VERSION 5.7 ;
  NOWIREEXTENSIONATPIN ON ;
  DIVIDERCHAR "/" ;
  BUSBITCHARS "[]" ;
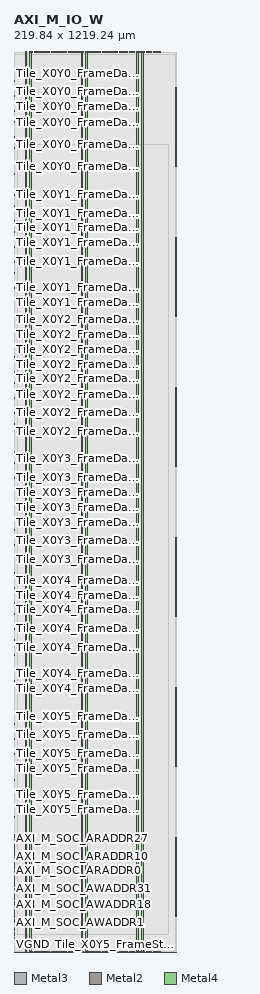
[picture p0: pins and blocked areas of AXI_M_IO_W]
MACRO AXI_M_IO_W
  CLASS BLOCK ;
  FOREIGN AXI_M_IO_W ;
  ORIGIN 0.000 0.000 ;
  SIZE 219.840 BY 1219.240 ;
  PIN AXI_M_SOC_ARADDR0
    DIRECTION OUTPUT ;
    USE SIGNAL ;
    ANTENNADIFFAREA 0.632400 ;
    PORT
      LAYER Metal3 ;
        RECT 0.000 120.340 0.400 120.740 ;
    END
  END AXI_M_SOC_ARADDR0
  PIN AXI_M_SOC_ARADDR1
    DIRECTION OUTPUT ;
    USE SIGNAL ;
    ANTENNADIFFAREA 0.632400 ;
    PORT
      LAYER Metal3 ;
        RECT 0.000 121.180 0.400 121.580 ;
    END
  END AXI_M_SOC_ARADDR1
  PIN AXI_M_SOC_ARADDR10
    DIRECTION OUTPUT ;
    USE SIGNAL ;
    ANTENNADIFFAREA 0.632400 ;
    PORT
      LAYER Metal3 ;
        RECT 0.000 128.740 0.400 129.140 ;
    END
  END AXI_M_SOC_ARADDR10
  PIN AXI_M_SOC_ARADDR11
    DIRECTION OUTPUT ;
    USE SIGNAL ;
    ANTENNADIFFAREA 0.632400 ;
    PORT
      LAYER Metal3 ;
        RECT 0.000 129.580 0.400 129.980 ;
    END
  END AXI_M_SOC_ARADDR11
  PIN AXI_M_SOC_ARADDR12
    DIRECTION OUTPUT ;
    USE SIGNAL ;
    ANTENNADIFFAREA 0.632400 ;
    PORT
      LAYER Metal3 ;
        RECT 0.000 130.420 0.400 130.820 ;
    END
  END AXI_M_SOC_ARADDR12
  PIN AXI_M_SOC_ARADDR13
    DIRECTION OUTPUT ;
    USE SIGNAL ;
    ANTENNADIFFAREA 0.632400 ;
    PORT
      LAYER Metal3 ;
        RECT 0.000 131.260 0.400 131.660 ;
    END
  END AXI_M_SOC_ARADDR13
  PIN AXI_M_SOC_ARADDR14
    DIRECTION OUTPUT ;
    USE SIGNAL ;
    ANTENNADIFFAREA 0.632400 ;
    PORT
      LAYER Metal3 ;
        RECT 0.000 132.100 0.400 132.500 ;
    END
  END AXI_M_SOC_ARADDR14
  PIN AXI_M_SOC_ARADDR15
    DIRECTION OUTPUT ;
    USE SIGNAL ;
    ANTENNADIFFAREA 0.632400 ;
    PORT
      LAYER Metal3 ;
        RECT 0.000 132.940 0.400 133.340 ;
    END
  END AXI_M_SOC_ARADDR15
  PIN AXI_M_SOC_ARADDR16
    DIRECTION OUTPUT ;
    USE SIGNAL ;
    ANTENNADIFFAREA 0.632400 ;
    PORT
      LAYER Metal3 ;
        RECT 0.000 133.780 0.400 134.180 ;
    END
  END AXI_M_SOC_ARADDR16
  PIN AXI_M_SOC_ARADDR17
    DIRECTION OUTPUT ;
    USE SIGNAL ;
    ANTENNADIFFAREA 0.632400 ;
    PORT
      LAYER Metal3 ;
        RECT 0.000 134.620 0.400 135.020 ;
    END
  END AXI_M_SOC_ARADDR17
  PIN AXI_M_SOC_ARADDR18
    DIRECTION OUTPUT ;
    USE SIGNAL ;
    ANTENNADIFFAREA 0.632400 ;
    PORT
      LAYER Metal3 ;
        RECT 0.000 135.460 0.400 135.860 ;
    END
  END AXI_M_SOC_ARADDR18
  PIN AXI_M_SOC_ARADDR19
    DIRECTION OUTPUT ;
    USE SIGNAL ;
    ANTENNADIFFAREA 0.632400 ;
    PORT
      LAYER Metal3 ;
        RECT 0.000 136.300 0.400 136.700 ;
    END
  END AXI_M_SOC_ARADDR19
  PIN AXI_M_SOC_ARADDR2
    DIRECTION OUTPUT ;
    USE SIGNAL ;
    ANTENNADIFFAREA 0.632400 ;
    PORT
      LAYER Metal3 ;
        RECT 0.000 122.020 0.400 122.420 ;
    END
  END AXI_M_SOC_ARADDR2
  PIN AXI_M_SOC_ARADDR20
    DIRECTION OUTPUT ;
    USE SIGNAL ;
    ANTENNADIFFAREA 0.632400 ;
    PORT
      LAYER Metal3 ;
        RECT 0.000 137.140 0.400 137.540 ;
    END
  END AXI_M_SOC_ARADDR20
  PIN AXI_M_SOC_ARADDR21
    DIRECTION OUTPUT ;
    USE SIGNAL ;
    ANTENNADIFFAREA 0.632400 ;
    PORT
      LAYER Metal3 ;
        RECT 0.000 137.980 0.400 138.380 ;
    END
  END AXI_M_SOC_ARADDR21
  PIN AXI_M_SOC_ARADDR22
    DIRECTION OUTPUT ;
    USE SIGNAL ;
    ANTENNADIFFAREA 0.632400 ;
    PORT
      LAYER Metal3 ;
        RECT 0.000 138.820 0.400 139.220 ;
    END
  END AXI_M_SOC_ARADDR22
  PIN AXI_M_SOC_ARADDR23
    DIRECTION OUTPUT ;
    USE SIGNAL ;
    ANTENNADIFFAREA 0.632400 ;
    PORT
      LAYER Metal3 ;
        RECT 0.000 139.660 0.400 140.060 ;
    END
  END AXI_M_SOC_ARADDR23
  PIN AXI_M_SOC_ARADDR24
    DIRECTION OUTPUT ;
    USE SIGNAL ;
    ANTENNADIFFAREA 0.632400 ;
    PORT
      LAYER Metal3 ;
        RECT 0.000 140.500 0.400 140.900 ;
    END
  END AXI_M_SOC_ARADDR24
  PIN AXI_M_SOC_ARADDR25
    DIRECTION OUTPUT ;
    USE SIGNAL ;
    ANTENNADIFFAREA 0.632400 ;
    PORT
      LAYER Metal3 ;
        RECT 0.000 141.340 0.400 141.740 ;
    END
  END AXI_M_SOC_ARADDR25
  PIN AXI_M_SOC_ARADDR26
    DIRECTION OUTPUT ;
    USE SIGNAL ;
    ANTENNADIFFAREA 0.632400 ;
    PORT
      LAYER Metal3 ;
        RECT 0.000 142.180 0.400 142.580 ;
    END
  END AXI_M_SOC_ARADDR26
  PIN AXI_M_SOC_ARADDR27
    DIRECTION OUTPUT ;
    USE SIGNAL ;
    ANTENNADIFFAREA 0.632400 ;
    PORT
      LAYER Metal3 ;
        RECT 0.000 143.020 0.400 143.420 ;
    END
  END AXI_M_SOC_ARADDR27
  PIN AXI_M_SOC_ARADDR28
    DIRECTION OUTPUT ;
    USE SIGNAL ;
    ANTENNADIFFAREA 0.632400 ;
    PORT
      LAYER Metal3 ;
        RECT 0.000 143.860 0.400 144.260 ;
    END
  END AXI_M_SOC_ARADDR28
  PIN AXI_M_SOC_ARADDR29
    DIRECTION OUTPUT ;
    USE SIGNAL ;
    ANTENNADIFFAREA 0.632400 ;
    PORT
      LAYER Metal3 ;
        RECT 0.000 144.700 0.400 145.100 ;
    END
  END AXI_M_SOC_ARADDR29
  PIN AXI_M_SOC_ARADDR3
    DIRECTION OUTPUT ;
    USE SIGNAL ;
    ANTENNADIFFAREA 0.632400 ;
    PORT
      LAYER Metal3 ;
        RECT 0.000 122.860 0.400 123.260 ;
    END
  END AXI_M_SOC_ARADDR3
  PIN AXI_M_SOC_ARADDR30
    DIRECTION OUTPUT ;
    USE SIGNAL ;
    ANTENNADIFFAREA 0.632400 ;
    PORT
      LAYER Metal3 ;
        RECT 0.000 145.540 0.400 145.940 ;
    END
  END AXI_M_SOC_ARADDR30
  PIN AXI_M_SOC_ARADDR31
    DIRECTION OUTPUT ;
    USE SIGNAL ;
    ANTENNADIFFAREA 0.632400 ;
    PORT
      LAYER Metal3 ;
        RECT 0.000 146.380 0.400 146.780 ;
    END
  END AXI_M_SOC_ARADDR31
  PIN AXI_M_SOC_ARADDR4
    DIRECTION OUTPUT ;
    USE SIGNAL ;
    ANTENNADIFFAREA 0.632400 ;
    PORT
      LAYER Metal3 ;
        RECT 0.000 123.700 0.400 124.100 ;
    END
  END AXI_M_SOC_ARADDR4
  PIN AXI_M_SOC_ARADDR5
    DIRECTION OUTPUT ;
    USE SIGNAL ;
    ANTENNADIFFAREA 0.632400 ;
    PORT
      LAYER Metal3 ;
        RECT 0.000 124.540 0.400 124.940 ;
    END
  END AXI_M_SOC_ARADDR5
  PIN AXI_M_SOC_ARADDR6
    DIRECTION OUTPUT ;
    USE SIGNAL ;
    ANTENNADIFFAREA 0.632400 ;
    PORT
      LAYER Metal3 ;
        RECT 0.000 125.380 0.400 125.780 ;
    END
  END AXI_M_SOC_ARADDR6
  PIN AXI_M_SOC_ARADDR7
    DIRECTION OUTPUT ;
    USE SIGNAL ;
    ANTENNADIFFAREA 0.632400 ;
    PORT
      LAYER Metal3 ;
        RECT 0.000 126.220 0.400 126.620 ;
    END
  END AXI_M_SOC_ARADDR7
  PIN AXI_M_SOC_ARADDR8
    DIRECTION OUTPUT ;
    USE SIGNAL ;
    ANTENNADIFFAREA 0.632400 ;
    PORT
      LAYER Metal3 ;
        RECT 0.000 127.060 0.400 127.460 ;
    END
  END AXI_M_SOC_ARADDR8
  PIN AXI_M_SOC_ARADDR9
    DIRECTION OUTPUT ;
    USE SIGNAL ;
    ANTENNADIFFAREA 0.632400 ;
    PORT
      LAYER Metal3 ;
        RECT 0.000 127.900 0.400 128.300 ;
    END
  END AXI_M_SOC_ARADDR9
  PIN AXI_M_SOC_ARBURST0
    DIRECTION OUTPUT ;
    USE SIGNAL ;
    ANTENNADIFFAREA 0.649200 ;
    PORT
      LAYER Metal3 ;
        RECT 0.000 156.460 0.400 156.860 ;
    END
  END AXI_M_SOC_ARBURST0
  PIN AXI_M_SOC_ARBURST1
    DIRECTION OUTPUT ;
    USE SIGNAL ;
    ANTENNADIFFAREA 0.662000 ;
    PORT
      LAYER Metal3 ;
        RECT 0.000 157.300 0.400 157.700 ;
    END
  END AXI_M_SOC_ARBURST1
  PIN AXI_M_SOC_ARLEN0
    DIRECTION OUTPUT ;
    USE SIGNAL ;
    ANTENNADIFFAREA 0.662000 ;
    PORT
      LAYER Metal3 ;
        RECT 0.000 147.220 0.400 147.620 ;
    END
  END AXI_M_SOC_ARLEN0
  PIN AXI_M_SOC_ARLEN1
    DIRECTION OUTPUT ;
    USE SIGNAL ;
    ANTENNADIFFAREA 1.135600 ;
    PORT
      LAYER Metal3 ;
        RECT 0.000 148.060 0.400 148.460 ;
    END
  END AXI_M_SOC_ARLEN1
  PIN AXI_M_SOC_ARLEN2
    DIRECTION OUTPUT ;
    USE SIGNAL ;
    ANTENNADIFFAREA 0.662000 ;
    PORT
      LAYER Metal3 ;
        RECT 0.000 148.900 0.400 149.300 ;
    END
  END AXI_M_SOC_ARLEN2
  PIN AXI_M_SOC_ARLEN3
    DIRECTION OUTPUT ;
    USE SIGNAL ;
    ANTENNADIFFAREA 1.135600 ;
    PORT
      LAYER Metal3 ;
        RECT 0.000 149.740 0.400 150.140 ;
    END
  END AXI_M_SOC_ARLEN3
  PIN AXI_M_SOC_ARLEN4
    DIRECTION OUTPUT ;
    USE SIGNAL ;
    ANTENNADIFFAREA 1.135600 ;
    PORT
      LAYER Metal3 ;
        RECT 0.000 150.580 0.400 150.980 ;
    END
  END AXI_M_SOC_ARLEN4
  PIN AXI_M_SOC_ARLEN5
    DIRECTION OUTPUT ;
    USE SIGNAL ;
    ANTENNADIFFAREA 1.135600 ;
    PORT
      LAYER Metal3 ;
        RECT 0.000 151.420 0.400 151.820 ;
    END
  END AXI_M_SOC_ARLEN5
  PIN AXI_M_SOC_ARLEN6
    DIRECTION OUTPUT ;
    USE SIGNAL ;
    ANTENNADIFFAREA 1.135600 ;
    PORT
      LAYER Metal3 ;
        RECT 0.000 152.260 0.400 152.660 ;
    END
  END AXI_M_SOC_ARLEN6
  PIN AXI_M_SOC_ARLEN7
    DIRECTION OUTPUT ;
    USE SIGNAL ;
    ANTENNADIFFAREA 1.135600 ;
    PORT
      LAYER Metal3 ;
        RECT 0.000 153.100 0.400 153.500 ;
    END
  END AXI_M_SOC_ARLEN7
  PIN AXI_M_SOC_ARREADY
    DIRECTION INPUT ;
    USE SIGNAL ;
    ANTENNAGATEAREA 1.279200 ;
    PORT
      LAYER Metal3 ;
        RECT 0.000 17.860 0.400 18.260 ;
    END
  END AXI_M_SOC_ARREADY
  PIN AXI_M_SOC_ARSIZE0
    DIRECTION OUTPUT ;
    USE SIGNAL ;
    ANTENNADIFFAREA 0.662000 ;
    PORT
      LAYER Metal3 ;
        RECT 0.000 153.940 0.400 154.340 ;
    END
  END AXI_M_SOC_ARSIZE0
  PIN AXI_M_SOC_ARSIZE1
    DIRECTION OUTPUT ;
    USE SIGNAL ;
    ANTENNADIFFAREA 0.649200 ;
    PORT
      LAYER Metal3 ;
        RECT 0.000 154.780 0.400 155.180 ;
    END
  END AXI_M_SOC_ARSIZE1
  PIN AXI_M_SOC_ARSIZE2
    DIRECTION OUTPUT ;
    USE SIGNAL ;
    ANTENNADIFFAREA 0.662000 ;
    PORT
      LAYER Metal3 ;
        RECT 0.000 155.620 0.400 156.020 ;
    END
  END AXI_M_SOC_ARSIZE2
  PIN AXI_M_SOC_ARVALID
    DIRECTION OUTPUT ;
    USE SIGNAL ;
    ANTENNADIFFAREA 0.632400 ;
    PORT
      LAYER Metal3 ;
        RECT 0.000 158.140 0.400 158.540 ;
    END
  END AXI_M_SOC_ARVALID
  PIN AXI_M_SOC_AWADDR0
    DIRECTION OUTPUT ;
    USE SIGNAL ;
    ANTENNADIFFAREA 0.632400 ;
    PORT
      LAYER Metal3 ;
        RECT 0.000 48.940 0.400 49.340 ;
    END
  END AXI_M_SOC_AWADDR0
  PIN AXI_M_SOC_AWADDR1
    DIRECTION OUTPUT ;
    USE SIGNAL ;
    ANTENNADIFFAREA 0.632400 ;
    PORT
      LAYER Metal3 ;
        RECT 0.000 49.780 0.400 50.180 ;
    END
  END AXI_M_SOC_AWADDR1
  PIN AXI_M_SOC_AWADDR10
    DIRECTION OUTPUT ;
    USE SIGNAL ;
    ANTENNADIFFAREA 0.632400 ;
    PORT
      LAYER Metal3 ;
        RECT 0.000 57.340 0.400 57.740 ;
    END
  END AXI_M_SOC_AWADDR10
  PIN AXI_M_SOC_AWADDR11
    DIRECTION OUTPUT ;
    USE SIGNAL ;
    ANTENNADIFFAREA 0.632400 ;
    PORT
      LAYER Metal3 ;
        RECT 0.000 58.180 0.400 58.580 ;
    END
  END AXI_M_SOC_AWADDR11
  PIN AXI_M_SOC_AWADDR12
    DIRECTION OUTPUT ;
    USE SIGNAL ;
    ANTENNADIFFAREA 0.632400 ;
    PORT
      LAYER Metal3 ;
        RECT 0.000 59.020 0.400 59.420 ;
    END
  END AXI_M_SOC_AWADDR12
  PIN AXI_M_SOC_AWADDR13
    DIRECTION OUTPUT ;
    USE SIGNAL ;
    ANTENNADIFFAREA 0.632400 ;
    PORT
      LAYER Metal3 ;
        RECT 0.000 59.860 0.400 60.260 ;
    END
  END AXI_M_SOC_AWADDR13
  PIN AXI_M_SOC_AWADDR14
    DIRECTION OUTPUT ;
    USE SIGNAL ;
    ANTENNADIFFAREA 0.632400 ;
    PORT
      LAYER Metal3 ;
        RECT 0.000 60.700 0.400 61.100 ;
    END
  END AXI_M_SOC_AWADDR14
  PIN AXI_M_SOC_AWADDR15
    DIRECTION OUTPUT ;
    USE SIGNAL ;
    ANTENNADIFFAREA 0.632400 ;
    PORT
      LAYER Metal3 ;
        RECT 0.000 61.540 0.400 61.940 ;
    END
  END AXI_M_SOC_AWADDR15
  PIN AXI_M_SOC_AWADDR16
    DIRECTION OUTPUT ;
    USE SIGNAL ;
    ANTENNADIFFAREA 0.632400 ;
    PORT
      LAYER Metal3 ;
        RECT 0.000 62.380 0.400 62.780 ;
    END
  END AXI_M_SOC_AWADDR16
  PIN AXI_M_SOC_AWADDR17
    DIRECTION OUTPUT ;
    USE SIGNAL ;
    ANTENNADIFFAREA 0.632400 ;
    PORT
      LAYER Metal3 ;
        RECT 0.000 63.220 0.400 63.620 ;
    END
  END AXI_M_SOC_AWADDR17
  PIN AXI_M_SOC_AWADDR18
    DIRECTION OUTPUT ;
    USE SIGNAL ;
    ANTENNADIFFAREA 0.632400 ;
    PORT
      LAYER Metal3 ;
        RECT 0.000 64.060 0.400 64.460 ;
    END
  END AXI_M_SOC_AWADDR18
  PIN AXI_M_SOC_AWADDR19
    DIRECTION OUTPUT ;
    USE SIGNAL ;
    ANTENNADIFFAREA 0.632400 ;
    PORT
      LAYER Metal3 ;
        RECT 0.000 64.900 0.400 65.300 ;
    END
  END AXI_M_SOC_AWADDR19
  PIN AXI_M_SOC_AWADDR2
    DIRECTION OUTPUT ;
    USE SIGNAL ;
    ANTENNADIFFAREA 0.632400 ;
    PORT
      LAYER Metal3 ;
        RECT 0.000 50.620 0.400 51.020 ;
    END
  END AXI_M_SOC_AWADDR2
  PIN AXI_M_SOC_AWADDR20
    DIRECTION OUTPUT ;
    USE SIGNAL ;
    ANTENNADIFFAREA 0.632400 ;
    PORT
      LAYER Metal3 ;
        RECT 0.000 65.740 0.400 66.140 ;
    END
  END AXI_M_SOC_AWADDR20
  PIN AXI_M_SOC_AWADDR21
    DIRECTION OUTPUT ;
    USE SIGNAL ;
    ANTENNADIFFAREA 0.632400 ;
    PORT
      LAYER Metal3 ;
        RECT 0.000 66.580 0.400 66.980 ;
    END
  END AXI_M_SOC_AWADDR21
  PIN AXI_M_SOC_AWADDR22
    DIRECTION OUTPUT ;
    USE SIGNAL ;
    ANTENNADIFFAREA 0.632400 ;
    PORT
      LAYER Metal3 ;
        RECT 0.000 67.420 0.400 67.820 ;
    END
  END AXI_M_SOC_AWADDR22
  PIN AXI_M_SOC_AWADDR23
    DIRECTION OUTPUT ;
    USE SIGNAL ;
    ANTENNADIFFAREA 0.632400 ;
    PORT
      LAYER Metal3 ;
        RECT 0.000 68.260 0.400 68.660 ;
    END
  END AXI_M_SOC_AWADDR23
  PIN AXI_M_SOC_AWADDR24
    DIRECTION OUTPUT ;
    USE SIGNAL ;
    ANTENNADIFFAREA 0.632400 ;
    PORT
      LAYER Metal3 ;
        RECT 0.000 69.100 0.400 69.500 ;
    END
  END AXI_M_SOC_AWADDR24
  PIN AXI_M_SOC_AWADDR25
    DIRECTION OUTPUT ;
    USE SIGNAL ;
    ANTENNADIFFAREA 0.632400 ;
    PORT
      LAYER Metal3 ;
        RECT 0.000 69.940 0.400 70.340 ;
    END
  END AXI_M_SOC_AWADDR25
  PIN AXI_M_SOC_AWADDR26
    DIRECTION OUTPUT ;
    USE SIGNAL ;
    ANTENNADIFFAREA 0.632400 ;
    PORT
      LAYER Metal3 ;
        RECT 0.000 70.780 0.400 71.180 ;
    END
  END AXI_M_SOC_AWADDR26
  PIN AXI_M_SOC_AWADDR27
    DIRECTION OUTPUT ;
    USE SIGNAL ;
    ANTENNADIFFAREA 0.632400 ;
    PORT
      LAYER Metal3 ;
        RECT 0.000 71.620 0.400 72.020 ;
    END
  END AXI_M_SOC_AWADDR27
  PIN AXI_M_SOC_AWADDR28
    DIRECTION OUTPUT ;
    USE SIGNAL ;
    ANTENNADIFFAREA 0.632400 ;
    PORT
      LAYER Metal3 ;
        RECT 0.000 72.460 0.400 72.860 ;
    END
  END AXI_M_SOC_AWADDR28
  PIN AXI_M_SOC_AWADDR29
    DIRECTION OUTPUT ;
    USE SIGNAL ;
    ANTENNADIFFAREA 0.632400 ;
    PORT
      LAYER Metal3 ;
        RECT 0.000 73.300 0.400 73.700 ;
    END
  END AXI_M_SOC_AWADDR29
  PIN AXI_M_SOC_AWADDR3
    DIRECTION OUTPUT ;
    USE SIGNAL ;
    ANTENNADIFFAREA 0.632400 ;
    PORT
      LAYER Metal3 ;
        RECT 0.000 51.460 0.400 51.860 ;
    END
  END AXI_M_SOC_AWADDR3
  PIN AXI_M_SOC_AWADDR30
    DIRECTION OUTPUT ;
    USE SIGNAL ;
    ANTENNADIFFAREA 0.632400 ;
    PORT
      LAYER Metal3 ;
        RECT 0.000 74.140 0.400 74.540 ;
    END
  END AXI_M_SOC_AWADDR30
  PIN AXI_M_SOC_AWADDR31
    DIRECTION OUTPUT ;
    USE SIGNAL ;
    ANTENNADIFFAREA 0.632400 ;
    PORT
      LAYER Metal3 ;
        RECT 0.000 74.980 0.400 75.380 ;
    END
  END AXI_M_SOC_AWADDR31
  PIN AXI_M_SOC_AWADDR4
    DIRECTION OUTPUT ;
    USE SIGNAL ;
    ANTENNADIFFAREA 0.632400 ;
    PORT
      LAYER Metal3 ;
        RECT 0.000 52.300 0.400 52.700 ;
    END
  END AXI_M_SOC_AWADDR4
  PIN AXI_M_SOC_AWADDR5
    DIRECTION OUTPUT ;
    USE SIGNAL ;
    ANTENNADIFFAREA 0.632400 ;
    PORT
      LAYER Metal3 ;
        RECT 0.000 53.140 0.400 53.540 ;
    END
  END AXI_M_SOC_AWADDR5
  PIN AXI_M_SOC_AWADDR6
    DIRECTION OUTPUT ;
    USE SIGNAL ;
    ANTENNADIFFAREA 0.632400 ;
    PORT
      LAYER Metal3 ;
        RECT 0.000 53.980 0.400 54.380 ;
    END
  END AXI_M_SOC_AWADDR6
  PIN AXI_M_SOC_AWADDR7
    DIRECTION OUTPUT ;
    USE SIGNAL ;
    ANTENNADIFFAREA 0.632400 ;
    PORT
      LAYER Metal3 ;
        RECT 0.000 54.820 0.400 55.220 ;
    END
  END AXI_M_SOC_AWADDR7
  PIN AXI_M_SOC_AWADDR8
    DIRECTION OUTPUT ;
    USE SIGNAL ;
    ANTENNADIFFAREA 0.632400 ;
    PORT
      LAYER Metal3 ;
        RECT 0.000 55.660 0.400 56.060 ;
    END
  END AXI_M_SOC_AWADDR8
  PIN AXI_M_SOC_AWADDR9
    DIRECTION OUTPUT ;
    USE SIGNAL ;
    ANTENNADIFFAREA 0.632400 ;
    PORT
      LAYER Metal3 ;
        RECT 0.000 56.500 0.400 56.900 ;
    END
  END AXI_M_SOC_AWADDR9
  PIN AXI_M_SOC_AWBURST0
    DIRECTION OUTPUT ;
    USE SIGNAL ;
    ANTENNADIFFAREA 0.649200 ;
    PORT
      LAYER Metal3 ;
        RECT 0.000 85.060 0.400 85.460 ;
    END
  END AXI_M_SOC_AWBURST0
  PIN AXI_M_SOC_AWBURST1
    DIRECTION OUTPUT ;
    USE SIGNAL ;
    ANTENNADIFFAREA 0.662000 ;
    PORT
      LAYER Metal3 ;
        RECT 0.000 85.900 0.400 86.300 ;
    END
  END AXI_M_SOC_AWBURST1
  PIN AXI_M_SOC_AWLEN0
    DIRECTION OUTPUT ;
    USE SIGNAL ;
    ANTENNADIFFAREA 0.662000 ;
    PORT
      LAYER Metal3 ;
        RECT 0.000 75.820 0.400 76.220 ;
    END
  END AXI_M_SOC_AWLEN0
  PIN AXI_M_SOC_AWLEN1
    DIRECTION OUTPUT ;
    USE SIGNAL ;
    ANTENNADIFFAREA 0.662000 ;
    PORT
      LAYER Metal3 ;
        RECT 0.000 76.660 0.400 77.060 ;
    END
  END AXI_M_SOC_AWLEN1
  PIN AXI_M_SOC_AWLEN2
    DIRECTION OUTPUT ;
    USE SIGNAL ;
    ANTENNADIFFAREA 0.662000 ;
    PORT
      LAYER Metal3 ;
        RECT 0.000 77.500 0.400 77.900 ;
    END
  END AXI_M_SOC_AWLEN2
  PIN AXI_M_SOC_AWLEN3
    DIRECTION OUTPUT ;
    USE SIGNAL ;
    ANTENNADIFFAREA 0.662000 ;
    PORT
      LAYER Metal3 ;
        RECT 0.000 78.340 0.400 78.740 ;
    END
  END AXI_M_SOC_AWLEN3
  PIN AXI_M_SOC_AWLEN4
    DIRECTION OUTPUT ;
    USE SIGNAL ;
    ANTENNADIFFAREA 0.662000 ;
    PORT
      LAYER Metal3 ;
        RECT 0.000 79.180 0.400 79.580 ;
    END
  END AXI_M_SOC_AWLEN4
  PIN AXI_M_SOC_AWLEN5
    DIRECTION OUTPUT ;
    USE SIGNAL ;
    ANTENNADIFFAREA 0.662000 ;
    PORT
      LAYER Metal3 ;
        RECT 0.000 80.020 0.400 80.420 ;
    END
  END AXI_M_SOC_AWLEN5
  PIN AXI_M_SOC_AWLEN6
    DIRECTION OUTPUT ;
    USE SIGNAL ;
    ANTENNADIFFAREA 0.662000 ;
    PORT
      LAYER Metal3 ;
        RECT 0.000 80.860 0.400 81.260 ;
    END
  END AXI_M_SOC_AWLEN6
  PIN AXI_M_SOC_AWLEN7
    DIRECTION OUTPUT ;
    USE SIGNAL ;
    ANTENNADIFFAREA 0.662000 ;
    PORT
      LAYER Metal3 ;
        RECT 0.000 81.700 0.400 82.100 ;
    END
  END AXI_M_SOC_AWLEN7
  PIN AXI_M_SOC_AWREADY
    DIRECTION INPUT ;
    USE SIGNAL ;
    ANTENNAGATEAREA 1.279200 ;
    PORT
      LAYER Metal3 ;
        RECT 0.000 13.660 0.400 14.060 ;
    END
  END AXI_M_SOC_AWREADY
  PIN AXI_M_SOC_AWSIZE0
    DIRECTION OUTPUT ;
    USE SIGNAL ;
    ANTENNADIFFAREA 0.662000 ;
    PORT
      LAYER Metal3 ;
        RECT 0.000 82.540 0.400 82.940 ;
    END
  END AXI_M_SOC_AWSIZE0
  PIN AXI_M_SOC_AWSIZE1
    DIRECTION OUTPUT ;
    USE SIGNAL ;
    ANTENNADIFFAREA 0.649200 ;
    PORT
      LAYER Metal3 ;
        RECT 0.000 83.380 0.400 83.780 ;
    END
  END AXI_M_SOC_AWSIZE1
  PIN AXI_M_SOC_AWSIZE2
    DIRECTION OUTPUT ;
    USE SIGNAL ;
    ANTENNADIFFAREA 0.662000 ;
    PORT
      LAYER Metal3 ;
        RECT 0.000 84.220 0.400 84.620 ;
    END
  END AXI_M_SOC_AWSIZE2
  PIN AXI_M_SOC_AWVALID
    DIRECTION OUTPUT ;
    USE SIGNAL ;
    ANTENNAGATEAREA 0.213200 ;
    ANTENNADIFFAREA 0.632400 ;
    PORT
      LAYER Metal3 ;
        RECT 0.000 86.740 0.400 87.140 ;
    END
  END AXI_M_SOC_AWVALID
  PIN AXI_M_SOC_BREADY
    DIRECTION OUTPUT ;
    USE SIGNAL ;
    ANTENNADIFFAREA 0.632400 ;
    PORT
      LAYER Metal3 ;
        RECT 0.000 119.500 0.400 119.900 ;
    END
  END AXI_M_SOC_BREADY
  PIN AXI_M_SOC_BRESP0
    DIRECTION INPUT ;
    USE SIGNAL ;
    ANTENNAGATEAREA 1.279200 ;
    ANTENNADIFFAREA 12.092400 ;
    PORT
      LAYER Metal3 ;
        RECT 0.000 15.340 0.400 15.740 ;
    END
  END AXI_M_SOC_BRESP0
  PIN AXI_M_SOC_BRESP1
    DIRECTION INPUT ;
    USE SIGNAL ;
    ANTENNAGATEAREA 1.279200 ;
    PORT
      LAYER Metal3 ;
        RECT 0.000 16.180 0.400 16.580 ;
    END
  END AXI_M_SOC_BRESP1
  PIN AXI_M_SOC_BVALID
    DIRECTION INPUT ;
    USE SIGNAL ;
    ANTENNAGATEAREA 1.279200 ;
    ANTENNADIFFAREA 36.277199 ;
    PORT
      LAYER Metal3 ;
        RECT 0.000 17.020 0.400 17.420 ;
    END
  END AXI_M_SOC_BVALID
  PIN AXI_M_SOC_RDATA0
    DIRECTION INPUT ;
    USE SIGNAL ;
    ANTENNAGATEAREA 1.279200 ;
    PORT
      LAYER Metal3 ;
        RECT 0.000 18.700 0.400 19.100 ;
    END
  END AXI_M_SOC_RDATA0
  PIN AXI_M_SOC_RDATA1
    DIRECTION INPUT ;
    USE SIGNAL ;
    ANTENNAGATEAREA 1.279200 ;
    PORT
      LAYER Metal3 ;
        RECT 0.000 19.540 0.400 19.940 ;
    END
  END AXI_M_SOC_RDATA1
  PIN AXI_M_SOC_RDATA10
    DIRECTION INPUT ;
    USE SIGNAL ;
    ANTENNAGATEAREA 1.279200 ;
    ANTENNADIFFAREA 72.554398 ;
    PORT
      LAYER Metal3 ;
        RECT 0.000 27.100 0.400 27.500 ;
    END
  END AXI_M_SOC_RDATA10
  PIN AXI_M_SOC_RDATA11
    DIRECTION INPUT ;
    USE SIGNAL ;
    ANTENNAGATEAREA 1.279200 ;
    PORT
      LAYER Metal3 ;
        RECT 0.000 27.940 0.400 28.340 ;
    END
  END AXI_M_SOC_RDATA11
  PIN AXI_M_SOC_RDATA12
    DIRECTION INPUT ;
    USE SIGNAL ;
    ANTENNAGATEAREA 1.279200 ;
    PORT
      LAYER Metal3 ;
        RECT 0.000 28.780 0.400 29.180 ;
    END
  END AXI_M_SOC_RDATA12
  PIN AXI_M_SOC_RDATA13
    DIRECTION INPUT ;
    USE SIGNAL ;
    ANTENNAGATEAREA 1.279200 ;
    ANTENNADIFFAREA 12.092400 ;
    PORT
      LAYER Metal3 ;
        RECT 0.000 29.620 0.400 30.020 ;
    END
  END AXI_M_SOC_RDATA13
  PIN AXI_M_SOC_RDATA14
    DIRECTION INPUT ;
    USE SIGNAL ;
    ANTENNAGATEAREA 1.279200 ;
    PORT
      LAYER Metal3 ;
        RECT 0.000 30.460 0.400 30.860 ;
    END
  END AXI_M_SOC_RDATA14
  PIN AXI_M_SOC_RDATA15
    DIRECTION INPUT ;
    USE SIGNAL ;
    ANTENNAGATEAREA 1.279200 ;
    ANTENNADIFFAREA 12.092400 ;
    PORT
      LAYER Metal3 ;
        RECT 0.000 31.300 0.400 31.700 ;
    END
  END AXI_M_SOC_RDATA15
  PIN AXI_M_SOC_RDATA16
    DIRECTION INPUT ;
    USE SIGNAL ;
    ANTENNAGATEAREA 1.279200 ;
    PORT
      LAYER Metal3 ;
        RECT 0.000 32.140 0.400 32.540 ;
    END
  END AXI_M_SOC_RDATA16
  PIN AXI_M_SOC_RDATA17
    DIRECTION INPUT ;
    USE SIGNAL ;
    ANTENNAGATEAREA 1.279200 ;
    PORT
      LAYER Metal3 ;
        RECT 0.000 32.980 0.400 33.380 ;
    END
  END AXI_M_SOC_RDATA17
  PIN AXI_M_SOC_RDATA18
    DIRECTION INPUT ;
    USE SIGNAL ;
    ANTENNAGATEAREA 1.279200 ;
    ANTENNADIFFAREA 12.092400 ;
    PORT
      LAYER Metal3 ;
        RECT 0.000 33.820 0.400 34.220 ;
    END
  END AXI_M_SOC_RDATA18
  PIN AXI_M_SOC_RDATA19
    DIRECTION INPUT ;
    USE SIGNAL ;
    ANTENNAGATEAREA 1.279200 ;
    PORT
      LAYER Metal3 ;
        RECT 0.000 34.660 0.400 35.060 ;
    END
  END AXI_M_SOC_RDATA19
  PIN AXI_M_SOC_RDATA2
    DIRECTION INPUT ;
    USE SIGNAL ;
    ANTENNAGATEAREA 1.279200 ;
    PORT
      LAYER Metal3 ;
        RECT 0.000 20.380 0.400 20.780 ;
    END
  END AXI_M_SOC_RDATA2
  PIN AXI_M_SOC_RDATA20
    DIRECTION INPUT ;
    USE SIGNAL ;
    ANTENNAGATEAREA 1.279200 ;
    PORT
      LAYER Metal3 ;
        RECT 0.000 35.500 0.400 35.900 ;
    END
  END AXI_M_SOC_RDATA20
  PIN AXI_M_SOC_RDATA21
    DIRECTION INPUT ;
    USE SIGNAL ;
    ANTENNAGATEAREA 1.279200 ;
    PORT
      LAYER Metal3 ;
        RECT 0.000 36.340 0.400 36.740 ;
    END
  END AXI_M_SOC_RDATA21
  PIN AXI_M_SOC_RDATA22
    DIRECTION INPUT ;
    USE SIGNAL ;
    ANTENNAGATEAREA 1.279200 ;
    ANTENNADIFFAREA 12.092400 ;
    PORT
      LAYER Metal3 ;
        RECT 0.000 37.180 0.400 37.580 ;
    END
  END AXI_M_SOC_RDATA22
  PIN AXI_M_SOC_RDATA23
    DIRECTION INPUT ;
    USE SIGNAL ;
    ANTENNAGATEAREA 1.279200 ;
    ANTENNADIFFAREA 24.184799 ;
    PORT
      LAYER Metal3 ;
        RECT 0.000 38.020 0.400 38.420 ;
    END
  END AXI_M_SOC_RDATA23
  PIN AXI_M_SOC_RDATA24
    DIRECTION INPUT ;
    USE SIGNAL ;
    ANTENNAGATEAREA 1.279200 ;
    ANTENNADIFFAREA 12.092400 ;
    PORT
      LAYER Metal3 ;
        RECT 0.000 38.860 0.400 39.260 ;
    END
  END AXI_M_SOC_RDATA24
  PIN AXI_M_SOC_RDATA25
    DIRECTION INPUT ;
    USE SIGNAL ;
    ANTENNAGATEAREA 1.279200 ;
    PORT
      LAYER Metal3 ;
        RECT 0.000 39.700 0.400 40.100 ;
    END
  END AXI_M_SOC_RDATA25
  PIN AXI_M_SOC_RDATA26
    DIRECTION INPUT ;
    USE SIGNAL ;
    ANTENNAGATEAREA 1.279200 ;
    PORT
      LAYER Metal3 ;
        RECT 0.000 40.540 0.400 40.940 ;
    END
  END AXI_M_SOC_RDATA26
  PIN AXI_M_SOC_RDATA27
    DIRECTION INPUT ;
    USE SIGNAL ;
    ANTENNAGATEAREA 1.279200 ;
    PORT
      LAYER Metal3 ;
        RECT 0.000 41.380 0.400 41.780 ;
    END
  END AXI_M_SOC_RDATA27
  PIN AXI_M_SOC_RDATA28
    DIRECTION INPUT ;
    USE SIGNAL ;
    ANTENNAGATEAREA 1.279200 ;
    PORT
      LAYER Metal3 ;
        RECT 0.000 42.220 0.400 42.620 ;
    END
  END AXI_M_SOC_RDATA28
  PIN AXI_M_SOC_RDATA29
    DIRECTION INPUT ;
    USE SIGNAL ;
    ANTENNAGATEAREA 1.279200 ;
    PORT
      LAYER Metal3 ;
        RECT 0.000 43.060 0.400 43.460 ;
    END
  END AXI_M_SOC_RDATA29
  PIN AXI_M_SOC_RDATA3
    DIRECTION INPUT ;
    USE SIGNAL ;
    ANTENNAGATEAREA 1.279200 ;
    PORT
      LAYER Metal3 ;
        RECT 0.000 21.220 0.400 21.620 ;
    END
  END AXI_M_SOC_RDATA3
  PIN AXI_M_SOC_RDATA30
    DIRECTION INPUT ;
    USE SIGNAL ;
    ANTENNAGATEAREA 1.279200 ;
    PORT
      LAYER Metal3 ;
        RECT 0.000 43.900 0.400 44.300 ;
    END
  END AXI_M_SOC_RDATA30
  PIN AXI_M_SOC_RDATA31
    DIRECTION INPUT ;
    USE SIGNAL ;
    ANTENNAGATEAREA 1.279200 ;
    PORT
      LAYER Metal3 ;
        RECT 0.000 44.740 0.400 45.140 ;
    END
  END AXI_M_SOC_RDATA31
  PIN AXI_M_SOC_RDATA4
    DIRECTION INPUT ;
    USE SIGNAL ;
    ANTENNAGATEAREA 1.279200 ;
    PORT
      LAYER Metal3 ;
        RECT 0.000 22.060 0.400 22.460 ;
    END
  END AXI_M_SOC_RDATA4
  PIN AXI_M_SOC_RDATA5
    DIRECTION INPUT ;
    USE SIGNAL ;
    ANTENNAGATEAREA 1.279200 ;
    PORT
      LAYER Metal3 ;
        RECT 0.000 22.900 0.400 23.300 ;
    END
  END AXI_M_SOC_RDATA5
  PIN AXI_M_SOC_RDATA6
    DIRECTION INPUT ;
    USE SIGNAL ;
    ANTENNAGATEAREA 1.279200 ;
    PORT
      LAYER Metal3 ;
        RECT 0.000 23.740 0.400 24.140 ;
    END
  END AXI_M_SOC_RDATA6
  PIN AXI_M_SOC_RDATA7
    DIRECTION INPUT ;
    USE SIGNAL ;
    ANTENNAGATEAREA 1.279200 ;
    PORT
      LAYER Metal3 ;
        RECT 0.000 24.580 0.400 24.980 ;
    END
  END AXI_M_SOC_RDATA7
  PIN AXI_M_SOC_RDATA8
    DIRECTION INPUT ;
    USE SIGNAL ;
    ANTENNAGATEAREA 1.279200 ;
    PORT
      LAYER Metal3 ;
        RECT 0.000 25.420 0.400 25.820 ;
    END
  END AXI_M_SOC_RDATA8
  PIN AXI_M_SOC_RDATA9
    DIRECTION INPUT ;
    USE SIGNAL ;
    ANTENNAGATEAREA 1.279200 ;
    ANTENNADIFFAREA 12.092400 ;
    PORT
      LAYER Metal3 ;
        RECT 0.000 26.260 0.400 26.660 ;
    END
  END AXI_M_SOC_RDATA9
  PIN AXI_M_SOC_RLAST
    DIRECTION INPUT ;
    USE SIGNAL ;
    ANTENNAGATEAREA 1.279200 ;
    PORT
      LAYER Metal3 ;
        RECT 0.000 47.260 0.400 47.660 ;
    END
  END AXI_M_SOC_RLAST
  PIN AXI_M_SOC_RREADY
    DIRECTION OUTPUT ;
    USE SIGNAL ;
    ANTENNADIFFAREA 0.632400 ;
    PORT
      LAYER Metal3 ;
        RECT 0.000 158.980 0.400 159.380 ;
    END
  END AXI_M_SOC_RREADY
  PIN AXI_M_SOC_RRESP0
    DIRECTION INPUT ;
    USE SIGNAL ;
    ANTENNAGATEAREA 1.279200 ;
    PORT
      LAYER Metal3 ;
        RECT 0.000 45.580 0.400 45.980 ;
    END
  END AXI_M_SOC_RRESP0
  PIN AXI_M_SOC_RRESP1
    DIRECTION INPUT ;
    USE SIGNAL ;
    ANTENNAGATEAREA 1.279200 ;
    PORT
      LAYER Metal3 ;
        RECT 0.000 46.420 0.400 46.820 ;
    END
  END AXI_M_SOC_RRESP1
  PIN AXI_M_SOC_RVALID
    DIRECTION INPUT ;
    USE SIGNAL ;
    ANTENNAGATEAREA 1.279200 ;
    PORT
      LAYER Metal3 ;
        RECT 0.000 48.100 0.400 48.500 ;
    END
  END AXI_M_SOC_RVALID
  PIN AXI_M_SOC_WDATA0
    DIRECTION OUTPUT ;
    USE SIGNAL ;
    ANTENNADIFFAREA 0.632400 ;
    PORT
      LAYER Metal3 ;
        RECT 0.000 87.580 0.400 87.980 ;
    END
  END AXI_M_SOC_WDATA0
  PIN AXI_M_SOC_WDATA1
    DIRECTION OUTPUT ;
    USE SIGNAL ;
    ANTENNADIFFAREA 0.632400 ;
    PORT
      LAYER Metal3 ;
        RECT 0.000 88.420 0.400 88.820 ;
    END
  END AXI_M_SOC_WDATA1
  PIN AXI_M_SOC_WDATA10
    DIRECTION OUTPUT ;
    USE SIGNAL ;
    ANTENNADIFFAREA 0.632400 ;
    PORT
      LAYER Metal3 ;
        RECT 0.000 95.980 0.400 96.380 ;
    END
  END AXI_M_SOC_WDATA10
  PIN AXI_M_SOC_WDATA11
    DIRECTION OUTPUT ;
    USE SIGNAL ;
    ANTENNADIFFAREA 0.632400 ;
    PORT
      LAYER Metal3 ;
        RECT 0.000 96.820 0.400 97.220 ;
    END
  END AXI_M_SOC_WDATA11
  PIN AXI_M_SOC_WDATA12
    DIRECTION OUTPUT ;
    USE SIGNAL ;
    ANTENNADIFFAREA 0.632400 ;
    PORT
      LAYER Metal3 ;
        RECT 0.000 97.660 0.400 98.060 ;
    END
  END AXI_M_SOC_WDATA12
  PIN AXI_M_SOC_WDATA13
    DIRECTION OUTPUT ;
    USE SIGNAL ;
    ANTENNADIFFAREA 0.632400 ;
    PORT
      LAYER Metal3 ;
        RECT 0.000 98.500 0.400 98.900 ;
    END
  END AXI_M_SOC_WDATA13
  PIN AXI_M_SOC_WDATA14
    DIRECTION OUTPUT ;
    USE SIGNAL ;
    ANTENNADIFFAREA 0.632400 ;
    PORT
      LAYER Metal3 ;
        RECT 0.000 99.340 0.400 99.740 ;
    END
  END AXI_M_SOC_WDATA14
  PIN AXI_M_SOC_WDATA15
    DIRECTION OUTPUT ;
    USE SIGNAL ;
    ANTENNADIFFAREA 0.632400 ;
    PORT
      LAYER Metal3 ;
        RECT 0.000 100.180 0.400 100.580 ;
    END
  END AXI_M_SOC_WDATA15
  PIN AXI_M_SOC_WDATA16
    DIRECTION OUTPUT ;
    USE SIGNAL ;
    ANTENNADIFFAREA 0.632400 ;
    PORT
      LAYER Metal3 ;
        RECT 0.000 101.020 0.400 101.420 ;
    END
  END AXI_M_SOC_WDATA16
  PIN AXI_M_SOC_WDATA17
    DIRECTION OUTPUT ;
    USE SIGNAL ;
    ANTENNADIFFAREA 0.632400 ;
    PORT
      LAYER Metal3 ;
        RECT 0.000 101.860 0.400 102.260 ;
    END
  END AXI_M_SOC_WDATA17
  PIN AXI_M_SOC_WDATA18
    DIRECTION OUTPUT ;
    USE SIGNAL ;
    ANTENNADIFFAREA 0.632400 ;
    PORT
      LAYER Metal3 ;
        RECT 0.000 102.700 0.400 103.100 ;
    END
  END AXI_M_SOC_WDATA18
  PIN AXI_M_SOC_WDATA19
    DIRECTION OUTPUT ;
    USE SIGNAL ;
    ANTENNADIFFAREA 0.632400 ;
    PORT
      LAYER Metal3 ;
        RECT 0.000 103.540 0.400 103.940 ;
    END
  END AXI_M_SOC_WDATA19
  PIN AXI_M_SOC_WDATA2
    DIRECTION OUTPUT ;
    USE SIGNAL ;
    ANTENNADIFFAREA 0.632400 ;
    PORT
      LAYER Metal3 ;
        RECT 0.000 89.260 0.400 89.660 ;
    END
  END AXI_M_SOC_WDATA2
  PIN AXI_M_SOC_WDATA20
    DIRECTION OUTPUT ;
    USE SIGNAL ;
    ANTENNADIFFAREA 0.632400 ;
    PORT
      LAYER Metal3 ;
        RECT 0.000 104.380 0.400 104.780 ;
    END
  END AXI_M_SOC_WDATA20
  PIN AXI_M_SOC_WDATA21
    DIRECTION OUTPUT ;
    USE SIGNAL ;
    ANTENNADIFFAREA 0.632400 ;
    PORT
      LAYER Metal3 ;
        RECT 0.000 105.220 0.400 105.620 ;
    END
  END AXI_M_SOC_WDATA21
  PIN AXI_M_SOC_WDATA22
    DIRECTION OUTPUT ;
    USE SIGNAL ;
    ANTENNADIFFAREA 0.632400 ;
    PORT
      LAYER Metal3 ;
        RECT 0.000 106.060 0.400 106.460 ;
    END
  END AXI_M_SOC_WDATA22
  PIN AXI_M_SOC_WDATA23
    DIRECTION OUTPUT ;
    USE SIGNAL ;
    ANTENNADIFFAREA 0.632400 ;
    PORT
      LAYER Metal3 ;
        RECT 0.000 106.900 0.400 107.300 ;
    END
  END AXI_M_SOC_WDATA23
  PIN AXI_M_SOC_WDATA24
    DIRECTION OUTPUT ;
    USE SIGNAL ;
    ANTENNADIFFAREA 0.632400 ;
    PORT
      LAYER Metal3 ;
        RECT 0.000 107.740 0.400 108.140 ;
    END
  END AXI_M_SOC_WDATA24
  PIN AXI_M_SOC_WDATA25
    DIRECTION OUTPUT ;
    USE SIGNAL ;
    ANTENNADIFFAREA 0.632400 ;
    PORT
      LAYER Metal3 ;
        RECT 0.000 108.580 0.400 108.980 ;
    END
  END AXI_M_SOC_WDATA25
  PIN AXI_M_SOC_WDATA26
    DIRECTION OUTPUT ;
    USE SIGNAL ;
    ANTENNADIFFAREA 0.632400 ;
    PORT
      LAYER Metal3 ;
        RECT 0.000 109.420 0.400 109.820 ;
    END
  END AXI_M_SOC_WDATA26
  PIN AXI_M_SOC_WDATA27
    DIRECTION OUTPUT ;
    USE SIGNAL ;
    ANTENNADIFFAREA 0.632400 ;
    PORT
      LAYER Metal3 ;
        RECT 0.000 110.260 0.400 110.660 ;
    END
  END AXI_M_SOC_WDATA27
  PIN AXI_M_SOC_WDATA28
    DIRECTION OUTPUT ;
    USE SIGNAL ;
    ANTENNADIFFAREA 0.632400 ;
    PORT
      LAYER Metal3 ;
        RECT 0.000 111.100 0.400 111.500 ;
    END
  END AXI_M_SOC_WDATA28
  PIN AXI_M_SOC_WDATA29
    DIRECTION OUTPUT ;
    USE SIGNAL ;
    ANTENNADIFFAREA 0.632400 ;
    PORT
      LAYER Metal3 ;
        RECT 0.000 111.940 0.400 112.340 ;
    END
  END AXI_M_SOC_WDATA29
  PIN AXI_M_SOC_WDATA3
    DIRECTION OUTPUT ;
    USE SIGNAL ;
    ANTENNADIFFAREA 0.632400 ;
    PORT
      LAYER Metal3 ;
        RECT 0.000 90.100 0.400 90.500 ;
    END
  END AXI_M_SOC_WDATA3
  PIN AXI_M_SOC_WDATA30
    DIRECTION OUTPUT ;
    USE SIGNAL ;
    ANTENNADIFFAREA 0.632400 ;
    PORT
      LAYER Metal3 ;
        RECT 0.000 112.780 0.400 113.180 ;
    END
  END AXI_M_SOC_WDATA30
  PIN AXI_M_SOC_WDATA31
    DIRECTION OUTPUT ;
    USE SIGNAL ;
    ANTENNADIFFAREA 0.632400 ;
    PORT
      LAYER Metal3 ;
        RECT 0.000 113.620 0.400 114.020 ;
    END
  END AXI_M_SOC_WDATA31
  PIN AXI_M_SOC_WDATA4
    DIRECTION OUTPUT ;
    USE SIGNAL ;
    ANTENNADIFFAREA 0.632400 ;
    PORT
      LAYER Metal3 ;
        RECT 0.000 90.940 0.400 91.340 ;
    END
  END AXI_M_SOC_WDATA4
  PIN AXI_M_SOC_WDATA5
    DIRECTION OUTPUT ;
    USE SIGNAL ;
    ANTENNADIFFAREA 0.632400 ;
    PORT
      LAYER Metal3 ;
        RECT 0.000 91.780 0.400 92.180 ;
    END
  END AXI_M_SOC_WDATA5
  PIN AXI_M_SOC_WDATA6
    DIRECTION OUTPUT ;
    USE SIGNAL ;
    ANTENNADIFFAREA 0.632400 ;
    PORT
      LAYER Metal3 ;
        RECT 0.000 92.620 0.400 93.020 ;
    END
  END AXI_M_SOC_WDATA6
  PIN AXI_M_SOC_WDATA7
    DIRECTION OUTPUT ;
    USE SIGNAL ;
    ANTENNADIFFAREA 0.632400 ;
    PORT
      LAYER Metal3 ;
        RECT 0.000 93.460 0.400 93.860 ;
    END
  END AXI_M_SOC_WDATA7
  PIN AXI_M_SOC_WDATA8
    DIRECTION OUTPUT ;
    USE SIGNAL ;
    ANTENNADIFFAREA 0.632400 ;
    PORT
      LAYER Metal3 ;
        RECT 0.000 94.300 0.400 94.700 ;
    END
  END AXI_M_SOC_WDATA8
  PIN AXI_M_SOC_WDATA9
    DIRECTION OUTPUT ;
    USE SIGNAL ;
    ANTENNADIFFAREA 0.632400 ;
    PORT
      LAYER Metal3 ;
        RECT 0.000 95.140 0.400 95.540 ;
    END
  END AXI_M_SOC_WDATA9
  PIN AXI_M_SOC_WLAST
    DIRECTION OUTPUT ;
    USE SIGNAL ;
    ANTENNADIFFAREA 0.649200 ;
    PORT
      LAYER Metal3 ;
        RECT 0.000 117.820 0.400 118.220 ;
    END
  END AXI_M_SOC_WLAST
  PIN AXI_M_SOC_WREADY
    DIRECTION INPUT ;
    USE SIGNAL ;
    ANTENNAGATEAREA 1.279200 ;
    PORT
      LAYER Metal3 ;
        RECT 0.000 14.500 0.400 14.900 ;
    END
  END AXI_M_SOC_WREADY
  PIN AXI_M_SOC_WSTRB0
    DIRECTION OUTPUT ;
    USE SIGNAL ;
    ANTENNADIFFAREA 0.649200 ;
    PORT
      LAYER Metal3 ;
        RECT 0.000 114.460 0.400 114.860 ;
    END
  END AXI_M_SOC_WSTRB0
  PIN AXI_M_SOC_WSTRB1
    DIRECTION OUTPUT ;
    USE SIGNAL ;
    ANTENNADIFFAREA 0.649200 ;
    PORT
      LAYER Metal3 ;
        RECT 0.000 115.300 0.400 115.700 ;
    END
  END AXI_M_SOC_WSTRB1
  PIN AXI_M_SOC_WSTRB2
    DIRECTION OUTPUT ;
    USE SIGNAL ;
    ANTENNADIFFAREA 0.649200 ;
    PORT
      LAYER Metal3 ;
        RECT 0.000 116.140 0.400 116.540 ;
    END
  END AXI_M_SOC_WSTRB2
  PIN AXI_M_SOC_WSTRB3
    DIRECTION OUTPUT ;
    USE SIGNAL ;
    ANTENNADIFFAREA 0.649200 ;
    PORT
      LAYER Metal3 ;
        RECT 0.000 116.980 0.400 117.380 ;
    END
  END AXI_M_SOC_WSTRB3
  PIN AXI_M_SOC_WVALID
    DIRECTION OUTPUT ;
    USE SIGNAL ;
    ANTENNADIFFAREA 0.632400 ;
    PORT
      LAYER Metal3 ;
        RECT 0.000 118.660 0.400 119.060 ;
    END
  END AXI_M_SOC_WVALID
  PIN Tile_X0Y0_E1BEG[0]
    DIRECTION OUTPUT ;
    USE SIGNAL ;
    ANTENNADIFFAREA 0.708600 ;
    PORT
      LAYER Metal3 ;
        RECT 219.440 1104.400 219.840 1104.800 ;
    END
  END Tile_X0Y0_E1BEG[0]
  PIN Tile_X0Y0_E1BEG[1]
    DIRECTION OUTPUT ;
    USE SIGNAL ;
    ANTENNADIFFAREA 0.708600 ;
    PORT
      LAYER Metal3 ;
        RECT 219.440 1105.240 219.840 1105.640 ;
    END
  END Tile_X0Y0_E1BEG[1]
  PIN Tile_X0Y0_E1BEG[2]
    DIRECTION OUTPUT ;
    USE SIGNAL ;
    ANTENNADIFFAREA 0.708600 ;
    PORT
      LAYER Metal3 ;
        RECT 219.440 1106.080 219.840 1106.480 ;
    END
  END Tile_X0Y0_E1BEG[2]
  PIN Tile_X0Y0_E1BEG[3]
    DIRECTION OUTPUT ;
    USE SIGNAL ;
    ANTENNADIFFAREA 0.708600 ;
    PORT
      LAYER Metal3 ;
        RECT 219.440 1106.920 219.840 1107.320 ;
    END
  END Tile_X0Y0_E1BEG[3]
  PIN Tile_X0Y0_E2BEG[0]
    DIRECTION OUTPUT ;
    USE SIGNAL ;
    ANTENNADIFFAREA 0.708600 ;
    PORT
      LAYER Metal3 ;
        RECT 219.440 1107.760 219.840 1108.160 ;
    END
  END Tile_X0Y0_E2BEG[0]
  PIN Tile_X0Y0_E2BEG[1]
    DIRECTION OUTPUT ;
    USE SIGNAL ;
    ANTENNADIFFAREA 0.708600 ;
    PORT
      LAYER Metal3 ;
        RECT 219.440 1108.600 219.840 1109.000 ;
    END
  END Tile_X0Y0_E2BEG[1]
  PIN Tile_X0Y0_E2BEG[2]
    DIRECTION OUTPUT ;
    USE SIGNAL ;
    ANTENNADIFFAREA 0.708600 ;
    PORT
      LAYER Metal3 ;
        RECT 219.440 1109.440 219.840 1109.840 ;
    END
  END Tile_X0Y0_E2BEG[2]
  PIN Tile_X0Y0_E2BEG[3]
    DIRECTION OUTPUT ;
    USE SIGNAL ;
    ANTENNADIFFAREA 0.708600 ;
    PORT
      LAYER Metal3 ;
        RECT 219.440 1110.280 219.840 1110.680 ;
    END
  END Tile_X0Y0_E2BEG[3]
  PIN Tile_X0Y0_E2BEG[4]
    DIRECTION OUTPUT ;
    USE SIGNAL ;
    ANTENNADIFFAREA 0.708600 ;
    PORT
      LAYER Metal3 ;
        RECT 219.440 1111.120 219.840 1111.520 ;
    END
  END Tile_X0Y0_E2BEG[4]
  PIN Tile_X0Y0_E2BEG[5]
    DIRECTION OUTPUT ;
    USE SIGNAL ;
    ANTENNADIFFAREA 0.708600 ;
    PORT
      LAYER Metal3 ;
        RECT 219.440 1111.960 219.840 1112.360 ;
    END
  END Tile_X0Y0_E2BEG[5]
  PIN Tile_X0Y0_E2BEG[6]
    DIRECTION OUTPUT ;
    USE SIGNAL ;
    ANTENNADIFFAREA 0.708600 ;
    PORT
      LAYER Metal3 ;
        RECT 219.440 1112.800 219.840 1113.200 ;
    END
  END Tile_X0Y0_E2BEG[6]
  PIN Tile_X0Y0_E2BEG[7]
    DIRECTION OUTPUT ;
    USE SIGNAL ;
    ANTENNADIFFAREA 0.708600 ;
    PORT
      LAYER Metal3 ;
        RECT 219.440 1113.640 219.840 1114.040 ;
    END
  END Tile_X0Y0_E2BEG[7]
  PIN Tile_X0Y0_E2BEGb[0]
    DIRECTION OUTPUT ;
    USE SIGNAL ;
    ANTENNADIFFAREA 0.708600 ;
    PORT
      LAYER Metal3 ;
        RECT 219.440 1114.480 219.840 1114.880 ;
    END
  END Tile_X0Y0_E2BEGb[0]
  PIN Tile_X0Y0_E2BEGb[1]
    DIRECTION OUTPUT ;
    USE SIGNAL ;
    ANTENNADIFFAREA 0.708600 ;
    PORT
      LAYER Metal3 ;
        RECT 219.440 1115.320 219.840 1115.720 ;
    END
  END Tile_X0Y0_E2BEGb[1]
  PIN Tile_X0Y0_E2BEGb[2]
    DIRECTION OUTPUT ;
    USE SIGNAL ;
    ANTENNADIFFAREA 0.708600 ;
    PORT
      LAYER Metal3 ;
        RECT 219.440 1116.160 219.840 1116.560 ;
    END
  END Tile_X0Y0_E2BEGb[2]
  PIN Tile_X0Y0_E2BEGb[3]
    DIRECTION OUTPUT ;
    USE SIGNAL ;
    ANTENNADIFFAREA 0.708600 ;
    PORT
      LAYER Metal3 ;
        RECT 219.440 1117.000 219.840 1117.400 ;
    END
  END Tile_X0Y0_E2BEGb[3]
  PIN Tile_X0Y0_E2BEGb[4]
    DIRECTION OUTPUT ;
    USE SIGNAL ;
    ANTENNADIFFAREA 0.708600 ;
    PORT
      LAYER Metal3 ;
        RECT 219.440 1117.840 219.840 1118.240 ;
    END
  END Tile_X0Y0_E2BEGb[4]
  PIN Tile_X0Y0_E2BEGb[5]
    DIRECTION OUTPUT ;
    USE SIGNAL ;
    ANTENNADIFFAREA 0.708600 ;
    PORT
      LAYER Metal3 ;
        RECT 219.440 1118.680 219.840 1119.080 ;
    END
  END Tile_X0Y0_E2BEGb[5]
  PIN Tile_X0Y0_E2BEGb[6]
    DIRECTION OUTPUT ;
    USE SIGNAL ;
    ANTENNADIFFAREA 0.708600 ;
    PORT
      LAYER Metal3 ;
        RECT 219.440 1119.520 219.840 1119.920 ;
    END
  END Tile_X0Y0_E2BEGb[6]
  PIN Tile_X0Y0_E2BEGb[7]
    DIRECTION OUTPUT ;
    USE SIGNAL ;
    ANTENNADIFFAREA 0.708600 ;
    PORT
      LAYER Metal3 ;
        RECT 219.440 1120.360 219.840 1120.760 ;
    END
  END Tile_X0Y0_E2BEGb[7]
  PIN Tile_X0Y0_E6BEG[0]
    DIRECTION OUTPUT ;
    USE SIGNAL ;
    ANTENNADIFFAREA 0.708600 ;
    PORT
      LAYER Metal3 ;
        RECT 219.440 1134.640 219.840 1135.040 ;
    END
  END Tile_X0Y0_E6BEG[0]
  PIN Tile_X0Y0_E6BEG[10]
    DIRECTION OUTPUT ;
    USE SIGNAL ;
    ANTENNADIFFAREA 0.708600 ;
    PORT
      LAYER Metal3 ;
        RECT 219.440 1143.040 219.840 1143.440 ;
    END
  END Tile_X0Y0_E6BEG[10]
  PIN Tile_X0Y0_E6BEG[11]
    DIRECTION OUTPUT ;
    USE SIGNAL ;
    ANTENNADIFFAREA 0.708600 ;
    PORT
      LAYER Metal3 ;
        RECT 219.440 1143.880 219.840 1144.280 ;
    END
  END Tile_X0Y0_E6BEG[11]
  PIN Tile_X0Y0_E6BEG[1]
    DIRECTION OUTPUT ;
    USE SIGNAL ;
    ANTENNADIFFAREA 0.708600 ;
    PORT
      LAYER Metal3 ;
        RECT 219.440 1135.480 219.840 1135.880 ;
    END
  END Tile_X0Y0_E6BEG[1]
  PIN Tile_X0Y0_E6BEG[2]
    DIRECTION OUTPUT ;
    USE SIGNAL ;
    ANTENNADIFFAREA 0.708600 ;
    PORT
      LAYER Metal3 ;
        RECT 219.440 1136.320 219.840 1136.720 ;
    END
  END Tile_X0Y0_E6BEG[2]
  PIN Tile_X0Y0_E6BEG[3]
    DIRECTION OUTPUT ;
    USE SIGNAL ;
    ANTENNADIFFAREA 0.708600 ;
    PORT
      LAYER Metal3 ;
        RECT 219.440 1137.160 219.840 1137.560 ;
    END
  END Tile_X0Y0_E6BEG[3]
  PIN Tile_X0Y0_E6BEG[4]
    DIRECTION OUTPUT ;
    USE SIGNAL ;
    ANTENNADIFFAREA 0.708600 ;
    PORT
      LAYER Metal3 ;
        RECT 219.440 1138.000 219.840 1138.400 ;
    END
  END Tile_X0Y0_E6BEG[4]
  PIN Tile_X0Y0_E6BEG[5]
    DIRECTION OUTPUT ;
    USE SIGNAL ;
    ANTENNADIFFAREA 0.708600 ;
    PORT
      LAYER Metal3 ;
        RECT 219.440 1138.840 219.840 1139.240 ;
    END
  END Tile_X0Y0_E6BEG[5]
  PIN Tile_X0Y0_E6BEG[6]
    DIRECTION OUTPUT ;
    USE SIGNAL ;
    ANTENNADIFFAREA 0.708600 ;
    PORT
      LAYER Metal3 ;
        RECT 219.440 1139.680 219.840 1140.080 ;
    END
  END Tile_X0Y0_E6BEG[6]
  PIN Tile_X0Y0_E6BEG[7]
    DIRECTION OUTPUT ;
    USE SIGNAL ;
    ANTENNADIFFAREA 0.708600 ;
    PORT
      LAYER Metal3 ;
        RECT 219.440 1140.520 219.840 1140.920 ;
    END
  END Tile_X0Y0_E6BEG[7]
  PIN Tile_X0Y0_E6BEG[8]
    DIRECTION OUTPUT ;
    USE SIGNAL ;
    ANTENNADIFFAREA 0.708600 ;
    PORT
      LAYER Metal3 ;
        RECT 219.440 1141.360 219.840 1141.760 ;
    END
  END Tile_X0Y0_E6BEG[8]
  PIN Tile_X0Y0_E6BEG[9]
    DIRECTION OUTPUT ;
    USE SIGNAL ;
    ANTENNADIFFAREA 0.708600 ;
    PORT
      LAYER Metal3 ;
        RECT 219.440 1142.200 219.840 1142.600 ;
    END
  END Tile_X0Y0_E6BEG[9]
  PIN Tile_X0Y0_EE4BEG[0]
    DIRECTION OUTPUT ;
    USE SIGNAL ;
    ANTENNADIFFAREA 0.708600 ;
    PORT
      LAYER Metal3 ;
        RECT 219.440 1121.200 219.840 1121.600 ;
    END
  END Tile_X0Y0_EE4BEG[0]
  PIN Tile_X0Y0_EE4BEG[10]
    DIRECTION OUTPUT ;
    USE SIGNAL ;
    ANTENNADIFFAREA 0.708600 ;
    PORT
      LAYER Metal3 ;
        RECT 219.440 1129.600 219.840 1130.000 ;
    END
  END Tile_X0Y0_EE4BEG[10]
  PIN Tile_X0Y0_EE4BEG[11]
    DIRECTION OUTPUT ;
    USE SIGNAL ;
    ANTENNADIFFAREA 0.708600 ;
    PORT
      LAYER Metal3 ;
        RECT 219.440 1130.440 219.840 1130.840 ;
    END
  END Tile_X0Y0_EE4BEG[11]
  PIN Tile_X0Y0_EE4BEG[12]
    DIRECTION OUTPUT ;
    USE SIGNAL ;
    ANTENNADIFFAREA 0.708600 ;
    PORT
      LAYER Metal3 ;
        RECT 219.440 1131.280 219.840 1131.680 ;
    END
  END Tile_X0Y0_EE4BEG[12]
  PIN Tile_X0Y0_EE4BEG[13]
    DIRECTION OUTPUT ;
    USE SIGNAL ;
    ANTENNADIFFAREA 0.708600 ;
    PORT
      LAYER Metal3 ;
        RECT 219.440 1132.120 219.840 1132.520 ;
    END
  END Tile_X0Y0_EE4BEG[13]
  PIN Tile_X0Y0_EE4BEG[14]
    DIRECTION OUTPUT ;
    USE SIGNAL ;
    ANTENNADIFFAREA 0.708600 ;
    PORT
      LAYER Metal3 ;
        RECT 219.440 1132.960 219.840 1133.360 ;
    END
  END Tile_X0Y0_EE4BEG[14]
  PIN Tile_X0Y0_EE4BEG[15]
    DIRECTION OUTPUT ;
    USE SIGNAL ;
    ANTENNADIFFAREA 0.708600 ;
    PORT
      LAYER Metal3 ;
        RECT 219.440 1133.800 219.840 1134.200 ;
    END
  END Tile_X0Y0_EE4BEG[15]
  PIN Tile_X0Y0_EE4BEG[1]
    DIRECTION OUTPUT ;
    USE SIGNAL ;
    ANTENNADIFFAREA 0.708600 ;
    PORT
      LAYER Metal3 ;
        RECT 219.440 1122.040 219.840 1122.440 ;
    END
  END Tile_X0Y0_EE4BEG[1]
  PIN Tile_X0Y0_EE4BEG[2]
    DIRECTION OUTPUT ;
    USE SIGNAL ;
    ANTENNADIFFAREA 0.708600 ;
    PORT
      LAYER Metal3 ;
        RECT 219.440 1122.880 219.840 1123.280 ;
    END
  END Tile_X0Y0_EE4BEG[2]
  PIN Tile_X0Y0_EE4BEG[3]
    DIRECTION OUTPUT ;
    USE SIGNAL ;
    ANTENNADIFFAREA 0.708600 ;
    PORT
      LAYER Metal3 ;
        RECT 219.440 1123.720 219.840 1124.120 ;
    END
  END Tile_X0Y0_EE4BEG[3]
  PIN Tile_X0Y0_EE4BEG[4]
    DIRECTION OUTPUT ;
    USE SIGNAL ;
    ANTENNADIFFAREA 0.708600 ;
    PORT
      LAYER Metal3 ;
        RECT 219.440 1124.560 219.840 1124.960 ;
    END
  END Tile_X0Y0_EE4BEG[4]
  PIN Tile_X0Y0_EE4BEG[5]
    DIRECTION OUTPUT ;
    USE SIGNAL ;
    ANTENNADIFFAREA 0.708600 ;
    PORT
      LAYER Metal3 ;
        RECT 219.440 1125.400 219.840 1125.800 ;
    END
  END Tile_X0Y0_EE4BEG[5]
  PIN Tile_X0Y0_EE4BEG[6]
    DIRECTION OUTPUT ;
    USE SIGNAL ;
    ANTENNADIFFAREA 0.708600 ;
    PORT
      LAYER Metal3 ;
        RECT 219.440 1126.240 219.840 1126.640 ;
    END
  END Tile_X0Y0_EE4BEG[6]
  PIN Tile_X0Y0_EE4BEG[7]
    DIRECTION OUTPUT ;
    USE SIGNAL ;
    ANTENNADIFFAREA 0.708600 ;
    PORT
      LAYER Metal3 ;
        RECT 219.440 1127.080 219.840 1127.480 ;
    END
  END Tile_X0Y0_EE4BEG[7]
  PIN Tile_X0Y0_EE4BEG[8]
    DIRECTION OUTPUT ;
    USE SIGNAL ;
    ANTENNADIFFAREA 0.708600 ;
    PORT
      LAYER Metal3 ;
        RECT 219.440 1127.920 219.840 1128.320 ;
    END
  END Tile_X0Y0_EE4BEG[8]
  PIN Tile_X0Y0_EE4BEG[9]
    DIRECTION OUTPUT ;
    USE SIGNAL ;
    ANTENNADIFFAREA 0.708600 ;
    PORT
      LAYER Metal3 ;
        RECT 219.440 1128.760 219.840 1129.160 ;
    END
  END Tile_X0Y0_EE4BEG[9]
  PIN Tile_X0Y0_FrameData[0]
    DIRECTION INPUT ;
    USE SIGNAL ;
    ANTENNAGATEAREA 1.626300 ;
    PORT
      LAYER Metal3 ;
        RECT 0.000 1053.580 0.400 1053.980 ;
    END
  END Tile_X0Y0_FrameData[0]
  PIN Tile_X0Y0_FrameData[10]
    DIRECTION INPUT ;
    USE SIGNAL ;
    ANTENNAGATEAREA 1.626300 ;
    PORT
      LAYER Metal3 ;
        RECT 0.000 1103.980 0.400 1104.380 ;
    END
  END Tile_X0Y0_FrameData[10]
  PIN Tile_X0Y0_FrameData[11]
    DIRECTION INPUT ;
    USE SIGNAL ;
    ANTENNAGATEAREA 1.626300 ;
    PORT
      LAYER Metal3 ;
        RECT 0.000 1109.020 0.400 1109.420 ;
    END
  END Tile_X0Y0_FrameData[11]
  PIN Tile_X0Y0_FrameData[12]
    DIRECTION INPUT ;
    USE SIGNAL ;
    ANTENNAGATEAREA 1.626300 ;
    PORT
      LAYER Metal3 ;
        RECT 0.000 1114.060 0.400 1114.460 ;
    END
  END Tile_X0Y0_FrameData[12]
  PIN Tile_X0Y0_FrameData[13]
    DIRECTION INPUT ;
    USE SIGNAL ;
    ANTENNAGATEAREA 1.626300 ;
    PORT
      LAYER Metal3 ;
        RECT 0.000 1119.100 0.400 1119.500 ;
    END
  END Tile_X0Y0_FrameData[13]
  PIN Tile_X0Y0_FrameData[14]
    DIRECTION INPUT ;
    USE SIGNAL ;
    ANTENNAGATEAREA 1.626300 ;
    PORT
      LAYER Metal3 ;
        RECT 0.000 1124.140 0.400 1124.540 ;
    END
  END Tile_X0Y0_FrameData[14]
  PIN Tile_X0Y0_FrameData[15]
    DIRECTION INPUT ;
    USE SIGNAL ;
    ANTENNAGATEAREA 1.626300 ;
    PORT
      LAYER Metal3 ;
        RECT 0.000 1129.180 0.400 1129.580 ;
    END
  END Tile_X0Y0_FrameData[15]
  PIN Tile_X0Y0_FrameData[16]
    DIRECTION INPUT ;
    USE SIGNAL ;
    ANTENNAGATEAREA 1.807000 ;
    PORT
      LAYER Metal3 ;
        RECT 0.000 1134.220 0.400 1134.620 ;
    END
  END Tile_X0Y0_FrameData[16]
  PIN Tile_X0Y0_FrameData[17]
    DIRECTION INPUT ;
    USE SIGNAL ;
    ANTENNAGATEAREA 1.807000 ;
    PORT
      LAYER Metal3 ;
        RECT 0.000 1139.260 0.400 1139.660 ;
    END
  END Tile_X0Y0_FrameData[17]
  PIN Tile_X0Y0_FrameData[18]
    DIRECTION INPUT ;
    USE SIGNAL ;
    ANTENNAGATEAREA 1.807000 ;
    PORT
      LAYER Metal3 ;
        RECT 0.000 1144.300 0.400 1144.700 ;
    END
  END Tile_X0Y0_FrameData[18]
  PIN Tile_X0Y0_FrameData[19]
    DIRECTION INPUT ;
    USE SIGNAL ;
    ANTENNAGATEAREA 1.807000 ;
    PORT
      LAYER Metal3 ;
        RECT 0.000 1149.340 0.400 1149.740 ;
    END
  END Tile_X0Y0_FrameData[19]
  PIN Tile_X0Y0_FrameData[1]
    DIRECTION INPUT ;
    USE SIGNAL ;
    ANTENNAGATEAREA 1.626300 ;
    PORT
      LAYER Metal3 ;
        RECT 0.000 1058.620 0.400 1059.020 ;
    END
  END Tile_X0Y0_FrameData[1]
  PIN Tile_X0Y0_FrameData[20]
    DIRECTION INPUT ;
    USE SIGNAL ;
    ANTENNAGATEAREA 1.807000 ;
    PORT
      LAYER Metal3 ;
        RECT 0.000 1154.380 0.400 1154.780 ;
    END
  END Tile_X0Y0_FrameData[20]
  PIN Tile_X0Y0_FrameData[21]
    DIRECTION INPUT ;
    USE SIGNAL ;
    ANTENNAGATEAREA 1.807000 ;
    PORT
      LAYER Metal3 ;
        RECT 0.000 1159.420 0.400 1159.820 ;
    END
  END Tile_X0Y0_FrameData[21]
  PIN Tile_X0Y0_FrameData[22]
    DIRECTION INPUT ;
    USE SIGNAL ;
    ANTENNAGATEAREA 1.807000 ;
    PORT
      LAYER Metal3 ;
        RECT 0.000 1164.460 0.400 1164.860 ;
    END
  END Tile_X0Y0_FrameData[22]
  PIN Tile_X0Y0_FrameData[23]
    DIRECTION INPUT ;
    USE SIGNAL ;
    ANTENNAGATEAREA 1.807000 ;
    PORT
      LAYER Metal3 ;
        RECT 0.000 1169.500 0.400 1169.900 ;
    END
  END Tile_X0Y0_FrameData[23]
  PIN Tile_X0Y0_FrameData[24]
    DIRECTION INPUT ;
    USE SIGNAL ;
    ANTENNAGATEAREA 1.807000 ;
    PORT
      LAYER Metal3 ;
        RECT 0.000 1174.540 0.400 1174.940 ;
    END
  END Tile_X0Y0_FrameData[24]
  PIN Tile_X0Y0_FrameData[25]
    DIRECTION INPUT ;
    USE SIGNAL ;
    ANTENNAGATEAREA 1.807000 ;
    PORT
      LAYER Metal3 ;
        RECT 0.000 1179.580 0.400 1179.980 ;
    END
  END Tile_X0Y0_FrameData[25]
  PIN Tile_X0Y0_FrameData[26]
    DIRECTION INPUT ;
    USE SIGNAL ;
    ANTENNAGATEAREA 1.807000 ;
    PORT
      LAYER Metal3 ;
        RECT 0.000 1184.620 0.400 1185.020 ;
    END
  END Tile_X0Y0_FrameData[26]
  PIN Tile_X0Y0_FrameData[27]
    DIRECTION INPUT ;
    USE SIGNAL ;
    ANTENNAGATEAREA 1.807000 ;
    PORT
      LAYER Metal3 ;
        RECT 0.000 1189.660 0.400 1190.060 ;
    END
  END Tile_X0Y0_FrameData[27]
  PIN Tile_X0Y0_FrameData[28]
    DIRECTION INPUT ;
    USE SIGNAL ;
    ANTENNAGATEAREA 1.807000 ;
    PORT
      LAYER Metal3 ;
        RECT 0.000 1194.700 0.400 1195.100 ;
    END
  END Tile_X0Y0_FrameData[28]
  PIN Tile_X0Y0_FrameData[29]
    DIRECTION INPUT ;
    USE SIGNAL ;
    ANTENNAGATEAREA 1.807000 ;
    PORT
      LAYER Metal3 ;
        RECT 0.000 1199.740 0.400 1200.140 ;
    END
  END Tile_X0Y0_FrameData[29]
  PIN Tile_X0Y0_FrameData[2]
    DIRECTION INPUT ;
    USE SIGNAL ;
    ANTENNAGATEAREA 1.626300 ;
    PORT
      LAYER Metal3 ;
        RECT 0.000 1063.660 0.400 1064.060 ;
    END
  END Tile_X0Y0_FrameData[2]
  PIN Tile_X0Y0_FrameData[30]
    DIRECTION INPUT ;
    USE SIGNAL ;
    ANTENNAGATEAREA 1.807000 ;
    PORT
      LAYER Metal3 ;
        RECT 0.000 1204.780 0.400 1205.180 ;
    END
  END Tile_X0Y0_FrameData[30]
  PIN Tile_X0Y0_FrameData[31]
    DIRECTION INPUT ;
    USE SIGNAL ;
    ANTENNAGATEAREA 1.807000 ;
    PORT
      LAYER Metal3 ;
        RECT 0.000 1209.820 0.400 1210.220 ;
    END
  END Tile_X0Y0_FrameData[31]
  PIN Tile_X0Y0_FrameData[3]
    DIRECTION INPUT ;
    USE SIGNAL ;
    ANTENNAGATEAREA 1.626300 ;
    PORT
      LAYER Metal3 ;
        RECT 0.000 1068.700 0.400 1069.100 ;
    END
  END Tile_X0Y0_FrameData[3]
  PIN Tile_X0Y0_FrameData[4]
    DIRECTION INPUT ;
    USE SIGNAL ;
    ANTENNAGATEAREA 1.626300 ;
    PORT
      LAYER Metal3 ;
        RECT 0.000 1073.740 0.400 1074.140 ;
    END
  END Tile_X0Y0_FrameData[4]
  PIN Tile_X0Y0_FrameData[5]
    DIRECTION INPUT ;
    USE SIGNAL ;
    ANTENNAGATEAREA 1.626300 ;
    PORT
      LAYER Metal3 ;
        RECT 0.000 1078.780 0.400 1079.180 ;
    END
  END Tile_X0Y0_FrameData[5]
  PIN Tile_X0Y0_FrameData[6]
    DIRECTION INPUT ;
    USE SIGNAL ;
    ANTENNAGATEAREA 1.626300 ;
    PORT
      LAYER Metal3 ;
        RECT 0.000 1083.820 0.400 1084.220 ;
    END
  END Tile_X0Y0_FrameData[6]
  PIN Tile_X0Y0_FrameData[7]
    DIRECTION INPUT ;
    USE SIGNAL ;
    ANTENNAGATEAREA 1.626300 ;
    ANTENNADIFFAREA 20.153999 ;
    PORT
      LAYER Metal3 ;
        RECT 0.000 1088.860 0.400 1089.260 ;
    END
  END Tile_X0Y0_FrameData[7]
  PIN Tile_X0Y0_FrameData[8]
    DIRECTION INPUT ;
    USE SIGNAL ;
    ANTENNAGATEAREA 1.626300 ;
    PORT
      LAYER Metal3 ;
        RECT 0.000 1093.900 0.400 1094.300 ;
    END
  END Tile_X0Y0_FrameData[8]
  PIN Tile_X0Y0_FrameData[9]
    DIRECTION INPUT ;
    USE SIGNAL ;
    ANTENNAGATEAREA 1.626300 ;
    PORT
      LAYER Metal3 ;
        RECT 0.000 1098.940 0.400 1099.340 ;
    END
  END Tile_X0Y0_FrameData[9]
  PIN Tile_X0Y0_FrameData_O[0]
    DIRECTION OUTPUT ;
    USE SIGNAL ;
    ANTENNADIFFAREA 0.708600 ;
    PORT
      LAYER Metal3 ;
        RECT 219.440 1144.720 219.840 1145.120 ;
    END
  END Tile_X0Y0_FrameData_O[0]
  PIN Tile_X0Y0_FrameData_O[10]
    DIRECTION OUTPUT ;
    USE SIGNAL ;
    ANTENNADIFFAREA 0.708600 ;
    PORT
      LAYER Metal3 ;
        RECT 219.440 1153.120 219.840 1153.520 ;
    END
  END Tile_X0Y0_FrameData_O[10]
  PIN Tile_X0Y0_FrameData_O[11]
    DIRECTION OUTPUT ;
    USE SIGNAL ;
    ANTENNADIFFAREA 0.708600 ;
    PORT
      LAYER Metal3 ;
        RECT 219.440 1153.960 219.840 1154.360 ;
    END
  END Tile_X0Y0_FrameData_O[11]
  PIN Tile_X0Y0_FrameData_O[12]
    DIRECTION OUTPUT ;
    USE SIGNAL ;
    ANTENNADIFFAREA 0.708600 ;
    PORT
      LAYER Metal3 ;
        RECT 219.440 1154.800 219.840 1155.200 ;
    END
  END Tile_X0Y0_FrameData_O[12]
  PIN Tile_X0Y0_FrameData_O[13]
    DIRECTION OUTPUT ;
    USE SIGNAL ;
    ANTENNADIFFAREA 0.708600 ;
    PORT
      LAYER Metal3 ;
        RECT 219.440 1155.640 219.840 1156.040 ;
    END
  END Tile_X0Y0_FrameData_O[13]
  PIN Tile_X0Y0_FrameData_O[14]
    DIRECTION OUTPUT ;
    USE SIGNAL ;
    ANTENNADIFFAREA 0.708600 ;
    PORT
      LAYER Metal3 ;
        RECT 219.440 1156.480 219.840 1156.880 ;
    END
  END Tile_X0Y0_FrameData_O[14]
  PIN Tile_X0Y0_FrameData_O[15]
    DIRECTION OUTPUT ;
    USE SIGNAL ;
    ANTENNADIFFAREA 0.708600 ;
    PORT
      LAYER Metal3 ;
        RECT 219.440 1157.320 219.840 1157.720 ;
    END
  END Tile_X0Y0_FrameData_O[15]
  PIN Tile_X0Y0_FrameData_O[16]
    DIRECTION OUTPUT ;
    USE SIGNAL ;
    ANTENNADIFFAREA 0.708600 ;
    PORT
      LAYER Metal3 ;
        RECT 219.440 1158.160 219.840 1158.560 ;
    END
  END Tile_X0Y0_FrameData_O[16]
  PIN Tile_X0Y0_FrameData_O[17]
    DIRECTION OUTPUT ;
    USE SIGNAL ;
    ANTENNADIFFAREA 0.708600 ;
    PORT
      LAYER Metal3 ;
        RECT 219.440 1159.000 219.840 1159.400 ;
    END
  END Tile_X0Y0_FrameData_O[17]
  PIN Tile_X0Y0_FrameData_O[18]
    DIRECTION OUTPUT ;
    USE SIGNAL ;
    ANTENNADIFFAREA 0.708600 ;
    PORT
      LAYER Metal3 ;
        RECT 219.440 1159.840 219.840 1160.240 ;
    END
  END Tile_X0Y0_FrameData_O[18]
  PIN Tile_X0Y0_FrameData_O[19]
    DIRECTION OUTPUT ;
    USE SIGNAL ;
    ANTENNADIFFAREA 0.708600 ;
    PORT
      LAYER Metal3 ;
        RECT 219.440 1160.680 219.840 1161.080 ;
    END
  END Tile_X0Y0_FrameData_O[19]
  PIN Tile_X0Y0_FrameData_O[1]
    DIRECTION OUTPUT ;
    USE SIGNAL ;
    ANTENNADIFFAREA 0.708600 ;
    PORT
      LAYER Metal3 ;
        RECT 219.440 1145.560 219.840 1145.960 ;
    END
  END Tile_X0Y0_FrameData_O[1]
  PIN Tile_X0Y0_FrameData_O[20]
    DIRECTION OUTPUT ;
    USE SIGNAL ;
    ANTENNADIFFAREA 0.708600 ;
    PORT
      LAYER Metal3 ;
        RECT 219.440 1161.520 219.840 1161.920 ;
    END
  END Tile_X0Y0_FrameData_O[20]
  PIN Tile_X0Y0_FrameData_O[21]
    DIRECTION OUTPUT ;
    USE SIGNAL ;
    ANTENNADIFFAREA 0.708600 ;
    PORT
      LAYER Metal3 ;
        RECT 219.440 1162.360 219.840 1162.760 ;
    END
  END Tile_X0Y0_FrameData_O[21]
  PIN Tile_X0Y0_FrameData_O[22]
    DIRECTION OUTPUT ;
    USE SIGNAL ;
    ANTENNADIFFAREA 0.708600 ;
    PORT
      LAYER Metal3 ;
        RECT 219.440 1163.200 219.840 1163.600 ;
    END
  END Tile_X0Y0_FrameData_O[22]
  PIN Tile_X0Y0_FrameData_O[23]
    DIRECTION OUTPUT ;
    USE SIGNAL ;
    ANTENNADIFFAREA 0.708600 ;
    PORT
      LAYER Metal3 ;
        RECT 219.440 1164.040 219.840 1164.440 ;
    END
  END Tile_X0Y0_FrameData_O[23]
  PIN Tile_X0Y0_FrameData_O[24]
    DIRECTION OUTPUT ;
    USE SIGNAL ;
    ANTENNADIFFAREA 0.708600 ;
    PORT
      LAYER Metal3 ;
        RECT 219.440 1164.880 219.840 1165.280 ;
    END
  END Tile_X0Y0_FrameData_O[24]
  PIN Tile_X0Y0_FrameData_O[25]
    DIRECTION OUTPUT ;
    USE SIGNAL ;
    ANTENNADIFFAREA 0.708600 ;
    PORT
      LAYER Metal3 ;
        RECT 219.440 1165.720 219.840 1166.120 ;
    END
  END Tile_X0Y0_FrameData_O[25]
  PIN Tile_X0Y0_FrameData_O[26]
    DIRECTION OUTPUT ;
    USE SIGNAL ;
    ANTENNADIFFAREA 0.708600 ;
    PORT
      LAYER Metal3 ;
        RECT 219.440 1166.560 219.840 1166.960 ;
    END
  END Tile_X0Y0_FrameData_O[26]
  PIN Tile_X0Y0_FrameData_O[27]
    DIRECTION OUTPUT ;
    USE SIGNAL ;
    ANTENNADIFFAREA 0.708600 ;
    PORT
      LAYER Metal3 ;
        RECT 219.440 1167.400 219.840 1167.800 ;
    END
  END Tile_X0Y0_FrameData_O[27]
  PIN Tile_X0Y0_FrameData_O[28]
    DIRECTION OUTPUT ;
    USE SIGNAL ;
    ANTENNADIFFAREA 0.708600 ;
    PORT
      LAYER Metal3 ;
        RECT 219.440 1168.240 219.840 1168.640 ;
    END
  END Tile_X0Y0_FrameData_O[28]
  PIN Tile_X0Y0_FrameData_O[29]
    DIRECTION OUTPUT ;
    USE SIGNAL ;
    ANTENNADIFFAREA 0.708600 ;
    PORT
      LAYER Metal3 ;
        RECT 219.440 1169.080 219.840 1169.480 ;
    END
  END Tile_X0Y0_FrameData_O[29]
  PIN Tile_X0Y0_FrameData_O[2]
    DIRECTION OUTPUT ;
    USE SIGNAL ;
    ANTENNADIFFAREA 0.708600 ;
    PORT
      LAYER Metal3 ;
        RECT 219.440 1146.400 219.840 1146.800 ;
    END
  END Tile_X0Y0_FrameData_O[2]
  PIN Tile_X0Y0_FrameData_O[30]
    DIRECTION OUTPUT ;
    USE SIGNAL ;
    ANTENNADIFFAREA 0.708600 ;
    PORT
      LAYER Metal3 ;
        RECT 219.440 1169.920 219.840 1170.320 ;
    END
  END Tile_X0Y0_FrameData_O[30]
  PIN Tile_X0Y0_FrameData_O[31]
    DIRECTION OUTPUT ;
    USE SIGNAL ;
    ANTENNADIFFAREA 0.708600 ;
    PORT
      LAYER Metal3 ;
        RECT 219.440 1170.760 219.840 1171.160 ;
    END
  END Tile_X0Y0_FrameData_O[31]
  PIN Tile_X0Y0_FrameData_O[3]
    DIRECTION OUTPUT ;
    USE SIGNAL ;
    ANTENNADIFFAREA 0.708600 ;
    PORT
      LAYER Metal3 ;
        RECT 219.440 1147.240 219.840 1147.640 ;
    END
  END Tile_X0Y0_FrameData_O[3]
  PIN Tile_X0Y0_FrameData_O[4]
    DIRECTION OUTPUT ;
    USE SIGNAL ;
    ANTENNADIFFAREA 0.708600 ;
    PORT
      LAYER Metal3 ;
        RECT 219.440 1148.080 219.840 1148.480 ;
    END
  END Tile_X0Y0_FrameData_O[4]
  PIN Tile_X0Y0_FrameData_O[5]
    DIRECTION OUTPUT ;
    USE SIGNAL ;
    ANTENNADIFFAREA 0.708600 ;
    PORT
      LAYER Metal3 ;
        RECT 219.440 1148.920 219.840 1149.320 ;
    END
  END Tile_X0Y0_FrameData_O[5]
  PIN Tile_X0Y0_FrameData_O[6]
    DIRECTION OUTPUT ;
    USE SIGNAL ;
    ANTENNADIFFAREA 0.708600 ;
    PORT
      LAYER Metal3 ;
        RECT 219.440 1149.760 219.840 1150.160 ;
    END
  END Tile_X0Y0_FrameData_O[6]
  PIN Tile_X0Y0_FrameData_O[7]
    DIRECTION OUTPUT ;
    USE SIGNAL ;
    ANTENNADIFFAREA 0.708600 ;
    PORT
      LAYER Metal3 ;
        RECT 219.440 1150.600 219.840 1151.000 ;
    END
  END Tile_X0Y0_FrameData_O[7]
  PIN Tile_X0Y0_FrameData_O[8]
    DIRECTION OUTPUT ;
    USE SIGNAL ;
    ANTENNADIFFAREA 0.708600 ;
    PORT
      LAYER Metal3 ;
        RECT 219.440 1151.440 219.840 1151.840 ;
    END
  END Tile_X0Y0_FrameData_O[8]
  PIN Tile_X0Y0_FrameData_O[9]
    DIRECTION OUTPUT ;
    USE SIGNAL ;
    ANTENNADIFFAREA 0.708600 ;
    PORT
      LAYER Metal3 ;
        RECT 219.440 1152.280 219.840 1152.680 ;
    END
  END Tile_X0Y0_FrameData_O[9]
  PIN Tile_X0Y0_FrameStrobe_O[0]
    DIRECTION OUTPUT ;
    USE SIGNAL ;
    ANTENNADIFFAREA 0.708600 ;
    PORT
      LAYER Metal2 ;
        RECT 159.640 1218.840 160.040 1219.240 ;
    END
  END Tile_X0Y0_FrameStrobe_O[0]
  PIN Tile_X0Y0_FrameStrobe_O[10]
    DIRECTION OUTPUT ;
    USE SIGNAL ;
    ANTENNADIFFAREA 0.708600 ;
    PORT
      LAYER Metal2 ;
        RECT 178.840 1218.840 179.240 1219.240 ;
    END
  END Tile_X0Y0_FrameStrobe_O[10]
  PIN Tile_X0Y0_FrameStrobe_O[11]
    DIRECTION OUTPUT ;
    USE SIGNAL ;
    ANTENNADIFFAREA 0.708600 ;
    PORT
      LAYER Metal2 ;
        RECT 180.760 1218.840 181.160 1219.240 ;
    END
  END Tile_X0Y0_FrameStrobe_O[11]
  PIN Tile_X0Y0_FrameStrobe_O[12]
    DIRECTION OUTPUT ;
    USE SIGNAL ;
    ANTENNADIFFAREA 0.708600 ;
    PORT
      LAYER Metal2 ;
        RECT 182.680 1218.840 183.080 1219.240 ;
    END
  END Tile_X0Y0_FrameStrobe_O[12]
  PIN Tile_X0Y0_FrameStrobe_O[13]
    DIRECTION OUTPUT ;
    USE SIGNAL ;
    ANTENNADIFFAREA 0.708600 ;
    PORT
      LAYER Metal2 ;
        RECT 184.600 1218.840 185.000 1219.240 ;
    END
  END Tile_X0Y0_FrameStrobe_O[13]
  PIN Tile_X0Y0_FrameStrobe_O[14]
    DIRECTION OUTPUT ;
    USE SIGNAL ;
    ANTENNADIFFAREA 0.708600 ;
    PORT
      LAYER Metal2 ;
        RECT 186.520 1218.840 186.920 1219.240 ;
    END
  END Tile_X0Y0_FrameStrobe_O[14]
  PIN Tile_X0Y0_FrameStrobe_O[15]
    DIRECTION OUTPUT ;
    USE SIGNAL ;
    ANTENNADIFFAREA 0.708600 ;
    PORT
      LAYER Metal2 ;
        RECT 188.440 1218.840 188.840 1219.240 ;
    END
  END Tile_X0Y0_FrameStrobe_O[15]
  PIN Tile_X0Y0_FrameStrobe_O[16]
    DIRECTION OUTPUT ;
    USE SIGNAL ;
    ANTENNADIFFAREA 0.708600 ;
    PORT
      LAYER Metal2 ;
        RECT 190.360 1218.840 190.760 1219.240 ;
    END
  END Tile_X0Y0_FrameStrobe_O[16]
  PIN Tile_X0Y0_FrameStrobe_O[17]
    DIRECTION OUTPUT ;
    USE SIGNAL ;
    ANTENNADIFFAREA 0.708600 ;
    PORT
      LAYER Metal2 ;
        RECT 192.280 1218.840 192.680 1219.240 ;
    END
  END Tile_X0Y0_FrameStrobe_O[17]
  PIN Tile_X0Y0_FrameStrobe_O[18]
    DIRECTION OUTPUT ;
    USE SIGNAL ;
    ANTENNADIFFAREA 0.708600 ;
    PORT
      LAYER Metal2 ;
        RECT 194.200 1218.840 194.600 1219.240 ;
    END
  END Tile_X0Y0_FrameStrobe_O[18]
  PIN Tile_X0Y0_FrameStrobe_O[19]
    DIRECTION OUTPUT ;
    USE SIGNAL ;
    ANTENNADIFFAREA 0.708600 ;
    PORT
      LAYER Metal2 ;
        RECT 196.120 1218.840 196.520 1219.240 ;
    END
  END Tile_X0Y0_FrameStrobe_O[19]
  PIN Tile_X0Y0_FrameStrobe_O[1]
    DIRECTION OUTPUT ;
    USE SIGNAL ;
    ANTENNADIFFAREA 0.708600 ;
    PORT
      LAYER Metal2 ;
        RECT 161.560 1218.840 161.960 1219.240 ;
    END
  END Tile_X0Y0_FrameStrobe_O[1]
  PIN Tile_X0Y0_FrameStrobe_O[2]
    DIRECTION OUTPUT ;
    USE SIGNAL ;
    ANTENNADIFFAREA 0.708600 ;
    PORT
      LAYER Metal2 ;
        RECT 163.480 1218.840 163.880 1219.240 ;
    END
  END Tile_X0Y0_FrameStrobe_O[2]
  PIN Tile_X0Y0_FrameStrobe_O[3]
    DIRECTION OUTPUT ;
    USE SIGNAL ;
    ANTENNADIFFAREA 0.708600 ;
    PORT
      LAYER Metal2 ;
        RECT 165.400 1218.840 165.800 1219.240 ;
    END
  END Tile_X0Y0_FrameStrobe_O[3]
  PIN Tile_X0Y0_FrameStrobe_O[4]
    DIRECTION OUTPUT ;
    USE SIGNAL ;
    ANTENNADIFFAREA 0.708600 ;
    PORT
      LAYER Metal2 ;
        RECT 167.320 1218.840 167.720 1219.240 ;
    END
  END Tile_X0Y0_FrameStrobe_O[4]
  PIN Tile_X0Y0_FrameStrobe_O[5]
    DIRECTION OUTPUT ;
    USE SIGNAL ;
    ANTENNADIFFAREA 0.708600 ;
    PORT
      LAYER Metal2 ;
        RECT 169.240 1218.840 169.640 1219.240 ;
    END
  END Tile_X0Y0_FrameStrobe_O[5]
  PIN Tile_X0Y0_FrameStrobe_O[6]
    DIRECTION OUTPUT ;
    USE SIGNAL ;
    ANTENNADIFFAREA 0.708600 ;
    PORT
      LAYER Metal2 ;
        RECT 171.160 1218.840 171.560 1219.240 ;
    END
  END Tile_X0Y0_FrameStrobe_O[6]
  PIN Tile_X0Y0_FrameStrobe_O[7]
    DIRECTION OUTPUT ;
    USE SIGNAL ;
    ANTENNADIFFAREA 0.708600 ;
    PORT
      LAYER Metal2 ;
        RECT 173.080 1218.840 173.480 1219.240 ;
    END
  END Tile_X0Y0_FrameStrobe_O[7]
  PIN Tile_X0Y0_FrameStrobe_O[8]
    DIRECTION OUTPUT ;
    USE SIGNAL ;
    ANTENNADIFFAREA 0.708600 ;
    PORT
      LAYER Metal2 ;
        RECT 175.000 1218.840 175.400 1219.240 ;
    END
  END Tile_X0Y0_FrameStrobe_O[8]
  PIN Tile_X0Y0_FrameStrobe_O[9]
    DIRECTION OUTPUT ;
    USE SIGNAL ;
    ANTENNADIFFAREA 0.708600 ;
    PORT
      LAYER Metal2 ;
        RECT 176.920 1218.840 177.320 1219.240 ;
    END
  END Tile_X0Y0_FrameStrobe_O[9]
  PIN Tile_X0Y0_N1BEG[0]
    DIRECTION OUTPUT ;
    USE SIGNAL ;
    ANTENNADIFFAREA 0.708600 ;
    PORT
      LAYER Metal2 ;
        RECT 21.400 1218.840 21.800 1219.240 ;
    END
  END Tile_X0Y0_N1BEG[0]
  PIN Tile_X0Y0_N1BEG[1]
    DIRECTION OUTPUT ;
    USE SIGNAL ;
    ANTENNADIFFAREA 0.708600 ;
    PORT
      LAYER Metal2 ;
        RECT 23.320 1218.840 23.720 1219.240 ;
    END
  END Tile_X0Y0_N1BEG[1]
  PIN Tile_X0Y0_N1BEG[2]
    DIRECTION OUTPUT ;
    USE SIGNAL ;
    ANTENNADIFFAREA 0.708600 ;
    PORT
      LAYER Metal2 ;
        RECT 25.240 1218.840 25.640 1219.240 ;
    END
  END Tile_X0Y0_N1BEG[2]
  PIN Tile_X0Y0_N1BEG[3]
    DIRECTION OUTPUT ;
    USE SIGNAL ;
    ANTENNADIFFAREA 0.708600 ;
    PORT
      LAYER Metal2 ;
        RECT 27.160 1218.840 27.560 1219.240 ;
    END
  END Tile_X0Y0_N1BEG[3]
  PIN Tile_X0Y0_N2BEG[0]
    DIRECTION OUTPUT ;
    USE SIGNAL ;
    ANTENNADIFFAREA 0.708600 ;
    PORT
      LAYER Metal2 ;
        RECT 29.080 1218.840 29.480 1219.240 ;
    END
  END Tile_X0Y0_N2BEG[0]
  PIN Tile_X0Y0_N2BEG[1]
    DIRECTION OUTPUT ;
    USE SIGNAL ;
    ANTENNADIFFAREA 0.708600 ;
    PORT
      LAYER Metal2 ;
        RECT 31.000 1218.840 31.400 1219.240 ;
    END
  END Tile_X0Y0_N2BEG[1]
  PIN Tile_X0Y0_N2BEG[2]
    DIRECTION OUTPUT ;
    USE SIGNAL ;
    ANTENNADIFFAREA 0.708600 ;
    PORT
      LAYER Metal2 ;
        RECT 32.920 1218.840 33.320 1219.240 ;
    END
  END Tile_X0Y0_N2BEG[2]
  PIN Tile_X0Y0_N2BEG[3]
    DIRECTION OUTPUT ;
    USE SIGNAL ;
    ANTENNADIFFAREA 0.708600 ;
    PORT
      LAYER Metal2 ;
        RECT 34.840 1218.840 35.240 1219.240 ;
    END
  END Tile_X0Y0_N2BEG[3]
  PIN Tile_X0Y0_N2BEG[4]
    DIRECTION OUTPUT ;
    USE SIGNAL ;
    ANTENNADIFFAREA 0.708600 ;
    PORT
      LAYER Metal2 ;
        RECT 36.760 1218.840 37.160 1219.240 ;
    END
  END Tile_X0Y0_N2BEG[4]
  PIN Tile_X0Y0_N2BEG[5]
    DIRECTION OUTPUT ;
    USE SIGNAL ;
    ANTENNADIFFAREA 0.708600 ;
    PORT
      LAYER Metal2 ;
        RECT 38.680 1218.840 39.080 1219.240 ;
    END
  END Tile_X0Y0_N2BEG[5]
  PIN Tile_X0Y0_N2BEG[6]
    DIRECTION OUTPUT ;
    USE SIGNAL ;
    ANTENNADIFFAREA 0.708600 ;
    PORT
      LAYER Metal2 ;
        RECT 40.600 1218.840 41.000 1219.240 ;
    END
  END Tile_X0Y0_N2BEG[6]
  PIN Tile_X0Y0_N2BEG[7]
    DIRECTION OUTPUT ;
    USE SIGNAL ;
    ANTENNADIFFAREA 0.708600 ;
    PORT
      LAYER Metal2 ;
        RECT 42.520 1218.840 42.920 1219.240 ;
    END
  END Tile_X0Y0_N2BEG[7]
  PIN Tile_X0Y0_N2BEGb[0]
    DIRECTION OUTPUT ;
    USE SIGNAL ;
    ANTENNADIFFAREA 0.708600 ;
    PORT
      LAYER Metal2 ;
        RECT 44.440 1218.840 44.840 1219.240 ;
    END
  END Tile_X0Y0_N2BEGb[0]
  PIN Tile_X0Y0_N2BEGb[1]
    DIRECTION OUTPUT ;
    USE SIGNAL ;
    ANTENNADIFFAREA 0.708600 ;
    PORT
      LAYER Metal2 ;
        RECT 46.360 1218.840 46.760 1219.240 ;
    END
  END Tile_X0Y0_N2BEGb[1]
  PIN Tile_X0Y0_N2BEGb[2]
    DIRECTION OUTPUT ;
    USE SIGNAL ;
    ANTENNADIFFAREA 0.708600 ;
    PORT
      LAYER Metal2 ;
        RECT 48.280 1218.840 48.680 1219.240 ;
    END
  END Tile_X0Y0_N2BEGb[2]
  PIN Tile_X0Y0_N2BEGb[3]
    DIRECTION OUTPUT ;
    USE SIGNAL ;
    ANTENNADIFFAREA 0.708600 ;
    PORT
      LAYER Metal2 ;
        RECT 50.200 1218.840 50.600 1219.240 ;
    END
  END Tile_X0Y0_N2BEGb[3]
  PIN Tile_X0Y0_N2BEGb[4]
    DIRECTION OUTPUT ;
    USE SIGNAL ;
    ANTENNADIFFAREA 0.708600 ;
    PORT
      LAYER Metal2 ;
        RECT 52.120 1218.840 52.520 1219.240 ;
    END
  END Tile_X0Y0_N2BEGb[4]
  PIN Tile_X0Y0_N2BEGb[5]
    DIRECTION OUTPUT ;
    USE SIGNAL ;
    ANTENNADIFFAREA 0.708600 ;
    PORT
      LAYER Metal2 ;
        RECT 54.040 1218.840 54.440 1219.240 ;
    END
  END Tile_X0Y0_N2BEGb[5]
  PIN Tile_X0Y0_N2BEGb[6]
    DIRECTION OUTPUT ;
    USE SIGNAL ;
    ANTENNADIFFAREA 0.708600 ;
    PORT
      LAYER Metal2 ;
        RECT 55.960 1218.840 56.360 1219.240 ;
    END
  END Tile_X0Y0_N2BEGb[6]
  PIN Tile_X0Y0_N2BEGb[7]
    DIRECTION OUTPUT ;
    USE SIGNAL ;
    ANTENNADIFFAREA 0.708600 ;
    PORT
      LAYER Metal2 ;
        RECT 57.880 1218.840 58.280 1219.240 ;
    END
  END Tile_X0Y0_N2BEGb[7]
  PIN Tile_X0Y0_N4BEG[0]
    DIRECTION OUTPUT ;
    USE SIGNAL ;
    ANTENNADIFFAREA 0.708600 ;
    PORT
      LAYER Metal2 ;
        RECT 59.800 1218.840 60.200 1219.240 ;
    END
  END Tile_X0Y0_N4BEG[0]
  PIN Tile_X0Y0_N4BEG[10]
    DIRECTION OUTPUT ;
    USE SIGNAL ;
    ANTENNADIFFAREA 0.708600 ;
    PORT
      LAYER Metal2 ;
        RECT 79.000 1218.840 79.400 1219.240 ;
    END
  END Tile_X0Y0_N4BEG[10]
  PIN Tile_X0Y0_N4BEG[11]
    DIRECTION OUTPUT ;
    USE SIGNAL ;
    ANTENNADIFFAREA 0.708600 ;
    PORT
      LAYER Metal2 ;
        RECT 80.920 1218.840 81.320 1219.240 ;
    END
  END Tile_X0Y0_N4BEG[11]
  PIN Tile_X0Y0_N4BEG[12]
    DIRECTION OUTPUT ;
    USE SIGNAL ;
    ANTENNADIFFAREA 0.708600 ;
    PORT
      LAYER Metal2 ;
        RECT 82.840 1218.840 83.240 1219.240 ;
    END
  END Tile_X0Y0_N4BEG[12]
  PIN Tile_X0Y0_N4BEG[13]
    DIRECTION OUTPUT ;
    USE SIGNAL ;
    ANTENNADIFFAREA 0.708600 ;
    PORT
      LAYER Metal2 ;
        RECT 84.760 1218.840 85.160 1219.240 ;
    END
  END Tile_X0Y0_N4BEG[13]
  PIN Tile_X0Y0_N4BEG[14]
    DIRECTION OUTPUT ;
    USE SIGNAL ;
    ANTENNADIFFAREA 0.708600 ;
    PORT
      LAYER Metal2 ;
        RECT 86.680 1218.840 87.080 1219.240 ;
    END
  END Tile_X0Y0_N4BEG[14]
  PIN Tile_X0Y0_N4BEG[15]
    DIRECTION OUTPUT ;
    USE SIGNAL ;
    ANTENNADIFFAREA 0.708600 ;
    PORT
      LAYER Metal2 ;
        RECT 88.600 1218.840 89.000 1219.240 ;
    END
  END Tile_X0Y0_N4BEG[15]
  PIN Tile_X0Y0_N4BEG[1]
    DIRECTION OUTPUT ;
    USE SIGNAL ;
    ANTENNADIFFAREA 0.708600 ;
    PORT
      LAYER Metal2 ;
        RECT 61.720 1218.840 62.120 1219.240 ;
    END
  END Tile_X0Y0_N4BEG[1]
  PIN Tile_X0Y0_N4BEG[2]
    DIRECTION OUTPUT ;
    USE SIGNAL ;
    ANTENNADIFFAREA 0.708600 ;
    PORT
      LAYER Metal2 ;
        RECT 63.640 1218.840 64.040 1219.240 ;
    END
  END Tile_X0Y0_N4BEG[2]
  PIN Tile_X0Y0_N4BEG[3]
    DIRECTION OUTPUT ;
    USE SIGNAL ;
    ANTENNADIFFAREA 0.708600 ;
    PORT
      LAYER Metal2 ;
        RECT 65.560 1218.840 65.960 1219.240 ;
    END
  END Tile_X0Y0_N4BEG[3]
  PIN Tile_X0Y0_N4BEG[4]
    DIRECTION OUTPUT ;
    USE SIGNAL ;
    ANTENNADIFFAREA 0.708600 ;
    PORT
      LAYER Metal2 ;
        RECT 67.480 1218.840 67.880 1219.240 ;
    END
  END Tile_X0Y0_N4BEG[4]
  PIN Tile_X0Y0_N4BEG[5]
    DIRECTION OUTPUT ;
    USE SIGNAL ;
    ANTENNADIFFAREA 0.708600 ;
    PORT
      LAYER Metal2 ;
        RECT 69.400 1218.840 69.800 1219.240 ;
    END
  END Tile_X0Y0_N4BEG[5]
  PIN Tile_X0Y0_N4BEG[6]
    DIRECTION OUTPUT ;
    USE SIGNAL ;
    ANTENNADIFFAREA 0.708600 ;
    PORT
      LAYER Metal2 ;
        RECT 71.320 1218.840 71.720 1219.240 ;
    END
  END Tile_X0Y0_N4BEG[6]
  PIN Tile_X0Y0_N4BEG[7]
    DIRECTION OUTPUT ;
    USE SIGNAL ;
    ANTENNADIFFAREA 0.708600 ;
    PORT
      LAYER Metal2 ;
        RECT 73.240 1218.840 73.640 1219.240 ;
    END
  END Tile_X0Y0_N4BEG[7]
  PIN Tile_X0Y0_N4BEG[8]
    DIRECTION OUTPUT ;
    USE SIGNAL ;
    ANTENNADIFFAREA 0.708600 ;
    PORT
      LAYER Metal2 ;
        RECT 75.160 1218.840 75.560 1219.240 ;
    END
  END Tile_X0Y0_N4BEG[8]
  PIN Tile_X0Y0_N4BEG[9]
    DIRECTION OUTPUT ;
    USE SIGNAL ;
    ANTENNADIFFAREA 0.708600 ;
    PORT
      LAYER Metal2 ;
        RECT 77.080 1218.840 77.480 1219.240 ;
    END
  END Tile_X0Y0_N4BEG[9]
  PIN Tile_X0Y0_S1END[0]
    DIRECTION INPUT ;
    USE SIGNAL ;
    ANTENNAGATEAREA 1.307800 ;
    PORT
      LAYER Metal2 ;
        RECT 90.520 1218.840 90.920 1219.240 ;
    END
  END Tile_X0Y0_S1END[0]
  PIN Tile_X0Y0_S1END[1]
    DIRECTION INPUT ;
    USE SIGNAL ;
    ANTENNAGATEAREA 1.307800 ;
    PORT
      LAYER Metal2 ;
        RECT 92.440 1218.840 92.840 1219.240 ;
    END
  END Tile_X0Y0_S1END[1]
  PIN Tile_X0Y0_S1END[2]
    DIRECTION INPUT ;
    USE SIGNAL ;
    ANTENNAGATEAREA 1.307800 ;
    PORT
      LAYER Metal2 ;
        RECT 94.360 1218.840 94.760 1219.240 ;
    END
  END Tile_X0Y0_S1END[2]
  PIN Tile_X0Y0_S1END[3]
    DIRECTION INPUT ;
    USE SIGNAL ;
    ANTENNAGATEAREA 1.307800 ;
    PORT
      LAYER Metal2 ;
        RECT 96.280 1218.840 96.680 1219.240 ;
    END
  END Tile_X0Y0_S1END[3]
  PIN Tile_X0Y0_S2END[0]
    DIRECTION INPUT ;
    USE SIGNAL ;
    ANTENNAGATEAREA 0.213200 ;
    PORT
      LAYER Metal2 ;
        RECT 113.560 1218.840 113.960 1219.240 ;
    END
  END Tile_X0Y0_S2END[0]
  PIN Tile_X0Y0_S2END[1]
    DIRECTION INPUT ;
    USE SIGNAL ;
    ANTENNAGATEAREA 0.213200 ;
    PORT
      LAYER Metal2 ;
        RECT 115.480 1218.840 115.880 1219.240 ;
    END
  END Tile_X0Y0_S2END[1]
  PIN Tile_X0Y0_S2END[2]
    DIRECTION INPUT ;
    USE SIGNAL ;
    ANTENNAGATEAREA 0.213200 ;
    PORT
      LAYER Metal2 ;
        RECT 117.400 1218.840 117.800 1219.240 ;
    END
  END Tile_X0Y0_S2END[2]
  PIN Tile_X0Y0_S2END[3]
    DIRECTION INPUT ;
    USE SIGNAL ;
    ANTENNAGATEAREA 0.213200 ;
    PORT
      LAYER Metal2 ;
        RECT 119.320 1218.840 119.720 1219.240 ;
    END
  END Tile_X0Y0_S2END[3]
  PIN Tile_X0Y0_S2END[4]
    DIRECTION INPUT ;
    USE SIGNAL ;
    ANTENNAGATEAREA 0.213200 ;
    PORT
      LAYER Metal2 ;
        RECT 121.240 1218.840 121.640 1219.240 ;
    END
  END Tile_X0Y0_S2END[4]
  PIN Tile_X0Y0_S2END[5]
    DIRECTION INPUT ;
    USE SIGNAL ;
    ANTENNAGATEAREA 0.213200 ;
    PORT
      LAYER Metal2 ;
        RECT 123.160 1218.840 123.560 1219.240 ;
    END
  END Tile_X0Y0_S2END[5]
  PIN Tile_X0Y0_S2END[6]
    DIRECTION INPUT ;
    USE SIGNAL ;
    ANTENNAGATEAREA 0.213200 ;
    PORT
      LAYER Metal2 ;
        RECT 125.080 1218.840 125.480 1219.240 ;
    END
  END Tile_X0Y0_S2END[6]
  PIN Tile_X0Y0_S2END[7]
    DIRECTION INPUT ;
    USE SIGNAL ;
    ANTENNAGATEAREA 0.213200 ;
    PORT
      LAYER Metal2 ;
        RECT 127.000 1218.840 127.400 1219.240 ;
    END
  END Tile_X0Y0_S2END[7]
  PIN Tile_X0Y0_S2MID[0]
    DIRECTION INPUT ;
    USE SIGNAL ;
    ANTENNAGATEAREA 0.426400 ;
    PORT
      LAYER Metal2 ;
        RECT 98.200 1218.840 98.600 1219.240 ;
    END
  END Tile_X0Y0_S2MID[0]
  PIN Tile_X0Y0_S2MID[1]
    DIRECTION INPUT ;
    USE SIGNAL ;
    ANTENNAGATEAREA 0.426400 ;
    ANTENNADIFFAREA 4.030800 ;
    PORT
      LAYER Metal2 ;
        RECT 100.120 1218.840 100.520 1219.240 ;
    END
  END Tile_X0Y0_S2MID[1]
  PIN Tile_X0Y0_S2MID[2]
    DIRECTION INPUT ;
    USE SIGNAL ;
    ANTENNAGATEAREA 0.426400 ;
    PORT
      LAYER Metal2 ;
        RECT 102.040 1218.840 102.440 1219.240 ;
    END
  END Tile_X0Y0_S2MID[2]
  PIN Tile_X0Y0_S2MID[3]
    DIRECTION INPUT ;
    USE SIGNAL ;
    ANTENNAGATEAREA 0.426400 ;
    PORT
      LAYER Metal2 ;
        RECT 103.960 1218.840 104.360 1219.240 ;
    END
  END Tile_X0Y0_S2MID[3]
  PIN Tile_X0Y0_S2MID[4]
    DIRECTION INPUT ;
    USE SIGNAL ;
    ANTENNAGATEAREA 0.426400 ;
    PORT
      LAYER Metal2 ;
        RECT 105.880 1218.840 106.280 1219.240 ;
    END
  END Tile_X0Y0_S2MID[4]
  PIN Tile_X0Y0_S2MID[5]
    DIRECTION INPUT ;
    USE SIGNAL ;
    ANTENNAGATEAREA 0.426400 ;
    PORT
      LAYER Metal2 ;
        RECT 107.800 1218.840 108.200 1219.240 ;
    END
  END Tile_X0Y0_S2MID[5]
  PIN Tile_X0Y0_S2MID[6]
    DIRECTION INPUT ;
    USE SIGNAL ;
    ANTENNAGATEAREA 0.426400 ;
    PORT
      LAYER Metal2 ;
        RECT 109.720 1218.840 110.120 1219.240 ;
    END
  END Tile_X0Y0_S2MID[6]
  PIN Tile_X0Y0_S2MID[7]
    DIRECTION INPUT ;
    USE SIGNAL ;
    ANTENNAGATEAREA 0.426400 ;
    ANTENNADIFFAREA 4.030800 ;
    PORT
      LAYER Metal2 ;
        RECT 111.640 1218.840 112.040 1219.240 ;
    END
  END Tile_X0Y0_S2MID[7]
  PIN Tile_X0Y0_S4END[0]
    DIRECTION INPUT ;
    USE SIGNAL ;
    ANTENNAGATEAREA 1.066000 ;
    PORT
      LAYER Metal2 ;
        RECT 128.920 1218.840 129.320 1219.240 ;
    END
  END Tile_X0Y0_S4END[0]
  PIN Tile_X0Y0_S4END[10]
    DIRECTION INPUT ;
    USE SIGNAL ;
    ANTENNAGATEAREA 1.066000 ;
    PORT
      LAYER Metal2 ;
        RECT 148.120 1218.840 148.520 1219.240 ;
    END
  END Tile_X0Y0_S4END[10]
  PIN Tile_X0Y0_S4END[11]
    DIRECTION INPUT ;
    USE SIGNAL ;
    ANTENNAGATEAREA 1.066000 ;
    PORT
      LAYER Metal2 ;
        RECT 150.040 1218.840 150.440 1219.240 ;
    END
  END Tile_X0Y0_S4END[11]
  PIN Tile_X0Y0_S4END[12]
    DIRECTION INPUT ;
    USE SIGNAL ;
    ANTENNAGATEAREA 1.066000 ;
    PORT
      LAYER Metal2 ;
        RECT 151.960 1218.840 152.360 1219.240 ;
    END
  END Tile_X0Y0_S4END[12]
  PIN Tile_X0Y0_S4END[13]
    DIRECTION INPUT ;
    USE SIGNAL ;
    ANTENNAGATEAREA 1.066000 ;
    PORT
      LAYER Metal2 ;
        RECT 153.880 1218.840 154.280 1219.240 ;
    END
  END Tile_X0Y0_S4END[13]
  PIN Tile_X0Y0_S4END[14]
    DIRECTION INPUT ;
    USE SIGNAL ;
    ANTENNAGATEAREA 1.066000 ;
    PORT
      LAYER Metal2 ;
        RECT 155.800 1218.840 156.200 1219.240 ;
    END
  END Tile_X0Y0_S4END[14]
  PIN Tile_X0Y0_S4END[15]
    DIRECTION INPUT ;
    USE SIGNAL ;
    ANTENNAGATEAREA 1.066000 ;
    PORT
      LAYER Metal2 ;
        RECT 157.720 1218.840 158.120 1219.240 ;
    END
  END Tile_X0Y0_S4END[15]
  PIN Tile_X0Y0_S4END[1]
    DIRECTION INPUT ;
    USE SIGNAL ;
    ANTENNAGATEAREA 1.066000 ;
    PORT
      LAYER Metal2 ;
        RECT 130.840 1218.840 131.240 1219.240 ;
    END
  END Tile_X0Y0_S4END[1]
  PIN Tile_X0Y0_S4END[2]
    DIRECTION INPUT ;
    USE SIGNAL ;
    ANTENNAGATEAREA 1.066000 ;
    PORT
      LAYER Metal2 ;
        RECT 132.760 1218.840 133.160 1219.240 ;
    END
  END Tile_X0Y0_S4END[2]
  PIN Tile_X0Y0_S4END[3]
    DIRECTION INPUT ;
    USE SIGNAL ;
    ANTENNAGATEAREA 1.066000 ;
    PORT
      LAYER Metal2 ;
        RECT 134.680 1218.840 135.080 1219.240 ;
    END
  END Tile_X0Y0_S4END[3]
  PIN Tile_X0Y0_S4END[4]
    DIRECTION INPUT ;
    USE SIGNAL ;
    ANTENNAGATEAREA 1.066000 ;
    PORT
      LAYER Metal2 ;
        RECT 136.600 1218.840 137.000 1219.240 ;
    END
  END Tile_X0Y0_S4END[4]
  PIN Tile_X0Y0_S4END[5]
    DIRECTION INPUT ;
    USE SIGNAL ;
    ANTENNAGATEAREA 1.066000 ;
    PORT
      LAYER Metal2 ;
        RECT 138.520 1218.840 138.920 1219.240 ;
    END
  END Tile_X0Y0_S4END[5]
  PIN Tile_X0Y0_S4END[6]
    DIRECTION INPUT ;
    USE SIGNAL ;
    ANTENNAGATEAREA 1.066000 ;
    PORT
      LAYER Metal2 ;
        RECT 140.440 1218.840 140.840 1219.240 ;
    END
  END Tile_X0Y0_S4END[6]
  PIN Tile_X0Y0_S4END[7]
    DIRECTION INPUT ;
    USE SIGNAL ;
    ANTENNAGATEAREA 1.066000 ;
    PORT
      LAYER Metal2 ;
        RECT 142.360 1218.840 142.760 1219.240 ;
    END
  END Tile_X0Y0_S4END[7]
  PIN Tile_X0Y0_S4END[8]
    DIRECTION INPUT ;
    USE SIGNAL ;
    ANTENNAGATEAREA 1.066000 ;
    PORT
      LAYER Metal2 ;
        RECT 144.280 1218.840 144.680 1219.240 ;
    END
  END Tile_X0Y0_S4END[8]
  PIN Tile_X0Y0_S4END[9]
    DIRECTION INPUT ;
    USE SIGNAL ;
    ANTENNAGATEAREA 1.066000 ;
    PORT
      LAYER Metal2 ;
        RECT 146.200 1218.840 146.600 1219.240 ;
    END
  END Tile_X0Y0_S4END[9]
  PIN Tile_X0Y0_UserCLKo
    DIRECTION OUTPUT ;
    USE SIGNAL ;
    ANTENNADIFFAREA 0.708600 ;
    PORT
      LAYER Metal2 ;
        RECT 198.040 1218.840 198.440 1219.240 ;
    END
  END Tile_X0Y0_UserCLKo
  PIN Tile_X0Y0_W1END[0]
    DIRECTION INPUT ;
    USE SIGNAL ;
    ANTENNAGATEAREA 1.279200 ;
    PORT
      LAYER Metal3 ;
        RECT 219.440 1064.080 219.840 1064.480 ;
    END
  END Tile_X0Y0_W1END[0]
  PIN Tile_X0Y0_W1END[1]
    DIRECTION INPUT ;
    USE SIGNAL ;
    ANTENNAGATEAREA 1.279200 ;
    PORT
      LAYER Metal3 ;
        RECT 219.440 1064.920 219.840 1065.320 ;
    END
  END Tile_X0Y0_W1END[1]
  PIN Tile_X0Y0_W1END[2]
    DIRECTION INPUT ;
    USE SIGNAL ;
    ANTENNAGATEAREA 1.279200 ;
    PORT
      LAYER Metal3 ;
        RECT 219.440 1065.760 219.840 1066.160 ;
    END
  END Tile_X0Y0_W1END[2]
  PIN Tile_X0Y0_W1END[3]
    DIRECTION INPUT ;
    USE SIGNAL ;
    ANTENNAGATEAREA 1.279200 ;
    PORT
      LAYER Metal3 ;
        RECT 219.440 1066.600 219.840 1067.000 ;
    END
  END Tile_X0Y0_W1END[3]
  PIN Tile_X0Y0_W2END[0]
    DIRECTION INPUT ;
    USE SIGNAL ;
    ANTENNAGATEAREA 0.852800 ;
    PORT
      LAYER Metal3 ;
        RECT 219.440 1074.160 219.840 1074.560 ;
    END
  END Tile_X0Y0_W2END[0]
  PIN Tile_X0Y0_W2END[1]
    DIRECTION INPUT ;
    USE SIGNAL ;
    ANTENNAGATEAREA 0.852800 ;
    PORT
      LAYER Metal3 ;
        RECT 219.440 1075.000 219.840 1075.400 ;
    END
  END Tile_X0Y0_W2END[1]
  PIN Tile_X0Y0_W2END[2]
    DIRECTION INPUT ;
    USE SIGNAL ;
    ANTENNAGATEAREA 0.852800 ;
    PORT
      LAYER Metal3 ;
        RECT 219.440 1075.840 219.840 1076.240 ;
    END
  END Tile_X0Y0_W2END[2]
  PIN Tile_X0Y0_W2END[3]
    DIRECTION INPUT ;
    USE SIGNAL ;
    ANTENNAGATEAREA 0.852800 ;
    PORT
      LAYER Metal3 ;
        RECT 219.440 1076.680 219.840 1077.080 ;
    END
  END Tile_X0Y0_W2END[3]
  PIN Tile_X0Y0_W2END[4]
    DIRECTION INPUT ;
    USE SIGNAL ;
    ANTENNAGATEAREA 0.852800 ;
    PORT
      LAYER Metal3 ;
        RECT 219.440 1077.520 219.840 1077.920 ;
    END
  END Tile_X0Y0_W2END[4]
  PIN Tile_X0Y0_W2END[5]
    DIRECTION INPUT ;
    USE SIGNAL ;
    ANTENNAGATEAREA 0.852800 ;
    PORT
      LAYER Metal3 ;
        RECT 219.440 1078.360 219.840 1078.760 ;
    END
  END Tile_X0Y0_W2END[5]
  PIN Tile_X0Y0_W2END[6]
    DIRECTION INPUT ;
    USE SIGNAL ;
    ANTENNAGATEAREA 0.852800 ;
    PORT
      LAYER Metal3 ;
        RECT 219.440 1079.200 219.840 1079.600 ;
    END
  END Tile_X0Y0_W2END[6]
  PIN Tile_X0Y0_W2END[7]
    DIRECTION INPUT ;
    USE SIGNAL ;
    ANTENNAGATEAREA 0.852800 ;
    PORT
      LAYER Metal3 ;
        RECT 219.440 1080.040 219.840 1080.440 ;
    END
  END Tile_X0Y0_W2END[7]
  PIN Tile_X0Y0_W2MID[0]
    DIRECTION INPUT ;
    USE SIGNAL ;
    ANTENNAGATEAREA 0.852800 ;
    PORT
      LAYER Metal3 ;
        RECT 219.440 1067.440 219.840 1067.840 ;
    END
  END Tile_X0Y0_W2MID[0]
  PIN Tile_X0Y0_W2MID[1]
    DIRECTION INPUT ;
    USE SIGNAL ;
    ANTENNAGATEAREA 0.852800 ;
    PORT
      LAYER Metal3 ;
        RECT 219.440 1068.280 219.840 1068.680 ;
    END
  END Tile_X0Y0_W2MID[1]
  PIN Tile_X0Y0_W2MID[2]
    DIRECTION INPUT ;
    USE SIGNAL ;
    ANTENNAGATEAREA 0.852800 ;
    PORT
      LAYER Metal3 ;
        RECT 219.440 1069.120 219.840 1069.520 ;
    END
  END Tile_X0Y0_W2MID[2]
  PIN Tile_X0Y0_W2MID[3]
    DIRECTION INPUT ;
    USE SIGNAL ;
    ANTENNAGATEAREA 0.852800 ;
    PORT
      LAYER Metal3 ;
        RECT 219.440 1069.960 219.840 1070.360 ;
    END
  END Tile_X0Y0_W2MID[3]
  PIN Tile_X0Y0_W2MID[4]
    DIRECTION INPUT ;
    USE SIGNAL ;
    ANTENNAGATEAREA 0.852800 ;
    PORT
      LAYER Metal3 ;
        RECT 219.440 1070.800 219.840 1071.200 ;
    END
  END Tile_X0Y0_W2MID[4]
  PIN Tile_X0Y0_W2MID[5]
    DIRECTION INPUT ;
    USE SIGNAL ;
    ANTENNAGATEAREA 0.852800 ;
    PORT
      LAYER Metal3 ;
        RECT 219.440 1071.640 219.840 1072.040 ;
    END
  END Tile_X0Y0_W2MID[5]
  PIN Tile_X0Y0_W2MID[6]
    DIRECTION INPUT ;
    USE SIGNAL ;
    ANTENNAGATEAREA 0.852800 ;
    PORT
      LAYER Metal3 ;
        RECT 219.440 1072.480 219.840 1072.880 ;
    END
  END Tile_X0Y0_W2MID[6]
  PIN Tile_X0Y0_W2MID[7]
    DIRECTION INPUT ;
    USE SIGNAL ;
    ANTENNAGATEAREA 0.852800 ;
    PORT
      LAYER Metal3 ;
        RECT 219.440 1073.320 219.840 1073.720 ;
    END
  END Tile_X0Y0_W2MID[7]
  PIN Tile_X0Y0_W6END[0]
    DIRECTION INPUT ;
    USE SIGNAL ;
    ANTENNAGATEAREA 0.881400 ;
    PORT
      LAYER Metal3 ;
        RECT 219.440 1094.320 219.840 1094.720 ;
    END
  END Tile_X0Y0_W6END[0]
  PIN Tile_X0Y0_W6END[10]
    DIRECTION INPUT ;
    USE SIGNAL ;
    ANTENNAGATEAREA 0.852800 ;
    PORT
      LAYER Metal3 ;
        RECT 219.440 1102.720 219.840 1103.120 ;
    END
  END Tile_X0Y0_W6END[10]
  PIN Tile_X0Y0_W6END[11]
    DIRECTION INPUT ;
    USE SIGNAL ;
    ANTENNAGATEAREA 0.852800 ;
    PORT
      LAYER Metal3 ;
        RECT 219.440 1103.560 219.840 1103.960 ;
    END
  END Tile_X0Y0_W6END[11]
  PIN Tile_X0Y0_W6END[1]
    DIRECTION INPUT ;
    USE SIGNAL ;
    ANTENNAGATEAREA 0.881400 ;
    PORT
      LAYER Metal3 ;
        RECT 219.440 1095.160 219.840 1095.560 ;
    END
  END Tile_X0Y0_W6END[1]
  PIN Tile_X0Y0_W6END[2]
    DIRECTION INPUT ;
    USE SIGNAL ;
    ANTENNAGATEAREA 0.881400 ;
    PORT
      LAYER Metal3 ;
        RECT 219.440 1096.000 219.840 1096.400 ;
    END
  END Tile_X0Y0_W6END[2]
  PIN Tile_X0Y0_W6END[3]
    DIRECTION INPUT ;
    USE SIGNAL ;
    ANTENNAGATEAREA 0.881400 ;
    PORT
      LAYER Metal3 ;
        RECT 219.440 1096.840 219.840 1097.240 ;
    END
  END Tile_X0Y0_W6END[3]
  PIN Tile_X0Y0_W6END[4]
    DIRECTION INPUT ;
    USE SIGNAL ;
    ANTENNAGATEAREA 1.066000 ;
    PORT
      LAYER Metal3 ;
        RECT 219.440 1097.680 219.840 1098.080 ;
    END
  END Tile_X0Y0_W6END[4]
  PIN Tile_X0Y0_W6END[5]
    DIRECTION INPUT ;
    USE SIGNAL ;
    ANTENNAGATEAREA 1.066000 ;
    PORT
      LAYER Metal3 ;
        RECT 219.440 1098.520 219.840 1098.920 ;
    END
  END Tile_X0Y0_W6END[5]
  PIN Tile_X0Y0_W6END[6]
    DIRECTION INPUT ;
    USE SIGNAL ;
    ANTENNAGATEAREA 1.066000 ;
    PORT
      LAYER Metal3 ;
        RECT 219.440 1099.360 219.840 1099.760 ;
    END
  END Tile_X0Y0_W6END[6]
  PIN Tile_X0Y0_W6END[7]
    DIRECTION INPUT ;
    USE SIGNAL ;
    ANTENNAGATEAREA 1.066000 ;
    PORT
      LAYER Metal3 ;
        RECT 219.440 1100.200 219.840 1100.600 ;
    END
  END Tile_X0Y0_W6END[7]
  PIN Tile_X0Y0_W6END[8]
    DIRECTION INPUT ;
    USE SIGNAL ;
    ANTENNAGATEAREA 0.852800 ;
    PORT
      LAYER Metal3 ;
        RECT 219.440 1101.040 219.840 1101.440 ;
    END
  END Tile_X0Y0_W6END[8]
  PIN Tile_X0Y0_W6END[9]
    DIRECTION INPUT ;
    USE SIGNAL ;
    ANTENNAGATEAREA 0.852800 ;
    PORT
      LAYER Metal3 ;
        RECT 219.440 1101.880 219.840 1102.280 ;
    END
  END Tile_X0Y0_W6END[9]
  PIN Tile_X0Y0_WW4END[0]
    DIRECTION INPUT ;
    USE SIGNAL ;
    ANTENNAGATEAREA 0.852800 ;
    PORT
      LAYER Metal3 ;
        RECT 219.440 1080.880 219.840 1081.280 ;
    END
  END Tile_X0Y0_WW4END[0]
  PIN Tile_X0Y0_WW4END[10]
    DIRECTION INPUT ;
    USE SIGNAL ;
    ANTENNAGATEAREA 0.639600 ;
    PORT
      LAYER Metal3 ;
        RECT 219.440 1089.280 219.840 1089.680 ;
    END
  END Tile_X0Y0_WW4END[10]
  PIN Tile_X0Y0_WW4END[11]
    DIRECTION INPUT ;
    USE SIGNAL ;
    ANTENNAGATEAREA 0.639600 ;
    PORT
      LAYER Metal3 ;
        RECT 219.440 1090.120 219.840 1090.520 ;
    END
  END Tile_X0Y0_WW4END[11]
  PIN Tile_X0Y0_WW4END[12]
    DIRECTION INPUT ;
    USE SIGNAL ;
    ANTENNAGATEAREA 0.852800 ;
    PORT
      LAYER Metal3 ;
        RECT 219.440 1090.960 219.840 1091.360 ;
    END
  END Tile_X0Y0_WW4END[12]
  PIN Tile_X0Y0_WW4END[13]
    DIRECTION INPUT ;
    USE SIGNAL ;
    ANTENNAGATEAREA 0.852800 ;
    PORT
      LAYER Metal3 ;
        RECT 219.440 1091.800 219.840 1092.200 ;
    END
  END Tile_X0Y0_WW4END[13]
  PIN Tile_X0Y0_WW4END[14]
    DIRECTION INPUT ;
    USE SIGNAL ;
    ANTENNAGATEAREA 0.852800 ;
    PORT
      LAYER Metal3 ;
        RECT 219.440 1092.640 219.840 1093.040 ;
    END
  END Tile_X0Y0_WW4END[14]
  PIN Tile_X0Y0_WW4END[15]
    DIRECTION INPUT ;
    USE SIGNAL ;
    ANTENNAGATEAREA 0.852800 ;
    PORT
      LAYER Metal3 ;
        RECT 219.440 1093.480 219.840 1093.880 ;
    END
  END Tile_X0Y0_WW4END[15]
  PIN Tile_X0Y0_WW4END[1]
    DIRECTION INPUT ;
    USE SIGNAL ;
    ANTENNAGATEAREA 0.852800 ;
    PORT
      LAYER Metal3 ;
        RECT 219.440 1081.720 219.840 1082.120 ;
    END
  END Tile_X0Y0_WW4END[1]
  PIN Tile_X0Y0_WW4END[2]
    DIRECTION INPUT ;
    USE SIGNAL ;
    ANTENNAGATEAREA 0.852800 ;
    PORT
      LAYER Metal3 ;
        RECT 219.440 1082.560 219.840 1082.960 ;
    END
  END Tile_X0Y0_WW4END[2]
  PIN Tile_X0Y0_WW4END[3]
    DIRECTION INPUT ;
    USE SIGNAL ;
    ANTENNAGATEAREA 0.852800 ;
    PORT
      LAYER Metal3 ;
        RECT 219.440 1083.400 219.840 1083.800 ;
    END
  END Tile_X0Y0_WW4END[3]
  PIN Tile_X0Y0_WW4END[4]
    DIRECTION INPUT ;
    USE SIGNAL ;
    ANTENNAGATEAREA 0.639600 ;
    PORT
      LAYER Metal3 ;
        RECT 219.440 1084.240 219.840 1084.640 ;
    END
  END Tile_X0Y0_WW4END[4]
  PIN Tile_X0Y0_WW4END[5]
    DIRECTION INPUT ;
    USE SIGNAL ;
    ANTENNAGATEAREA 0.639600 ;
    PORT
      LAYER Metal3 ;
        RECT 219.440 1085.080 219.840 1085.480 ;
    END
  END Tile_X0Y0_WW4END[5]
  PIN Tile_X0Y0_WW4END[6]
    DIRECTION INPUT ;
    USE SIGNAL ;
    ANTENNAGATEAREA 0.639600 ;
    PORT
      LAYER Metal3 ;
        RECT 219.440 1085.920 219.840 1086.320 ;
    END
  END Tile_X0Y0_WW4END[6]
  PIN Tile_X0Y0_WW4END[7]
    DIRECTION INPUT ;
    USE SIGNAL ;
    ANTENNAGATEAREA 0.639600 ;
    PORT
      LAYER Metal3 ;
        RECT 219.440 1086.760 219.840 1087.160 ;
    END
  END Tile_X0Y0_WW4END[7]
  PIN Tile_X0Y0_WW4END[8]
    DIRECTION INPUT ;
    USE SIGNAL ;
    ANTENNAGATEAREA 0.639600 ;
    PORT
      LAYER Metal3 ;
        RECT 219.440 1087.600 219.840 1088.000 ;
    END
  END Tile_X0Y0_WW4END[8]
  PIN Tile_X0Y0_WW4END[9]
    DIRECTION INPUT ;
    USE SIGNAL ;
    ANTENNAGATEAREA 0.639600 ;
    PORT
      LAYER Metal3 ;
        RECT 219.440 1088.440 219.840 1088.840 ;
    END
  END Tile_X0Y0_WW4END[9]
  PIN Tile_X0Y1_E1BEG[0]
    DIRECTION OUTPUT ;
    USE SIGNAL ;
    ANTENNADIFFAREA 0.708600 ;
    PORT
      LAYER Metal3 ;
        RECT 219.440 901.120 219.840 901.520 ;
    END
  END Tile_X0Y1_E1BEG[0]
  PIN Tile_X0Y1_E1BEG[1]
    DIRECTION OUTPUT ;
    USE SIGNAL ;
    ANTENNADIFFAREA 0.708600 ;
    PORT
      LAYER Metal3 ;
        RECT 219.440 901.960 219.840 902.360 ;
    END
  END Tile_X0Y1_E1BEG[1]
  PIN Tile_X0Y1_E1BEG[2]
    DIRECTION OUTPUT ;
    USE SIGNAL ;
    ANTENNADIFFAREA 0.708600 ;
    PORT
      LAYER Metal3 ;
        RECT 219.440 902.800 219.840 903.200 ;
    END
  END Tile_X0Y1_E1BEG[2]
  PIN Tile_X0Y1_E1BEG[3]
    DIRECTION OUTPUT ;
    USE SIGNAL ;
    ANTENNADIFFAREA 0.708600 ;
    PORT
      LAYER Metal3 ;
        RECT 219.440 903.640 219.840 904.040 ;
    END
  END Tile_X0Y1_E1BEG[3]
  PIN Tile_X0Y1_E2BEG[0]
    DIRECTION OUTPUT ;
    USE SIGNAL ;
    ANTENNADIFFAREA 0.708600 ;
    PORT
      LAYER Metal3 ;
        RECT 219.440 904.480 219.840 904.880 ;
    END
  END Tile_X0Y1_E2BEG[0]
  PIN Tile_X0Y1_E2BEG[1]
    DIRECTION OUTPUT ;
    USE SIGNAL ;
    ANTENNADIFFAREA 0.708600 ;
    PORT
      LAYER Metal3 ;
        RECT 219.440 905.320 219.840 905.720 ;
    END
  END Tile_X0Y1_E2BEG[1]
  PIN Tile_X0Y1_E2BEG[2]
    DIRECTION OUTPUT ;
    USE SIGNAL ;
    ANTENNADIFFAREA 0.708600 ;
    PORT
      LAYER Metal3 ;
        RECT 219.440 906.160 219.840 906.560 ;
    END
  END Tile_X0Y1_E2BEG[2]
  PIN Tile_X0Y1_E2BEG[3]
    DIRECTION OUTPUT ;
    USE SIGNAL ;
    ANTENNADIFFAREA 0.708600 ;
    PORT
      LAYER Metal3 ;
        RECT 219.440 907.000 219.840 907.400 ;
    END
  END Tile_X0Y1_E2BEG[3]
  PIN Tile_X0Y1_E2BEG[4]
    DIRECTION OUTPUT ;
    USE SIGNAL ;
    ANTENNADIFFAREA 0.708600 ;
    PORT
      LAYER Metal3 ;
        RECT 219.440 907.840 219.840 908.240 ;
    END
  END Tile_X0Y1_E2BEG[4]
  PIN Tile_X0Y1_E2BEG[5]
    DIRECTION OUTPUT ;
    USE SIGNAL ;
    ANTENNADIFFAREA 0.708600 ;
    PORT
      LAYER Metal3 ;
        RECT 219.440 908.680 219.840 909.080 ;
    END
  END Tile_X0Y1_E2BEG[5]
  PIN Tile_X0Y1_E2BEG[6]
    DIRECTION OUTPUT ;
    USE SIGNAL ;
    ANTENNADIFFAREA 0.708600 ;
    PORT
      LAYER Metal3 ;
        RECT 219.440 909.520 219.840 909.920 ;
    END
  END Tile_X0Y1_E2BEG[6]
  PIN Tile_X0Y1_E2BEG[7]
    DIRECTION OUTPUT ;
    USE SIGNAL ;
    ANTENNADIFFAREA 0.708600 ;
    PORT
      LAYER Metal3 ;
        RECT 219.440 910.360 219.840 910.760 ;
    END
  END Tile_X0Y1_E2BEG[7]
  PIN Tile_X0Y1_E2BEGb[0]
    DIRECTION OUTPUT ;
    USE SIGNAL ;
    ANTENNADIFFAREA 0.708600 ;
    PORT
      LAYER Metal3 ;
        RECT 219.440 911.200 219.840 911.600 ;
    END
  END Tile_X0Y1_E2BEGb[0]
  PIN Tile_X0Y1_E2BEGb[1]
    DIRECTION OUTPUT ;
    USE SIGNAL ;
    ANTENNADIFFAREA 0.708600 ;
    PORT
      LAYER Metal3 ;
        RECT 219.440 912.040 219.840 912.440 ;
    END
  END Tile_X0Y1_E2BEGb[1]
  PIN Tile_X0Y1_E2BEGb[2]
    DIRECTION OUTPUT ;
    USE SIGNAL ;
    ANTENNADIFFAREA 0.708600 ;
    PORT
      LAYER Metal3 ;
        RECT 219.440 912.880 219.840 913.280 ;
    END
  END Tile_X0Y1_E2BEGb[2]
  PIN Tile_X0Y1_E2BEGb[3]
    DIRECTION OUTPUT ;
    USE SIGNAL ;
    ANTENNADIFFAREA 0.708600 ;
    PORT
      LAYER Metal3 ;
        RECT 219.440 913.720 219.840 914.120 ;
    END
  END Tile_X0Y1_E2BEGb[3]
  PIN Tile_X0Y1_E2BEGb[4]
    DIRECTION OUTPUT ;
    USE SIGNAL ;
    ANTENNADIFFAREA 0.708600 ;
    PORT
      LAYER Metal3 ;
        RECT 219.440 914.560 219.840 914.960 ;
    END
  END Tile_X0Y1_E2BEGb[4]
  PIN Tile_X0Y1_E2BEGb[5]
    DIRECTION OUTPUT ;
    USE SIGNAL ;
    ANTENNADIFFAREA 0.708600 ;
    PORT
      LAYER Metal3 ;
        RECT 219.440 915.400 219.840 915.800 ;
    END
  END Tile_X0Y1_E2BEGb[5]
  PIN Tile_X0Y1_E2BEGb[6]
    DIRECTION OUTPUT ;
    USE SIGNAL ;
    ANTENNADIFFAREA 0.708600 ;
    PORT
      LAYER Metal3 ;
        RECT 219.440 916.240 219.840 916.640 ;
    END
  END Tile_X0Y1_E2BEGb[6]
  PIN Tile_X0Y1_E2BEGb[7]
    DIRECTION OUTPUT ;
    USE SIGNAL ;
    ANTENNADIFFAREA 0.708600 ;
    PORT
      LAYER Metal3 ;
        RECT 219.440 917.080 219.840 917.480 ;
    END
  END Tile_X0Y1_E2BEGb[7]
  PIN Tile_X0Y1_E6BEG[0]
    DIRECTION OUTPUT ;
    USE SIGNAL ;
    ANTENNADIFFAREA 0.708600 ;
    PORT
      LAYER Metal3 ;
        RECT 219.440 931.360 219.840 931.760 ;
    END
  END Tile_X0Y1_E6BEG[0]
  PIN Tile_X0Y1_E6BEG[10]
    DIRECTION OUTPUT ;
    USE SIGNAL ;
    ANTENNADIFFAREA 0.708600 ;
    PORT
      LAYER Metal3 ;
        RECT 219.440 939.760 219.840 940.160 ;
    END
  END Tile_X0Y1_E6BEG[10]
  PIN Tile_X0Y1_E6BEG[11]
    DIRECTION OUTPUT ;
    USE SIGNAL ;
    ANTENNADIFFAREA 0.708600 ;
    PORT
      LAYER Metal3 ;
        RECT 219.440 940.600 219.840 941.000 ;
    END
  END Tile_X0Y1_E6BEG[11]
  PIN Tile_X0Y1_E6BEG[1]
    DIRECTION OUTPUT ;
    USE SIGNAL ;
    ANTENNADIFFAREA 0.708600 ;
    PORT
      LAYER Metal3 ;
        RECT 219.440 932.200 219.840 932.600 ;
    END
  END Tile_X0Y1_E6BEG[1]
  PIN Tile_X0Y1_E6BEG[2]
    DIRECTION OUTPUT ;
    USE SIGNAL ;
    ANTENNADIFFAREA 0.708600 ;
    PORT
      LAYER Metal3 ;
        RECT 219.440 933.040 219.840 933.440 ;
    END
  END Tile_X0Y1_E6BEG[2]
  PIN Tile_X0Y1_E6BEG[3]
    DIRECTION OUTPUT ;
    USE SIGNAL ;
    ANTENNADIFFAREA 0.708600 ;
    PORT
      LAYER Metal3 ;
        RECT 219.440 933.880 219.840 934.280 ;
    END
  END Tile_X0Y1_E6BEG[3]
  PIN Tile_X0Y1_E6BEG[4]
    DIRECTION OUTPUT ;
    USE SIGNAL ;
    ANTENNADIFFAREA 0.708600 ;
    PORT
      LAYER Metal3 ;
        RECT 219.440 934.720 219.840 935.120 ;
    END
  END Tile_X0Y1_E6BEG[4]
  PIN Tile_X0Y1_E6BEG[5]
    DIRECTION OUTPUT ;
    USE SIGNAL ;
    ANTENNADIFFAREA 0.708600 ;
    PORT
      LAYER Metal3 ;
        RECT 219.440 935.560 219.840 935.960 ;
    END
  END Tile_X0Y1_E6BEG[5]
  PIN Tile_X0Y1_E6BEG[6]
    DIRECTION OUTPUT ;
    USE SIGNAL ;
    ANTENNADIFFAREA 0.708600 ;
    PORT
      LAYER Metal3 ;
        RECT 219.440 936.400 219.840 936.800 ;
    END
  END Tile_X0Y1_E6BEG[6]
  PIN Tile_X0Y1_E6BEG[7]
    DIRECTION OUTPUT ;
    USE SIGNAL ;
    ANTENNADIFFAREA 0.708600 ;
    PORT
      LAYER Metal3 ;
        RECT 219.440 937.240 219.840 937.640 ;
    END
  END Tile_X0Y1_E6BEG[7]
  PIN Tile_X0Y1_E6BEG[8]
    DIRECTION OUTPUT ;
    USE SIGNAL ;
    ANTENNADIFFAREA 0.708600 ;
    PORT
      LAYER Metal3 ;
        RECT 219.440 938.080 219.840 938.480 ;
    END
  END Tile_X0Y1_E6BEG[8]
  PIN Tile_X0Y1_E6BEG[9]
    DIRECTION OUTPUT ;
    USE SIGNAL ;
    ANTENNADIFFAREA 0.708600 ;
    PORT
      LAYER Metal3 ;
        RECT 219.440 938.920 219.840 939.320 ;
    END
  END Tile_X0Y1_E6BEG[9]
  PIN Tile_X0Y1_EE4BEG[0]
    DIRECTION OUTPUT ;
    USE SIGNAL ;
    ANTENNADIFFAREA 0.708600 ;
    PORT
      LAYER Metal3 ;
        RECT 219.440 917.920 219.840 918.320 ;
    END
  END Tile_X0Y1_EE4BEG[0]
  PIN Tile_X0Y1_EE4BEG[10]
    DIRECTION OUTPUT ;
    USE SIGNAL ;
    ANTENNADIFFAREA 0.708600 ;
    PORT
      LAYER Metal3 ;
        RECT 219.440 926.320 219.840 926.720 ;
    END
  END Tile_X0Y1_EE4BEG[10]
  PIN Tile_X0Y1_EE4BEG[11]
    DIRECTION OUTPUT ;
    USE SIGNAL ;
    ANTENNADIFFAREA 0.708600 ;
    PORT
      LAYER Metal3 ;
        RECT 219.440 927.160 219.840 927.560 ;
    END
  END Tile_X0Y1_EE4BEG[11]
  PIN Tile_X0Y1_EE4BEG[12]
    DIRECTION OUTPUT ;
    USE SIGNAL ;
    ANTENNADIFFAREA 0.708600 ;
    PORT
      LAYER Metal3 ;
        RECT 219.440 928.000 219.840 928.400 ;
    END
  END Tile_X0Y1_EE4BEG[12]
  PIN Tile_X0Y1_EE4BEG[13]
    DIRECTION OUTPUT ;
    USE SIGNAL ;
    ANTENNADIFFAREA 0.708600 ;
    PORT
      LAYER Metal3 ;
        RECT 219.440 928.840 219.840 929.240 ;
    END
  END Tile_X0Y1_EE4BEG[13]
  PIN Tile_X0Y1_EE4BEG[14]
    DIRECTION OUTPUT ;
    USE SIGNAL ;
    ANTENNADIFFAREA 0.708600 ;
    PORT
      LAYER Metal3 ;
        RECT 219.440 929.680 219.840 930.080 ;
    END
  END Tile_X0Y1_EE4BEG[14]
  PIN Tile_X0Y1_EE4BEG[15]
    DIRECTION OUTPUT ;
    USE SIGNAL ;
    ANTENNADIFFAREA 0.708600 ;
    PORT
      LAYER Metal3 ;
        RECT 219.440 930.520 219.840 930.920 ;
    END
  END Tile_X0Y1_EE4BEG[15]
  PIN Tile_X0Y1_EE4BEG[1]
    DIRECTION OUTPUT ;
    USE SIGNAL ;
    ANTENNADIFFAREA 0.708600 ;
    PORT
      LAYER Metal3 ;
        RECT 219.440 918.760 219.840 919.160 ;
    END
  END Tile_X0Y1_EE4BEG[1]
  PIN Tile_X0Y1_EE4BEG[2]
    DIRECTION OUTPUT ;
    USE SIGNAL ;
    ANTENNADIFFAREA 0.708600 ;
    PORT
      LAYER Metal3 ;
        RECT 219.440 919.600 219.840 920.000 ;
    END
  END Tile_X0Y1_EE4BEG[2]
  PIN Tile_X0Y1_EE4BEG[3]
    DIRECTION OUTPUT ;
    USE SIGNAL ;
    ANTENNADIFFAREA 0.708600 ;
    PORT
      LAYER Metal3 ;
        RECT 219.440 920.440 219.840 920.840 ;
    END
  END Tile_X0Y1_EE4BEG[3]
  PIN Tile_X0Y1_EE4BEG[4]
    DIRECTION OUTPUT ;
    USE SIGNAL ;
    ANTENNADIFFAREA 0.708600 ;
    PORT
      LAYER Metal3 ;
        RECT 219.440 921.280 219.840 921.680 ;
    END
  END Tile_X0Y1_EE4BEG[4]
  PIN Tile_X0Y1_EE4BEG[5]
    DIRECTION OUTPUT ;
    USE SIGNAL ;
    ANTENNADIFFAREA 0.708600 ;
    PORT
      LAYER Metal3 ;
        RECT 219.440 922.120 219.840 922.520 ;
    END
  END Tile_X0Y1_EE4BEG[5]
  PIN Tile_X0Y1_EE4BEG[6]
    DIRECTION OUTPUT ;
    USE SIGNAL ;
    ANTENNADIFFAREA 0.708600 ;
    PORT
      LAYER Metal3 ;
        RECT 219.440 922.960 219.840 923.360 ;
    END
  END Tile_X0Y1_EE4BEG[6]
  PIN Tile_X0Y1_EE4BEG[7]
    DIRECTION OUTPUT ;
    USE SIGNAL ;
    ANTENNADIFFAREA 0.708600 ;
    PORT
      LAYER Metal3 ;
        RECT 219.440 923.800 219.840 924.200 ;
    END
  END Tile_X0Y1_EE4BEG[7]
  PIN Tile_X0Y1_EE4BEG[8]
    DIRECTION OUTPUT ;
    USE SIGNAL ;
    ANTENNADIFFAREA 0.708600 ;
    PORT
      LAYER Metal3 ;
        RECT 219.440 924.640 219.840 925.040 ;
    END
  END Tile_X0Y1_EE4BEG[8]
  PIN Tile_X0Y1_EE4BEG[9]
    DIRECTION OUTPUT ;
    USE SIGNAL ;
    ANTENNADIFFAREA 0.708600 ;
    PORT
      LAYER Metal3 ;
        RECT 219.440 925.480 219.840 925.880 ;
    END
  END Tile_X0Y1_EE4BEG[9]
  PIN Tile_X0Y1_FrameData[0]
    DIRECTION INPUT ;
    USE SIGNAL ;
    ANTENNAGATEAREA 1.626300 ;
    PORT
      LAYER Metal3 ;
        RECT 0.000 879.280 0.400 879.680 ;
    END
  END Tile_X0Y1_FrameData[0]
  PIN Tile_X0Y1_FrameData[10]
    DIRECTION INPUT ;
    USE SIGNAL ;
    ANTENNAGATEAREA 1.626300 ;
    PORT
      LAYER Metal3 ;
        RECT 0.000 929.680 0.400 930.080 ;
    END
  END Tile_X0Y1_FrameData[10]
  PIN Tile_X0Y1_FrameData[11]
    DIRECTION INPUT ;
    USE SIGNAL ;
    ANTENNAGATEAREA 1.626300 ;
    PORT
      LAYER Metal3 ;
        RECT 0.000 934.720 0.400 935.120 ;
    END
  END Tile_X0Y1_FrameData[11]
  PIN Tile_X0Y1_FrameData[12]
    DIRECTION INPUT ;
    USE SIGNAL ;
    ANTENNAGATEAREA 1.626300 ;
    PORT
      LAYER Metal3 ;
        RECT 0.000 939.760 0.400 940.160 ;
    END
  END Tile_X0Y1_FrameData[12]
  PIN Tile_X0Y1_FrameData[13]
    DIRECTION INPUT ;
    USE SIGNAL ;
    ANTENNAGATEAREA 1.626300 ;
    PORT
      LAYER Metal3 ;
        RECT 0.000 944.800 0.400 945.200 ;
    END
  END Tile_X0Y1_FrameData[13]
  PIN Tile_X0Y1_FrameData[14]
    DIRECTION INPUT ;
    USE SIGNAL ;
    ANTENNAGATEAREA 1.626300 ;
    ANTENNADIFFAREA 20.153999 ;
    PORT
      LAYER Metal3 ;
        RECT 0.000 949.840 0.400 950.240 ;
    END
  END Tile_X0Y1_FrameData[14]
  PIN Tile_X0Y1_FrameData[15]
    DIRECTION INPUT ;
    USE SIGNAL ;
    ANTENNAGATEAREA 1.626300 ;
    PORT
      LAYER Metal3 ;
        RECT 0.000 954.880 0.400 955.280 ;
    END
  END Tile_X0Y1_FrameData[15]
  PIN Tile_X0Y1_FrameData[16]
    DIRECTION INPUT ;
    USE SIGNAL ;
    ANTENNAGATEAREA 1.807000 ;
    PORT
      LAYER Metal3 ;
        RECT 0.000 959.920 0.400 960.320 ;
    END
  END Tile_X0Y1_FrameData[16]
  PIN Tile_X0Y1_FrameData[17]
    DIRECTION INPUT ;
    USE SIGNAL ;
    ANTENNAGATEAREA 1.807000 ;
    PORT
      LAYER Metal3 ;
        RECT 0.000 964.960 0.400 965.360 ;
    END
  END Tile_X0Y1_FrameData[17]
  PIN Tile_X0Y1_FrameData[18]
    DIRECTION INPUT ;
    USE SIGNAL ;
    ANTENNAGATEAREA 1.807000 ;
    PORT
      LAYER Metal3 ;
        RECT 0.000 970.000 0.400 970.400 ;
    END
  END Tile_X0Y1_FrameData[18]
  PIN Tile_X0Y1_FrameData[19]
    DIRECTION INPUT ;
    USE SIGNAL ;
    ANTENNAGATEAREA 1.807000 ;
    PORT
      LAYER Metal3 ;
        RECT 0.000 975.040 0.400 975.440 ;
    END
  END Tile_X0Y1_FrameData[19]
  PIN Tile_X0Y1_FrameData[1]
    DIRECTION INPUT ;
    USE SIGNAL ;
    ANTENNAGATEAREA 1.626300 ;
    ANTENNADIFFAREA 20.153999 ;
    PORT
      LAYER Metal3 ;
        RECT 0.000 884.320 0.400 884.720 ;
    END
  END Tile_X0Y1_FrameData[1]
  PIN Tile_X0Y1_FrameData[20]
    DIRECTION INPUT ;
    USE SIGNAL ;
    ANTENNAGATEAREA 1.807000 ;
    PORT
      LAYER Metal3 ;
        RECT 0.000 980.080 0.400 980.480 ;
    END
  END Tile_X0Y1_FrameData[20]
  PIN Tile_X0Y1_FrameData[21]
    DIRECTION INPUT ;
    USE SIGNAL ;
    ANTENNAGATEAREA 1.807000 ;
    PORT
      LAYER Metal3 ;
        RECT 0.000 985.120 0.400 985.520 ;
    END
  END Tile_X0Y1_FrameData[21]
  PIN Tile_X0Y1_FrameData[22]
    DIRECTION INPUT ;
    USE SIGNAL ;
    ANTENNAGATEAREA 1.807000 ;
    PORT
      LAYER Metal3 ;
        RECT 0.000 990.160 0.400 990.560 ;
    END
  END Tile_X0Y1_FrameData[22]
  PIN Tile_X0Y1_FrameData[23]
    DIRECTION INPUT ;
    USE SIGNAL ;
    ANTENNAGATEAREA 1.807000 ;
    PORT
      LAYER Metal3 ;
        RECT 0.000 995.200 0.400 995.600 ;
    END
  END Tile_X0Y1_FrameData[23]
  PIN Tile_X0Y1_FrameData[24]
    DIRECTION INPUT ;
    USE SIGNAL ;
    ANTENNAGATEAREA 1.807000 ;
    PORT
      LAYER Metal3 ;
        RECT 0.000 1000.240 0.400 1000.640 ;
    END
  END Tile_X0Y1_FrameData[24]
  PIN Tile_X0Y1_FrameData[25]
    DIRECTION INPUT ;
    USE SIGNAL ;
    ANTENNAGATEAREA 1.807000 ;
    ANTENNADIFFAREA 22.169399 ;
    PORT
      LAYER Metal3 ;
        RECT 0.000 1005.280 0.400 1005.680 ;
    END
  END Tile_X0Y1_FrameData[25]
  PIN Tile_X0Y1_FrameData[26]
    DIRECTION INPUT ;
    USE SIGNAL ;
    ANTENNAGATEAREA 1.807000 ;
    PORT
      LAYER Metal3 ;
        RECT 0.000 1010.320 0.400 1010.720 ;
    END
  END Tile_X0Y1_FrameData[26]
  PIN Tile_X0Y1_FrameData[27]
    DIRECTION INPUT ;
    USE SIGNAL ;
    ANTENNAGATEAREA 1.807000 ;
    PORT
      LAYER Metal3 ;
        RECT 0.000 1015.360 0.400 1015.760 ;
    END
  END Tile_X0Y1_FrameData[27]
  PIN Tile_X0Y1_FrameData[28]
    DIRECTION INPUT ;
    USE SIGNAL ;
    ANTENNAGATEAREA 1.807000 ;
    PORT
      LAYER Metal3 ;
        RECT 0.000 1020.400 0.400 1020.800 ;
    END
  END Tile_X0Y1_FrameData[28]
  PIN Tile_X0Y1_FrameData[29]
    DIRECTION INPUT ;
    USE SIGNAL ;
    ANTENNAGATEAREA 1.807000 ;
    PORT
      LAYER Metal3 ;
        RECT 0.000 1025.440 0.400 1025.840 ;
    END
  END Tile_X0Y1_FrameData[29]
  PIN Tile_X0Y1_FrameData[2]
    DIRECTION INPUT ;
    USE SIGNAL ;
    ANTENNAGATEAREA 1.626300 ;
    PORT
      LAYER Metal3 ;
        RECT 0.000 889.360 0.400 889.760 ;
    END
  END Tile_X0Y1_FrameData[2]
  PIN Tile_X0Y1_FrameData[30]
    DIRECTION INPUT ;
    USE SIGNAL ;
    ANTENNAGATEAREA 1.807000 ;
    PORT
      LAYER Metal3 ;
        RECT 0.000 1030.480 0.400 1030.880 ;
    END
  END Tile_X0Y1_FrameData[30]
  PIN Tile_X0Y1_FrameData[31]
    DIRECTION INPUT ;
    USE SIGNAL ;
    ANTENNAGATEAREA 1.807000 ;
    PORT
      LAYER Metal3 ;
        RECT 0.000 1035.520 0.400 1035.920 ;
    END
  END Tile_X0Y1_FrameData[31]
  PIN Tile_X0Y1_FrameData[3]
    DIRECTION INPUT ;
    USE SIGNAL ;
    ANTENNAGATEAREA 1.626300 ;
    PORT
      LAYER Metal3 ;
        RECT 0.000 894.400 0.400 894.800 ;
    END
  END Tile_X0Y1_FrameData[3]
  PIN Tile_X0Y1_FrameData[4]
    DIRECTION INPUT ;
    USE SIGNAL ;
    ANTENNAGATEAREA 1.626300 ;
    PORT
      LAYER Metal3 ;
        RECT 0.000 899.440 0.400 899.840 ;
    END
  END Tile_X0Y1_FrameData[4]
  PIN Tile_X0Y1_FrameData[5]
    DIRECTION INPUT ;
    USE SIGNAL ;
    ANTENNAGATEAREA 1.626300 ;
    PORT
      LAYER Metal3 ;
        RECT 0.000 904.480 0.400 904.880 ;
    END
  END Tile_X0Y1_FrameData[5]
  PIN Tile_X0Y1_FrameData[6]
    DIRECTION INPUT ;
    USE SIGNAL ;
    ANTENNAGATEAREA 1.626300 ;
    PORT
      LAYER Metal3 ;
        RECT 0.000 909.520 0.400 909.920 ;
    END
  END Tile_X0Y1_FrameData[6]
  PIN Tile_X0Y1_FrameData[7]
    DIRECTION INPUT ;
    USE SIGNAL ;
    ANTENNAGATEAREA 1.626300 ;
    PORT
      LAYER Metal3 ;
        RECT 0.000 914.560 0.400 914.960 ;
    END
  END Tile_X0Y1_FrameData[7]
  PIN Tile_X0Y1_FrameData[8]
    DIRECTION INPUT ;
    USE SIGNAL ;
    ANTENNAGATEAREA 1.626300 ;
    PORT
      LAYER Metal3 ;
        RECT 0.000 919.600 0.400 920.000 ;
    END
  END Tile_X0Y1_FrameData[8]
  PIN Tile_X0Y1_FrameData[9]
    DIRECTION INPUT ;
    USE SIGNAL ;
    ANTENNAGATEAREA 1.626300 ;
    PORT
      LAYER Metal3 ;
        RECT 0.000 924.640 0.400 925.040 ;
    END
  END Tile_X0Y1_FrameData[9]
  PIN Tile_X0Y1_FrameData_O[0]
    DIRECTION OUTPUT ;
    USE SIGNAL ;
    ANTENNADIFFAREA 0.708600 ;
    PORT
      LAYER Metal3 ;
        RECT 219.440 941.440 219.840 941.840 ;
    END
  END Tile_X0Y1_FrameData_O[0]
  PIN Tile_X0Y1_FrameData_O[10]
    DIRECTION OUTPUT ;
    USE SIGNAL ;
    ANTENNADIFFAREA 0.708600 ;
    PORT
      LAYER Metal3 ;
        RECT 219.440 949.840 219.840 950.240 ;
    END
  END Tile_X0Y1_FrameData_O[10]
  PIN Tile_X0Y1_FrameData_O[11]
    DIRECTION OUTPUT ;
    USE SIGNAL ;
    ANTENNADIFFAREA 0.708600 ;
    PORT
      LAYER Metal3 ;
        RECT 219.440 950.680 219.840 951.080 ;
    END
  END Tile_X0Y1_FrameData_O[11]
  PIN Tile_X0Y1_FrameData_O[12]
    DIRECTION OUTPUT ;
    USE SIGNAL ;
    ANTENNADIFFAREA 0.708600 ;
    PORT
      LAYER Metal3 ;
        RECT 219.440 951.520 219.840 951.920 ;
    END
  END Tile_X0Y1_FrameData_O[12]
  PIN Tile_X0Y1_FrameData_O[13]
    DIRECTION OUTPUT ;
    USE SIGNAL ;
    ANTENNADIFFAREA 0.708600 ;
    PORT
      LAYER Metal3 ;
        RECT 219.440 952.360 219.840 952.760 ;
    END
  END Tile_X0Y1_FrameData_O[13]
  PIN Tile_X0Y1_FrameData_O[14]
    DIRECTION OUTPUT ;
    USE SIGNAL ;
    ANTENNADIFFAREA 0.708600 ;
    PORT
      LAYER Metal3 ;
        RECT 219.440 953.200 219.840 953.600 ;
    END
  END Tile_X0Y1_FrameData_O[14]
  PIN Tile_X0Y1_FrameData_O[15]
    DIRECTION OUTPUT ;
    USE SIGNAL ;
    ANTENNADIFFAREA 0.708600 ;
    PORT
      LAYER Metal3 ;
        RECT 219.440 954.040 219.840 954.440 ;
    END
  END Tile_X0Y1_FrameData_O[15]
  PIN Tile_X0Y1_FrameData_O[16]
    DIRECTION OUTPUT ;
    USE SIGNAL ;
    ANTENNADIFFAREA 0.708600 ;
    PORT
      LAYER Metal3 ;
        RECT 219.440 954.880 219.840 955.280 ;
    END
  END Tile_X0Y1_FrameData_O[16]
  PIN Tile_X0Y1_FrameData_O[17]
    DIRECTION OUTPUT ;
    USE SIGNAL ;
    ANTENNADIFFAREA 0.708600 ;
    PORT
      LAYER Metal3 ;
        RECT 219.440 955.720 219.840 956.120 ;
    END
  END Tile_X0Y1_FrameData_O[17]
  PIN Tile_X0Y1_FrameData_O[18]
    DIRECTION OUTPUT ;
    USE SIGNAL ;
    ANTENNADIFFAREA 0.708600 ;
    PORT
      LAYER Metal3 ;
        RECT 219.440 956.560 219.840 956.960 ;
    END
  END Tile_X0Y1_FrameData_O[18]
  PIN Tile_X0Y1_FrameData_O[19]
    DIRECTION OUTPUT ;
    USE SIGNAL ;
    ANTENNADIFFAREA 0.708600 ;
    PORT
      LAYER Metal3 ;
        RECT 219.440 957.400 219.840 957.800 ;
    END
  END Tile_X0Y1_FrameData_O[19]
  PIN Tile_X0Y1_FrameData_O[1]
    DIRECTION OUTPUT ;
    USE SIGNAL ;
    ANTENNADIFFAREA 0.708600 ;
    PORT
      LAYER Metal3 ;
        RECT 219.440 942.280 219.840 942.680 ;
    END
  END Tile_X0Y1_FrameData_O[1]
  PIN Tile_X0Y1_FrameData_O[20]
    DIRECTION OUTPUT ;
    USE SIGNAL ;
    ANTENNADIFFAREA 0.708600 ;
    PORT
      LAYER Metal3 ;
        RECT 219.440 958.240 219.840 958.640 ;
    END
  END Tile_X0Y1_FrameData_O[20]
  PIN Tile_X0Y1_FrameData_O[21]
    DIRECTION OUTPUT ;
    USE SIGNAL ;
    ANTENNADIFFAREA 0.708600 ;
    PORT
      LAYER Metal3 ;
        RECT 219.440 959.080 219.840 959.480 ;
    END
  END Tile_X0Y1_FrameData_O[21]
  PIN Tile_X0Y1_FrameData_O[22]
    DIRECTION OUTPUT ;
    USE SIGNAL ;
    ANTENNADIFFAREA 0.708600 ;
    PORT
      LAYER Metal3 ;
        RECT 219.440 959.920 219.840 960.320 ;
    END
  END Tile_X0Y1_FrameData_O[22]
  PIN Tile_X0Y1_FrameData_O[23]
    DIRECTION OUTPUT ;
    USE SIGNAL ;
    ANTENNADIFFAREA 0.708600 ;
    PORT
      LAYER Metal3 ;
        RECT 219.440 960.760 219.840 961.160 ;
    END
  END Tile_X0Y1_FrameData_O[23]
  PIN Tile_X0Y1_FrameData_O[24]
    DIRECTION OUTPUT ;
    USE SIGNAL ;
    ANTENNADIFFAREA 0.708600 ;
    PORT
      LAYER Metal3 ;
        RECT 219.440 961.600 219.840 962.000 ;
    END
  END Tile_X0Y1_FrameData_O[24]
  PIN Tile_X0Y1_FrameData_O[25]
    DIRECTION OUTPUT ;
    USE SIGNAL ;
    ANTENNADIFFAREA 0.708600 ;
    PORT
      LAYER Metal3 ;
        RECT 219.440 962.440 219.840 962.840 ;
    END
  END Tile_X0Y1_FrameData_O[25]
  PIN Tile_X0Y1_FrameData_O[26]
    DIRECTION OUTPUT ;
    USE SIGNAL ;
    ANTENNADIFFAREA 0.708600 ;
    PORT
      LAYER Metal3 ;
        RECT 219.440 963.280 219.840 963.680 ;
    END
  END Tile_X0Y1_FrameData_O[26]
  PIN Tile_X0Y1_FrameData_O[27]
    DIRECTION OUTPUT ;
    USE SIGNAL ;
    ANTENNADIFFAREA 0.708600 ;
    PORT
      LAYER Metal3 ;
        RECT 219.440 964.120 219.840 964.520 ;
    END
  END Tile_X0Y1_FrameData_O[27]
  PIN Tile_X0Y1_FrameData_O[28]
    DIRECTION OUTPUT ;
    USE SIGNAL ;
    ANTENNADIFFAREA 0.708600 ;
    PORT
      LAYER Metal3 ;
        RECT 219.440 964.960 219.840 965.360 ;
    END
  END Tile_X0Y1_FrameData_O[28]
  PIN Tile_X0Y1_FrameData_O[29]
    DIRECTION OUTPUT ;
    USE SIGNAL ;
    ANTENNADIFFAREA 0.708600 ;
    PORT
      LAYER Metal3 ;
        RECT 219.440 965.800 219.840 966.200 ;
    END
  END Tile_X0Y1_FrameData_O[29]
  PIN Tile_X0Y1_FrameData_O[2]
    DIRECTION OUTPUT ;
    USE SIGNAL ;
    ANTENNADIFFAREA 0.708600 ;
    PORT
      LAYER Metal3 ;
        RECT 219.440 943.120 219.840 943.520 ;
    END
  END Tile_X0Y1_FrameData_O[2]
  PIN Tile_X0Y1_FrameData_O[30]
    DIRECTION OUTPUT ;
    USE SIGNAL ;
    ANTENNADIFFAREA 0.708600 ;
    PORT
      LAYER Metal3 ;
        RECT 219.440 966.640 219.840 967.040 ;
    END
  END Tile_X0Y1_FrameData_O[30]
  PIN Tile_X0Y1_FrameData_O[31]
    DIRECTION OUTPUT ;
    USE SIGNAL ;
    ANTENNADIFFAREA 0.708600 ;
    PORT
      LAYER Metal3 ;
        RECT 219.440 967.480 219.840 967.880 ;
    END
  END Tile_X0Y1_FrameData_O[31]
  PIN Tile_X0Y1_FrameData_O[3]
    DIRECTION OUTPUT ;
    USE SIGNAL ;
    ANTENNADIFFAREA 0.708600 ;
    PORT
      LAYER Metal3 ;
        RECT 219.440 943.960 219.840 944.360 ;
    END
  END Tile_X0Y1_FrameData_O[3]
  PIN Tile_X0Y1_FrameData_O[4]
    DIRECTION OUTPUT ;
    USE SIGNAL ;
    ANTENNADIFFAREA 0.708600 ;
    PORT
      LAYER Metal3 ;
        RECT 219.440 944.800 219.840 945.200 ;
    END
  END Tile_X0Y1_FrameData_O[4]
  PIN Tile_X0Y1_FrameData_O[5]
    DIRECTION OUTPUT ;
    USE SIGNAL ;
    ANTENNADIFFAREA 0.708600 ;
    PORT
      LAYER Metal3 ;
        RECT 219.440 945.640 219.840 946.040 ;
    END
  END Tile_X0Y1_FrameData_O[5]
  PIN Tile_X0Y1_FrameData_O[6]
    DIRECTION OUTPUT ;
    USE SIGNAL ;
    ANTENNADIFFAREA 0.708600 ;
    PORT
      LAYER Metal3 ;
        RECT 219.440 946.480 219.840 946.880 ;
    END
  END Tile_X0Y1_FrameData_O[6]
  PIN Tile_X0Y1_FrameData_O[7]
    DIRECTION OUTPUT ;
    USE SIGNAL ;
    ANTENNADIFFAREA 0.708600 ;
    PORT
      LAYER Metal3 ;
        RECT 219.440 947.320 219.840 947.720 ;
    END
  END Tile_X0Y1_FrameData_O[7]
  PIN Tile_X0Y1_FrameData_O[8]
    DIRECTION OUTPUT ;
    USE SIGNAL ;
    ANTENNADIFFAREA 0.708600 ;
    PORT
      LAYER Metal3 ;
        RECT 219.440 948.160 219.840 948.560 ;
    END
  END Tile_X0Y1_FrameData_O[8]
  PIN Tile_X0Y1_FrameData_O[9]
    DIRECTION OUTPUT ;
    USE SIGNAL ;
    ANTENNADIFFAREA 0.708600 ;
    PORT
      LAYER Metal3 ;
        RECT 219.440 949.000 219.840 949.400 ;
    END
  END Tile_X0Y1_FrameData_O[9]
  PIN Tile_X0Y1_W1END[0]
    DIRECTION INPUT ;
    USE SIGNAL ;
    ANTENNAGATEAREA 1.279200 ;
    PORT
      LAYER Metal3 ;
        RECT 219.440 860.800 219.840 861.200 ;
    END
  END Tile_X0Y1_W1END[0]
  PIN Tile_X0Y1_W1END[1]
    DIRECTION INPUT ;
    USE SIGNAL ;
    ANTENNAGATEAREA 1.279200 ;
    PORT
      LAYER Metal3 ;
        RECT 219.440 861.640 219.840 862.040 ;
    END
  END Tile_X0Y1_W1END[1]
  PIN Tile_X0Y1_W1END[2]
    DIRECTION INPUT ;
    USE SIGNAL ;
    ANTENNAGATEAREA 1.279200 ;
    PORT
      LAYER Metal3 ;
        RECT 219.440 862.480 219.840 862.880 ;
    END
  END Tile_X0Y1_W1END[2]
  PIN Tile_X0Y1_W1END[3]
    DIRECTION INPUT ;
    USE SIGNAL ;
    ANTENNAGATEAREA 1.279200 ;
    PORT
      LAYER Metal3 ;
        RECT 219.440 863.320 219.840 863.720 ;
    END
  END Tile_X0Y1_W1END[3]
  PIN Tile_X0Y1_W2END[0]
    DIRECTION INPUT ;
    USE SIGNAL ;
    ANTENNAGATEAREA 0.852800 ;
    PORT
      LAYER Metal3 ;
        RECT 219.440 870.880 219.840 871.280 ;
    END
  END Tile_X0Y1_W2END[0]
  PIN Tile_X0Y1_W2END[1]
    DIRECTION INPUT ;
    USE SIGNAL ;
    ANTENNAGATEAREA 0.852800 ;
    PORT
      LAYER Metal3 ;
        RECT 219.440 871.720 219.840 872.120 ;
    END
  END Tile_X0Y1_W2END[1]
  PIN Tile_X0Y1_W2END[2]
    DIRECTION INPUT ;
    USE SIGNAL ;
    ANTENNAGATEAREA 0.852800 ;
    PORT
      LAYER Metal3 ;
        RECT 219.440 872.560 219.840 872.960 ;
    END
  END Tile_X0Y1_W2END[2]
  PIN Tile_X0Y1_W2END[3]
    DIRECTION INPUT ;
    USE SIGNAL ;
    ANTENNAGATEAREA 0.852800 ;
    PORT
      LAYER Metal3 ;
        RECT 219.440 873.400 219.840 873.800 ;
    END
  END Tile_X0Y1_W2END[3]
  PIN Tile_X0Y1_W2END[4]
    DIRECTION INPUT ;
    USE SIGNAL ;
    ANTENNAGATEAREA 0.852800 ;
    PORT
      LAYER Metal3 ;
        RECT 219.440 874.240 219.840 874.640 ;
    END
  END Tile_X0Y1_W2END[4]
  PIN Tile_X0Y1_W2END[5]
    DIRECTION INPUT ;
    USE SIGNAL ;
    ANTENNAGATEAREA 0.852800 ;
    PORT
      LAYER Metal3 ;
        RECT 219.440 875.080 219.840 875.480 ;
    END
  END Tile_X0Y1_W2END[5]
  PIN Tile_X0Y1_W2END[6]
    DIRECTION INPUT ;
    USE SIGNAL ;
    ANTENNAGATEAREA 0.852800 ;
    PORT
      LAYER Metal3 ;
        RECT 219.440 875.920 219.840 876.320 ;
    END
  END Tile_X0Y1_W2END[6]
  PIN Tile_X0Y1_W2END[7]
    DIRECTION INPUT ;
    USE SIGNAL ;
    ANTENNAGATEAREA 0.852800 ;
    PORT
      LAYER Metal3 ;
        RECT 219.440 876.760 219.840 877.160 ;
    END
  END Tile_X0Y1_W2END[7]
  PIN Tile_X0Y1_W2MID[0]
    DIRECTION INPUT ;
    USE SIGNAL ;
    ANTENNAGATEAREA 0.852800 ;
    PORT
      LAYER Metal3 ;
        RECT 219.440 864.160 219.840 864.560 ;
    END
  END Tile_X0Y1_W2MID[0]
  PIN Tile_X0Y1_W2MID[1]
    DIRECTION INPUT ;
    USE SIGNAL ;
    ANTENNAGATEAREA 0.852800 ;
    PORT
      LAYER Metal3 ;
        RECT 219.440 865.000 219.840 865.400 ;
    END
  END Tile_X0Y1_W2MID[1]
  PIN Tile_X0Y1_W2MID[2]
    DIRECTION INPUT ;
    USE SIGNAL ;
    ANTENNAGATEAREA 0.852800 ;
    PORT
      LAYER Metal3 ;
        RECT 219.440 865.840 219.840 866.240 ;
    END
  END Tile_X0Y1_W2MID[2]
  PIN Tile_X0Y1_W2MID[3]
    DIRECTION INPUT ;
    USE SIGNAL ;
    ANTENNAGATEAREA 0.852800 ;
    PORT
      LAYER Metal3 ;
        RECT 219.440 866.680 219.840 867.080 ;
    END
  END Tile_X0Y1_W2MID[3]
  PIN Tile_X0Y1_W2MID[4]
    DIRECTION INPUT ;
    USE SIGNAL ;
    ANTENNAGATEAREA 0.852800 ;
    PORT
      LAYER Metal3 ;
        RECT 219.440 867.520 219.840 867.920 ;
    END
  END Tile_X0Y1_W2MID[4]
  PIN Tile_X0Y1_W2MID[5]
    DIRECTION INPUT ;
    USE SIGNAL ;
    ANTENNAGATEAREA 0.852800 ;
    PORT
      LAYER Metal3 ;
        RECT 219.440 868.360 219.840 868.760 ;
    END
  END Tile_X0Y1_W2MID[5]
  PIN Tile_X0Y1_W2MID[6]
    DIRECTION INPUT ;
    USE SIGNAL ;
    ANTENNAGATEAREA 0.852800 ;
    PORT
      LAYER Metal3 ;
        RECT 219.440 869.200 219.840 869.600 ;
    END
  END Tile_X0Y1_W2MID[6]
  PIN Tile_X0Y1_W2MID[7]
    DIRECTION INPUT ;
    USE SIGNAL ;
    ANTENNAGATEAREA 0.852800 ;
    PORT
      LAYER Metal3 ;
        RECT 219.440 870.040 219.840 870.440 ;
    END
  END Tile_X0Y1_W2MID[7]
  PIN Tile_X0Y1_W6END[0]
    DIRECTION INPUT ;
    USE SIGNAL ;
    ANTENNAGATEAREA 0.881400 ;
    PORT
      LAYER Metal3 ;
        RECT 219.440 891.040 219.840 891.440 ;
    END
  END Tile_X0Y1_W6END[0]
  PIN Tile_X0Y1_W6END[10]
    DIRECTION INPUT ;
    USE SIGNAL ;
    ANTENNAGATEAREA 0.852800 ;
    PORT
      LAYER Metal3 ;
        RECT 219.440 899.440 219.840 899.840 ;
    END
  END Tile_X0Y1_W6END[10]
  PIN Tile_X0Y1_W6END[11]
    DIRECTION INPUT ;
    USE SIGNAL ;
    ANTENNAGATEAREA 0.852800 ;
    PORT
      LAYER Metal3 ;
        RECT 219.440 900.280 219.840 900.680 ;
    END
  END Tile_X0Y1_W6END[11]
  PIN Tile_X0Y1_W6END[1]
    DIRECTION INPUT ;
    USE SIGNAL ;
    ANTENNAGATEAREA 0.881400 ;
    PORT
      LAYER Metal3 ;
        RECT 219.440 891.880 219.840 892.280 ;
    END
  END Tile_X0Y1_W6END[1]
  PIN Tile_X0Y1_W6END[2]
    DIRECTION INPUT ;
    USE SIGNAL ;
    ANTENNAGATEAREA 0.881400 ;
    PORT
      LAYER Metal3 ;
        RECT 219.440 892.720 219.840 893.120 ;
    END
  END Tile_X0Y1_W6END[2]
  PIN Tile_X0Y1_W6END[3]
    DIRECTION INPUT ;
    USE SIGNAL ;
    ANTENNAGATEAREA 0.881400 ;
    PORT
      LAYER Metal3 ;
        RECT 219.440 893.560 219.840 893.960 ;
    END
  END Tile_X0Y1_W6END[3]
  PIN Tile_X0Y1_W6END[4]
    DIRECTION INPUT ;
    USE SIGNAL ;
    ANTENNAGATEAREA 1.066000 ;
    PORT
      LAYER Metal3 ;
        RECT 219.440 894.400 219.840 894.800 ;
    END
  END Tile_X0Y1_W6END[4]
  PIN Tile_X0Y1_W6END[5]
    DIRECTION INPUT ;
    USE SIGNAL ;
    ANTENNAGATEAREA 1.066000 ;
    PORT
      LAYER Metal3 ;
        RECT 219.440 895.240 219.840 895.640 ;
    END
  END Tile_X0Y1_W6END[5]
  PIN Tile_X0Y1_W6END[6]
    DIRECTION INPUT ;
    USE SIGNAL ;
    ANTENNAGATEAREA 1.066000 ;
    PORT
      LAYER Metal3 ;
        RECT 219.440 896.080 219.840 896.480 ;
    END
  END Tile_X0Y1_W6END[6]
  PIN Tile_X0Y1_W6END[7]
    DIRECTION INPUT ;
    USE SIGNAL ;
    ANTENNAGATEAREA 1.066000 ;
    PORT
      LAYER Metal3 ;
        RECT 219.440 896.920 219.840 897.320 ;
    END
  END Tile_X0Y1_W6END[7]
  PIN Tile_X0Y1_W6END[8]
    DIRECTION INPUT ;
    USE SIGNAL ;
    ANTENNAGATEAREA 0.852800 ;
    PORT
      LAYER Metal3 ;
        RECT 219.440 897.760 219.840 898.160 ;
    END
  END Tile_X0Y1_W6END[8]
  PIN Tile_X0Y1_W6END[9]
    DIRECTION INPUT ;
    USE SIGNAL ;
    ANTENNAGATEAREA 0.852800 ;
    PORT
      LAYER Metal3 ;
        RECT 219.440 898.600 219.840 899.000 ;
    END
  END Tile_X0Y1_W6END[9]
  PIN Tile_X0Y1_WW4END[0]
    DIRECTION INPUT ;
    USE SIGNAL ;
    ANTENNAGATEAREA 0.852800 ;
    PORT
      LAYER Metal3 ;
        RECT 219.440 877.600 219.840 878.000 ;
    END
  END Tile_X0Y1_WW4END[0]
  PIN Tile_X0Y1_WW4END[10]
    DIRECTION INPUT ;
    USE SIGNAL ;
    ANTENNAGATEAREA 0.639600 ;
    PORT
      LAYER Metal3 ;
        RECT 219.440 886.000 219.840 886.400 ;
    END
  END Tile_X0Y1_WW4END[10]
  PIN Tile_X0Y1_WW4END[11]
    DIRECTION INPUT ;
    USE SIGNAL ;
    ANTENNAGATEAREA 0.639600 ;
    PORT
      LAYER Metal3 ;
        RECT 219.440 886.840 219.840 887.240 ;
    END
  END Tile_X0Y1_WW4END[11]
  PIN Tile_X0Y1_WW4END[12]
    DIRECTION INPUT ;
    USE SIGNAL ;
    ANTENNAGATEAREA 0.852800 ;
    PORT
      LAYER Metal3 ;
        RECT 219.440 887.680 219.840 888.080 ;
    END
  END Tile_X0Y1_WW4END[12]
  PIN Tile_X0Y1_WW4END[13]
    DIRECTION INPUT ;
    USE SIGNAL ;
    ANTENNAGATEAREA 0.852800 ;
    PORT
      LAYER Metal3 ;
        RECT 219.440 888.520 219.840 888.920 ;
    END
  END Tile_X0Y1_WW4END[13]
  PIN Tile_X0Y1_WW4END[14]
    DIRECTION INPUT ;
    USE SIGNAL ;
    ANTENNAGATEAREA 0.852800 ;
    PORT
      LAYER Metal3 ;
        RECT 219.440 889.360 219.840 889.760 ;
    END
  END Tile_X0Y1_WW4END[14]
  PIN Tile_X0Y1_WW4END[15]
    DIRECTION INPUT ;
    USE SIGNAL ;
    ANTENNAGATEAREA 0.852800 ;
    PORT
      LAYER Metal3 ;
        RECT 219.440 890.200 219.840 890.600 ;
    END
  END Tile_X0Y1_WW4END[15]
  PIN Tile_X0Y1_WW4END[1]
    DIRECTION INPUT ;
    USE SIGNAL ;
    ANTENNAGATEAREA 0.852800 ;
    PORT
      LAYER Metal3 ;
        RECT 219.440 878.440 219.840 878.840 ;
    END
  END Tile_X0Y1_WW4END[1]
  PIN Tile_X0Y1_WW4END[2]
    DIRECTION INPUT ;
    USE SIGNAL ;
    ANTENNAGATEAREA 0.852800 ;
    PORT
      LAYER Metal3 ;
        RECT 219.440 879.280 219.840 879.680 ;
    END
  END Tile_X0Y1_WW4END[2]
  PIN Tile_X0Y1_WW4END[3]
    DIRECTION INPUT ;
    USE SIGNAL ;
    ANTENNAGATEAREA 0.852800 ;
    PORT
      LAYER Metal3 ;
        RECT 219.440 880.120 219.840 880.520 ;
    END
  END Tile_X0Y1_WW4END[3]
  PIN Tile_X0Y1_WW4END[4]
    DIRECTION INPUT ;
    USE SIGNAL ;
    ANTENNAGATEAREA 0.639600 ;
    PORT
      LAYER Metal3 ;
        RECT 219.440 880.960 219.840 881.360 ;
    END
  END Tile_X0Y1_WW4END[4]
  PIN Tile_X0Y1_WW4END[5]
    DIRECTION INPUT ;
    USE SIGNAL ;
    ANTENNAGATEAREA 0.639600 ;
    PORT
      LAYER Metal3 ;
        RECT 219.440 881.800 219.840 882.200 ;
    END
  END Tile_X0Y1_WW4END[5]
  PIN Tile_X0Y1_WW4END[6]
    DIRECTION INPUT ;
    USE SIGNAL ;
    ANTENNAGATEAREA 0.639600 ;
    PORT
      LAYER Metal3 ;
        RECT 219.440 882.640 219.840 883.040 ;
    END
  END Tile_X0Y1_WW4END[6]
  PIN Tile_X0Y1_WW4END[7]
    DIRECTION INPUT ;
    USE SIGNAL ;
    ANTENNAGATEAREA 0.639600 ;
    PORT
      LAYER Metal3 ;
        RECT 219.440 883.480 219.840 883.880 ;
    END
  END Tile_X0Y1_WW4END[7]
  PIN Tile_X0Y1_WW4END[8]
    DIRECTION INPUT ;
    USE SIGNAL ;
    ANTENNAGATEAREA 0.639600 ;
    PORT
      LAYER Metal3 ;
        RECT 219.440 884.320 219.840 884.720 ;
    END
  END Tile_X0Y1_WW4END[8]
  PIN Tile_X0Y1_WW4END[9]
    DIRECTION INPUT ;
    USE SIGNAL ;
    ANTENNAGATEAREA 0.639600 ;
    PORT
      LAYER Metal3 ;
        RECT 219.440 885.160 219.840 885.560 ;
    END
  END Tile_X0Y1_WW4END[9]
  PIN Tile_X0Y2_E1BEG[0]
    DIRECTION OUTPUT ;
    USE SIGNAL ;
    ANTENNADIFFAREA 0.708600 ;
    PORT
      LAYER Metal3 ;
        RECT 219.440 697.840 219.840 698.240 ;
    END
  END Tile_X0Y2_E1BEG[0]
  PIN Tile_X0Y2_E1BEG[1]
    DIRECTION OUTPUT ;
    USE SIGNAL ;
    ANTENNADIFFAREA 0.708600 ;
    PORT
      LAYER Metal3 ;
        RECT 219.440 698.680 219.840 699.080 ;
    END
  END Tile_X0Y2_E1BEG[1]
  PIN Tile_X0Y2_E1BEG[2]
    DIRECTION OUTPUT ;
    USE SIGNAL ;
    ANTENNADIFFAREA 0.708600 ;
    PORT
      LAYER Metal3 ;
        RECT 219.440 699.520 219.840 699.920 ;
    END
  END Tile_X0Y2_E1BEG[2]
  PIN Tile_X0Y2_E1BEG[3]
    DIRECTION OUTPUT ;
    USE SIGNAL ;
    ANTENNADIFFAREA 0.708600 ;
    PORT
      LAYER Metal3 ;
        RECT 219.440 700.360 219.840 700.760 ;
    END
  END Tile_X0Y2_E1BEG[3]
  PIN Tile_X0Y2_E2BEG[0]
    DIRECTION OUTPUT ;
    USE SIGNAL ;
    ANTENNADIFFAREA 0.708600 ;
    PORT
      LAYER Metal3 ;
        RECT 219.440 701.200 219.840 701.600 ;
    END
  END Tile_X0Y2_E2BEG[0]
  PIN Tile_X0Y2_E2BEG[1]
    DIRECTION OUTPUT ;
    USE SIGNAL ;
    ANTENNADIFFAREA 0.708600 ;
    PORT
      LAYER Metal3 ;
        RECT 219.440 702.040 219.840 702.440 ;
    END
  END Tile_X0Y2_E2BEG[1]
  PIN Tile_X0Y2_E2BEG[2]
    DIRECTION OUTPUT ;
    USE SIGNAL ;
    ANTENNADIFFAREA 0.708600 ;
    PORT
      LAYER Metal3 ;
        RECT 219.440 702.880 219.840 703.280 ;
    END
  END Tile_X0Y2_E2BEG[2]
  PIN Tile_X0Y2_E2BEG[3]
    DIRECTION OUTPUT ;
    USE SIGNAL ;
    ANTENNADIFFAREA 0.708600 ;
    PORT
      LAYER Metal3 ;
        RECT 219.440 703.720 219.840 704.120 ;
    END
  END Tile_X0Y2_E2BEG[3]
  PIN Tile_X0Y2_E2BEG[4]
    DIRECTION OUTPUT ;
    USE SIGNAL ;
    ANTENNADIFFAREA 0.708600 ;
    PORT
      LAYER Metal3 ;
        RECT 219.440 704.560 219.840 704.960 ;
    END
  END Tile_X0Y2_E2BEG[4]
  PIN Tile_X0Y2_E2BEG[5]
    DIRECTION OUTPUT ;
    USE SIGNAL ;
    ANTENNADIFFAREA 0.708600 ;
    PORT
      LAYER Metal3 ;
        RECT 219.440 705.400 219.840 705.800 ;
    END
  END Tile_X0Y2_E2BEG[5]
  PIN Tile_X0Y2_E2BEG[6]
    DIRECTION OUTPUT ;
    USE SIGNAL ;
    ANTENNADIFFAREA 0.708600 ;
    PORT
      LAYER Metal3 ;
        RECT 219.440 706.240 219.840 706.640 ;
    END
  END Tile_X0Y2_E2BEG[6]
  PIN Tile_X0Y2_E2BEG[7]
    DIRECTION OUTPUT ;
    USE SIGNAL ;
    ANTENNADIFFAREA 0.708600 ;
    PORT
      LAYER Metal3 ;
        RECT 219.440 707.080 219.840 707.480 ;
    END
  END Tile_X0Y2_E2BEG[7]
  PIN Tile_X0Y2_E2BEGb[0]
    DIRECTION OUTPUT ;
    USE SIGNAL ;
    ANTENNADIFFAREA 0.708600 ;
    PORT
      LAYER Metal3 ;
        RECT 219.440 707.920 219.840 708.320 ;
    END
  END Tile_X0Y2_E2BEGb[0]
  PIN Tile_X0Y2_E2BEGb[1]
    DIRECTION OUTPUT ;
    USE SIGNAL ;
    ANTENNADIFFAREA 0.708600 ;
    PORT
      LAYER Metal3 ;
        RECT 219.440 708.760 219.840 709.160 ;
    END
  END Tile_X0Y2_E2BEGb[1]
  PIN Tile_X0Y2_E2BEGb[2]
    DIRECTION OUTPUT ;
    USE SIGNAL ;
    ANTENNADIFFAREA 0.708600 ;
    PORT
      LAYER Metal3 ;
        RECT 219.440 709.600 219.840 710.000 ;
    END
  END Tile_X0Y2_E2BEGb[2]
  PIN Tile_X0Y2_E2BEGb[3]
    DIRECTION OUTPUT ;
    USE SIGNAL ;
    ANTENNADIFFAREA 0.708600 ;
    PORT
      LAYER Metal3 ;
        RECT 219.440 710.440 219.840 710.840 ;
    END
  END Tile_X0Y2_E2BEGb[3]
  PIN Tile_X0Y2_E2BEGb[4]
    DIRECTION OUTPUT ;
    USE SIGNAL ;
    ANTENNADIFFAREA 0.708600 ;
    PORT
      LAYER Metal3 ;
        RECT 219.440 711.280 219.840 711.680 ;
    END
  END Tile_X0Y2_E2BEGb[4]
  PIN Tile_X0Y2_E2BEGb[5]
    DIRECTION OUTPUT ;
    USE SIGNAL ;
    ANTENNADIFFAREA 0.708600 ;
    PORT
      LAYER Metal3 ;
        RECT 219.440 712.120 219.840 712.520 ;
    END
  END Tile_X0Y2_E2BEGb[5]
  PIN Tile_X0Y2_E2BEGb[6]
    DIRECTION OUTPUT ;
    USE SIGNAL ;
    ANTENNADIFFAREA 0.708600 ;
    PORT
      LAYER Metal3 ;
        RECT 219.440 712.960 219.840 713.360 ;
    END
  END Tile_X0Y2_E2BEGb[6]
  PIN Tile_X0Y2_E2BEGb[7]
    DIRECTION OUTPUT ;
    USE SIGNAL ;
    ANTENNADIFFAREA 0.708600 ;
    PORT
      LAYER Metal3 ;
        RECT 219.440 713.800 219.840 714.200 ;
    END
  END Tile_X0Y2_E2BEGb[7]
  PIN Tile_X0Y2_E6BEG[0]
    DIRECTION OUTPUT ;
    USE SIGNAL ;
    ANTENNADIFFAREA 0.708600 ;
    PORT
      LAYER Metal3 ;
        RECT 219.440 728.080 219.840 728.480 ;
    END
  END Tile_X0Y2_E6BEG[0]
  PIN Tile_X0Y2_E6BEG[10]
    DIRECTION OUTPUT ;
    USE SIGNAL ;
    ANTENNADIFFAREA 0.708600 ;
    PORT
      LAYER Metal3 ;
        RECT 219.440 736.480 219.840 736.880 ;
    END
  END Tile_X0Y2_E6BEG[10]
  PIN Tile_X0Y2_E6BEG[11]
    DIRECTION OUTPUT ;
    USE SIGNAL ;
    ANTENNADIFFAREA 0.708600 ;
    PORT
      LAYER Metal3 ;
        RECT 219.440 737.320 219.840 737.720 ;
    END
  END Tile_X0Y2_E6BEG[11]
  PIN Tile_X0Y2_E6BEG[1]
    DIRECTION OUTPUT ;
    USE SIGNAL ;
    ANTENNADIFFAREA 0.708600 ;
    PORT
      LAYER Metal3 ;
        RECT 219.440 728.920 219.840 729.320 ;
    END
  END Tile_X0Y2_E6BEG[1]
  PIN Tile_X0Y2_E6BEG[2]
    DIRECTION OUTPUT ;
    USE SIGNAL ;
    ANTENNADIFFAREA 0.708600 ;
    PORT
      LAYER Metal3 ;
        RECT 219.440 729.760 219.840 730.160 ;
    END
  END Tile_X0Y2_E6BEG[2]
  PIN Tile_X0Y2_E6BEG[3]
    DIRECTION OUTPUT ;
    USE SIGNAL ;
    ANTENNADIFFAREA 0.708600 ;
    PORT
      LAYER Metal3 ;
        RECT 219.440 730.600 219.840 731.000 ;
    END
  END Tile_X0Y2_E6BEG[3]
  PIN Tile_X0Y2_E6BEG[4]
    DIRECTION OUTPUT ;
    USE SIGNAL ;
    ANTENNADIFFAREA 0.708600 ;
    PORT
      LAYER Metal3 ;
        RECT 219.440 731.440 219.840 731.840 ;
    END
  END Tile_X0Y2_E6BEG[4]
  PIN Tile_X0Y2_E6BEG[5]
    DIRECTION OUTPUT ;
    USE SIGNAL ;
    ANTENNADIFFAREA 0.708600 ;
    PORT
      LAYER Metal3 ;
        RECT 219.440 732.280 219.840 732.680 ;
    END
  END Tile_X0Y2_E6BEG[5]
  PIN Tile_X0Y2_E6BEG[6]
    DIRECTION OUTPUT ;
    USE SIGNAL ;
    ANTENNADIFFAREA 0.708600 ;
    PORT
      LAYER Metal3 ;
        RECT 219.440 733.120 219.840 733.520 ;
    END
  END Tile_X0Y2_E6BEG[6]
  PIN Tile_X0Y2_E6BEG[7]
    DIRECTION OUTPUT ;
    USE SIGNAL ;
    ANTENNADIFFAREA 0.708600 ;
    PORT
      LAYER Metal3 ;
        RECT 219.440 733.960 219.840 734.360 ;
    END
  END Tile_X0Y2_E6BEG[7]
  PIN Tile_X0Y2_E6BEG[8]
    DIRECTION OUTPUT ;
    USE SIGNAL ;
    ANTENNADIFFAREA 0.708600 ;
    PORT
      LAYER Metal3 ;
        RECT 219.440 734.800 219.840 735.200 ;
    END
  END Tile_X0Y2_E6BEG[8]
  PIN Tile_X0Y2_E6BEG[9]
    DIRECTION OUTPUT ;
    USE SIGNAL ;
    ANTENNADIFFAREA 0.708600 ;
    PORT
      LAYER Metal3 ;
        RECT 219.440 735.640 219.840 736.040 ;
    END
  END Tile_X0Y2_E6BEG[9]
  PIN Tile_X0Y2_EE4BEG[0]
    DIRECTION OUTPUT ;
    USE SIGNAL ;
    ANTENNADIFFAREA 0.708600 ;
    PORT
      LAYER Metal3 ;
        RECT 219.440 714.640 219.840 715.040 ;
    END
  END Tile_X0Y2_EE4BEG[0]
  PIN Tile_X0Y2_EE4BEG[10]
    DIRECTION OUTPUT ;
    USE SIGNAL ;
    ANTENNADIFFAREA 0.708600 ;
    PORT
      LAYER Metal3 ;
        RECT 219.440 723.040 219.840 723.440 ;
    END
  END Tile_X0Y2_EE4BEG[10]
  PIN Tile_X0Y2_EE4BEG[11]
    DIRECTION OUTPUT ;
    USE SIGNAL ;
    ANTENNADIFFAREA 0.708600 ;
    PORT
      LAYER Metal3 ;
        RECT 219.440 723.880 219.840 724.280 ;
    END
  END Tile_X0Y2_EE4BEG[11]
  PIN Tile_X0Y2_EE4BEG[12]
    DIRECTION OUTPUT ;
    USE SIGNAL ;
    ANTENNADIFFAREA 0.708600 ;
    PORT
      LAYER Metal3 ;
        RECT 219.440 724.720 219.840 725.120 ;
    END
  END Tile_X0Y2_EE4BEG[12]
  PIN Tile_X0Y2_EE4BEG[13]
    DIRECTION OUTPUT ;
    USE SIGNAL ;
    ANTENNADIFFAREA 0.708600 ;
    PORT
      LAYER Metal3 ;
        RECT 219.440 725.560 219.840 725.960 ;
    END
  END Tile_X0Y2_EE4BEG[13]
  PIN Tile_X0Y2_EE4BEG[14]
    DIRECTION OUTPUT ;
    USE SIGNAL ;
    ANTENNADIFFAREA 0.708600 ;
    PORT
      LAYER Metal3 ;
        RECT 219.440 726.400 219.840 726.800 ;
    END
  END Tile_X0Y2_EE4BEG[14]
  PIN Tile_X0Y2_EE4BEG[15]
    DIRECTION OUTPUT ;
    USE SIGNAL ;
    ANTENNADIFFAREA 0.708600 ;
    PORT
      LAYER Metal3 ;
        RECT 219.440 727.240 219.840 727.640 ;
    END
  END Tile_X0Y2_EE4BEG[15]
  PIN Tile_X0Y2_EE4BEG[1]
    DIRECTION OUTPUT ;
    USE SIGNAL ;
    ANTENNADIFFAREA 0.708600 ;
    PORT
      LAYER Metal3 ;
        RECT 219.440 715.480 219.840 715.880 ;
    END
  END Tile_X0Y2_EE4BEG[1]
  PIN Tile_X0Y2_EE4BEG[2]
    DIRECTION OUTPUT ;
    USE SIGNAL ;
    ANTENNADIFFAREA 0.708600 ;
    PORT
      LAYER Metal3 ;
        RECT 219.440 716.320 219.840 716.720 ;
    END
  END Tile_X0Y2_EE4BEG[2]
  PIN Tile_X0Y2_EE4BEG[3]
    DIRECTION OUTPUT ;
    USE SIGNAL ;
    ANTENNADIFFAREA 0.708600 ;
    PORT
      LAYER Metal3 ;
        RECT 219.440 717.160 219.840 717.560 ;
    END
  END Tile_X0Y2_EE4BEG[3]
  PIN Tile_X0Y2_EE4BEG[4]
    DIRECTION OUTPUT ;
    USE SIGNAL ;
    ANTENNADIFFAREA 0.708600 ;
    PORT
      LAYER Metal3 ;
        RECT 219.440 718.000 219.840 718.400 ;
    END
  END Tile_X0Y2_EE4BEG[4]
  PIN Tile_X0Y2_EE4BEG[5]
    DIRECTION OUTPUT ;
    USE SIGNAL ;
    ANTENNADIFFAREA 0.708600 ;
    PORT
      LAYER Metal3 ;
        RECT 219.440 718.840 219.840 719.240 ;
    END
  END Tile_X0Y2_EE4BEG[5]
  PIN Tile_X0Y2_EE4BEG[6]
    DIRECTION OUTPUT ;
    USE SIGNAL ;
    ANTENNADIFFAREA 0.708600 ;
    PORT
      LAYER Metal3 ;
        RECT 219.440 719.680 219.840 720.080 ;
    END
  END Tile_X0Y2_EE4BEG[6]
  PIN Tile_X0Y2_EE4BEG[7]
    DIRECTION OUTPUT ;
    USE SIGNAL ;
    ANTENNADIFFAREA 0.708600 ;
    PORT
      LAYER Metal3 ;
        RECT 219.440 720.520 219.840 720.920 ;
    END
  END Tile_X0Y2_EE4BEG[7]
  PIN Tile_X0Y2_EE4BEG[8]
    DIRECTION OUTPUT ;
    USE SIGNAL ;
    ANTENNADIFFAREA 0.708600 ;
    PORT
      LAYER Metal3 ;
        RECT 219.440 721.360 219.840 721.760 ;
    END
  END Tile_X0Y2_EE4BEG[8]
  PIN Tile_X0Y2_EE4BEG[9]
    DIRECTION OUTPUT ;
    USE SIGNAL ;
    ANTENNADIFFAREA 0.708600 ;
    PORT
      LAYER Metal3 ;
        RECT 219.440 722.200 219.840 722.600 ;
    END
  END Tile_X0Y2_EE4BEG[9]
  PIN Tile_X0Y2_FrameData[0]
    DIRECTION INPUT ;
    USE SIGNAL ;
    ANTENNAGATEAREA 1.626300 ;
    PORT
      LAYER Metal3 ;
        RECT 0.000 704.980 0.400 705.380 ;
    END
  END Tile_X0Y2_FrameData[0]
  PIN Tile_X0Y2_FrameData[10]
    DIRECTION INPUT ;
    USE SIGNAL ;
    ANTENNAGATEAREA 1.626300 ;
    PORT
      LAYER Metal3 ;
        RECT 0.000 755.380 0.400 755.780 ;
    END
  END Tile_X0Y2_FrameData[10]
  PIN Tile_X0Y2_FrameData[11]
    DIRECTION INPUT ;
    USE SIGNAL ;
    ANTENNAGATEAREA 1.626300 ;
    PORT
      LAYER Metal3 ;
        RECT 0.000 760.420 0.400 760.820 ;
    END
  END Tile_X0Y2_FrameData[11]
  PIN Tile_X0Y2_FrameData[12]
    DIRECTION INPUT ;
    USE SIGNAL ;
    ANTENNAGATEAREA 1.626300 ;
    PORT
      LAYER Metal3 ;
        RECT 0.000 765.460 0.400 765.860 ;
    END
  END Tile_X0Y2_FrameData[12]
  PIN Tile_X0Y2_FrameData[13]
    DIRECTION INPUT ;
    USE SIGNAL ;
    ANTENNAGATEAREA 1.626300 ;
    PORT
      LAYER Metal3 ;
        RECT 0.000 770.500 0.400 770.900 ;
    END
  END Tile_X0Y2_FrameData[13]
  PIN Tile_X0Y2_FrameData[14]
    DIRECTION INPUT ;
    USE SIGNAL ;
    ANTENNAGATEAREA 1.626300 ;
    ANTENNADIFFAREA 20.153999 ;
    PORT
      LAYER Metal3 ;
        RECT 0.000 775.540 0.400 775.940 ;
    END
  END Tile_X0Y2_FrameData[14]
  PIN Tile_X0Y2_FrameData[15]
    DIRECTION INPUT ;
    USE SIGNAL ;
    ANTENNAGATEAREA 1.626300 ;
    ANTENNADIFFAREA 18.138599 ;
    PORT
      LAYER Metal3 ;
        RECT 0.000 780.580 0.400 780.980 ;
    END
  END Tile_X0Y2_FrameData[15]
  PIN Tile_X0Y2_FrameData[16]
    DIRECTION INPUT ;
    USE SIGNAL ;
    ANTENNAGATEAREA 1.807000 ;
    PORT
      LAYER Metal3 ;
        RECT 0.000 785.620 0.400 786.020 ;
    END
  END Tile_X0Y2_FrameData[16]
  PIN Tile_X0Y2_FrameData[17]
    DIRECTION INPUT ;
    USE SIGNAL ;
    ANTENNAGATEAREA 1.807000 ;
    PORT
      LAYER Metal3 ;
        RECT 0.000 790.660 0.400 791.060 ;
    END
  END Tile_X0Y2_FrameData[17]
  PIN Tile_X0Y2_FrameData[18]
    DIRECTION INPUT ;
    USE SIGNAL ;
    ANTENNAGATEAREA 1.807000 ;
    PORT
      LAYER Metal3 ;
        RECT 0.000 795.700 0.400 796.100 ;
    END
  END Tile_X0Y2_FrameData[18]
  PIN Tile_X0Y2_FrameData[19]
    DIRECTION INPUT ;
    USE SIGNAL ;
    ANTENNAGATEAREA 1.807000 ;
    PORT
      LAYER Metal3 ;
        RECT 0.000 800.740 0.400 801.140 ;
    END
  END Tile_X0Y2_FrameData[19]
  PIN Tile_X0Y2_FrameData[1]
    DIRECTION INPUT ;
    USE SIGNAL ;
    ANTENNAGATEAREA 1.626300 ;
    PORT
      LAYER Metal3 ;
        RECT 0.000 710.020 0.400 710.420 ;
    END
  END Tile_X0Y2_FrameData[1]
  PIN Tile_X0Y2_FrameData[20]
    DIRECTION INPUT ;
    USE SIGNAL ;
    ANTENNAGATEAREA 1.807000 ;
    PORT
      LAYER Metal3 ;
        RECT 0.000 805.780 0.400 806.180 ;
    END
  END Tile_X0Y2_FrameData[20]
  PIN Tile_X0Y2_FrameData[21]
    DIRECTION INPUT ;
    USE SIGNAL ;
    ANTENNAGATEAREA 1.807000 ;
    PORT
      LAYER Metal3 ;
        RECT 0.000 810.820 0.400 811.220 ;
    END
  END Tile_X0Y2_FrameData[21]
  PIN Tile_X0Y2_FrameData[22]
    DIRECTION INPUT ;
    USE SIGNAL ;
    ANTENNAGATEAREA 1.807000 ;
    PORT
      LAYER Metal3 ;
        RECT 0.000 815.860 0.400 816.260 ;
    END
  END Tile_X0Y2_FrameData[22]
  PIN Tile_X0Y2_FrameData[23]
    DIRECTION INPUT ;
    USE SIGNAL ;
    ANTENNAGATEAREA 1.807000 ;
    PORT
      LAYER Metal3 ;
        RECT 0.000 820.900 0.400 821.300 ;
    END
  END Tile_X0Y2_FrameData[23]
  PIN Tile_X0Y2_FrameData[24]
    DIRECTION INPUT ;
    USE SIGNAL ;
    ANTENNAGATEAREA 1.807000 ;
    ANTENNADIFFAREA 24.184799 ;
    PORT
      LAYER Metal3 ;
        RECT 0.000 825.940 0.400 826.340 ;
    END
  END Tile_X0Y2_FrameData[24]
  PIN Tile_X0Y2_FrameData[25]
    DIRECTION INPUT ;
    USE SIGNAL ;
    ANTENNAGATEAREA 1.807000 ;
    ANTENNADIFFAREA 20.153999 ;
    PORT
      LAYER Metal3 ;
        RECT 0.000 830.980 0.400 831.380 ;
    END
  END Tile_X0Y2_FrameData[25]
  PIN Tile_X0Y2_FrameData[26]
    DIRECTION INPUT ;
    USE SIGNAL ;
    ANTENNAGATEAREA 1.807000 ;
    PORT
      LAYER Metal3 ;
        RECT 0.000 836.020 0.400 836.420 ;
    END
  END Tile_X0Y2_FrameData[26]
  PIN Tile_X0Y2_FrameData[27]
    DIRECTION INPUT ;
    USE SIGNAL ;
    ANTENNAGATEAREA 1.807000 ;
    PORT
      LAYER Metal3 ;
        RECT 0.000 841.060 0.400 841.460 ;
    END
  END Tile_X0Y2_FrameData[27]
  PIN Tile_X0Y2_FrameData[28]
    DIRECTION INPUT ;
    USE SIGNAL ;
    ANTENNAGATEAREA 1.807000 ;
    PORT
      LAYER Metal3 ;
        RECT 0.000 846.100 0.400 846.500 ;
    END
  END Tile_X0Y2_FrameData[28]
  PIN Tile_X0Y2_FrameData[29]
    DIRECTION INPUT ;
    USE SIGNAL ;
    ANTENNAGATEAREA 1.807000 ;
    PORT
      LAYER Metal3 ;
        RECT 0.000 851.140 0.400 851.540 ;
    END
  END Tile_X0Y2_FrameData[29]
  PIN Tile_X0Y2_FrameData[2]
    DIRECTION INPUT ;
    USE SIGNAL ;
    ANTENNAGATEAREA 1.626300 ;
    PORT
      LAYER Metal3 ;
        RECT 0.000 715.060 0.400 715.460 ;
    END
  END Tile_X0Y2_FrameData[2]
  PIN Tile_X0Y2_FrameData[30]
    DIRECTION INPUT ;
    USE SIGNAL ;
    ANTENNAGATEAREA 1.807000 ;
    PORT
      LAYER Metal3 ;
        RECT 0.000 856.180 0.400 856.580 ;
    END
  END Tile_X0Y2_FrameData[30]
  PIN Tile_X0Y2_FrameData[31]
    DIRECTION INPUT ;
    USE SIGNAL ;
    ANTENNAGATEAREA 1.807000 ;
    PORT
      LAYER Metal3 ;
        RECT 0.000 861.220 0.400 861.620 ;
    END
  END Tile_X0Y2_FrameData[31]
  PIN Tile_X0Y2_FrameData[3]
    DIRECTION INPUT ;
    USE SIGNAL ;
    ANTENNAGATEAREA 1.626300 ;
    PORT
      LAYER Metal3 ;
        RECT 0.000 720.100 0.400 720.500 ;
    END
  END Tile_X0Y2_FrameData[3]
  PIN Tile_X0Y2_FrameData[4]
    DIRECTION INPUT ;
    USE SIGNAL ;
    ANTENNAGATEAREA 1.626300 ;
    PORT
      LAYER Metal3 ;
        RECT 0.000 725.140 0.400 725.540 ;
    END
  END Tile_X0Y2_FrameData[4]
  PIN Tile_X0Y2_FrameData[5]
    DIRECTION INPUT ;
    USE SIGNAL ;
    ANTENNAGATEAREA 1.626300 ;
    PORT
      LAYER Metal3 ;
        RECT 0.000 730.180 0.400 730.580 ;
    END
  END Tile_X0Y2_FrameData[5]
  PIN Tile_X0Y2_FrameData[6]
    DIRECTION INPUT ;
    USE SIGNAL ;
    ANTENNAGATEAREA 1.626300 ;
    PORT
      LAYER Metal3 ;
        RECT 0.000 735.220 0.400 735.620 ;
    END
  END Tile_X0Y2_FrameData[6]
  PIN Tile_X0Y2_FrameData[7]
    DIRECTION INPUT ;
    USE SIGNAL ;
    ANTENNAGATEAREA 1.626300 ;
    PORT
      LAYER Metal3 ;
        RECT 0.000 740.260 0.400 740.660 ;
    END
  END Tile_X0Y2_FrameData[7]
  PIN Tile_X0Y2_FrameData[8]
    DIRECTION INPUT ;
    USE SIGNAL ;
    ANTENNAGATEAREA 1.626300 ;
    PORT
      LAYER Metal3 ;
        RECT 0.000 745.300 0.400 745.700 ;
    END
  END Tile_X0Y2_FrameData[8]
  PIN Tile_X0Y2_FrameData[9]
    DIRECTION INPUT ;
    USE SIGNAL ;
    ANTENNAGATEAREA 1.626300 ;
    PORT
      LAYER Metal3 ;
        RECT 0.000 750.340 0.400 750.740 ;
    END
  END Tile_X0Y2_FrameData[9]
  PIN Tile_X0Y2_FrameData_O[0]
    DIRECTION OUTPUT ;
    USE SIGNAL ;
    ANTENNADIFFAREA 0.708600 ;
    PORT
      LAYER Metal3 ;
        RECT 219.440 738.160 219.840 738.560 ;
    END
  END Tile_X0Y2_FrameData_O[0]
  PIN Tile_X0Y2_FrameData_O[10]
    DIRECTION OUTPUT ;
    USE SIGNAL ;
    ANTENNADIFFAREA 0.708600 ;
    PORT
      LAYER Metal3 ;
        RECT 219.440 746.560 219.840 746.960 ;
    END
  END Tile_X0Y2_FrameData_O[10]
  PIN Tile_X0Y2_FrameData_O[11]
    DIRECTION OUTPUT ;
    USE SIGNAL ;
    ANTENNADIFFAREA 0.708600 ;
    PORT
      LAYER Metal3 ;
        RECT 219.440 747.400 219.840 747.800 ;
    END
  END Tile_X0Y2_FrameData_O[11]
  PIN Tile_X0Y2_FrameData_O[12]
    DIRECTION OUTPUT ;
    USE SIGNAL ;
    ANTENNADIFFAREA 0.708600 ;
    PORT
      LAYER Metal3 ;
        RECT 219.440 748.240 219.840 748.640 ;
    END
  END Tile_X0Y2_FrameData_O[12]
  PIN Tile_X0Y2_FrameData_O[13]
    DIRECTION OUTPUT ;
    USE SIGNAL ;
    ANTENNADIFFAREA 0.708600 ;
    PORT
      LAYER Metal3 ;
        RECT 219.440 749.080 219.840 749.480 ;
    END
  END Tile_X0Y2_FrameData_O[13]
  PIN Tile_X0Y2_FrameData_O[14]
    DIRECTION OUTPUT ;
    USE SIGNAL ;
    ANTENNADIFFAREA 0.708600 ;
    PORT
      LAYER Metal3 ;
        RECT 219.440 749.920 219.840 750.320 ;
    END
  END Tile_X0Y2_FrameData_O[14]
  PIN Tile_X0Y2_FrameData_O[15]
    DIRECTION OUTPUT ;
    USE SIGNAL ;
    ANTENNADIFFAREA 0.708600 ;
    PORT
      LAYER Metal3 ;
        RECT 219.440 750.760 219.840 751.160 ;
    END
  END Tile_X0Y2_FrameData_O[15]
  PIN Tile_X0Y2_FrameData_O[16]
    DIRECTION OUTPUT ;
    USE SIGNAL ;
    ANTENNADIFFAREA 0.708600 ;
    PORT
      LAYER Metal3 ;
        RECT 219.440 751.600 219.840 752.000 ;
    END
  END Tile_X0Y2_FrameData_O[16]
  PIN Tile_X0Y2_FrameData_O[17]
    DIRECTION OUTPUT ;
    USE SIGNAL ;
    ANTENNADIFFAREA 0.708600 ;
    PORT
      LAYER Metal3 ;
        RECT 219.440 752.440 219.840 752.840 ;
    END
  END Tile_X0Y2_FrameData_O[17]
  PIN Tile_X0Y2_FrameData_O[18]
    DIRECTION OUTPUT ;
    USE SIGNAL ;
    ANTENNADIFFAREA 0.708600 ;
    PORT
      LAYER Metal3 ;
        RECT 219.440 753.280 219.840 753.680 ;
    END
  END Tile_X0Y2_FrameData_O[18]
  PIN Tile_X0Y2_FrameData_O[19]
    DIRECTION OUTPUT ;
    USE SIGNAL ;
    ANTENNADIFFAREA 0.708600 ;
    PORT
      LAYER Metal3 ;
        RECT 219.440 754.120 219.840 754.520 ;
    END
  END Tile_X0Y2_FrameData_O[19]
  PIN Tile_X0Y2_FrameData_O[1]
    DIRECTION OUTPUT ;
    USE SIGNAL ;
    ANTENNADIFFAREA 0.708600 ;
    PORT
      LAYER Metal3 ;
        RECT 219.440 739.000 219.840 739.400 ;
    END
  END Tile_X0Y2_FrameData_O[1]
  PIN Tile_X0Y2_FrameData_O[20]
    DIRECTION OUTPUT ;
    USE SIGNAL ;
    ANTENNADIFFAREA 0.708600 ;
    PORT
      LAYER Metal3 ;
        RECT 219.440 754.960 219.840 755.360 ;
    END
  END Tile_X0Y2_FrameData_O[20]
  PIN Tile_X0Y2_FrameData_O[21]
    DIRECTION OUTPUT ;
    USE SIGNAL ;
    ANTENNADIFFAREA 0.708600 ;
    PORT
      LAYER Metal3 ;
        RECT 219.440 755.800 219.840 756.200 ;
    END
  END Tile_X0Y2_FrameData_O[21]
  PIN Tile_X0Y2_FrameData_O[22]
    DIRECTION OUTPUT ;
    USE SIGNAL ;
    ANTENNADIFFAREA 0.708600 ;
    PORT
      LAYER Metal3 ;
        RECT 219.440 756.640 219.840 757.040 ;
    END
  END Tile_X0Y2_FrameData_O[22]
  PIN Tile_X0Y2_FrameData_O[23]
    DIRECTION OUTPUT ;
    USE SIGNAL ;
    ANTENNADIFFAREA 0.708600 ;
    PORT
      LAYER Metal3 ;
        RECT 219.440 757.480 219.840 757.880 ;
    END
  END Tile_X0Y2_FrameData_O[23]
  PIN Tile_X0Y2_FrameData_O[24]
    DIRECTION OUTPUT ;
    USE SIGNAL ;
    ANTENNADIFFAREA 0.708600 ;
    PORT
      LAYER Metal3 ;
        RECT 219.440 758.320 219.840 758.720 ;
    END
  END Tile_X0Y2_FrameData_O[24]
  PIN Tile_X0Y2_FrameData_O[25]
    DIRECTION OUTPUT ;
    USE SIGNAL ;
    ANTENNADIFFAREA 0.708600 ;
    PORT
      LAYER Metal3 ;
        RECT 219.440 759.160 219.840 759.560 ;
    END
  END Tile_X0Y2_FrameData_O[25]
  PIN Tile_X0Y2_FrameData_O[26]
    DIRECTION OUTPUT ;
    USE SIGNAL ;
    ANTENNADIFFAREA 0.708600 ;
    PORT
      LAYER Metal3 ;
        RECT 219.440 760.000 219.840 760.400 ;
    END
  END Tile_X0Y2_FrameData_O[26]
  PIN Tile_X0Y2_FrameData_O[27]
    DIRECTION OUTPUT ;
    USE SIGNAL ;
    ANTENNADIFFAREA 0.708600 ;
    PORT
      LAYER Metal3 ;
        RECT 219.440 760.840 219.840 761.240 ;
    END
  END Tile_X0Y2_FrameData_O[27]
  PIN Tile_X0Y2_FrameData_O[28]
    DIRECTION OUTPUT ;
    USE SIGNAL ;
    ANTENNADIFFAREA 0.708600 ;
    PORT
      LAYER Metal3 ;
        RECT 219.440 761.680 219.840 762.080 ;
    END
  END Tile_X0Y2_FrameData_O[28]
  PIN Tile_X0Y2_FrameData_O[29]
    DIRECTION OUTPUT ;
    USE SIGNAL ;
    ANTENNADIFFAREA 0.708600 ;
    PORT
      LAYER Metal3 ;
        RECT 219.440 762.520 219.840 762.920 ;
    END
  END Tile_X0Y2_FrameData_O[29]
  PIN Tile_X0Y2_FrameData_O[2]
    DIRECTION OUTPUT ;
    USE SIGNAL ;
    ANTENNADIFFAREA 0.708600 ;
    PORT
      LAYER Metal3 ;
        RECT 219.440 739.840 219.840 740.240 ;
    END
  END Tile_X0Y2_FrameData_O[2]
  PIN Tile_X0Y2_FrameData_O[30]
    DIRECTION OUTPUT ;
    USE SIGNAL ;
    ANTENNADIFFAREA 0.708600 ;
    PORT
      LAYER Metal3 ;
        RECT 219.440 763.360 219.840 763.760 ;
    END
  END Tile_X0Y2_FrameData_O[30]
  PIN Tile_X0Y2_FrameData_O[31]
    DIRECTION OUTPUT ;
    USE SIGNAL ;
    ANTENNADIFFAREA 0.708600 ;
    PORT
      LAYER Metal3 ;
        RECT 219.440 764.200 219.840 764.600 ;
    END
  END Tile_X0Y2_FrameData_O[31]
  PIN Tile_X0Y2_FrameData_O[3]
    DIRECTION OUTPUT ;
    USE SIGNAL ;
    ANTENNADIFFAREA 0.708600 ;
    PORT
      LAYER Metal3 ;
        RECT 219.440 740.680 219.840 741.080 ;
    END
  END Tile_X0Y2_FrameData_O[3]
  PIN Tile_X0Y2_FrameData_O[4]
    DIRECTION OUTPUT ;
    USE SIGNAL ;
    ANTENNADIFFAREA 0.708600 ;
    PORT
      LAYER Metal3 ;
        RECT 219.440 741.520 219.840 741.920 ;
    END
  END Tile_X0Y2_FrameData_O[4]
  PIN Tile_X0Y2_FrameData_O[5]
    DIRECTION OUTPUT ;
    USE SIGNAL ;
    ANTENNADIFFAREA 0.708600 ;
    PORT
      LAYER Metal3 ;
        RECT 219.440 742.360 219.840 742.760 ;
    END
  END Tile_X0Y2_FrameData_O[5]
  PIN Tile_X0Y2_FrameData_O[6]
    DIRECTION OUTPUT ;
    USE SIGNAL ;
    ANTENNADIFFAREA 0.708600 ;
    PORT
      LAYER Metal3 ;
        RECT 219.440 743.200 219.840 743.600 ;
    END
  END Tile_X0Y2_FrameData_O[6]
  PIN Tile_X0Y2_FrameData_O[7]
    DIRECTION OUTPUT ;
    USE SIGNAL ;
    ANTENNADIFFAREA 0.708600 ;
    PORT
      LAYER Metal3 ;
        RECT 219.440 744.040 219.840 744.440 ;
    END
  END Tile_X0Y2_FrameData_O[7]
  PIN Tile_X0Y2_FrameData_O[8]
    DIRECTION OUTPUT ;
    USE SIGNAL ;
    ANTENNADIFFAREA 0.708600 ;
    PORT
      LAYER Metal3 ;
        RECT 219.440 744.880 219.840 745.280 ;
    END
  END Tile_X0Y2_FrameData_O[8]
  PIN Tile_X0Y2_FrameData_O[9]
    DIRECTION OUTPUT ;
    USE SIGNAL ;
    ANTENNADIFFAREA 0.708600 ;
    PORT
      LAYER Metal3 ;
        RECT 219.440 745.720 219.840 746.120 ;
    END
  END Tile_X0Y2_FrameData_O[9]
  PIN Tile_X0Y2_W1END[0]
    DIRECTION INPUT ;
    USE SIGNAL ;
    ANTENNAGATEAREA 1.279200 ;
    PORT
      LAYER Metal3 ;
        RECT 219.440 657.520 219.840 657.920 ;
    END
  END Tile_X0Y2_W1END[0]
  PIN Tile_X0Y2_W1END[1]
    DIRECTION INPUT ;
    USE SIGNAL ;
    ANTENNAGATEAREA 1.279200 ;
    PORT
      LAYER Metal3 ;
        RECT 219.440 658.360 219.840 658.760 ;
    END
  END Tile_X0Y2_W1END[1]
  PIN Tile_X0Y2_W1END[2]
    DIRECTION INPUT ;
    USE SIGNAL ;
    ANTENNAGATEAREA 1.279200 ;
    PORT
      LAYER Metal3 ;
        RECT 219.440 659.200 219.840 659.600 ;
    END
  END Tile_X0Y2_W1END[2]
  PIN Tile_X0Y2_W1END[3]
    DIRECTION INPUT ;
    USE SIGNAL ;
    ANTENNAGATEAREA 1.279200 ;
    PORT
      LAYER Metal3 ;
        RECT 219.440 660.040 219.840 660.440 ;
    END
  END Tile_X0Y2_W1END[3]
  PIN Tile_X0Y2_W2END[0]
    DIRECTION INPUT ;
    USE SIGNAL ;
    ANTENNAGATEAREA 0.852800 ;
    PORT
      LAYER Metal3 ;
        RECT 219.440 667.600 219.840 668.000 ;
    END
  END Tile_X0Y2_W2END[0]
  PIN Tile_X0Y2_W2END[1]
    DIRECTION INPUT ;
    USE SIGNAL ;
    ANTENNAGATEAREA 0.852800 ;
    PORT
      LAYER Metal3 ;
        RECT 219.440 668.440 219.840 668.840 ;
    END
  END Tile_X0Y2_W2END[1]
  PIN Tile_X0Y2_W2END[2]
    DIRECTION INPUT ;
    USE SIGNAL ;
    ANTENNAGATEAREA 0.852800 ;
    PORT
      LAYER Metal3 ;
        RECT 219.440 669.280 219.840 669.680 ;
    END
  END Tile_X0Y2_W2END[2]
  PIN Tile_X0Y2_W2END[3]
    DIRECTION INPUT ;
    USE SIGNAL ;
    ANTENNAGATEAREA 0.852800 ;
    PORT
      LAYER Metal3 ;
        RECT 219.440 670.120 219.840 670.520 ;
    END
  END Tile_X0Y2_W2END[3]
  PIN Tile_X0Y2_W2END[4]
    DIRECTION INPUT ;
    USE SIGNAL ;
    ANTENNAGATEAREA 0.852800 ;
    PORT
      LAYER Metal3 ;
        RECT 219.440 670.960 219.840 671.360 ;
    END
  END Tile_X0Y2_W2END[4]
  PIN Tile_X0Y2_W2END[5]
    DIRECTION INPUT ;
    USE SIGNAL ;
    ANTENNAGATEAREA 0.852800 ;
    PORT
      LAYER Metal3 ;
        RECT 219.440 671.800 219.840 672.200 ;
    END
  END Tile_X0Y2_W2END[5]
  PIN Tile_X0Y2_W2END[6]
    DIRECTION INPUT ;
    USE SIGNAL ;
    ANTENNAGATEAREA 0.852800 ;
    PORT
      LAYER Metal3 ;
        RECT 219.440 672.640 219.840 673.040 ;
    END
  END Tile_X0Y2_W2END[6]
  PIN Tile_X0Y2_W2END[7]
    DIRECTION INPUT ;
    USE SIGNAL ;
    ANTENNAGATEAREA 0.852800 ;
    PORT
      LAYER Metal3 ;
        RECT 219.440 673.480 219.840 673.880 ;
    END
  END Tile_X0Y2_W2END[7]
  PIN Tile_X0Y2_W2MID[0]
    DIRECTION INPUT ;
    USE SIGNAL ;
    ANTENNAGATEAREA 0.852800 ;
    PORT
      LAYER Metal3 ;
        RECT 219.440 660.880 219.840 661.280 ;
    END
  END Tile_X0Y2_W2MID[0]
  PIN Tile_X0Y2_W2MID[1]
    DIRECTION INPUT ;
    USE SIGNAL ;
    ANTENNAGATEAREA 0.852800 ;
    PORT
      LAYER Metal3 ;
        RECT 219.440 661.720 219.840 662.120 ;
    END
  END Tile_X0Y2_W2MID[1]
  PIN Tile_X0Y2_W2MID[2]
    DIRECTION INPUT ;
    USE SIGNAL ;
    ANTENNAGATEAREA 0.852800 ;
    PORT
      LAYER Metal3 ;
        RECT 219.440 662.560 219.840 662.960 ;
    END
  END Tile_X0Y2_W2MID[2]
  PIN Tile_X0Y2_W2MID[3]
    DIRECTION INPUT ;
    USE SIGNAL ;
    ANTENNAGATEAREA 0.852800 ;
    PORT
      LAYER Metal3 ;
        RECT 219.440 663.400 219.840 663.800 ;
    END
  END Tile_X0Y2_W2MID[3]
  PIN Tile_X0Y2_W2MID[4]
    DIRECTION INPUT ;
    USE SIGNAL ;
    ANTENNAGATEAREA 0.852800 ;
    PORT
      LAYER Metal3 ;
        RECT 219.440 664.240 219.840 664.640 ;
    END
  END Tile_X0Y2_W2MID[4]
  PIN Tile_X0Y2_W2MID[5]
    DIRECTION INPUT ;
    USE SIGNAL ;
    ANTENNAGATEAREA 0.852800 ;
    PORT
      LAYER Metal3 ;
        RECT 219.440 665.080 219.840 665.480 ;
    END
  END Tile_X0Y2_W2MID[5]
  PIN Tile_X0Y2_W2MID[6]
    DIRECTION INPUT ;
    USE SIGNAL ;
    ANTENNAGATEAREA 0.852800 ;
    PORT
      LAYER Metal3 ;
        RECT 219.440 665.920 219.840 666.320 ;
    END
  END Tile_X0Y2_W2MID[6]
  PIN Tile_X0Y2_W2MID[7]
    DIRECTION INPUT ;
    USE SIGNAL ;
    ANTENNAGATEAREA 0.852800 ;
    PORT
      LAYER Metal3 ;
        RECT 219.440 666.760 219.840 667.160 ;
    END
  END Tile_X0Y2_W2MID[7]
  PIN Tile_X0Y2_W6END[0]
    DIRECTION INPUT ;
    USE SIGNAL ;
    ANTENNAGATEAREA 0.881400 ;
    PORT
      LAYER Metal3 ;
        RECT 219.440 687.760 219.840 688.160 ;
    END
  END Tile_X0Y2_W6END[0]
  PIN Tile_X0Y2_W6END[10]
    DIRECTION INPUT ;
    USE SIGNAL ;
    ANTENNAGATEAREA 0.852800 ;
    PORT
      LAYER Metal3 ;
        RECT 219.440 696.160 219.840 696.560 ;
    END
  END Tile_X0Y2_W6END[10]
  PIN Tile_X0Y2_W6END[11]
    DIRECTION INPUT ;
    USE SIGNAL ;
    ANTENNAGATEAREA 0.852800 ;
    PORT
      LAYER Metal3 ;
        RECT 219.440 697.000 219.840 697.400 ;
    END
  END Tile_X0Y2_W6END[11]
  PIN Tile_X0Y2_W6END[1]
    DIRECTION INPUT ;
    USE SIGNAL ;
    ANTENNAGATEAREA 0.881400 ;
    PORT
      LAYER Metal3 ;
        RECT 219.440 688.600 219.840 689.000 ;
    END
  END Tile_X0Y2_W6END[1]
  PIN Tile_X0Y2_W6END[2]
    DIRECTION INPUT ;
    USE SIGNAL ;
    ANTENNAGATEAREA 0.881400 ;
    PORT
      LAYER Metal3 ;
        RECT 219.440 689.440 219.840 689.840 ;
    END
  END Tile_X0Y2_W6END[2]
  PIN Tile_X0Y2_W6END[3]
    DIRECTION INPUT ;
    USE SIGNAL ;
    ANTENNAGATEAREA 0.881400 ;
    PORT
      LAYER Metal3 ;
        RECT 219.440 690.280 219.840 690.680 ;
    END
  END Tile_X0Y2_W6END[3]
  PIN Tile_X0Y2_W6END[4]
    DIRECTION INPUT ;
    USE SIGNAL ;
    ANTENNAGATEAREA 1.066000 ;
    PORT
      LAYER Metal3 ;
        RECT 219.440 691.120 219.840 691.520 ;
    END
  END Tile_X0Y2_W6END[4]
  PIN Tile_X0Y2_W6END[5]
    DIRECTION INPUT ;
    USE SIGNAL ;
    ANTENNAGATEAREA 1.066000 ;
    PORT
      LAYER Metal3 ;
        RECT 219.440 691.960 219.840 692.360 ;
    END
  END Tile_X0Y2_W6END[5]
  PIN Tile_X0Y2_W6END[6]
    DIRECTION INPUT ;
    USE SIGNAL ;
    ANTENNAGATEAREA 1.066000 ;
    PORT
      LAYER Metal3 ;
        RECT 219.440 692.800 219.840 693.200 ;
    END
  END Tile_X0Y2_W6END[6]
  PIN Tile_X0Y2_W6END[7]
    DIRECTION INPUT ;
    USE SIGNAL ;
    ANTENNAGATEAREA 1.066000 ;
    PORT
      LAYER Metal3 ;
        RECT 219.440 693.640 219.840 694.040 ;
    END
  END Tile_X0Y2_W6END[7]
  PIN Tile_X0Y2_W6END[8]
    DIRECTION INPUT ;
    USE SIGNAL ;
    ANTENNAGATEAREA 0.852800 ;
    PORT
      LAYER Metal3 ;
        RECT 219.440 694.480 219.840 694.880 ;
    END
  END Tile_X0Y2_W6END[8]
  PIN Tile_X0Y2_W6END[9]
    DIRECTION INPUT ;
    USE SIGNAL ;
    ANTENNAGATEAREA 0.852800 ;
    PORT
      LAYER Metal3 ;
        RECT 219.440 695.320 219.840 695.720 ;
    END
  END Tile_X0Y2_W6END[9]
  PIN Tile_X0Y2_WW4END[0]
    DIRECTION INPUT ;
    USE SIGNAL ;
    ANTENNAGATEAREA 0.852800 ;
    PORT
      LAYER Metal3 ;
        RECT 219.440 674.320 219.840 674.720 ;
    END
  END Tile_X0Y2_WW4END[0]
  PIN Tile_X0Y2_WW4END[10]
    DIRECTION INPUT ;
    USE SIGNAL ;
    ANTENNAGATEAREA 0.639600 ;
    PORT
      LAYER Metal3 ;
        RECT 219.440 682.720 219.840 683.120 ;
    END
  END Tile_X0Y2_WW4END[10]
  PIN Tile_X0Y2_WW4END[11]
    DIRECTION INPUT ;
    USE SIGNAL ;
    ANTENNAGATEAREA 0.639600 ;
    PORT
      LAYER Metal3 ;
        RECT 219.440 683.560 219.840 683.960 ;
    END
  END Tile_X0Y2_WW4END[11]
  PIN Tile_X0Y2_WW4END[12]
    DIRECTION INPUT ;
    USE SIGNAL ;
    ANTENNAGATEAREA 0.852800 ;
    PORT
      LAYER Metal3 ;
        RECT 219.440 684.400 219.840 684.800 ;
    END
  END Tile_X0Y2_WW4END[12]
  PIN Tile_X0Y2_WW4END[13]
    DIRECTION INPUT ;
    USE SIGNAL ;
    ANTENNAGATEAREA 0.852800 ;
    PORT
      LAYER Metal3 ;
        RECT 219.440 685.240 219.840 685.640 ;
    END
  END Tile_X0Y2_WW4END[13]
  PIN Tile_X0Y2_WW4END[14]
    DIRECTION INPUT ;
    USE SIGNAL ;
    ANTENNAGATEAREA 0.852800 ;
    PORT
      LAYER Metal3 ;
        RECT 219.440 686.080 219.840 686.480 ;
    END
  END Tile_X0Y2_WW4END[14]
  PIN Tile_X0Y2_WW4END[15]
    DIRECTION INPUT ;
    USE SIGNAL ;
    ANTENNAGATEAREA 0.852800 ;
    PORT
      LAYER Metal3 ;
        RECT 219.440 686.920 219.840 687.320 ;
    END
  END Tile_X0Y2_WW4END[15]
  PIN Tile_X0Y2_WW4END[1]
    DIRECTION INPUT ;
    USE SIGNAL ;
    ANTENNAGATEAREA 0.852800 ;
    PORT
      LAYER Metal3 ;
        RECT 219.440 675.160 219.840 675.560 ;
    END
  END Tile_X0Y2_WW4END[1]
  PIN Tile_X0Y2_WW4END[2]
    DIRECTION INPUT ;
    USE SIGNAL ;
    ANTENNAGATEAREA 0.852800 ;
    PORT
      LAYER Metal3 ;
        RECT 219.440 676.000 219.840 676.400 ;
    END
  END Tile_X0Y2_WW4END[2]
  PIN Tile_X0Y2_WW4END[3]
    DIRECTION INPUT ;
    USE SIGNAL ;
    ANTENNAGATEAREA 0.852800 ;
    PORT
      LAYER Metal3 ;
        RECT 219.440 676.840 219.840 677.240 ;
    END
  END Tile_X0Y2_WW4END[3]
  PIN Tile_X0Y2_WW4END[4]
    DIRECTION INPUT ;
    USE SIGNAL ;
    ANTENNAGATEAREA 0.639600 ;
    PORT
      LAYER Metal3 ;
        RECT 219.440 677.680 219.840 678.080 ;
    END
  END Tile_X0Y2_WW4END[4]
  PIN Tile_X0Y2_WW4END[5]
    DIRECTION INPUT ;
    USE SIGNAL ;
    ANTENNAGATEAREA 0.639600 ;
    PORT
      LAYER Metal3 ;
        RECT 219.440 678.520 219.840 678.920 ;
    END
  END Tile_X0Y2_WW4END[5]
  PIN Tile_X0Y2_WW4END[6]
    DIRECTION INPUT ;
    USE SIGNAL ;
    ANTENNAGATEAREA 0.639600 ;
    PORT
      LAYER Metal3 ;
        RECT 219.440 679.360 219.840 679.760 ;
    END
  END Tile_X0Y2_WW4END[6]
  PIN Tile_X0Y2_WW4END[7]
    DIRECTION INPUT ;
    USE SIGNAL ;
    ANTENNAGATEAREA 0.639600 ;
    PORT
      LAYER Metal3 ;
        RECT 219.440 680.200 219.840 680.600 ;
    END
  END Tile_X0Y2_WW4END[7]
  PIN Tile_X0Y2_WW4END[8]
    DIRECTION INPUT ;
    USE SIGNAL ;
    ANTENNAGATEAREA 0.639600 ;
    PORT
      LAYER Metal3 ;
        RECT 219.440 681.040 219.840 681.440 ;
    END
  END Tile_X0Y2_WW4END[8]
  PIN Tile_X0Y2_WW4END[9]
    DIRECTION INPUT ;
    USE SIGNAL ;
    ANTENNAGATEAREA 0.639600 ;
    PORT
      LAYER Metal3 ;
        RECT 219.440 681.880 219.840 682.280 ;
    END
  END Tile_X0Y2_WW4END[9]
  PIN Tile_X0Y3_E1BEG[0]
    DIRECTION OUTPUT ;
    USE SIGNAL ;
    ANTENNADIFFAREA 0.708600 ;
    PORT
      LAYER Metal3 ;
        RECT 219.440 494.560 219.840 494.960 ;
    END
  END Tile_X0Y3_E1BEG[0]
  PIN Tile_X0Y3_E1BEG[1]
    DIRECTION OUTPUT ;
    USE SIGNAL ;
    ANTENNADIFFAREA 0.708600 ;
    PORT
      LAYER Metal3 ;
        RECT 219.440 495.400 219.840 495.800 ;
    END
  END Tile_X0Y3_E1BEG[1]
  PIN Tile_X0Y3_E1BEG[2]
    DIRECTION OUTPUT ;
    USE SIGNAL ;
    ANTENNADIFFAREA 0.708600 ;
    PORT
      LAYER Metal3 ;
        RECT 219.440 496.240 219.840 496.640 ;
    END
  END Tile_X0Y3_E1BEG[2]
  PIN Tile_X0Y3_E1BEG[3]
    DIRECTION OUTPUT ;
    USE SIGNAL ;
    ANTENNADIFFAREA 0.708600 ;
    PORT
      LAYER Metal3 ;
        RECT 219.440 497.080 219.840 497.480 ;
    END
  END Tile_X0Y3_E1BEG[3]
  PIN Tile_X0Y3_E2BEG[0]
    DIRECTION OUTPUT ;
    USE SIGNAL ;
    ANTENNADIFFAREA 0.708600 ;
    PORT
      LAYER Metal3 ;
        RECT 219.440 497.920 219.840 498.320 ;
    END
  END Tile_X0Y3_E2BEG[0]
  PIN Tile_X0Y3_E2BEG[1]
    DIRECTION OUTPUT ;
    USE SIGNAL ;
    ANTENNADIFFAREA 0.708600 ;
    PORT
      LAYER Metal3 ;
        RECT 219.440 498.760 219.840 499.160 ;
    END
  END Tile_X0Y3_E2BEG[1]
  PIN Tile_X0Y3_E2BEG[2]
    DIRECTION OUTPUT ;
    USE SIGNAL ;
    ANTENNADIFFAREA 0.708600 ;
    PORT
      LAYER Metal3 ;
        RECT 219.440 499.600 219.840 500.000 ;
    END
  END Tile_X0Y3_E2BEG[2]
  PIN Tile_X0Y3_E2BEG[3]
    DIRECTION OUTPUT ;
    USE SIGNAL ;
    ANTENNADIFFAREA 0.708600 ;
    PORT
      LAYER Metal3 ;
        RECT 219.440 500.440 219.840 500.840 ;
    END
  END Tile_X0Y3_E2BEG[3]
  PIN Tile_X0Y3_E2BEG[4]
    DIRECTION OUTPUT ;
    USE SIGNAL ;
    ANTENNADIFFAREA 0.708600 ;
    PORT
      LAYER Metal3 ;
        RECT 219.440 501.280 219.840 501.680 ;
    END
  END Tile_X0Y3_E2BEG[4]
  PIN Tile_X0Y3_E2BEG[5]
    DIRECTION OUTPUT ;
    USE SIGNAL ;
    ANTENNADIFFAREA 0.708600 ;
    PORT
      LAYER Metal3 ;
        RECT 219.440 502.120 219.840 502.520 ;
    END
  END Tile_X0Y3_E2BEG[5]
  PIN Tile_X0Y3_E2BEG[6]
    DIRECTION OUTPUT ;
    USE SIGNAL ;
    ANTENNADIFFAREA 0.708600 ;
    PORT
      LAYER Metal3 ;
        RECT 219.440 502.960 219.840 503.360 ;
    END
  END Tile_X0Y3_E2BEG[6]
  PIN Tile_X0Y3_E2BEG[7]
    DIRECTION OUTPUT ;
    USE SIGNAL ;
    ANTENNADIFFAREA 0.708600 ;
    PORT
      LAYER Metal3 ;
        RECT 219.440 503.800 219.840 504.200 ;
    END
  END Tile_X0Y3_E2BEG[7]
  PIN Tile_X0Y3_E2BEGb[0]
    DIRECTION OUTPUT ;
    USE SIGNAL ;
    ANTENNADIFFAREA 0.708600 ;
    PORT
      LAYER Metal3 ;
        RECT 219.440 504.640 219.840 505.040 ;
    END
  END Tile_X0Y3_E2BEGb[0]
  PIN Tile_X0Y3_E2BEGb[1]
    DIRECTION OUTPUT ;
    USE SIGNAL ;
    ANTENNADIFFAREA 0.708600 ;
    PORT
      LAYER Metal3 ;
        RECT 219.440 505.480 219.840 505.880 ;
    END
  END Tile_X0Y3_E2BEGb[1]
  PIN Tile_X0Y3_E2BEGb[2]
    DIRECTION OUTPUT ;
    USE SIGNAL ;
    ANTENNADIFFAREA 0.708600 ;
    PORT
      LAYER Metal3 ;
        RECT 219.440 506.320 219.840 506.720 ;
    END
  END Tile_X0Y3_E2BEGb[2]
  PIN Tile_X0Y3_E2BEGb[3]
    DIRECTION OUTPUT ;
    USE SIGNAL ;
    ANTENNADIFFAREA 0.708600 ;
    PORT
      LAYER Metal3 ;
        RECT 219.440 507.160 219.840 507.560 ;
    END
  END Tile_X0Y3_E2BEGb[3]
  PIN Tile_X0Y3_E2BEGb[4]
    DIRECTION OUTPUT ;
    USE SIGNAL ;
    ANTENNADIFFAREA 0.708600 ;
    PORT
      LAYER Metal3 ;
        RECT 219.440 508.000 219.840 508.400 ;
    END
  END Tile_X0Y3_E2BEGb[4]
  PIN Tile_X0Y3_E2BEGb[5]
    DIRECTION OUTPUT ;
    USE SIGNAL ;
    ANTENNADIFFAREA 0.708600 ;
    PORT
      LAYER Metal3 ;
        RECT 219.440 508.840 219.840 509.240 ;
    END
  END Tile_X0Y3_E2BEGb[5]
  PIN Tile_X0Y3_E2BEGb[6]
    DIRECTION OUTPUT ;
    USE SIGNAL ;
    ANTENNADIFFAREA 0.708600 ;
    PORT
      LAYER Metal3 ;
        RECT 219.440 509.680 219.840 510.080 ;
    END
  END Tile_X0Y3_E2BEGb[6]
  PIN Tile_X0Y3_E2BEGb[7]
    DIRECTION OUTPUT ;
    USE SIGNAL ;
    ANTENNADIFFAREA 0.708600 ;
    PORT
      LAYER Metal3 ;
        RECT 219.440 510.520 219.840 510.920 ;
    END
  END Tile_X0Y3_E2BEGb[7]
  PIN Tile_X0Y3_E6BEG[0]
    DIRECTION OUTPUT ;
    USE SIGNAL ;
    ANTENNADIFFAREA 0.708600 ;
    PORT
      LAYER Metal3 ;
        RECT 219.440 524.800 219.840 525.200 ;
    END
  END Tile_X0Y3_E6BEG[0]
  PIN Tile_X0Y3_E6BEG[10]
    DIRECTION OUTPUT ;
    USE SIGNAL ;
    ANTENNADIFFAREA 0.708600 ;
    PORT
      LAYER Metal3 ;
        RECT 219.440 533.200 219.840 533.600 ;
    END
  END Tile_X0Y3_E6BEG[10]
  PIN Tile_X0Y3_E6BEG[11]
    DIRECTION OUTPUT ;
    USE SIGNAL ;
    ANTENNADIFFAREA 0.708600 ;
    PORT
      LAYER Metal3 ;
        RECT 219.440 534.040 219.840 534.440 ;
    END
  END Tile_X0Y3_E6BEG[11]
  PIN Tile_X0Y3_E6BEG[1]
    DIRECTION OUTPUT ;
    USE SIGNAL ;
    ANTENNADIFFAREA 0.708600 ;
    PORT
      LAYER Metal3 ;
        RECT 219.440 525.640 219.840 526.040 ;
    END
  END Tile_X0Y3_E6BEG[1]
  PIN Tile_X0Y3_E6BEG[2]
    DIRECTION OUTPUT ;
    USE SIGNAL ;
    ANTENNADIFFAREA 0.708600 ;
    PORT
      LAYER Metal3 ;
        RECT 219.440 526.480 219.840 526.880 ;
    END
  END Tile_X0Y3_E6BEG[2]
  PIN Tile_X0Y3_E6BEG[3]
    DIRECTION OUTPUT ;
    USE SIGNAL ;
    ANTENNADIFFAREA 0.708600 ;
    PORT
      LAYER Metal3 ;
        RECT 219.440 527.320 219.840 527.720 ;
    END
  END Tile_X0Y3_E6BEG[3]
  PIN Tile_X0Y3_E6BEG[4]
    DIRECTION OUTPUT ;
    USE SIGNAL ;
    ANTENNADIFFAREA 0.708600 ;
    PORT
      LAYER Metal3 ;
        RECT 219.440 528.160 219.840 528.560 ;
    END
  END Tile_X0Y3_E6BEG[4]
  PIN Tile_X0Y3_E6BEG[5]
    DIRECTION OUTPUT ;
    USE SIGNAL ;
    ANTENNADIFFAREA 0.708600 ;
    PORT
      LAYER Metal3 ;
        RECT 219.440 529.000 219.840 529.400 ;
    END
  END Tile_X0Y3_E6BEG[5]
  PIN Tile_X0Y3_E6BEG[6]
    DIRECTION OUTPUT ;
    USE SIGNAL ;
    ANTENNADIFFAREA 0.708600 ;
    PORT
      LAYER Metal3 ;
        RECT 219.440 529.840 219.840 530.240 ;
    END
  END Tile_X0Y3_E6BEG[6]
  PIN Tile_X0Y3_E6BEG[7]
    DIRECTION OUTPUT ;
    USE SIGNAL ;
    ANTENNADIFFAREA 0.708600 ;
    PORT
      LAYER Metal3 ;
        RECT 219.440 530.680 219.840 531.080 ;
    END
  END Tile_X0Y3_E6BEG[7]
  PIN Tile_X0Y3_E6BEG[8]
    DIRECTION OUTPUT ;
    USE SIGNAL ;
    ANTENNADIFFAREA 0.708600 ;
    PORT
      LAYER Metal3 ;
        RECT 219.440 531.520 219.840 531.920 ;
    END
  END Tile_X0Y3_E6BEG[8]
  PIN Tile_X0Y3_E6BEG[9]
    DIRECTION OUTPUT ;
    USE SIGNAL ;
    ANTENNADIFFAREA 0.708600 ;
    PORT
      LAYER Metal3 ;
        RECT 219.440 532.360 219.840 532.760 ;
    END
  END Tile_X0Y3_E6BEG[9]
  PIN Tile_X0Y3_EE4BEG[0]
    DIRECTION OUTPUT ;
    USE SIGNAL ;
    ANTENNADIFFAREA 0.708600 ;
    PORT
      LAYER Metal3 ;
        RECT 219.440 511.360 219.840 511.760 ;
    END
  END Tile_X0Y3_EE4BEG[0]
  PIN Tile_X0Y3_EE4BEG[10]
    DIRECTION OUTPUT ;
    USE SIGNAL ;
    ANTENNADIFFAREA 0.708600 ;
    PORT
      LAYER Metal3 ;
        RECT 219.440 519.760 219.840 520.160 ;
    END
  END Tile_X0Y3_EE4BEG[10]
  PIN Tile_X0Y3_EE4BEG[11]
    DIRECTION OUTPUT ;
    USE SIGNAL ;
    ANTENNADIFFAREA 0.708600 ;
    PORT
      LAYER Metal3 ;
        RECT 219.440 520.600 219.840 521.000 ;
    END
  END Tile_X0Y3_EE4BEG[11]
  PIN Tile_X0Y3_EE4BEG[12]
    DIRECTION OUTPUT ;
    USE SIGNAL ;
    ANTENNADIFFAREA 0.708600 ;
    PORT
      LAYER Metal3 ;
        RECT 219.440 521.440 219.840 521.840 ;
    END
  END Tile_X0Y3_EE4BEG[12]
  PIN Tile_X0Y3_EE4BEG[13]
    DIRECTION OUTPUT ;
    USE SIGNAL ;
    ANTENNADIFFAREA 0.708600 ;
    PORT
      LAYER Metal3 ;
        RECT 219.440 522.280 219.840 522.680 ;
    END
  END Tile_X0Y3_EE4BEG[13]
  PIN Tile_X0Y3_EE4BEG[14]
    DIRECTION OUTPUT ;
    USE SIGNAL ;
    ANTENNADIFFAREA 0.708600 ;
    PORT
      LAYER Metal3 ;
        RECT 219.440 523.120 219.840 523.520 ;
    END
  END Tile_X0Y3_EE4BEG[14]
  PIN Tile_X0Y3_EE4BEG[15]
    DIRECTION OUTPUT ;
    USE SIGNAL ;
    ANTENNADIFFAREA 0.708600 ;
    PORT
      LAYER Metal3 ;
        RECT 219.440 523.960 219.840 524.360 ;
    END
  END Tile_X0Y3_EE4BEG[15]
  PIN Tile_X0Y3_EE4BEG[1]
    DIRECTION OUTPUT ;
    USE SIGNAL ;
    ANTENNADIFFAREA 0.708600 ;
    PORT
      LAYER Metal3 ;
        RECT 219.440 512.200 219.840 512.600 ;
    END
  END Tile_X0Y3_EE4BEG[1]
  PIN Tile_X0Y3_EE4BEG[2]
    DIRECTION OUTPUT ;
    USE SIGNAL ;
    ANTENNADIFFAREA 0.708600 ;
    PORT
      LAYER Metal3 ;
        RECT 219.440 513.040 219.840 513.440 ;
    END
  END Tile_X0Y3_EE4BEG[2]
  PIN Tile_X0Y3_EE4BEG[3]
    DIRECTION OUTPUT ;
    USE SIGNAL ;
    ANTENNADIFFAREA 0.708600 ;
    PORT
      LAYER Metal3 ;
        RECT 219.440 513.880 219.840 514.280 ;
    END
  END Tile_X0Y3_EE4BEG[3]
  PIN Tile_X0Y3_EE4BEG[4]
    DIRECTION OUTPUT ;
    USE SIGNAL ;
    ANTENNADIFFAREA 0.708600 ;
    PORT
      LAYER Metal3 ;
        RECT 219.440 514.720 219.840 515.120 ;
    END
  END Tile_X0Y3_EE4BEG[4]
  PIN Tile_X0Y3_EE4BEG[5]
    DIRECTION OUTPUT ;
    USE SIGNAL ;
    ANTENNADIFFAREA 0.708600 ;
    PORT
      LAYER Metal3 ;
        RECT 219.440 515.560 219.840 515.960 ;
    END
  END Tile_X0Y3_EE4BEG[5]
  PIN Tile_X0Y3_EE4BEG[6]
    DIRECTION OUTPUT ;
    USE SIGNAL ;
    ANTENNADIFFAREA 0.708600 ;
    PORT
      LAYER Metal3 ;
        RECT 219.440 516.400 219.840 516.800 ;
    END
  END Tile_X0Y3_EE4BEG[6]
  PIN Tile_X0Y3_EE4BEG[7]
    DIRECTION OUTPUT ;
    USE SIGNAL ;
    ANTENNADIFFAREA 0.708600 ;
    PORT
      LAYER Metal3 ;
        RECT 219.440 517.240 219.840 517.640 ;
    END
  END Tile_X0Y3_EE4BEG[7]
  PIN Tile_X0Y3_EE4BEG[8]
    DIRECTION OUTPUT ;
    USE SIGNAL ;
    ANTENNADIFFAREA 0.708600 ;
    PORT
      LAYER Metal3 ;
        RECT 219.440 518.080 219.840 518.480 ;
    END
  END Tile_X0Y3_EE4BEG[8]
  PIN Tile_X0Y3_EE4BEG[9]
    DIRECTION OUTPUT ;
    USE SIGNAL ;
    ANTENNADIFFAREA 0.708600 ;
    PORT
      LAYER Metal3 ;
        RECT 219.440 518.920 219.840 519.320 ;
    END
  END Tile_X0Y3_EE4BEG[9]
  PIN Tile_X0Y3_FrameData[0]
    DIRECTION INPUT ;
    USE SIGNAL ;
    ANTENNAGATEAREA 1.626300 ;
    PORT
      LAYER Metal3 ;
        RECT 0.000 531.100 0.400 531.500 ;
    END
  END Tile_X0Y3_FrameData[0]
  PIN Tile_X0Y3_FrameData[10]
    DIRECTION INPUT ;
    USE SIGNAL ;
    ANTENNAGATEAREA 1.626300 ;
    PORT
      LAYER Metal3 ;
        RECT 0.000 581.500 0.400 581.900 ;
    END
  END Tile_X0Y3_FrameData[10]
  PIN Tile_X0Y3_FrameData[11]
    DIRECTION INPUT ;
    USE SIGNAL ;
    ANTENNAGATEAREA 1.626300 ;
    PORT
      LAYER Metal3 ;
        RECT 0.000 586.540 0.400 586.940 ;
    END
  END Tile_X0Y3_FrameData[11]
  PIN Tile_X0Y3_FrameData[12]
    DIRECTION INPUT ;
    USE SIGNAL ;
    ANTENNAGATEAREA 1.626300 ;
    PORT
      LAYER Metal3 ;
        RECT 0.000 591.580 0.400 591.980 ;
    END
  END Tile_X0Y3_FrameData[12]
  PIN Tile_X0Y3_FrameData[13]
    DIRECTION INPUT ;
    USE SIGNAL ;
    ANTENNAGATEAREA 1.626300 ;
    PORT
      LAYER Metal3 ;
        RECT 0.000 596.620 0.400 597.020 ;
    END
  END Tile_X0Y3_FrameData[13]
  PIN Tile_X0Y3_FrameData[14]
    DIRECTION INPUT ;
    USE SIGNAL ;
    ANTENNAGATEAREA 1.626300 ;
    PORT
      LAYER Metal3 ;
        RECT 0.000 601.660 0.400 602.060 ;
    END
  END Tile_X0Y3_FrameData[14]
  PIN Tile_X0Y3_FrameData[15]
    DIRECTION INPUT ;
    USE SIGNAL ;
    ANTENNAGATEAREA 1.626300 ;
    PORT
      LAYER Metal3 ;
        RECT 0.000 606.700 0.400 607.100 ;
    END
  END Tile_X0Y3_FrameData[15]
  PIN Tile_X0Y3_FrameData[16]
    DIRECTION INPUT ;
    USE SIGNAL ;
    ANTENNAGATEAREA 1.807000 ;
    PORT
      LAYER Metal3 ;
        RECT 0.000 611.740 0.400 612.140 ;
    END
  END Tile_X0Y3_FrameData[16]
  PIN Tile_X0Y3_FrameData[17]
    DIRECTION INPUT ;
    USE SIGNAL ;
    ANTENNAGATEAREA 1.807000 ;
    PORT
      LAYER Metal3 ;
        RECT 0.000 616.780 0.400 617.180 ;
    END
  END Tile_X0Y3_FrameData[17]
  PIN Tile_X0Y3_FrameData[18]
    DIRECTION INPUT ;
    USE SIGNAL ;
    ANTENNAGATEAREA 1.807000 ;
    PORT
      LAYER Metal3 ;
        RECT 0.000 621.820 0.400 622.220 ;
    END
  END Tile_X0Y3_FrameData[18]
  PIN Tile_X0Y3_FrameData[19]
    DIRECTION INPUT ;
    USE SIGNAL ;
    ANTENNAGATEAREA 1.807000 ;
    PORT
      LAYER Metal3 ;
        RECT 0.000 626.860 0.400 627.260 ;
    END
  END Tile_X0Y3_FrameData[19]
  PIN Tile_X0Y3_FrameData[1]
    DIRECTION INPUT ;
    USE SIGNAL ;
    ANTENNAGATEAREA 1.626300 ;
    PORT
      LAYER Metal3 ;
        RECT 0.000 536.140 0.400 536.540 ;
    END
  END Tile_X0Y3_FrameData[1]
  PIN Tile_X0Y3_FrameData[20]
    DIRECTION INPUT ;
    USE SIGNAL ;
    ANTENNAGATEAREA 1.807000 ;
    PORT
      LAYER Metal3 ;
        RECT 0.000 631.900 0.400 632.300 ;
    END
  END Tile_X0Y3_FrameData[20]
  PIN Tile_X0Y3_FrameData[21]
    DIRECTION INPUT ;
    USE SIGNAL ;
    ANTENNAGATEAREA 1.807000 ;
    PORT
      LAYER Metal3 ;
        RECT 0.000 636.940 0.400 637.340 ;
    END
  END Tile_X0Y3_FrameData[21]
  PIN Tile_X0Y3_FrameData[22]
    DIRECTION INPUT ;
    USE SIGNAL ;
    ANTENNAGATEAREA 1.807000 ;
    PORT
      LAYER Metal3 ;
        RECT 0.000 641.980 0.400 642.380 ;
    END
  END Tile_X0Y3_FrameData[22]
  PIN Tile_X0Y3_FrameData[23]
    DIRECTION INPUT ;
    USE SIGNAL ;
    ANTENNAGATEAREA 1.807000 ;
    PORT
      LAYER Metal3 ;
        RECT 0.000 647.020 0.400 647.420 ;
    END
  END Tile_X0Y3_FrameData[23]
  PIN Tile_X0Y3_FrameData[24]
    DIRECTION INPUT ;
    USE SIGNAL ;
    ANTENNAGATEAREA 1.807000 ;
    PORT
      LAYER Metal3 ;
        RECT 0.000 652.060 0.400 652.460 ;
    END
  END Tile_X0Y3_FrameData[24]
  PIN Tile_X0Y3_FrameData[25]
    DIRECTION INPUT ;
    USE SIGNAL ;
    ANTENNAGATEAREA 1.807000 ;
    ANTENNADIFFAREA 20.153999 ;
    PORT
      LAYER Metal3 ;
        RECT 0.000 657.100 0.400 657.500 ;
    END
  END Tile_X0Y3_FrameData[25]
  PIN Tile_X0Y3_FrameData[26]
    DIRECTION INPUT ;
    USE SIGNAL ;
    ANTENNAGATEAREA 1.807000 ;
    PORT
      LAYER Metal3 ;
        RECT 0.000 662.140 0.400 662.540 ;
    END
  END Tile_X0Y3_FrameData[26]
  PIN Tile_X0Y3_FrameData[27]
    DIRECTION INPUT ;
    USE SIGNAL ;
    ANTENNAGATEAREA 1.807000 ;
    PORT
      LAYER Metal3 ;
        RECT 0.000 667.180 0.400 667.580 ;
    END
  END Tile_X0Y3_FrameData[27]
  PIN Tile_X0Y3_FrameData[28]
    DIRECTION INPUT ;
    USE SIGNAL ;
    ANTENNAGATEAREA 1.807000 ;
    PORT
      LAYER Metal3 ;
        RECT 0.000 672.220 0.400 672.620 ;
    END
  END Tile_X0Y3_FrameData[28]
  PIN Tile_X0Y3_FrameData[29]
    DIRECTION INPUT ;
    USE SIGNAL ;
    ANTENNAGATEAREA 1.807000 ;
    PORT
      LAYER Metal3 ;
        RECT 0.000 677.260 0.400 677.660 ;
    END
  END Tile_X0Y3_FrameData[29]
  PIN Tile_X0Y3_FrameData[2]
    DIRECTION INPUT ;
    USE SIGNAL ;
    ANTENNAGATEAREA 1.626300 ;
    PORT
      LAYER Metal3 ;
        RECT 0.000 541.180 0.400 541.580 ;
    END
  END Tile_X0Y3_FrameData[2]
  PIN Tile_X0Y3_FrameData[30]
    DIRECTION INPUT ;
    USE SIGNAL ;
    ANTENNAGATEAREA 1.807000 ;
    PORT
      LAYER Metal3 ;
        RECT 0.000 682.300 0.400 682.700 ;
    END
  END Tile_X0Y3_FrameData[30]
  PIN Tile_X0Y3_FrameData[31]
    DIRECTION INPUT ;
    USE SIGNAL ;
    ANTENNAGATEAREA 1.807000 ;
    PORT
      LAYER Metal3 ;
        RECT 0.000 687.340 0.400 687.740 ;
    END
  END Tile_X0Y3_FrameData[31]
  PIN Tile_X0Y3_FrameData[3]
    DIRECTION INPUT ;
    USE SIGNAL ;
    ANTENNAGATEAREA 1.626300 ;
    PORT
      LAYER Metal3 ;
        RECT 0.000 546.220 0.400 546.620 ;
    END
  END Tile_X0Y3_FrameData[3]
  PIN Tile_X0Y3_FrameData[4]
    DIRECTION INPUT ;
    USE SIGNAL ;
    ANTENNAGATEAREA 1.626300 ;
    PORT
      LAYER Metal3 ;
        RECT 0.000 551.260 0.400 551.660 ;
    END
  END Tile_X0Y3_FrameData[4]
  PIN Tile_X0Y3_FrameData[5]
    DIRECTION INPUT ;
    USE SIGNAL ;
    ANTENNAGATEAREA 1.626300 ;
    PORT
      LAYER Metal3 ;
        RECT 0.000 556.300 0.400 556.700 ;
    END
  END Tile_X0Y3_FrameData[5]
  PIN Tile_X0Y3_FrameData[6]
    DIRECTION INPUT ;
    USE SIGNAL ;
    ANTENNAGATEAREA 1.626300 ;
    PORT
      LAYER Metal3 ;
        RECT 0.000 561.340 0.400 561.740 ;
    END
  END Tile_X0Y3_FrameData[6]
  PIN Tile_X0Y3_FrameData[7]
    DIRECTION INPUT ;
    USE SIGNAL ;
    ANTENNAGATEAREA 1.626300 ;
    PORT
      LAYER Metal3 ;
        RECT 0.000 566.380 0.400 566.780 ;
    END
  END Tile_X0Y3_FrameData[7]
  PIN Tile_X0Y3_FrameData[8]
    DIRECTION INPUT ;
    USE SIGNAL ;
    ANTENNAGATEAREA 1.626300 ;
    PORT
      LAYER Metal3 ;
        RECT 0.000 571.420 0.400 571.820 ;
    END
  END Tile_X0Y3_FrameData[8]
  PIN Tile_X0Y3_FrameData[9]
    DIRECTION INPUT ;
    USE SIGNAL ;
    ANTENNAGATEAREA 1.626300 ;
    PORT
      LAYER Metal3 ;
        RECT 0.000 576.460 0.400 576.860 ;
    END
  END Tile_X0Y3_FrameData[9]
  PIN Tile_X0Y3_FrameData_O[0]
    DIRECTION OUTPUT ;
    USE SIGNAL ;
    ANTENNADIFFAREA 0.708600 ;
    PORT
      LAYER Metal3 ;
        RECT 219.440 534.880 219.840 535.280 ;
    END
  END Tile_X0Y3_FrameData_O[0]
  PIN Tile_X0Y3_FrameData_O[10]
    DIRECTION OUTPUT ;
    USE SIGNAL ;
    ANTENNADIFFAREA 0.708600 ;
    PORT
      LAYER Metal3 ;
        RECT 219.440 543.280 219.840 543.680 ;
    END
  END Tile_X0Y3_FrameData_O[10]
  PIN Tile_X0Y3_FrameData_O[11]
    DIRECTION OUTPUT ;
    USE SIGNAL ;
    ANTENNADIFFAREA 0.708600 ;
    PORT
      LAYER Metal3 ;
        RECT 219.440 544.120 219.840 544.520 ;
    END
  END Tile_X0Y3_FrameData_O[11]
  PIN Tile_X0Y3_FrameData_O[12]
    DIRECTION OUTPUT ;
    USE SIGNAL ;
    ANTENNADIFFAREA 0.708600 ;
    PORT
      LAYER Metal3 ;
        RECT 219.440 544.960 219.840 545.360 ;
    END
  END Tile_X0Y3_FrameData_O[12]
  PIN Tile_X0Y3_FrameData_O[13]
    DIRECTION OUTPUT ;
    USE SIGNAL ;
    ANTENNADIFFAREA 0.708600 ;
    PORT
      LAYER Metal3 ;
        RECT 219.440 545.800 219.840 546.200 ;
    END
  END Tile_X0Y3_FrameData_O[13]
  PIN Tile_X0Y3_FrameData_O[14]
    DIRECTION OUTPUT ;
    USE SIGNAL ;
    ANTENNADIFFAREA 0.708600 ;
    PORT
      LAYER Metal3 ;
        RECT 219.440 546.640 219.840 547.040 ;
    END
  END Tile_X0Y3_FrameData_O[14]
  PIN Tile_X0Y3_FrameData_O[15]
    DIRECTION OUTPUT ;
    USE SIGNAL ;
    ANTENNADIFFAREA 0.708600 ;
    PORT
      LAYER Metal3 ;
        RECT 219.440 547.480 219.840 547.880 ;
    END
  END Tile_X0Y3_FrameData_O[15]
  PIN Tile_X0Y3_FrameData_O[16]
    DIRECTION OUTPUT ;
    USE SIGNAL ;
    ANTENNADIFFAREA 0.708600 ;
    PORT
      LAYER Metal3 ;
        RECT 219.440 548.320 219.840 548.720 ;
    END
  END Tile_X0Y3_FrameData_O[16]
  PIN Tile_X0Y3_FrameData_O[17]
    DIRECTION OUTPUT ;
    USE SIGNAL ;
    ANTENNADIFFAREA 0.708600 ;
    PORT
      LAYER Metal3 ;
        RECT 219.440 549.160 219.840 549.560 ;
    END
  END Tile_X0Y3_FrameData_O[17]
  PIN Tile_X0Y3_FrameData_O[18]
    DIRECTION OUTPUT ;
    USE SIGNAL ;
    ANTENNADIFFAREA 0.708600 ;
    PORT
      LAYER Metal3 ;
        RECT 219.440 550.000 219.840 550.400 ;
    END
  END Tile_X0Y3_FrameData_O[18]
  PIN Tile_X0Y3_FrameData_O[19]
    DIRECTION OUTPUT ;
    USE SIGNAL ;
    ANTENNADIFFAREA 0.708600 ;
    PORT
      LAYER Metal3 ;
        RECT 219.440 550.840 219.840 551.240 ;
    END
  END Tile_X0Y3_FrameData_O[19]
  PIN Tile_X0Y3_FrameData_O[1]
    DIRECTION OUTPUT ;
    USE SIGNAL ;
    ANTENNADIFFAREA 0.708600 ;
    PORT
      LAYER Metal3 ;
        RECT 219.440 535.720 219.840 536.120 ;
    END
  END Tile_X0Y3_FrameData_O[1]
  PIN Tile_X0Y3_FrameData_O[20]
    DIRECTION OUTPUT ;
    USE SIGNAL ;
    ANTENNADIFFAREA 0.708600 ;
    PORT
      LAYER Metal3 ;
        RECT 219.440 551.680 219.840 552.080 ;
    END
  END Tile_X0Y3_FrameData_O[20]
  PIN Tile_X0Y3_FrameData_O[21]
    DIRECTION OUTPUT ;
    USE SIGNAL ;
    ANTENNADIFFAREA 0.708600 ;
    PORT
      LAYER Metal3 ;
        RECT 219.440 552.520 219.840 552.920 ;
    END
  END Tile_X0Y3_FrameData_O[21]
  PIN Tile_X0Y3_FrameData_O[22]
    DIRECTION OUTPUT ;
    USE SIGNAL ;
    ANTENNADIFFAREA 0.708600 ;
    PORT
      LAYER Metal3 ;
        RECT 219.440 553.360 219.840 553.760 ;
    END
  END Tile_X0Y3_FrameData_O[22]
  PIN Tile_X0Y3_FrameData_O[23]
    DIRECTION OUTPUT ;
    USE SIGNAL ;
    ANTENNADIFFAREA 0.708600 ;
    PORT
      LAYER Metal3 ;
        RECT 219.440 554.200 219.840 554.600 ;
    END
  END Tile_X0Y3_FrameData_O[23]
  PIN Tile_X0Y3_FrameData_O[24]
    DIRECTION OUTPUT ;
    USE SIGNAL ;
    ANTENNADIFFAREA 0.708600 ;
    PORT
      LAYER Metal3 ;
        RECT 219.440 555.040 219.840 555.440 ;
    END
  END Tile_X0Y3_FrameData_O[24]
  PIN Tile_X0Y3_FrameData_O[25]
    DIRECTION OUTPUT ;
    USE SIGNAL ;
    ANTENNADIFFAREA 0.708600 ;
    PORT
      LAYER Metal3 ;
        RECT 219.440 555.880 219.840 556.280 ;
    END
  END Tile_X0Y3_FrameData_O[25]
  PIN Tile_X0Y3_FrameData_O[26]
    DIRECTION OUTPUT ;
    USE SIGNAL ;
    ANTENNADIFFAREA 0.708600 ;
    PORT
      LAYER Metal3 ;
        RECT 219.440 556.720 219.840 557.120 ;
    END
  END Tile_X0Y3_FrameData_O[26]
  PIN Tile_X0Y3_FrameData_O[27]
    DIRECTION OUTPUT ;
    USE SIGNAL ;
    ANTENNADIFFAREA 0.708600 ;
    PORT
      LAYER Metal3 ;
        RECT 219.440 557.560 219.840 557.960 ;
    END
  END Tile_X0Y3_FrameData_O[27]
  PIN Tile_X0Y3_FrameData_O[28]
    DIRECTION OUTPUT ;
    USE SIGNAL ;
    ANTENNADIFFAREA 0.708600 ;
    PORT
      LAYER Metal3 ;
        RECT 219.440 558.400 219.840 558.800 ;
    END
  END Tile_X0Y3_FrameData_O[28]
  PIN Tile_X0Y3_FrameData_O[29]
    DIRECTION OUTPUT ;
    USE SIGNAL ;
    ANTENNADIFFAREA 0.708600 ;
    PORT
      LAYER Metal3 ;
        RECT 219.440 559.240 219.840 559.640 ;
    END
  END Tile_X0Y3_FrameData_O[29]
  PIN Tile_X0Y3_FrameData_O[2]
    DIRECTION OUTPUT ;
    USE SIGNAL ;
    ANTENNADIFFAREA 0.708600 ;
    PORT
      LAYER Metal3 ;
        RECT 219.440 536.560 219.840 536.960 ;
    END
  END Tile_X0Y3_FrameData_O[2]
  PIN Tile_X0Y3_FrameData_O[30]
    DIRECTION OUTPUT ;
    USE SIGNAL ;
    ANTENNADIFFAREA 0.708600 ;
    PORT
      LAYER Metal3 ;
        RECT 219.440 560.080 219.840 560.480 ;
    END
  END Tile_X0Y3_FrameData_O[30]
  PIN Tile_X0Y3_FrameData_O[31]
    DIRECTION OUTPUT ;
    USE SIGNAL ;
    ANTENNADIFFAREA 0.708600 ;
    PORT
      LAYER Metal3 ;
        RECT 219.440 560.920 219.840 561.320 ;
    END
  END Tile_X0Y3_FrameData_O[31]
  PIN Tile_X0Y3_FrameData_O[3]
    DIRECTION OUTPUT ;
    USE SIGNAL ;
    ANTENNADIFFAREA 0.708600 ;
    PORT
      LAYER Metal3 ;
        RECT 219.440 537.400 219.840 537.800 ;
    END
  END Tile_X0Y3_FrameData_O[3]
  PIN Tile_X0Y3_FrameData_O[4]
    DIRECTION OUTPUT ;
    USE SIGNAL ;
    ANTENNADIFFAREA 0.708600 ;
    PORT
      LAYER Metal3 ;
        RECT 219.440 538.240 219.840 538.640 ;
    END
  END Tile_X0Y3_FrameData_O[4]
  PIN Tile_X0Y3_FrameData_O[5]
    DIRECTION OUTPUT ;
    USE SIGNAL ;
    ANTENNADIFFAREA 0.708600 ;
    PORT
      LAYER Metal3 ;
        RECT 219.440 539.080 219.840 539.480 ;
    END
  END Tile_X0Y3_FrameData_O[5]
  PIN Tile_X0Y3_FrameData_O[6]
    DIRECTION OUTPUT ;
    USE SIGNAL ;
    ANTENNADIFFAREA 0.708600 ;
    PORT
      LAYER Metal3 ;
        RECT 219.440 539.920 219.840 540.320 ;
    END
  END Tile_X0Y3_FrameData_O[6]
  PIN Tile_X0Y3_FrameData_O[7]
    DIRECTION OUTPUT ;
    USE SIGNAL ;
    ANTENNADIFFAREA 0.708600 ;
    PORT
      LAYER Metal3 ;
        RECT 219.440 540.760 219.840 541.160 ;
    END
  END Tile_X0Y3_FrameData_O[7]
  PIN Tile_X0Y3_FrameData_O[8]
    DIRECTION OUTPUT ;
    USE SIGNAL ;
    ANTENNADIFFAREA 0.708600 ;
    PORT
      LAYER Metal3 ;
        RECT 219.440 541.600 219.840 542.000 ;
    END
  END Tile_X0Y3_FrameData_O[8]
  PIN Tile_X0Y3_FrameData_O[9]
    DIRECTION OUTPUT ;
    USE SIGNAL ;
    ANTENNADIFFAREA 0.708600 ;
    PORT
      LAYER Metal3 ;
        RECT 219.440 542.440 219.840 542.840 ;
    END
  END Tile_X0Y3_FrameData_O[9]
  PIN Tile_X0Y3_W1END[0]
    DIRECTION INPUT ;
    USE SIGNAL ;
    ANTENNAGATEAREA 1.279200 ;
    PORT
      LAYER Metal3 ;
        RECT 219.440 454.240 219.840 454.640 ;
    END
  END Tile_X0Y3_W1END[0]
  PIN Tile_X0Y3_W1END[1]
    DIRECTION INPUT ;
    USE SIGNAL ;
    ANTENNAGATEAREA 1.279200 ;
    PORT
      LAYER Metal3 ;
        RECT 219.440 455.080 219.840 455.480 ;
    END
  END Tile_X0Y3_W1END[1]
  PIN Tile_X0Y3_W1END[2]
    DIRECTION INPUT ;
    USE SIGNAL ;
    ANTENNAGATEAREA 1.279200 ;
    PORT
      LAYER Metal3 ;
        RECT 219.440 455.920 219.840 456.320 ;
    END
  END Tile_X0Y3_W1END[2]
  PIN Tile_X0Y3_W1END[3]
    DIRECTION INPUT ;
    USE SIGNAL ;
    ANTENNAGATEAREA 1.279200 ;
    PORT
      LAYER Metal3 ;
        RECT 219.440 456.760 219.840 457.160 ;
    END
  END Tile_X0Y3_W1END[3]
  PIN Tile_X0Y3_W2END[0]
    DIRECTION INPUT ;
    USE SIGNAL ;
    ANTENNAGATEAREA 0.852800 ;
    PORT
      LAYER Metal3 ;
        RECT 219.440 464.320 219.840 464.720 ;
    END
  END Tile_X0Y3_W2END[0]
  PIN Tile_X0Y3_W2END[1]
    DIRECTION INPUT ;
    USE SIGNAL ;
    ANTENNAGATEAREA 0.852800 ;
    PORT
      LAYER Metal3 ;
        RECT 219.440 465.160 219.840 465.560 ;
    END
  END Tile_X0Y3_W2END[1]
  PIN Tile_X0Y3_W2END[2]
    DIRECTION INPUT ;
    USE SIGNAL ;
    ANTENNAGATEAREA 0.852800 ;
    PORT
      LAYER Metal3 ;
        RECT 219.440 466.000 219.840 466.400 ;
    END
  END Tile_X0Y3_W2END[2]
  PIN Tile_X0Y3_W2END[3]
    DIRECTION INPUT ;
    USE SIGNAL ;
    ANTENNAGATEAREA 0.852800 ;
    PORT
      LAYER Metal3 ;
        RECT 219.440 466.840 219.840 467.240 ;
    END
  END Tile_X0Y3_W2END[3]
  PIN Tile_X0Y3_W2END[4]
    DIRECTION INPUT ;
    USE SIGNAL ;
    ANTENNAGATEAREA 0.852800 ;
    PORT
      LAYER Metal3 ;
        RECT 219.440 467.680 219.840 468.080 ;
    END
  END Tile_X0Y3_W2END[4]
  PIN Tile_X0Y3_W2END[5]
    DIRECTION INPUT ;
    USE SIGNAL ;
    ANTENNAGATEAREA 0.852800 ;
    PORT
      LAYER Metal3 ;
        RECT 219.440 468.520 219.840 468.920 ;
    END
  END Tile_X0Y3_W2END[5]
  PIN Tile_X0Y3_W2END[6]
    DIRECTION INPUT ;
    USE SIGNAL ;
    ANTENNAGATEAREA 0.852800 ;
    PORT
      LAYER Metal3 ;
        RECT 219.440 469.360 219.840 469.760 ;
    END
  END Tile_X0Y3_W2END[6]
  PIN Tile_X0Y3_W2END[7]
    DIRECTION INPUT ;
    USE SIGNAL ;
    ANTENNAGATEAREA 0.852800 ;
    PORT
      LAYER Metal3 ;
        RECT 219.440 470.200 219.840 470.600 ;
    END
  END Tile_X0Y3_W2END[7]
  PIN Tile_X0Y3_W2MID[0]
    DIRECTION INPUT ;
    USE SIGNAL ;
    ANTENNAGATEAREA 0.852800 ;
    PORT
      LAYER Metal3 ;
        RECT 219.440 457.600 219.840 458.000 ;
    END
  END Tile_X0Y3_W2MID[0]
  PIN Tile_X0Y3_W2MID[1]
    DIRECTION INPUT ;
    USE SIGNAL ;
    ANTENNAGATEAREA 0.852800 ;
    PORT
      LAYER Metal3 ;
        RECT 219.440 458.440 219.840 458.840 ;
    END
  END Tile_X0Y3_W2MID[1]
  PIN Tile_X0Y3_W2MID[2]
    DIRECTION INPUT ;
    USE SIGNAL ;
    ANTENNAGATEAREA 0.852800 ;
    PORT
      LAYER Metal3 ;
        RECT 219.440 459.280 219.840 459.680 ;
    END
  END Tile_X0Y3_W2MID[2]
  PIN Tile_X0Y3_W2MID[3]
    DIRECTION INPUT ;
    USE SIGNAL ;
    ANTENNAGATEAREA 0.852800 ;
    PORT
      LAYER Metal3 ;
        RECT 219.440 460.120 219.840 460.520 ;
    END
  END Tile_X0Y3_W2MID[3]
  PIN Tile_X0Y3_W2MID[4]
    DIRECTION INPUT ;
    USE SIGNAL ;
    ANTENNAGATEAREA 0.852800 ;
    PORT
      LAYER Metal3 ;
        RECT 219.440 460.960 219.840 461.360 ;
    END
  END Tile_X0Y3_W2MID[4]
  PIN Tile_X0Y3_W2MID[5]
    DIRECTION INPUT ;
    USE SIGNAL ;
    ANTENNAGATEAREA 0.852800 ;
    PORT
      LAYER Metal3 ;
        RECT 219.440 461.800 219.840 462.200 ;
    END
  END Tile_X0Y3_W2MID[5]
  PIN Tile_X0Y3_W2MID[6]
    DIRECTION INPUT ;
    USE SIGNAL ;
    ANTENNAGATEAREA 0.852800 ;
    PORT
      LAYER Metal3 ;
        RECT 219.440 462.640 219.840 463.040 ;
    END
  END Tile_X0Y3_W2MID[6]
  PIN Tile_X0Y3_W2MID[7]
    DIRECTION INPUT ;
    USE SIGNAL ;
    ANTENNAGATEAREA 0.852800 ;
    PORT
      LAYER Metal3 ;
        RECT 219.440 463.480 219.840 463.880 ;
    END
  END Tile_X0Y3_W2MID[7]
  PIN Tile_X0Y3_W6END[0]
    DIRECTION INPUT ;
    USE SIGNAL ;
    ANTENNAGATEAREA 0.881400 ;
    PORT
      LAYER Metal3 ;
        RECT 219.440 484.480 219.840 484.880 ;
    END
  END Tile_X0Y3_W6END[0]
  PIN Tile_X0Y3_W6END[10]
    DIRECTION INPUT ;
    USE SIGNAL ;
    ANTENNAGATEAREA 0.852800 ;
    PORT
      LAYER Metal3 ;
        RECT 219.440 492.880 219.840 493.280 ;
    END
  END Tile_X0Y3_W6END[10]
  PIN Tile_X0Y3_W6END[11]
    DIRECTION INPUT ;
    USE SIGNAL ;
    ANTENNAGATEAREA 0.852800 ;
    PORT
      LAYER Metal3 ;
        RECT 219.440 493.720 219.840 494.120 ;
    END
  END Tile_X0Y3_W6END[11]
  PIN Tile_X0Y3_W6END[1]
    DIRECTION INPUT ;
    USE SIGNAL ;
    ANTENNAGATEAREA 0.881400 ;
    PORT
      LAYER Metal3 ;
        RECT 219.440 485.320 219.840 485.720 ;
    END
  END Tile_X0Y3_W6END[1]
  PIN Tile_X0Y3_W6END[2]
    DIRECTION INPUT ;
    USE SIGNAL ;
    ANTENNAGATEAREA 0.881400 ;
    PORT
      LAYER Metal3 ;
        RECT 219.440 486.160 219.840 486.560 ;
    END
  END Tile_X0Y3_W6END[2]
  PIN Tile_X0Y3_W6END[3]
    DIRECTION INPUT ;
    USE SIGNAL ;
    ANTENNAGATEAREA 0.881400 ;
    PORT
      LAYER Metal3 ;
        RECT 219.440 487.000 219.840 487.400 ;
    END
  END Tile_X0Y3_W6END[3]
  PIN Tile_X0Y3_W6END[4]
    DIRECTION INPUT ;
    USE SIGNAL ;
    ANTENNAGATEAREA 1.066000 ;
    PORT
      LAYER Metal3 ;
        RECT 219.440 487.840 219.840 488.240 ;
    END
  END Tile_X0Y3_W6END[4]
  PIN Tile_X0Y3_W6END[5]
    DIRECTION INPUT ;
    USE SIGNAL ;
    ANTENNAGATEAREA 1.066000 ;
    PORT
      LAYER Metal3 ;
        RECT 219.440 488.680 219.840 489.080 ;
    END
  END Tile_X0Y3_W6END[5]
  PIN Tile_X0Y3_W6END[6]
    DIRECTION INPUT ;
    USE SIGNAL ;
    ANTENNAGATEAREA 1.066000 ;
    PORT
      LAYER Metal3 ;
        RECT 219.440 489.520 219.840 489.920 ;
    END
  END Tile_X0Y3_W6END[6]
  PIN Tile_X0Y3_W6END[7]
    DIRECTION INPUT ;
    USE SIGNAL ;
    ANTENNAGATEAREA 1.066000 ;
    PORT
      LAYER Metal3 ;
        RECT 219.440 490.360 219.840 490.760 ;
    END
  END Tile_X0Y3_W6END[7]
  PIN Tile_X0Y3_W6END[8]
    DIRECTION INPUT ;
    USE SIGNAL ;
    ANTENNAGATEAREA 0.852800 ;
    PORT
      LAYER Metal3 ;
        RECT 219.440 491.200 219.840 491.600 ;
    END
  END Tile_X0Y3_W6END[8]
  PIN Tile_X0Y3_W6END[9]
    DIRECTION INPUT ;
    USE SIGNAL ;
    ANTENNAGATEAREA 0.852800 ;
    PORT
      LAYER Metal3 ;
        RECT 219.440 492.040 219.840 492.440 ;
    END
  END Tile_X0Y3_W6END[9]
  PIN Tile_X0Y3_WW4END[0]
    DIRECTION INPUT ;
    USE SIGNAL ;
    ANTENNAGATEAREA 0.852800 ;
    PORT
      LAYER Metal3 ;
        RECT 219.440 471.040 219.840 471.440 ;
    END
  END Tile_X0Y3_WW4END[0]
  PIN Tile_X0Y3_WW4END[10]
    DIRECTION INPUT ;
    USE SIGNAL ;
    ANTENNAGATEAREA 0.639600 ;
    PORT
      LAYER Metal3 ;
        RECT 219.440 479.440 219.840 479.840 ;
    END
  END Tile_X0Y3_WW4END[10]
  PIN Tile_X0Y3_WW4END[11]
    DIRECTION INPUT ;
    USE SIGNAL ;
    ANTENNAGATEAREA 0.639600 ;
    PORT
      LAYER Metal3 ;
        RECT 219.440 480.280 219.840 480.680 ;
    END
  END Tile_X0Y3_WW4END[11]
  PIN Tile_X0Y3_WW4END[12]
    DIRECTION INPUT ;
    USE SIGNAL ;
    ANTENNAGATEAREA 0.852800 ;
    PORT
      LAYER Metal3 ;
        RECT 219.440 481.120 219.840 481.520 ;
    END
  END Tile_X0Y3_WW4END[12]
  PIN Tile_X0Y3_WW4END[13]
    DIRECTION INPUT ;
    USE SIGNAL ;
    ANTENNAGATEAREA 0.852800 ;
    PORT
      LAYER Metal3 ;
        RECT 219.440 481.960 219.840 482.360 ;
    END
  END Tile_X0Y3_WW4END[13]
  PIN Tile_X0Y3_WW4END[14]
    DIRECTION INPUT ;
    USE SIGNAL ;
    ANTENNAGATEAREA 0.852800 ;
    PORT
      LAYER Metal3 ;
        RECT 219.440 482.800 219.840 483.200 ;
    END
  END Tile_X0Y3_WW4END[14]
  PIN Tile_X0Y3_WW4END[15]
    DIRECTION INPUT ;
    USE SIGNAL ;
    ANTENNAGATEAREA 0.852800 ;
    PORT
      LAYER Metal3 ;
        RECT 219.440 483.640 219.840 484.040 ;
    END
  END Tile_X0Y3_WW4END[15]
  PIN Tile_X0Y3_WW4END[1]
    DIRECTION INPUT ;
    USE SIGNAL ;
    ANTENNAGATEAREA 0.852800 ;
    PORT
      LAYER Metal3 ;
        RECT 219.440 471.880 219.840 472.280 ;
    END
  END Tile_X0Y3_WW4END[1]
  PIN Tile_X0Y3_WW4END[2]
    DIRECTION INPUT ;
    USE SIGNAL ;
    ANTENNAGATEAREA 0.852800 ;
    PORT
      LAYER Metal3 ;
        RECT 219.440 472.720 219.840 473.120 ;
    END
  END Tile_X0Y3_WW4END[2]
  PIN Tile_X0Y3_WW4END[3]
    DIRECTION INPUT ;
    USE SIGNAL ;
    ANTENNAGATEAREA 0.852800 ;
    PORT
      LAYER Metal3 ;
        RECT 219.440 473.560 219.840 473.960 ;
    END
  END Tile_X0Y3_WW4END[3]
  PIN Tile_X0Y3_WW4END[4]
    DIRECTION INPUT ;
    USE SIGNAL ;
    ANTENNAGATEAREA 0.639600 ;
    PORT
      LAYER Metal3 ;
        RECT 219.440 474.400 219.840 474.800 ;
    END
  END Tile_X0Y3_WW4END[4]
  PIN Tile_X0Y3_WW4END[5]
    DIRECTION INPUT ;
    USE SIGNAL ;
    ANTENNAGATEAREA 0.639600 ;
    PORT
      LAYER Metal3 ;
        RECT 219.440 475.240 219.840 475.640 ;
    END
  END Tile_X0Y3_WW4END[5]
  PIN Tile_X0Y3_WW4END[6]
    DIRECTION INPUT ;
    USE SIGNAL ;
    ANTENNAGATEAREA 0.639600 ;
    PORT
      LAYER Metal3 ;
        RECT 219.440 476.080 219.840 476.480 ;
    END
  END Tile_X0Y3_WW4END[6]
  PIN Tile_X0Y3_WW4END[7]
    DIRECTION INPUT ;
    USE SIGNAL ;
    ANTENNAGATEAREA 0.639600 ;
    PORT
      LAYER Metal3 ;
        RECT 219.440 476.920 219.840 477.320 ;
    END
  END Tile_X0Y3_WW4END[7]
  PIN Tile_X0Y3_WW4END[8]
    DIRECTION INPUT ;
    USE SIGNAL ;
    ANTENNAGATEAREA 0.639600 ;
    PORT
      LAYER Metal3 ;
        RECT 219.440 477.760 219.840 478.160 ;
    END
  END Tile_X0Y3_WW4END[8]
  PIN Tile_X0Y3_WW4END[9]
    DIRECTION INPUT ;
    USE SIGNAL ;
    ANTENNAGATEAREA 0.639600 ;
    PORT
      LAYER Metal3 ;
        RECT 219.440 478.600 219.840 479.000 ;
    END
  END Tile_X0Y3_WW4END[9]
  PIN Tile_X0Y4_E1BEG[0]
    DIRECTION OUTPUT ;
    USE SIGNAL ;
    ANTENNADIFFAREA 0.708600 ;
    PORT
      LAYER Metal3 ;
        RECT 219.440 291.280 219.840 291.680 ;
    END
  END Tile_X0Y4_E1BEG[0]
  PIN Tile_X0Y4_E1BEG[1]
    DIRECTION OUTPUT ;
    USE SIGNAL ;
    ANTENNADIFFAREA 0.708600 ;
    PORT
      LAYER Metal3 ;
        RECT 219.440 292.120 219.840 292.520 ;
    END
  END Tile_X0Y4_E1BEG[1]
  PIN Tile_X0Y4_E1BEG[2]
    DIRECTION OUTPUT ;
    USE SIGNAL ;
    ANTENNADIFFAREA 0.708600 ;
    PORT
      LAYER Metal3 ;
        RECT 219.440 292.960 219.840 293.360 ;
    END
  END Tile_X0Y4_E1BEG[2]
  PIN Tile_X0Y4_E1BEG[3]
    DIRECTION OUTPUT ;
    USE SIGNAL ;
    ANTENNADIFFAREA 0.708600 ;
    PORT
      LAYER Metal3 ;
        RECT 219.440 293.800 219.840 294.200 ;
    END
  END Tile_X0Y4_E1BEG[3]
  PIN Tile_X0Y4_E2BEG[0]
    DIRECTION OUTPUT ;
    USE SIGNAL ;
    ANTENNADIFFAREA 0.708600 ;
    PORT
      LAYER Metal3 ;
        RECT 219.440 294.640 219.840 295.040 ;
    END
  END Tile_X0Y4_E2BEG[0]
  PIN Tile_X0Y4_E2BEG[1]
    DIRECTION OUTPUT ;
    USE SIGNAL ;
    ANTENNADIFFAREA 0.708600 ;
    PORT
      LAYER Metal3 ;
        RECT 219.440 295.480 219.840 295.880 ;
    END
  END Tile_X0Y4_E2BEG[1]
  PIN Tile_X0Y4_E2BEG[2]
    DIRECTION OUTPUT ;
    USE SIGNAL ;
    ANTENNADIFFAREA 0.708600 ;
    PORT
      LAYER Metal3 ;
        RECT 219.440 296.320 219.840 296.720 ;
    END
  END Tile_X0Y4_E2BEG[2]
  PIN Tile_X0Y4_E2BEG[3]
    DIRECTION OUTPUT ;
    USE SIGNAL ;
    ANTENNADIFFAREA 0.708600 ;
    PORT
      LAYER Metal3 ;
        RECT 219.440 297.160 219.840 297.560 ;
    END
  END Tile_X0Y4_E2BEG[3]
  PIN Tile_X0Y4_E2BEG[4]
    DIRECTION OUTPUT ;
    USE SIGNAL ;
    ANTENNADIFFAREA 0.708600 ;
    PORT
      LAYER Metal3 ;
        RECT 219.440 298.000 219.840 298.400 ;
    END
  END Tile_X0Y4_E2BEG[4]
  PIN Tile_X0Y4_E2BEG[5]
    DIRECTION OUTPUT ;
    USE SIGNAL ;
    ANTENNADIFFAREA 0.708600 ;
    PORT
      LAYER Metal3 ;
        RECT 219.440 298.840 219.840 299.240 ;
    END
  END Tile_X0Y4_E2BEG[5]
  PIN Tile_X0Y4_E2BEG[6]
    DIRECTION OUTPUT ;
    USE SIGNAL ;
    ANTENNADIFFAREA 0.708600 ;
    PORT
      LAYER Metal3 ;
        RECT 219.440 299.680 219.840 300.080 ;
    END
  END Tile_X0Y4_E2BEG[6]
  PIN Tile_X0Y4_E2BEG[7]
    DIRECTION OUTPUT ;
    USE SIGNAL ;
    ANTENNADIFFAREA 0.708600 ;
    PORT
      LAYER Metal3 ;
        RECT 219.440 300.520 219.840 300.920 ;
    END
  END Tile_X0Y4_E2BEG[7]
  PIN Tile_X0Y4_E2BEGb[0]
    DIRECTION OUTPUT ;
    USE SIGNAL ;
    ANTENNADIFFAREA 0.708600 ;
    PORT
      LAYER Metal3 ;
        RECT 219.440 301.360 219.840 301.760 ;
    END
  END Tile_X0Y4_E2BEGb[0]
  PIN Tile_X0Y4_E2BEGb[1]
    DIRECTION OUTPUT ;
    USE SIGNAL ;
    ANTENNADIFFAREA 0.708600 ;
    PORT
      LAYER Metal3 ;
        RECT 219.440 302.200 219.840 302.600 ;
    END
  END Tile_X0Y4_E2BEGb[1]
  PIN Tile_X0Y4_E2BEGb[2]
    DIRECTION OUTPUT ;
    USE SIGNAL ;
    ANTENNADIFFAREA 0.708600 ;
    PORT
      LAYER Metal3 ;
        RECT 219.440 303.040 219.840 303.440 ;
    END
  END Tile_X0Y4_E2BEGb[2]
  PIN Tile_X0Y4_E2BEGb[3]
    DIRECTION OUTPUT ;
    USE SIGNAL ;
    ANTENNADIFFAREA 0.708600 ;
    PORT
      LAYER Metal3 ;
        RECT 219.440 303.880 219.840 304.280 ;
    END
  END Tile_X0Y4_E2BEGb[3]
  PIN Tile_X0Y4_E2BEGb[4]
    DIRECTION OUTPUT ;
    USE SIGNAL ;
    ANTENNADIFFAREA 0.708600 ;
    PORT
      LAYER Metal3 ;
        RECT 219.440 304.720 219.840 305.120 ;
    END
  END Tile_X0Y4_E2BEGb[4]
  PIN Tile_X0Y4_E2BEGb[5]
    DIRECTION OUTPUT ;
    USE SIGNAL ;
    ANTENNADIFFAREA 0.708600 ;
    PORT
      LAYER Metal3 ;
        RECT 219.440 305.560 219.840 305.960 ;
    END
  END Tile_X0Y4_E2BEGb[5]
  PIN Tile_X0Y4_E2BEGb[6]
    DIRECTION OUTPUT ;
    USE SIGNAL ;
    ANTENNADIFFAREA 0.708600 ;
    PORT
      LAYER Metal3 ;
        RECT 219.440 306.400 219.840 306.800 ;
    END
  END Tile_X0Y4_E2BEGb[6]
  PIN Tile_X0Y4_E2BEGb[7]
    DIRECTION OUTPUT ;
    USE SIGNAL ;
    ANTENNADIFFAREA 0.708600 ;
    PORT
      LAYER Metal3 ;
        RECT 219.440 307.240 219.840 307.640 ;
    END
  END Tile_X0Y4_E2BEGb[7]
  PIN Tile_X0Y4_E6BEG[0]
    DIRECTION OUTPUT ;
    USE SIGNAL ;
    ANTENNADIFFAREA 0.708600 ;
    PORT
      LAYER Metal3 ;
        RECT 219.440 321.520 219.840 321.920 ;
    END
  END Tile_X0Y4_E6BEG[0]
  PIN Tile_X0Y4_E6BEG[10]
    DIRECTION OUTPUT ;
    USE SIGNAL ;
    ANTENNADIFFAREA 0.708600 ;
    PORT
      LAYER Metal3 ;
        RECT 219.440 329.920 219.840 330.320 ;
    END
  END Tile_X0Y4_E6BEG[10]
  PIN Tile_X0Y4_E6BEG[11]
    DIRECTION OUTPUT ;
    USE SIGNAL ;
    ANTENNADIFFAREA 0.708600 ;
    PORT
      LAYER Metal3 ;
        RECT 219.440 330.760 219.840 331.160 ;
    END
  END Tile_X0Y4_E6BEG[11]
  PIN Tile_X0Y4_E6BEG[1]
    DIRECTION OUTPUT ;
    USE SIGNAL ;
    ANTENNADIFFAREA 0.708600 ;
    PORT
      LAYER Metal3 ;
        RECT 219.440 322.360 219.840 322.760 ;
    END
  END Tile_X0Y4_E6BEG[1]
  PIN Tile_X0Y4_E6BEG[2]
    DIRECTION OUTPUT ;
    USE SIGNAL ;
    ANTENNADIFFAREA 0.708600 ;
    PORT
      LAYER Metal3 ;
        RECT 219.440 323.200 219.840 323.600 ;
    END
  END Tile_X0Y4_E6BEG[2]
  PIN Tile_X0Y4_E6BEG[3]
    DIRECTION OUTPUT ;
    USE SIGNAL ;
    ANTENNADIFFAREA 0.708600 ;
    PORT
      LAYER Metal3 ;
        RECT 219.440 324.040 219.840 324.440 ;
    END
  END Tile_X0Y4_E6BEG[3]
  PIN Tile_X0Y4_E6BEG[4]
    DIRECTION OUTPUT ;
    USE SIGNAL ;
    ANTENNADIFFAREA 0.708600 ;
    PORT
      LAYER Metal3 ;
        RECT 219.440 324.880 219.840 325.280 ;
    END
  END Tile_X0Y4_E6BEG[4]
  PIN Tile_X0Y4_E6BEG[5]
    DIRECTION OUTPUT ;
    USE SIGNAL ;
    ANTENNADIFFAREA 0.708600 ;
    PORT
      LAYER Metal3 ;
        RECT 219.440 325.720 219.840 326.120 ;
    END
  END Tile_X0Y4_E6BEG[5]
  PIN Tile_X0Y4_E6BEG[6]
    DIRECTION OUTPUT ;
    USE SIGNAL ;
    ANTENNADIFFAREA 0.708600 ;
    PORT
      LAYER Metal3 ;
        RECT 219.440 326.560 219.840 326.960 ;
    END
  END Tile_X0Y4_E6BEG[6]
  PIN Tile_X0Y4_E6BEG[7]
    DIRECTION OUTPUT ;
    USE SIGNAL ;
    ANTENNADIFFAREA 0.708600 ;
    PORT
      LAYER Metal3 ;
        RECT 219.440 327.400 219.840 327.800 ;
    END
  END Tile_X0Y4_E6BEG[7]
  PIN Tile_X0Y4_E6BEG[8]
    DIRECTION OUTPUT ;
    USE SIGNAL ;
    ANTENNADIFFAREA 0.708600 ;
    PORT
      LAYER Metal3 ;
        RECT 219.440 328.240 219.840 328.640 ;
    END
  END Tile_X0Y4_E6BEG[8]
  PIN Tile_X0Y4_E6BEG[9]
    DIRECTION OUTPUT ;
    USE SIGNAL ;
    ANTENNADIFFAREA 0.708600 ;
    PORT
      LAYER Metal3 ;
        RECT 219.440 329.080 219.840 329.480 ;
    END
  END Tile_X0Y4_E6BEG[9]
  PIN Tile_X0Y4_EE4BEG[0]
    DIRECTION OUTPUT ;
    USE SIGNAL ;
    ANTENNADIFFAREA 0.708600 ;
    PORT
      LAYER Metal3 ;
        RECT 219.440 308.080 219.840 308.480 ;
    END
  END Tile_X0Y4_EE4BEG[0]
  PIN Tile_X0Y4_EE4BEG[10]
    DIRECTION OUTPUT ;
    USE SIGNAL ;
    ANTENNADIFFAREA 0.708600 ;
    PORT
      LAYER Metal3 ;
        RECT 219.440 316.480 219.840 316.880 ;
    END
  END Tile_X0Y4_EE4BEG[10]
  PIN Tile_X0Y4_EE4BEG[11]
    DIRECTION OUTPUT ;
    USE SIGNAL ;
    ANTENNADIFFAREA 0.708600 ;
    PORT
      LAYER Metal3 ;
        RECT 219.440 317.320 219.840 317.720 ;
    END
  END Tile_X0Y4_EE4BEG[11]
  PIN Tile_X0Y4_EE4BEG[12]
    DIRECTION OUTPUT ;
    USE SIGNAL ;
    ANTENNADIFFAREA 0.708600 ;
    PORT
      LAYER Metal3 ;
        RECT 219.440 318.160 219.840 318.560 ;
    END
  END Tile_X0Y4_EE4BEG[12]
  PIN Tile_X0Y4_EE4BEG[13]
    DIRECTION OUTPUT ;
    USE SIGNAL ;
    ANTENNADIFFAREA 0.708600 ;
    PORT
      LAYER Metal3 ;
        RECT 219.440 319.000 219.840 319.400 ;
    END
  END Tile_X0Y4_EE4BEG[13]
  PIN Tile_X0Y4_EE4BEG[14]
    DIRECTION OUTPUT ;
    USE SIGNAL ;
    ANTENNADIFFAREA 0.708600 ;
    PORT
      LAYER Metal3 ;
        RECT 219.440 319.840 219.840 320.240 ;
    END
  END Tile_X0Y4_EE4BEG[14]
  PIN Tile_X0Y4_EE4BEG[15]
    DIRECTION OUTPUT ;
    USE SIGNAL ;
    ANTENNADIFFAREA 0.708600 ;
    PORT
      LAYER Metal3 ;
        RECT 219.440 320.680 219.840 321.080 ;
    END
  END Tile_X0Y4_EE4BEG[15]
  PIN Tile_X0Y4_EE4BEG[1]
    DIRECTION OUTPUT ;
    USE SIGNAL ;
    ANTENNADIFFAREA 0.708600 ;
    PORT
      LAYER Metal3 ;
        RECT 219.440 308.920 219.840 309.320 ;
    END
  END Tile_X0Y4_EE4BEG[1]
  PIN Tile_X0Y4_EE4BEG[2]
    DIRECTION OUTPUT ;
    USE SIGNAL ;
    ANTENNADIFFAREA 0.708600 ;
    PORT
      LAYER Metal3 ;
        RECT 219.440 309.760 219.840 310.160 ;
    END
  END Tile_X0Y4_EE4BEG[2]
  PIN Tile_X0Y4_EE4BEG[3]
    DIRECTION OUTPUT ;
    USE SIGNAL ;
    ANTENNADIFFAREA 0.708600 ;
    PORT
      LAYER Metal3 ;
        RECT 219.440 310.600 219.840 311.000 ;
    END
  END Tile_X0Y4_EE4BEG[3]
  PIN Tile_X0Y4_EE4BEG[4]
    DIRECTION OUTPUT ;
    USE SIGNAL ;
    ANTENNADIFFAREA 0.708600 ;
    PORT
      LAYER Metal3 ;
        RECT 219.440 311.440 219.840 311.840 ;
    END
  END Tile_X0Y4_EE4BEG[4]
  PIN Tile_X0Y4_EE4BEG[5]
    DIRECTION OUTPUT ;
    USE SIGNAL ;
    ANTENNADIFFAREA 0.708600 ;
    PORT
      LAYER Metal3 ;
        RECT 219.440 312.280 219.840 312.680 ;
    END
  END Tile_X0Y4_EE4BEG[5]
  PIN Tile_X0Y4_EE4BEG[6]
    DIRECTION OUTPUT ;
    USE SIGNAL ;
    ANTENNADIFFAREA 0.708600 ;
    PORT
      LAYER Metal3 ;
        RECT 219.440 313.120 219.840 313.520 ;
    END
  END Tile_X0Y4_EE4BEG[6]
  PIN Tile_X0Y4_EE4BEG[7]
    DIRECTION OUTPUT ;
    USE SIGNAL ;
    ANTENNADIFFAREA 0.708600 ;
    PORT
      LAYER Metal3 ;
        RECT 219.440 313.960 219.840 314.360 ;
    END
  END Tile_X0Y4_EE4BEG[7]
  PIN Tile_X0Y4_EE4BEG[8]
    DIRECTION OUTPUT ;
    USE SIGNAL ;
    ANTENNADIFFAREA 0.708600 ;
    PORT
      LAYER Metal3 ;
        RECT 219.440 314.800 219.840 315.200 ;
    END
  END Tile_X0Y4_EE4BEG[8]
  PIN Tile_X0Y4_EE4BEG[9]
    DIRECTION OUTPUT ;
    USE SIGNAL ;
    ANTENNADIFFAREA 0.708600 ;
    PORT
      LAYER Metal3 ;
        RECT 219.440 315.640 219.840 316.040 ;
    END
  END Tile_X0Y4_EE4BEG[9]
  PIN Tile_X0Y4_FrameData[0]
    DIRECTION INPUT ;
    USE SIGNAL ;
    ANTENNAGATEAREA 1.626300 ;
    PORT
      LAYER Metal3 ;
        RECT 0.000 356.800 0.400 357.200 ;
    END
  END Tile_X0Y4_FrameData[0]
  PIN Tile_X0Y4_FrameData[10]
    DIRECTION INPUT ;
    USE SIGNAL ;
    ANTENNAGATEAREA 1.626300 ;
    PORT
      LAYER Metal3 ;
        RECT 0.000 407.200 0.400 407.600 ;
    END
  END Tile_X0Y4_FrameData[10]
  PIN Tile_X0Y4_FrameData[11]
    DIRECTION INPUT ;
    USE SIGNAL ;
    ANTENNAGATEAREA 1.626300 ;
    PORT
      LAYER Metal3 ;
        RECT 0.000 412.240 0.400 412.640 ;
    END
  END Tile_X0Y4_FrameData[11]
  PIN Tile_X0Y4_FrameData[12]
    DIRECTION INPUT ;
    USE SIGNAL ;
    ANTENNAGATEAREA 1.626300 ;
    PORT
      LAYER Metal3 ;
        RECT 0.000 417.280 0.400 417.680 ;
    END
  END Tile_X0Y4_FrameData[12]
  PIN Tile_X0Y4_FrameData[13]
    DIRECTION INPUT ;
    USE SIGNAL ;
    ANTENNAGATEAREA 1.626300 ;
    PORT
      LAYER Metal3 ;
        RECT 0.000 422.320 0.400 422.720 ;
    END
  END Tile_X0Y4_FrameData[13]
  PIN Tile_X0Y4_FrameData[14]
    DIRECTION INPUT ;
    USE SIGNAL ;
    ANTENNAGATEAREA 1.626300 ;
    PORT
      LAYER Metal3 ;
        RECT 0.000 427.360 0.400 427.760 ;
    END
  END Tile_X0Y4_FrameData[14]
  PIN Tile_X0Y4_FrameData[15]
    DIRECTION INPUT ;
    USE SIGNAL ;
    ANTENNAGATEAREA 1.626300 ;
    ANTENNADIFFAREA 18.138599 ;
    PORT
      LAYER Metal3 ;
        RECT 0.000 432.400 0.400 432.800 ;
    END
  END Tile_X0Y4_FrameData[15]
  PIN Tile_X0Y4_FrameData[16]
    DIRECTION INPUT ;
    USE SIGNAL ;
    ANTENNAGATEAREA 1.807000 ;
    PORT
      LAYER Metal3 ;
        RECT 0.000 437.440 0.400 437.840 ;
    END
  END Tile_X0Y4_FrameData[16]
  PIN Tile_X0Y4_FrameData[17]
    DIRECTION INPUT ;
    USE SIGNAL ;
    ANTENNAGATEAREA 1.807000 ;
    PORT
      LAYER Metal3 ;
        RECT 0.000 442.480 0.400 442.880 ;
    END
  END Tile_X0Y4_FrameData[17]
  PIN Tile_X0Y4_FrameData[18]
    DIRECTION INPUT ;
    USE SIGNAL ;
    ANTENNAGATEAREA 1.807000 ;
    PORT
      LAYER Metal3 ;
        RECT 0.000 447.520 0.400 447.920 ;
    END
  END Tile_X0Y4_FrameData[18]
  PIN Tile_X0Y4_FrameData[19]
    DIRECTION INPUT ;
    USE SIGNAL ;
    ANTENNAGATEAREA 1.807000 ;
    PORT
      LAYER Metal3 ;
        RECT 0.000 452.560 0.400 452.960 ;
    END
  END Tile_X0Y4_FrameData[19]
  PIN Tile_X0Y4_FrameData[1]
    DIRECTION INPUT ;
    USE SIGNAL ;
    ANTENNAGATEAREA 1.626300 ;
    PORT
      LAYER Metal3 ;
        RECT 0.000 361.840 0.400 362.240 ;
    END
  END Tile_X0Y4_FrameData[1]
  PIN Tile_X0Y4_FrameData[20]
    DIRECTION INPUT ;
    USE SIGNAL ;
    ANTENNAGATEAREA 1.807000 ;
    PORT
      LAYER Metal3 ;
        RECT 0.000 457.600 0.400 458.000 ;
    END
  END Tile_X0Y4_FrameData[20]
  PIN Tile_X0Y4_FrameData[21]
    DIRECTION INPUT ;
    USE SIGNAL ;
    ANTENNAGATEAREA 1.807000 ;
    PORT
      LAYER Metal3 ;
        RECT 0.000 462.640 0.400 463.040 ;
    END
  END Tile_X0Y4_FrameData[21]
  PIN Tile_X0Y4_FrameData[22]
    DIRECTION INPUT ;
    USE SIGNAL ;
    ANTENNAGATEAREA 1.807000 ;
    PORT
      LAYER Metal3 ;
        RECT 0.000 467.680 0.400 468.080 ;
    END
  END Tile_X0Y4_FrameData[22]
  PIN Tile_X0Y4_FrameData[23]
    DIRECTION INPUT ;
    USE SIGNAL ;
    ANTENNAGATEAREA 1.807000 ;
    PORT
      LAYER Metal3 ;
        RECT 0.000 472.720 0.400 473.120 ;
    END
  END Tile_X0Y4_FrameData[23]
  PIN Tile_X0Y4_FrameData[24]
    DIRECTION INPUT ;
    USE SIGNAL ;
    ANTENNAGATEAREA 1.807000 ;
    PORT
      LAYER Metal3 ;
        RECT 0.000 477.760 0.400 478.160 ;
    END
  END Tile_X0Y4_FrameData[24]
  PIN Tile_X0Y4_FrameData[25]
    DIRECTION INPUT ;
    USE SIGNAL ;
    ANTENNAGATEAREA 1.807000 ;
    PORT
      LAYER Metal3 ;
        RECT 0.000 482.800 0.400 483.200 ;
    END
  END Tile_X0Y4_FrameData[25]
  PIN Tile_X0Y4_FrameData[26]
    DIRECTION INPUT ;
    USE SIGNAL ;
    ANTENNAGATEAREA 1.807000 ;
    PORT
      LAYER Metal3 ;
        RECT 0.000 487.840 0.400 488.240 ;
    END
  END Tile_X0Y4_FrameData[26]
  PIN Tile_X0Y4_FrameData[27]
    DIRECTION INPUT ;
    USE SIGNAL ;
    ANTENNAGATEAREA 1.807000 ;
    PORT
      LAYER Metal3 ;
        RECT 0.000 492.880 0.400 493.280 ;
    END
  END Tile_X0Y4_FrameData[27]
  PIN Tile_X0Y4_FrameData[28]
    DIRECTION INPUT ;
    USE SIGNAL ;
    ANTENNAGATEAREA 1.807000 ;
    PORT
      LAYER Metal3 ;
        RECT 0.000 497.920 0.400 498.320 ;
    END
  END Tile_X0Y4_FrameData[28]
  PIN Tile_X0Y4_FrameData[29]
    DIRECTION INPUT ;
    USE SIGNAL ;
    ANTENNAGATEAREA 1.807000 ;
    PORT
      LAYER Metal3 ;
        RECT 0.000 502.960 0.400 503.360 ;
    END
  END Tile_X0Y4_FrameData[29]
  PIN Tile_X0Y4_FrameData[2]
    DIRECTION INPUT ;
    USE SIGNAL ;
    ANTENNAGATEAREA 1.626300 ;
    PORT
      LAYER Metal3 ;
        RECT 0.000 366.880 0.400 367.280 ;
    END
  END Tile_X0Y4_FrameData[2]
  PIN Tile_X0Y4_FrameData[30]
    DIRECTION INPUT ;
    USE SIGNAL ;
    ANTENNAGATEAREA 1.807000 ;
    ANTENNADIFFAREA 20.153999 ;
    PORT
      LAYER Metal3 ;
        RECT 0.000 508.000 0.400 508.400 ;
    END
  END Tile_X0Y4_FrameData[30]
  PIN Tile_X0Y4_FrameData[31]
    DIRECTION INPUT ;
    USE SIGNAL ;
    ANTENNAGATEAREA 1.807000 ;
    PORT
      LAYER Metal3 ;
        RECT 0.000 513.040 0.400 513.440 ;
    END
  END Tile_X0Y4_FrameData[31]
  PIN Tile_X0Y4_FrameData[3]
    DIRECTION INPUT ;
    USE SIGNAL ;
    ANTENNAGATEAREA 1.626300 ;
    PORT
      LAYER Metal3 ;
        RECT 0.000 371.920 0.400 372.320 ;
    END
  END Tile_X0Y4_FrameData[3]
  PIN Tile_X0Y4_FrameData[4]
    DIRECTION INPUT ;
    USE SIGNAL ;
    ANTENNAGATEAREA 1.626300 ;
    PORT
      LAYER Metal3 ;
        RECT 0.000 376.960 0.400 377.360 ;
    END
  END Tile_X0Y4_FrameData[4]
  PIN Tile_X0Y4_FrameData[5]
    DIRECTION INPUT ;
    USE SIGNAL ;
    ANTENNAGATEAREA 1.626300 ;
    PORT
      LAYER Metal3 ;
        RECT 0.000 382.000 0.400 382.400 ;
    END
  END Tile_X0Y4_FrameData[5]
  PIN Tile_X0Y4_FrameData[6]
    DIRECTION INPUT ;
    USE SIGNAL ;
    ANTENNAGATEAREA 1.626300 ;
    PORT
      LAYER Metal3 ;
        RECT 0.000 387.040 0.400 387.440 ;
    END
  END Tile_X0Y4_FrameData[6]
  PIN Tile_X0Y4_FrameData[7]
    DIRECTION INPUT ;
    USE SIGNAL ;
    ANTENNAGATEAREA 1.626300 ;
    PORT
      LAYER Metal3 ;
        RECT 0.000 392.080 0.400 392.480 ;
    END
  END Tile_X0Y4_FrameData[7]
  PIN Tile_X0Y4_FrameData[8]
    DIRECTION INPUT ;
    USE SIGNAL ;
    ANTENNAGATEAREA 1.626300 ;
    PORT
      LAYER Metal3 ;
        RECT 0.000 397.120 0.400 397.520 ;
    END
  END Tile_X0Y4_FrameData[8]
  PIN Tile_X0Y4_FrameData[9]
    DIRECTION INPUT ;
    USE SIGNAL ;
    ANTENNAGATEAREA 1.626300 ;
    PORT
      LAYER Metal3 ;
        RECT 0.000 402.160 0.400 402.560 ;
    END
  END Tile_X0Y4_FrameData[9]
  PIN Tile_X0Y4_FrameData_O[0]
    DIRECTION OUTPUT ;
    USE SIGNAL ;
    ANTENNADIFFAREA 0.708600 ;
    PORT
      LAYER Metal3 ;
        RECT 219.440 331.600 219.840 332.000 ;
    END
  END Tile_X0Y4_FrameData_O[0]
  PIN Tile_X0Y4_FrameData_O[10]
    DIRECTION OUTPUT ;
    USE SIGNAL ;
    ANTENNADIFFAREA 0.708600 ;
    PORT
      LAYER Metal3 ;
        RECT 219.440 340.000 219.840 340.400 ;
    END
  END Tile_X0Y4_FrameData_O[10]
  PIN Tile_X0Y4_FrameData_O[11]
    DIRECTION OUTPUT ;
    USE SIGNAL ;
    ANTENNADIFFAREA 0.708600 ;
    PORT
      LAYER Metal3 ;
        RECT 219.440 340.840 219.840 341.240 ;
    END
  END Tile_X0Y4_FrameData_O[11]
  PIN Tile_X0Y4_FrameData_O[12]
    DIRECTION OUTPUT ;
    USE SIGNAL ;
    ANTENNADIFFAREA 0.708600 ;
    PORT
      LAYER Metal3 ;
        RECT 219.440 341.680 219.840 342.080 ;
    END
  END Tile_X0Y4_FrameData_O[12]
  PIN Tile_X0Y4_FrameData_O[13]
    DIRECTION OUTPUT ;
    USE SIGNAL ;
    ANTENNADIFFAREA 0.708600 ;
    PORT
      LAYER Metal3 ;
        RECT 219.440 342.520 219.840 342.920 ;
    END
  END Tile_X0Y4_FrameData_O[13]
  PIN Tile_X0Y4_FrameData_O[14]
    DIRECTION OUTPUT ;
    USE SIGNAL ;
    ANTENNADIFFAREA 0.708600 ;
    PORT
      LAYER Metal3 ;
        RECT 219.440 343.360 219.840 343.760 ;
    END
  END Tile_X0Y4_FrameData_O[14]
  PIN Tile_X0Y4_FrameData_O[15]
    DIRECTION OUTPUT ;
    USE SIGNAL ;
    ANTENNADIFFAREA 0.708600 ;
    PORT
      LAYER Metal3 ;
        RECT 219.440 344.200 219.840 344.600 ;
    END
  END Tile_X0Y4_FrameData_O[15]
  PIN Tile_X0Y4_FrameData_O[16]
    DIRECTION OUTPUT ;
    USE SIGNAL ;
    ANTENNADIFFAREA 0.708600 ;
    PORT
      LAYER Metal3 ;
        RECT 219.440 345.040 219.840 345.440 ;
    END
  END Tile_X0Y4_FrameData_O[16]
  PIN Tile_X0Y4_FrameData_O[17]
    DIRECTION OUTPUT ;
    USE SIGNAL ;
    ANTENNADIFFAREA 0.708600 ;
    PORT
      LAYER Metal3 ;
        RECT 219.440 345.880 219.840 346.280 ;
    END
  END Tile_X0Y4_FrameData_O[17]
  PIN Tile_X0Y4_FrameData_O[18]
    DIRECTION OUTPUT ;
    USE SIGNAL ;
    ANTENNADIFFAREA 0.708600 ;
    PORT
      LAYER Metal3 ;
        RECT 219.440 346.720 219.840 347.120 ;
    END
  END Tile_X0Y4_FrameData_O[18]
  PIN Tile_X0Y4_FrameData_O[19]
    DIRECTION OUTPUT ;
    USE SIGNAL ;
    ANTENNADIFFAREA 0.708600 ;
    PORT
      LAYER Metal3 ;
        RECT 219.440 347.560 219.840 347.960 ;
    END
  END Tile_X0Y4_FrameData_O[19]
  PIN Tile_X0Y4_FrameData_O[1]
    DIRECTION OUTPUT ;
    USE SIGNAL ;
    ANTENNADIFFAREA 0.708600 ;
    PORT
      LAYER Metal3 ;
        RECT 219.440 332.440 219.840 332.840 ;
    END
  END Tile_X0Y4_FrameData_O[1]
  PIN Tile_X0Y4_FrameData_O[20]
    DIRECTION OUTPUT ;
    USE SIGNAL ;
    ANTENNADIFFAREA 0.708600 ;
    PORT
      LAYER Metal3 ;
        RECT 219.440 348.400 219.840 348.800 ;
    END
  END Tile_X0Y4_FrameData_O[20]
  PIN Tile_X0Y4_FrameData_O[21]
    DIRECTION OUTPUT ;
    USE SIGNAL ;
    ANTENNADIFFAREA 0.708600 ;
    PORT
      LAYER Metal3 ;
        RECT 219.440 349.240 219.840 349.640 ;
    END
  END Tile_X0Y4_FrameData_O[21]
  PIN Tile_X0Y4_FrameData_O[22]
    DIRECTION OUTPUT ;
    USE SIGNAL ;
    ANTENNADIFFAREA 0.708600 ;
    PORT
      LAYER Metal3 ;
        RECT 219.440 350.080 219.840 350.480 ;
    END
  END Tile_X0Y4_FrameData_O[22]
  PIN Tile_X0Y4_FrameData_O[23]
    DIRECTION OUTPUT ;
    USE SIGNAL ;
    ANTENNADIFFAREA 0.708600 ;
    PORT
      LAYER Metal3 ;
        RECT 219.440 350.920 219.840 351.320 ;
    END
  END Tile_X0Y4_FrameData_O[23]
  PIN Tile_X0Y4_FrameData_O[24]
    DIRECTION OUTPUT ;
    USE SIGNAL ;
    ANTENNADIFFAREA 0.708600 ;
    PORT
      LAYER Metal3 ;
        RECT 219.440 351.760 219.840 352.160 ;
    END
  END Tile_X0Y4_FrameData_O[24]
  PIN Tile_X0Y4_FrameData_O[25]
    DIRECTION OUTPUT ;
    USE SIGNAL ;
    ANTENNADIFFAREA 0.708600 ;
    PORT
      LAYER Metal3 ;
        RECT 219.440 352.600 219.840 353.000 ;
    END
  END Tile_X0Y4_FrameData_O[25]
  PIN Tile_X0Y4_FrameData_O[26]
    DIRECTION OUTPUT ;
    USE SIGNAL ;
    ANTENNADIFFAREA 0.708600 ;
    PORT
      LAYER Metal3 ;
        RECT 219.440 353.440 219.840 353.840 ;
    END
  END Tile_X0Y4_FrameData_O[26]
  PIN Tile_X0Y4_FrameData_O[27]
    DIRECTION OUTPUT ;
    USE SIGNAL ;
    ANTENNADIFFAREA 0.708600 ;
    PORT
      LAYER Metal3 ;
        RECT 219.440 354.280 219.840 354.680 ;
    END
  END Tile_X0Y4_FrameData_O[27]
  PIN Tile_X0Y4_FrameData_O[28]
    DIRECTION OUTPUT ;
    USE SIGNAL ;
    ANTENNADIFFAREA 0.708600 ;
    PORT
      LAYER Metal3 ;
        RECT 219.440 355.120 219.840 355.520 ;
    END
  END Tile_X0Y4_FrameData_O[28]
  PIN Tile_X0Y4_FrameData_O[29]
    DIRECTION OUTPUT ;
    USE SIGNAL ;
    ANTENNADIFFAREA 0.708600 ;
    PORT
      LAYER Metal3 ;
        RECT 219.440 355.960 219.840 356.360 ;
    END
  END Tile_X0Y4_FrameData_O[29]
  PIN Tile_X0Y4_FrameData_O[2]
    DIRECTION OUTPUT ;
    USE SIGNAL ;
    ANTENNADIFFAREA 0.708600 ;
    PORT
      LAYER Metal3 ;
        RECT 219.440 333.280 219.840 333.680 ;
    END
  END Tile_X0Y4_FrameData_O[2]
  PIN Tile_X0Y4_FrameData_O[30]
    DIRECTION OUTPUT ;
    USE SIGNAL ;
    ANTENNADIFFAREA 0.708600 ;
    PORT
      LAYER Metal3 ;
        RECT 219.440 356.800 219.840 357.200 ;
    END
  END Tile_X0Y4_FrameData_O[30]
  PIN Tile_X0Y4_FrameData_O[31]
    DIRECTION OUTPUT ;
    USE SIGNAL ;
    ANTENNADIFFAREA 0.708600 ;
    PORT
      LAYER Metal3 ;
        RECT 219.440 357.640 219.840 358.040 ;
    END
  END Tile_X0Y4_FrameData_O[31]
  PIN Tile_X0Y4_FrameData_O[3]
    DIRECTION OUTPUT ;
    USE SIGNAL ;
    ANTENNADIFFAREA 0.708600 ;
    PORT
      LAYER Metal3 ;
        RECT 219.440 334.120 219.840 334.520 ;
    END
  END Tile_X0Y4_FrameData_O[3]
  PIN Tile_X0Y4_FrameData_O[4]
    DIRECTION OUTPUT ;
    USE SIGNAL ;
    ANTENNADIFFAREA 0.708600 ;
    PORT
      LAYER Metal3 ;
        RECT 219.440 334.960 219.840 335.360 ;
    END
  END Tile_X0Y4_FrameData_O[4]
  PIN Tile_X0Y4_FrameData_O[5]
    DIRECTION OUTPUT ;
    USE SIGNAL ;
    ANTENNADIFFAREA 0.708600 ;
    PORT
      LAYER Metal3 ;
        RECT 219.440 335.800 219.840 336.200 ;
    END
  END Tile_X0Y4_FrameData_O[5]
  PIN Tile_X0Y4_FrameData_O[6]
    DIRECTION OUTPUT ;
    USE SIGNAL ;
    ANTENNADIFFAREA 0.708600 ;
    PORT
      LAYER Metal3 ;
        RECT 219.440 336.640 219.840 337.040 ;
    END
  END Tile_X0Y4_FrameData_O[6]
  PIN Tile_X0Y4_FrameData_O[7]
    DIRECTION OUTPUT ;
    USE SIGNAL ;
    ANTENNADIFFAREA 0.708600 ;
    PORT
      LAYER Metal3 ;
        RECT 219.440 337.480 219.840 337.880 ;
    END
  END Tile_X0Y4_FrameData_O[7]
  PIN Tile_X0Y4_FrameData_O[8]
    DIRECTION OUTPUT ;
    USE SIGNAL ;
    ANTENNADIFFAREA 0.708600 ;
    PORT
      LAYER Metal3 ;
        RECT 219.440 338.320 219.840 338.720 ;
    END
  END Tile_X0Y4_FrameData_O[8]
  PIN Tile_X0Y4_FrameData_O[9]
    DIRECTION OUTPUT ;
    USE SIGNAL ;
    ANTENNADIFFAREA 0.708600 ;
    PORT
      LAYER Metal3 ;
        RECT 219.440 339.160 219.840 339.560 ;
    END
  END Tile_X0Y4_FrameData_O[9]
  PIN Tile_X0Y4_W1END[0]
    DIRECTION INPUT ;
    USE SIGNAL ;
    ANTENNAGATEAREA 1.279200 ;
    PORT
      LAYER Metal3 ;
        RECT 219.440 250.960 219.840 251.360 ;
    END
  END Tile_X0Y4_W1END[0]
  PIN Tile_X0Y4_W1END[1]
    DIRECTION INPUT ;
    USE SIGNAL ;
    ANTENNAGATEAREA 1.279200 ;
    PORT
      LAYER Metal3 ;
        RECT 219.440 251.800 219.840 252.200 ;
    END
  END Tile_X0Y4_W1END[1]
  PIN Tile_X0Y4_W1END[2]
    DIRECTION INPUT ;
    USE SIGNAL ;
    ANTENNAGATEAREA 1.279200 ;
    PORT
      LAYER Metal3 ;
        RECT 219.440 252.640 219.840 253.040 ;
    END
  END Tile_X0Y4_W1END[2]
  PIN Tile_X0Y4_W1END[3]
    DIRECTION INPUT ;
    USE SIGNAL ;
    ANTENNAGATEAREA 1.279200 ;
    PORT
      LAYER Metal3 ;
        RECT 219.440 253.480 219.840 253.880 ;
    END
  END Tile_X0Y4_W1END[3]
  PIN Tile_X0Y4_W2END[0]
    DIRECTION INPUT ;
    USE SIGNAL ;
    ANTENNAGATEAREA 0.852800 ;
    PORT
      LAYER Metal3 ;
        RECT 219.440 261.040 219.840 261.440 ;
    END
  END Tile_X0Y4_W2END[0]
  PIN Tile_X0Y4_W2END[1]
    DIRECTION INPUT ;
    USE SIGNAL ;
    ANTENNAGATEAREA 0.852800 ;
    PORT
      LAYER Metal3 ;
        RECT 219.440 261.880 219.840 262.280 ;
    END
  END Tile_X0Y4_W2END[1]
  PIN Tile_X0Y4_W2END[2]
    DIRECTION INPUT ;
    USE SIGNAL ;
    ANTENNAGATEAREA 0.852800 ;
    PORT
      LAYER Metal3 ;
        RECT 219.440 262.720 219.840 263.120 ;
    END
  END Tile_X0Y4_W2END[2]
  PIN Tile_X0Y4_W2END[3]
    DIRECTION INPUT ;
    USE SIGNAL ;
    ANTENNAGATEAREA 0.852800 ;
    PORT
      LAYER Metal3 ;
        RECT 219.440 263.560 219.840 263.960 ;
    END
  END Tile_X0Y4_W2END[3]
  PIN Tile_X0Y4_W2END[4]
    DIRECTION INPUT ;
    USE SIGNAL ;
    ANTENNAGATEAREA 0.852800 ;
    PORT
      LAYER Metal3 ;
        RECT 219.440 264.400 219.840 264.800 ;
    END
  END Tile_X0Y4_W2END[4]
  PIN Tile_X0Y4_W2END[5]
    DIRECTION INPUT ;
    USE SIGNAL ;
    ANTENNAGATEAREA 0.852800 ;
    PORT
      LAYER Metal3 ;
        RECT 219.440 265.240 219.840 265.640 ;
    END
  END Tile_X0Y4_W2END[5]
  PIN Tile_X0Y4_W2END[6]
    DIRECTION INPUT ;
    USE SIGNAL ;
    ANTENNAGATEAREA 0.852800 ;
    PORT
      LAYER Metal3 ;
        RECT 219.440 266.080 219.840 266.480 ;
    END
  END Tile_X0Y4_W2END[6]
  PIN Tile_X0Y4_W2END[7]
    DIRECTION INPUT ;
    USE SIGNAL ;
    ANTENNAGATEAREA 0.852800 ;
    PORT
      LAYER Metal3 ;
        RECT 219.440 266.920 219.840 267.320 ;
    END
  END Tile_X0Y4_W2END[7]
  PIN Tile_X0Y4_W2MID[0]
    DIRECTION INPUT ;
    USE SIGNAL ;
    ANTENNAGATEAREA 0.852800 ;
    PORT
      LAYER Metal3 ;
        RECT 219.440 254.320 219.840 254.720 ;
    END
  END Tile_X0Y4_W2MID[0]
  PIN Tile_X0Y4_W2MID[1]
    DIRECTION INPUT ;
    USE SIGNAL ;
    ANTENNAGATEAREA 0.852800 ;
    PORT
      LAYER Metal3 ;
        RECT 219.440 255.160 219.840 255.560 ;
    END
  END Tile_X0Y4_W2MID[1]
  PIN Tile_X0Y4_W2MID[2]
    DIRECTION INPUT ;
    USE SIGNAL ;
    ANTENNAGATEAREA 0.852800 ;
    PORT
      LAYER Metal3 ;
        RECT 219.440 256.000 219.840 256.400 ;
    END
  END Tile_X0Y4_W2MID[2]
  PIN Tile_X0Y4_W2MID[3]
    DIRECTION INPUT ;
    USE SIGNAL ;
    ANTENNAGATEAREA 0.852800 ;
    PORT
      LAYER Metal3 ;
        RECT 219.440 256.840 219.840 257.240 ;
    END
  END Tile_X0Y4_W2MID[3]
  PIN Tile_X0Y4_W2MID[4]
    DIRECTION INPUT ;
    USE SIGNAL ;
    ANTENNAGATEAREA 0.852800 ;
    PORT
      LAYER Metal3 ;
        RECT 219.440 257.680 219.840 258.080 ;
    END
  END Tile_X0Y4_W2MID[4]
  PIN Tile_X0Y4_W2MID[5]
    DIRECTION INPUT ;
    USE SIGNAL ;
    ANTENNAGATEAREA 0.852800 ;
    PORT
      LAYER Metal3 ;
        RECT 219.440 258.520 219.840 258.920 ;
    END
  END Tile_X0Y4_W2MID[5]
  PIN Tile_X0Y4_W2MID[6]
    DIRECTION INPUT ;
    USE SIGNAL ;
    ANTENNAGATEAREA 0.852800 ;
    PORT
      LAYER Metal3 ;
        RECT 219.440 259.360 219.840 259.760 ;
    END
  END Tile_X0Y4_W2MID[6]
  PIN Tile_X0Y4_W2MID[7]
    DIRECTION INPUT ;
    USE SIGNAL ;
    ANTENNAGATEAREA 0.852800 ;
    PORT
      LAYER Metal3 ;
        RECT 219.440 260.200 219.840 260.600 ;
    END
  END Tile_X0Y4_W2MID[7]
  PIN Tile_X0Y4_W6END[0]
    DIRECTION INPUT ;
    USE SIGNAL ;
    ANTENNAGATEAREA 0.881400 ;
    PORT
      LAYER Metal3 ;
        RECT 219.440 281.200 219.840 281.600 ;
    END
  END Tile_X0Y4_W6END[0]
  PIN Tile_X0Y4_W6END[10]
    DIRECTION INPUT ;
    USE SIGNAL ;
    ANTENNAGATEAREA 0.852800 ;
    PORT
      LAYER Metal3 ;
        RECT 219.440 289.600 219.840 290.000 ;
    END
  END Tile_X0Y4_W6END[10]
  PIN Tile_X0Y4_W6END[11]
    DIRECTION INPUT ;
    USE SIGNAL ;
    ANTENNAGATEAREA 0.852800 ;
    PORT
      LAYER Metal3 ;
        RECT 219.440 290.440 219.840 290.840 ;
    END
  END Tile_X0Y4_W6END[11]
  PIN Tile_X0Y4_W6END[1]
    DIRECTION INPUT ;
    USE SIGNAL ;
    ANTENNAGATEAREA 0.881400 ;
    PORT
      LAYER Metal3 ;
        RECT 219.440 282.040 219.840 282.440 ;
    END
  END Tile_X0Y4_W6END[1]
  PIN Tile_X0Y4_W6END[2]
    DIRECTION INPUT ;
    USE SIGNAL ;
    ANTENNAGATEAREA 0.881400 ;
    PORT
      LAYER Metal3 ;
        RECT 219.440 282.880 219.840 283.280 ;
    END
  END Tile_X0Y4_W6END[2]
  PIN Tile_X0Y4_W6END[3]
    DIRECTION INPUT ;
    USE SIGNAL ;
    ANTENNAGATEAREA 0.881400 ;
    PORT
      LAYER Metal3 ;
        RECT 219.440 283.720 219.840 284.120 ;
    END
  END Tile_X0Y4_W6END[3]
  PIN Tile_X0Y4_W6END[4]
    DIRECTION INPUT ;
    USE SIGNAL ;
    ANTENNAGATEAREA 1.066000 ;
    PORT
      LAYER Metal3 ;
        RECT 219.440 284.560 219.840 284.960 ;
    END
  END Tile_X0Y4_W6END[4]
  PIN Tile_X0Y4_W6END[5]
    DIRECTION INPUT ;
    USE SIGNAL ;
    ANTENNAGATEAREA 1.066000 ;
    PORT
      LAYER Metal3 ;
        RECT 219.440 285.400 219.840 285.800 ;
    END
  END Tile_X0Y4_W6END[5]
  PIN Tile_X0Y4_W6END[6]
    DIRECTION INPUT ;
    USE SIGNAL ;
    ANTENNAGATEAREA 1.066000 ;
    PORT
      LAYER Metal3 ;
        RECT 219.440 286.240 219.840 286.640 ;
    END
  END Tile_X0Y4_W6END[6]
  PIN Tile_X0Y4_W6END[7]
    DIRECTION INPUT ;
    USE SIGNAL ;
    ANTENNAGATEAREA 1.066000 ;
    PORT
      LAYER Metal3 ;
        RECT 219.440 287.080 219.840 287.480 ;
    END
  END Tile_X0Y4_W6END[7]
  PIN Tile_X0Y4_W6END[8]
    DIRECTION INPUT ;
    USE SIGNAL ;
    ANTENNAGATEAREA 0.852800 ;
    PORT
      LAYER Metal3 ;
        RECT 219.440 287.920 219.840 288.320 ;
    END
  END Tile_X0Y4_W6END[8]
  PIN Tile_X0Y4_W6END[9]
    DIRECTION INPUT ;
    USE SIGNAL ;
    ANTENNAGATEAREA 0.852800 ;
    PORT
      LAYER Metal3 ;
        RECT 219.440 288.760 219.840 289.160 ;
    END
  END Tile_X0Y4_W6END[9]
  PIN Tile_X0Y4_WW4END[0]
    DIRECTION INPUT ;
    USE SIGNAL ;
    ANTENNAGATEAREA 0.852800 ;
    PORT
      LAYER Metal3 ;
        RECT 219.440 267.760 219.840 268.160 ;
    END
  END Tile_X0Y4_WW4END[0]
  PIN Tile_X0Y4_WW4END[10]
    DIRECTION INPUT ;
    USE SIGNAL ;
    ANTENNAGATEAREA 0.639600 ;
    PORT
      LAYER Metal3 ;
        RECT 219.440 276.160 219.840 276.560 ;
    END
  END Tile_X0Y4_WW4END[10]
  PIN Tile_X0Y4_WW4END[11]
    DIRECTION INPUT ;
    USE SIGNAL ;
    ANTENNAGATEAREA 0.639600 ;
    PORT
      LAYER Metal3 ;
        RECT 219.440 277.000 219.840 277.400 ;
    END
  END Tile_X0Y4_WW4END[11]
  PIN Tile_X0Y4_WW4END[12]
    DIRECTION INPUT ;
    USE SIGNAL ;
    ANTENNAGATEAREA 0.852800 ;
    PORT
      LAYER Metal3 ;
        RECT 219.440 277.840 219.840 278.240 ;
    END
  END Tile_X0Y4_WW4END[12]
  PIN Tile_X0Y4_WW4END[13]
    DIRECTION INPUT ;
    USE SIGNAL ;
    ANTENNAGATEAREA 0.852800 ;
    PORT
      LAYER Metal3 ;
        RECT 219.440 278.680 219.840 279.080 ;
    END
  END Tile_X0Y4_WW4END[13]
  PIN Tile_X0Y4_WW4END[14]
    DIRECTION INPUT ;
    USE SIGNAL ;
    ANTENNAGATEAREA 0.852800 ;
    PORT
      LAYER Metal3 ;
        RECT 219.440 279.520 219.840 279.920 ;
    END
  END Tile_X0Y4_WW4END[14]
  PIN Tile_X0Y4_WW4END[15]
    DIRECTION INPUT ;
    USE SIGNAL ;
    ANTENNAGATEAREA 0.852800 ;
    PORT
      LAYER Metal3 ;
        RECT 219.440 280.360 219.840 280.760 ;
    END
  END Tile_X0Y4_WW4END[15]
  PIN Tile_X0Y4_WW4END[1]
    DIRECTION INPUT ;
    USE SIGNAL ;
    ANTENNAGATEAREA 0.852800 ;
    PORT
      LAYER Metal3 ;
        RECT 219.440 268.600 219.840 269.000 ;
    END
  END Tile_X0Y4_WW4END[1]
  PIN Tile_X0Y4_WW4END[2]
    DIRECTION INPUT ;
    USE SIGNAL ;
    ANTENNAGATEAREA 0.852800 ;
    PORT
      LAYER Metal3 ;
        RECT 219.440 269.440 219.840 269.840 ;
    END
  END Tile_X0Y4_WW4END[2]
  PIN Tile_X0Y4_WW4END[3]
    DIRECTION INPUT ;
    USE SIGNAL ;
    ANTENNAGATEAREA 0.852800 ;
    PORT
      LAYER Metal3 ;
        RECT 219.440 270.280 219.840 270.680 ;
    END
  END Tile_X0Y4_WW4END[3]
  PIN Tile_X0Y4_WW4END[4]
    DIRECTION INPUT ;
    USE SIGNAL ;
    ANTENNAGATEAREA 0.639600 ;
    PORT
      LAYER Metal3 ;
        RECT 219.440 271.120 219.840 271.520 ;
    END
  END Tile_X0Y4_WW4END[4]
  PIN Tile_X0Y4_WW4END[5]
    DIRECTION INPUT ;
    USE SIGNAL ;
    ANTENNAGATEAREA 0.639600 ;
    PORT
      LAYER Metal3 ;
        RECT 219.440 271.960 219.840 272.360 ;
    END
  END Tile_X0Y4_WW4END[5]
  PIN Tile_X0Y4_WW4END[6]
    DIRECTION INPUT ;
    USE SIGNAL ;
    ANTENNAGATEAREA 0.639600 ;
    PORT
      LAYER Metal3 ;
        RECT 219.440 272.800 219.840 273.200 ;
    END
  END Tile_X0Y4_WW4END[6]
  PIN Tile_X0Y4_WW4END[7]
    DIRECTION INPUT ;
    USE SIGNAL ;
    ANTENNAGATEAREA 0.639600 ;
    PORT
      LAYER Metal3 ;
        RECT 219.440 273.640 219.840 274.040 ;
    END
  END Tile_X0Y4_WW4END[7]
  PIN Tile_X0Y4_WW4END[8]
    DIRECTION INPUT ;
    USE SIGNAL ;
    ANTENNAGATEAREA 0.639600 ;
    PORT
      LAYER Metal3 ;
        RECT 219.440 274.480 219.840 274.880 ;
    END
  END Tile_X0Y4_WW4END[8]
  PIN Tile_X0Y4_WW4END[9]
    DIRECTION INPUT ;
    USE SIGNAL ;
    ANTENNAGATEAREA 0.639600 ;
    PORT
      LAYER Metal3 ;
        RECT 219.440 275.320 219.840 275.720 ;
    END
  END Tile_X0Y4_WW4END[9]
  PIN Tile_X0Y5_E1BEG[0]
    DIRECTION OUTPUT ;
    USE SIGNAL ;
    ANTENNADIFFAREA 0.708600 ;
    PORT
      LAYER Metal3 ;
        RECT 219.440 88.420 219.840 88.820 ;
    END
  END Tile_X0Y5_E1BEG[0]
  PIN Tile_X0Y5_E1BEG[1]
    DIRECTION OUTPUT ;
    USE SIGNAL ;
    ANTENNADIFFAREA 0.708600 ;
    PORT
      LAYER Metal3 ;
        RECT 219.440 89.260 219.840 89.660 ;
    END
  END Tile_X0Y5_E1BEG[1]
  PIN Tile_X0Y5_E1BEG[2]
    DIRECTION OUTPUT ;
    USE SIGNAL ;
    ANTENNADIFFAREA 0.708600 ;
    PORT
      LAYER Metal3 ;
        RECT 219.440 90.100 219.840 90.500 ;
    END
  END Tile_X0Y5_E1BEG[2]
  PIN Tile_X0Y5_E1BEG[3]
    DIRECTION OUTPUT ;
    USE SIGNAL ;
    ANTENNADIFFAREA 0.708600 ;
    PORT
      LAYER Metal3 ;
        RECT 219.440 90.940 219.840 91.340 ;
    END
  END Tile_X0Y5_E1BEG[3]
  PIN Tile_X0Y5_E2BEG[0]
    DIRECTION OUTPUT ;
    USE SIGNAL ;
    ANTENNADIFFAREA 0.708600 ;
    PORT
      LAYER Metal3 ;
        RECT 219.440 91.780 219.840 92.180 ;
    END
  END Tile_X0Y5_E2BEG[0]
  PIN Tile_X0Y5_E2BEG[1]
    DIRECTION OUTPUT ;
    USE SIGNAL ;
    ANTENNADIFFAREA 0.708600 ;
    PORT
      LAYER Metal3 ;
        RECT 219.440 92.620 219.840 93.020 ;
    END
  END Tile_X0Y5_E2BEG[1]
  PIN Tile_X0Y5_E2BEG[2]
    DIRECTION OUTPUT ;
    USE SIGNAL ;
    ANTENNADIFFAREA 0.708600 ;
    PORT
      LAYER Metal3 ;
        RECT 219.440 93.460 219.840 93.860 ;
    END
  END Tile_X0Y5_E2BEG[2]
  PIN Tile_X0Y5_E2BEG[3]
    DIRECTION OUTPUT ;
    USE SIGNAL ;
    ANTENNADIFFAREA 0.708600 ;
    PORT
      LAYER Metal3 ;
        RECT 219.440 94.300 219.840 94.700 ;
    END
  END Tile_X0Y5_E2BEG[3]
  PIN Tile_X0Y5_E2BEG[4]
    DIRECTION OUTPUT ;
    USE SIGNAL ;
    ANTENNADIFFAREA 0.708600 ;
    PORT
      LAYER Metal3 ;
        RECT 219.440 95.140 219.840 95.540 ;
    END
  END Tile_X0Y5_E2BEG[4]
  PIN Tile_X0Y5_E2BEG[5]
    DIRECTION OUTPUT ;
    USE SIGNAL ;
    ANTENNADIFFAREA 0.708600 ;
    PORT
      LAYER Metal3 ;
        RECT 219.440 95.980 219.840 96.380 ;
    END
  END Tile_X0Y5_E2BEG[5]
  PIN Tile_X0Y5_E2BEG[6]
    DIRECTION OUTPUT ;
    USE SIGNAL ;
    ANTENNADIFFAREA 0.708600 ;
    PORT
      LAYER Metal3 ;
        RECT 219.440 96.820 219.840 97.220 ;
    END
  END Tile_X0Y5_E2BEG[6]
  PIN Tile_X0Y5_E2BEG[7]
    DIRECTION OUTPUT ;
    USE SIGNAL ;
    ANTENNADIFFAREA 0.708600 ;
    PORT
      LAYER Metal3 ;
        RECT 219.440 97.660 219.840 98.060 ;
    END
  END Tile_X0Y5_E2BEG[7]
  PIN Tile_X0Y5_E2BEGb[0]
    DIRECTION OUTPUT ;
    USE SIGNAL ;
    ANTENNADIFFAREA 0.708600 ;
    PORT
      LAYER Metal3 ;
        RECT 219.440 98.500 219.840 98.900 ;
    END
  END Tile_X0Y5_E2BEGb[0]
  PIN Tile_X0Y5_E2BEGb[1]
    DIRECTION OUTPUT ;
    USE SIGNAL ;
    ANTENNADIFFAREA 0.708600 ;
    PORT
      LAYER Metal3 ;
        RECT 219.440 99.340 219.840 99.740 ;
    END
  END Tile_X0Y5_E2BEGb[1]
  PIN Tile_X0Y5_E2BEGb[2]
    DIRECTION OUTPUT ;
    USE SIGNAL ;
    ANTENNADIFFAREA 0.708600 ;
    PORT
      LAYER Metal3 ;
        RECT 219.440 100.180 219.840 100.580 ;
    END
  END Tile_X0Y5_E2BEGb[2]
  PIN Tile_X0Y5_E2BEGb[3]
    DIRECTION OUTPUT ;
    USE SIGNAL ;
    ANTENNADIFFAREA 0.708600 ;
    PORT
      LAYER Metal3 ;
        RECT 219.440 101.020 219.840 101.420 ;
    END
  END Tile_X0Y5_E2BEGb[3]
  PIN Tile_X0Y5_E2BEGb[4]
    DIRECTION OUTPUT ;
    USE SIGNAL ;
    ANTENNADIFFAREA 0.708600 ;
    PORT
      LAYER Metal3 ;
        RECT 219.440 101.860 219.840 102.260 ;
    END
  END Tile_X0Y5_E2BEGb[4]
  PIN Tile_X0Y5_E2BEGb[5]
    DIRECTION OUTPUT ;
    USE SIGNAL ;
    ANTENNADIFFAREA 0.708600 ;
    PORT
      LAYER Metal3 ;
        RECT 219.440 102.700 219.840 103.100 ;
    END
  END Tile_X0Y5_E2BEGb[5]
  PIN Tile_X0Y5_E2BEGb[6]
    DIRECTION OUTPUT ;
    USE SIGNAL ;
    ANTENNADIFFAREA 0.708600 ;
    PORT
      LAYER Metal3 ;
        RECT 219.440 103.540 219.840 103.940 ;
    END
  END Tile_X0Y5_E2BEGb[6]
  PIN Tile_X0Y5_E2BEGb[7]
    DIRECTION OUTPUT ;
    USE SIGNAL ;
    ANTENNADIFFAREA 0.708600 ;
    PORT
      LAYER Metal3 ;
        RECT 219.440 104.380 219.840 104.780 ;
    END
  END Tile_X0Y5_E2BEGb[7]
  PIN Tile_X0Y5_E6BEG[0]
    DIRECTION OUTPUT ;
    USE SIGNAL ;
    ANTENNADIFFAREA 0.708600 ;
    PORT
      LAYER Metal3 ;
        RECT 219.440 118.660 219.840 119.060 ;
    END
  END Tile_X0Y5_E6BEG[0]
  PIN Tile_X0Y5_E6BEG[10]
    DIRECTION OUTPUT ;
    USE SIGNAL ;
    ANTENNADIFFAREA 0.708600 ;
    PORT
      LAYER Metal3 ;
        RECT 219.440 127.060 219.840 127.460 ;
    END
  END Tile_X0Y5_E6BEG[10]
  PIN Tile_X0Y5_E6BEG[11]
    DIRECTION OUTPUT ;
    USE SIGNAL ;
    ANTENNADIFFAREA 0.708600 ;
    PORT
      LAYER Metal3 ;
        RECT 219.440 127.900 219.840 128.300 ;
    END
  END Tile_X0Y5_E6BEG[11]
  PIN Tile_X0Y5_E6BEG[1]
    DIRECTION OUTPUT ;
    USE SIGNAL ;
    ANTENNADIFFAREA 0.708600 ;
    PORT
      LAYER Metal3 ;
        RECT 219.440 119.500 219.840 119.900 ;
    END
  END Tile_X0Y5_E6BEG[1]
  PIN Tile_X0Y5_E6BEG[2]
    DIRECTION OUTPUT ;
    USE SIGNAL ;
    ANTENNADIFFAREA 0.708600 ;
    PORT
      LAYER Metal3 ;
        RECT 219.440 120.340 219.840 120.740 ;
    END
  END Tile_X0Y5_E6BEG[2]
  PIN Tile_X0Y5_E6BEG[3]
    DIRECTION OUTPUT ;
    USE SIGNAL ;
    ANTENNADIFFAREA 0.708600 ;
    PORT
      LAYER Metal3 ;
        RECT 219.440 121.180 219.840 121.580 ;
    END
  END Tile_X0Y5_E6BEG[3]
  PIN Tile_X0Y5_E6BEG[4]
    DIRECTION OUTPUT ;
    USE SIGNAL ;
    ANTENNADIFFAREA 0.708600 ;
    PORT
      LAYER Metal3 ;
        RECT 219.440 122.020 219.840 122.420 ;
    END
  END Tile_X0Y5_E6BEG[4]
  PIN Tile_X0Y5_E6BEG[5]
    DIRECTION OUTPUT ;
    USE SIGNAL ;
    ANTENNADIFFAREA 0.708600 ;
    PORT
      LAYER Metal3 ;
        RECT 219.440 122.860 219.840 123.260 ;
    END
  END Tile_X0Y5_E6BEG[5]
  PIN Tile_X0Y5_E6BEG[6]
    DIRECTION OUTPUT ;
    USE SIGNAL ;
    ANTENNADIFFAREA 0.708600 ;
    PORT
      LAYER Metal3 ;
        RECT 219.440 123.700 219.840 124.100 ;
    END
  END Tile_X0Y5_E6BEG[6]
  PIN Tile_X0Y5_E6BEG[7]
    DIRECTION OUTPUT ;
    USE SIGNAL ;
    ANTENNADIFFAREA 0.708600 ;
    PORT
      LAYER Metal3 ;
        RECT 219.440 124.540 219.840 124.940 ;
    END
  END Tile_X0Y5_E6BEG[7]
  PIN Tile_X0Y5_E6BEG[8]
    DIRECTION OUTPUT ;
    USE SIGNAL ;
    ANTENNADIFFAREA 0.708600 ;
    PORT
      LAYER Metal3 ;
        RECT 219.440 125.380 219.840 125.780 ;
    END
  END Tile_X0Y5_E6BEG[8]
  PIN Tile_X0Y5_E6BEG[9]
    DIRECTION OUTPUT ;
    USE SIGNAL ;
    ANTENNADIFFAREA 0.708600 ;
    PORT
      LAYER Metal3 ;
        RECT 219.440 126.220 219.840 126.620 ;
    END
  END Tile_X0Y5_E6BEG[9]
  PIN Tile_X0Y5_EE4BEG[0]
    DIRECTION OUTPUT ;
    USE SIGNAL ;
    ANTENNADIFFAREA 0.708600 ;
    PORT
      LAYER Metal3 ;
        RECT 219.440 105.220 219.840 105.620 ;
    END
  END Tile_X0Y5_EE4BEG[0]
  PIN Tile_X0Y5_EE4BEG[10]
    DIRECTION OUTPUT ;
    USE SIGNAL ;
    ANTENNADIFFAREA 0.708600 ;
    PORT
      LAYER Metal3 ;
        RECT 219.440 113.620 219.840 114.020 ;
    END
  END Tile_X0Y5_EE4BEG[10]
  PIN Tile_X0Y5_EE4BEG[11]
    DIRECTION OUTPUT ;
    USE SIGNAL ;
    ANTENNADIFFAREA 0.708600 ;
    PORT
      LAYER Metal3 ;
        RECT 219.440 114.460 219.840 114.860 ;
    END
  END Tile_X0Y5_EE4BEG[11]
  PIN Tile_X0Y5_EE4BEG[12]
    DIRECTION OUTPUT ;
    USE SIGNAL ;
    ANTENNADIFFAREA 0.708600 ;
    PORT
      LAYER Metal3 ;
        RECT 219.440 115.300 219.840 115.700 ;
    END
  END Tile_X0Y5_EE4BEG[12]
  PIN Tile_X0Y5_EE4BEG[13]
    DIRECTION OUTPUT ;
    USE SIGNAL ;
    ANTENNADIFFAREA 0.708600 ;
    PORT
      LAYER Metal3 ;
        RECT 219.440 116.140 219.840 116.540 ;
    END
  END Tile_X0Y5_EE4BEG[13]
  PIN Tile_X0Y5_EE4BEG[14]
    DIRECTION OUTPUT ;
    USE SIGNAL ;
    ANTENNADIFFAREA 0.708600 ;
    PORT
      LAYER Metal3 ;
        RECT 219.440 116.980 219.840 117.380 ;
    END
  END Tile_X0Y5_EE4BEG[14]
  PIN Tile_X0Y5_EE4BEG[15]
    DIRECTION OUTPUT ;
    USE SIGNAL ;
    ANTENNADIFFAREA 0.708600 ;
    PORT
      LAYER Metal3 ;
        RECT 219.440 117.820 219.840 118.220 ;
    END
  END Tile_X0Y5_EE4BEG[15]
  PIN Tile_X0Y5_EE4BEG[1]
    DIRECTION OUTPUT ;
    USE SIGNAL ;
    ANTENNADIFFAREA 0.708600 ;
    PORT
      LAYER Metal3 ;
        RECT 219.440 106.060 219.840 106.460 ;
    END
  END Tile_X0Y5_EE4BEG[1]
  PIN Tile_X0Y5_EE4BEG[2]
    DIRECTION OUTPUT ;
    USE SIGNAL ;
    ANTENNADIFFAREA 0.708600 ;
    PORT
      LAYER Metal3 ;
        RECT 219.440 106.900 219.840 107.300 ;
    END
  END Tile_X0Y5_EE4BEG[2]
  PIN Tile_X0Y5_EE4BEG[3]
    DIRECTION OUTPUT ;
    USE SIGNAL ;
    ANTENNADIFFAREA 0.708600 ;
    PORT
      LAYER Metal3 ;
        RECT 219.440 107.740 219.840 108.140 ;
    END
  END Tile_X0Y5_EE4BEG[3]
  PIN Tile_X0Y5_EE4BEG[4]
    DIRECTION OUTPUT ;
    USE SIGNAL ;
    ANTENNADIFFAREA 0.708600 ;
    PORT
      LAYER Metal3 ;
        RECT 219.440 108.580 219.840 108.980 ;
    END
  END Tile_X0Y5_EE4BEG[4]
  PIN Tile_X0Y5_EE4BEG[5]
    DIRECTION OUTPUT ;
    USE SIGNAL ;
    ANTENNADIFFAREA 0.708600 ;
    PORT
      LAYER Metal3 ;
        RECT 219.440 109.420 219.840 109.820 ;
    END
  END Tile_X0Y5_EE4BEG[5]
  PIN Tile_X0Y5_EE4BEG[6]
    DIRECTION OUTPUT ;
    USE SIGNAL ;
    ANTENNADIFFAREA 0.708600 ;
    PORT
      LAYER Metal3 ;
        RECT 219.440 110.260 219.840 110.660 ;
    END
  END Tile_X0Y5_EE4BEG[6]
  PIN Tile_X0Y5_EE4BEG[7]
    DIRECTION OUTPUT ;
    USE SIGNAL ;
    ANTENNADIFFAREA 0.708600 ;
    PORT
      LAYER Metal3 ;
        RECT 219.440 111.100 219.840 111.500 ;
    END
  END Tile_X0Y5_EE4BEG[7]
  PIN Tile_X0Y5_EE4BEG[8]
    DIRECTION OUTPUT ;
    USE SIGNAL ;
    ANTENNADIFFAREA 0.708600 ;
    PORT
      LAYER Metal3 ;
        RECT 219.440 111.940 219.840 112.340 ;
    END
  END Tile_X0Y5_EE4BEG[8]
  PIN Tile_X0Y5_EE4BEG[9]
    DIRECTION OUTPUT ;
    USE SIGNAL ;
    ANTENNADIFFAREA 0.708600 ;
    PORT
      LAYER Metal3 ;
        RECT 219.440 112.780 219.840 113.180 ;
    END
  END Tile_X0Y5_EE4BEG[9]
  PIN Tile_X0Y5_FrameData[0]
    DIRECTION INPUT ;
    USE SIGNAL ;
    ANTENNAGATEAREA 1.807000 ;
    PORT
      LAYER Metal3 ;
        RECT 0.000 182.500 0.400 182.900 ;
    END
  END Tile_X0Y5_FrameData[0]
  PIN Tile_X0Y5_FrameData[10]
    DIRECTION INPUT ;
    USE SIGNAL ;
    ANTENNAGATEAREA 1.807000 ;
    PORT
      LAYER Metal3 ;
        RECT 0.000 232.900 0.400 233.300 ;
    END
  END Tile_X0Y5_FrameData[10]
  PIN Tile_X0Y5_FrameData[11]
    DIRECTION INPUT ;
    USE SIGNAL ;
    ANTENNAGATEAREA 1.807000 ;
    PORT
      LAYER Metal3 ;
        RECT 0.000 237.940 0.400 238.340 ;
    END
  END Tile_X0Y5_FrameData[11]
  PIN Tile_X0Y5_FrameData[12]
    DIRECTION INPUT ;
    USE SIGNAL ;
    ANTENNAGATEAREA 1.807000 ;
    ANTENNADIFFAREA 20.153999 ;
    PORT
      LAYER Metal3 ;
        RECT 0.000 242.980 0.400 243.380 ;
    END
  END Tile_X0Y5_FrameData[12]
  PIN Tile_X0Y5_FrameData[13]
    DIRECTION INPUT ;
    USE SIGNAL ;
    ANTENNAGATEAREA 1.807000 ;
    PORT
      LAYER Metal3 ;
        RECT 0.000 248.020 0.400 248.420 ;
    END
  END Tile_X0Y5_FrameData[13]
  PIN Tile_X0Y5_FrameData[14]
    DIRECTION INPUT ;
    USE SIGNAL ;
    ANTENNAGATEAREA 1.807000 ;
    PORT
      LAYER Metal3 ;
        RECT 0.000 253.060 0.400 253.460 ;
    END
  END Tile_X0Y5_FrameData[14]
  PIN Tile_X0Y5_FrameData[15]
    DIRECTION INPUT ;
    USE SIGNAL ;
    ANTENNAGATEAREA 1.807000 ;
    PORT
      LAYER Metal3 ;
        RECT 0.000 258.100 0.400 258.500 ;
    END
  END Tile_X0Y5_FrameData[15]
  PIN Tile_X0Y5_FrameData[16]
    DIRECTION INPUT ;
    USE SIGNAL ;
    ANTENNAGATEAREA 1.807000 ;
    PORT
      LAYER Metal3 ;
        RECT 0.000 263.140 0.400 263.540 ;
    END
  END Tile_X0Y5_FrameData[16]
  PIN Tile_X0Y5_FrameData[17]
    DIRECTION INPUT ;
    USE SIGNAL ;
    ANTENNAGATEAREA 1.807000 ;
    PORT
      LAYER Metal3 ;
        RECT 0.000 268.180 0.400 268.580 ;
    END
  END Tile_X0Y5_FrameData[17]
  PIN Tile_X0Y5_FrameData[18]
    DIRECTION INPUT ;
    USE SIGNAL ;
    ANTENNAGATEAREA 1.807000 ;
    ANTENNADIFFAREA 32.246399 ;
    PORT
      LAYER Metal3 ;
        RECT 0.000 273.220 0.400 273.620 ;
    END
  END Tile_X0Y5_FrameData[18]
  PIN Tile_X0Y5_FrameData[19]
    DIRECTION INPUT ;
    USE SIGNAL ;
    ANTENNAGATEAREA 1.807000 ;
    PORT
      LAYER Metal3 ;
        RECT 0.000 278.260 0.400 278.660 ;
    END
  END Tile_X0Y5_FrameData[19]
  PIN Tile_X0Y5_FrameData[1]
    DIRECTION INPUT ;
    USE SIGNAL ;
    ANTENNAGATEAREA 1.807000 ;
    PORT
      LAYER Metal3 ;
        RECT 0.000 187.540 0.400 187.940 ;
    END
  END Tile_X0Y5_FrameData[1]
  PIN Tile_X0Y5_FrameData[20]
    DIRECTION INPUT ;
    USE SIGNAL ;
    ANTENNAGATEAREA 1.807000 ;
    PORT
      LAYER Metal3 ;
        RECT 0.000 283.300 0.400 283.700 ;
    END
  END Tile_X0Y5_FrameData[20]
  PIN Tile_X0Y5_FrameData[21]
    DIRECTION INPUT ;
    USE SIGNAL ;
    ANTENNAGATEAREA 1.807000 ;
    ANTENNADIFFAREA 20.153999 ;
    PORT
      LAYER Metal3 ;
        RECT 0.000 288.340 0.400 288.740 ;
    END
  END Tile_X0Y5_FrameData[21]
  PIN Tile_X0Y5_FrameData[22]
    DIRECTION INPUT ;
    USE SIGNAL ;
    ANTENNAGATEAREA 1.807000 ;
    ANTENNADIFFAREA 20.153999 ;
    PORT
      LAYER Metal3 ;
        RECT 0.000 293.380 0.400 293.780 ;
    END
  END Tile_X0Y5_FrameData[22]
  PIN Tile_X0Y5_FrameData[23]
    DIRECTION INPUT ;
    USE SIGNAL ;
    ANTENNAGATEAREA 1.807000 ;
    PORT
      LAYER Metal3 ;
        RECT 0.000 298.420 0.400 298.820 ;
    END
  END Tile_X0Y5_FrameData[23]
  PIN Tile_X0Y5_FrameData[24]
    DIRECTION INPUT ;
    USE SIGNAL ;
    ANTENNAGATEAREA 1.807000 ;
    PORT
      LAYER Metal3 ;
        RECT 0.000 303.460 0.400 303.860 ;
    END
  END Tile_X0Y5_FrameData[24]
  PIN Tile_X0Y5_FrameData[25]
    DIRECTION INPUT ;
    USE SIGNAL ;
    ANTENNAGATEAREA 1.807000 ;
    PORT
      LAYER Metal3 ;
        RECT 0.000 308.500 0.400 308.900 ;
    END
  END Tile_X0Y5_FrameData[25]
  PIN Tile_X0Y5_FrameData[26]
    DIRECTION INPUT ;
    USE SIGNAL ;
    ANTENNAGATEAREA 1.807000 ;
    ANTENNADIFFAREA 20.153999 ;
    PORT
      LAYER Metal3 ;
        RECT 0.000 313.540 0.400 313.940 ;
    END
  END Tile_X0Y5_FrameData[26]
  PIN Tile_X0Y5_FrameData[27]
    DIRECTION INPUT ;
    USE SIGNAL ;
    ANTENNAGATEAREA 1.807000 ;
    PORT
      LAYER Metal3 ;
        RECT 0.000 318.580 0.400 318.980 ;
    END
  END Tile_X0Y5_FrameData[27]
  PIN Tile_X0Y5_FrameData[28]
    DIRECTION INPUT ;
    USE SIGNAL ;
    ANTENNAGATEAREA 1.987700 ;
    PORT
      LAYER Metal3 ;
        RECT 0.000 323.620 0.400 324.020 ;
    END
  END Tile_X0Y5_FrameData[28]
  PIN Tile_X0Y5_FrameData[29]
    DIRECTION INPUT ;
    USE SIGNAL ;
    ANTENNAGATEAREA 1.987700 ;
    PORT
      LAYER Metal3 ;
        RECT 0.000 328.660 0.400 329.060 ;
    END
  END Tile_X0Y5_FrameData[29]
  PIN Tile_X0Y5_FrameData[2]
    DIRECTION INPUT ;
    USE SIGNAL ;
    ANTENNAGATEAREA 1.807000 ;
    PORT
      LAYER Metal3 ;
        RECT 0.000 192.580 0.400 192.980 ;
    END
  END Tile_X0Y5_FrameData[2]
  PIN Tile_X0Y5_FrameData[30]
    DIRECTION INPUT ;
    USE SIGNAL ;
    ANTENNAGATEAREA 1.987700 ;
    PORT
      LAYER Metal3 ;
        RECT 0.000 333.700 0.400 334.100 ;
    END
  END Tile_X0Y5_FrameData[30]
  PIN Tile_X0Y5_FrameData[31]
    DIRECTION INPUT ;
    USE SIGNAL ;
    ANTENNAGATEAREA 1.987700 ;
    PORT
      LAYER Metal3 ;
        RECT 0.000 338.740 0.400 339.140 ;
    END
  END Tile_X0Y5_FrameData[31]
  PIN Tile_X0Y5_FrameData[3]
    DIRECTION INPUT ;
    USE SIGNAL ;
    ANTENNAGATEAREA 1.807000 ;
    PORT
      LAYER Metal3 ;
        RECT 0.000 197.620 0.400 198.020 ;
    END
  END Tile_X0Y5_FrameData[3]
  PIN Tile_X0Y5_FrameData[4]
    DIRECTION INPUT ;
    USE SIGNAL ;
    ANTENNAGATEAREA 1.807000 ;
    PORT
      LAYER Metal3 ;
        RECT 0.000 202.660 0.400 203.060 ;
    END
  END Tile_X0Y5_FrameData[4]
  PIN Tile_X0Y5_FrameData[5]
    DIRECTION INPUT ;
    USE SIGNAL ;
    ANTENNAGATEAREA 1.807000 ;
    PORT
      LAYER Metal3 ;
        RECT 0.000 207.700 0.400 208.100 ;
    END
  END Tile_X0Y5_FrameData[5]
  PIN Tile_X0Y5_FrameData[6]
    DIRECTION INPUT ;
    USE SIGNAL ;
    ANTENNAGATEAREA 1.807000 ;
    ANTENNADIFFAREA 20.153999 ;
    PORT
      LAYER Metal3 ;
        RECT 0.000 212.740 0.400 213.140 ;
    END
  END Tile_X0Y5_FrameData[6]
  PIN Tile_X0Y5_FrameData[7]
    DIRECTION INPUT ;
    USE SIGNAL ;
    ANTENNAGATEAREA 1.807000 ;
    PORT
      LAYER Metal3 ;
        RECT 0.000 217.780 0.400 218.180 ;
    END
  END Tile_X0Y5_FrameData[7]
  PIN Tile_X0Y5_FrameData[8]
    DIRECTION INPUT ;
    USE SIGNAL ;
    ANTENNAGATEAREA 1.807000 ;
    PORT
      LAYER Metal3 ;
        RECT 0.000 222.820 0.400 223.220 ;
    END
  END Tile_X0Y5_FrameData[8]
  PIN Tile_X0Y5_FrameData[9]
    DIRECTION INPUT ;
    USE SIGNAL ;
    ANTENNAGATEAREA 1.807000 ;
    PORT
      LAYER Metal3 ;
        RECT 0.000 227.860 0.400 228.260 ;
    END
  END Tile_X0Y5_FrameData[9]
  PIN Tile_X0Y5_FrameData_O[0]
    DIRECTION OUTPUT ;
    USE SIGNAL ;
    ANTENNADIFFAREA 0.708600 ;
    PORT
      LAYER Metal3 ;
        RECT 219.440 128.740 219.840 129.140 ;
    END
  END Tile_X0Y5_FrameData_O[0]
  PIN Tile_X0Y5_FrameData_O[10]
    DIRECTION OUTPUT ;
    USE SIGNAL ;
    ANTENNADIFFAREA 0.708600 ;
    PORT
      LAYER Metal3 ;
        RECT 219.440 137.140 219.840 137.540 ;
    END
  END Tile_X0Y5_FrameData_O[10]
  PIN Tile_X0Y5_FrameData_O[11]
    DIRECTION OUTPUT ;
    USE SIGNAL ;
    ANTENNADIFFAREA 0.708600 ;
    PORT
      LAYER Metal3 ;
        RECT 219.440 137.980 219.840 138.380 ;
    END
  END Tile_X0Y5_FrameData_O[11]
  PIN Tile_X0Y5_FrameData_O[12]
    DIRECTION OUTPUT ;
    USE SIGNAL ;
    ANTENNADIFFAREA 0.708600 ;
    PORT
      LAYER Metal3 ;
        RECT 219.440 138.820 219.840 139.220 ;
    END
  END Tile_X0Y5_FrameData_O[12]
  PIN Tile_X0Y5_FrameData_O[13]
    DIRECTION OUTPUT ;
    USE SIGNAL ;
    ANTENNADIFFAREA 0.708600 ;
    PORT
      LAYER Metal3 ;
        RECT 219.440 139.660 219.840 140.060 ;
    END
  END Tile_X0Y5_FrameData_O[13]
  PIN Tile_X0Y5_FrameData_O[14]
    DIRECTION OUTPUT ;
    USE SIGNAL ;
    ANTENNADIFFAREA 0.708600 ;
    PORT
      LAYER Metal3 ;
        RECT 219.440 140.500 219.840 140.900 ;
    END
  END Tile_X0Y5_FrameData_O[14]
  PIN Tile_X0Y5_FrameData_O[15]
    DIRECTION OUTPUT ;
    USE SIGNAL ;
    ANTENNADIFFAREA 0.708600 ;
    PORT
      LAYER Metal3 ;
        RECT 219.440 141.340 219.840 141.740 ;
    END
  END Tile_X0Y5_FrameData_O[15]
  PIN Tile_X0Y5_FrameData_O[16]
    DIRECTION OUTPUT ;
    USE SIGNAL ;
    ANTENNADIFFAREA 0.708600 ;
    PORT
      LAYER Metal3 ;
        RECT 219.440 142.180 219.840 142.580 ;
    END
  END Tile_X0Y5_FrameData_O[16]
  PIN Tile_X0Y5_FrameData_O[17]
    DIRECTION OUTPUT ;
    USE SIGNAL ;
    ANTENNADIFFAREA 0.708600 ;
    PORT
      LAYER Metal3 ;
        RECT 219.440 143.020 219.840 143.420 ;
    END
  END Tile_X0Y5_FrameData_O[17]
  PIN Tile_X0Y5_FrameData_O[18]
    DIRECTION OUTPUT ;
    USE SIGNAL ;
    ANTENNADIFFAREA 0.708600 ;
    PORT
      LAYER Metal3 ;
        RECT 219.440 143.860 219.840 144.260 ;
    END
  END Tile_X0Y5_FrameData_O[18]
  PIN Tile_X0Y5_FrameData_O[19]
    DIRECTION OUTPUT ;
    USE SIGNAL ;
    ANTENNADIFFAREA 0.708600 ;
    PORT
      LAYER Metal3 ;
        RECT 219.440 144.700 219.840 145.100 ;
    END
  END Tile_X0Y5_FrameData_O[19]
  PIN Tile_X0Y5_FrameData_O[1]
    DIRECTION OUTPUT ;
    USE SIGNAL ;
    ANTENNADIFFAREA 0.708600 ;
    PORT
      LAYER Metal3 ;
        RECT 219.440 129.580 219.840 129.980 ;
    END
  END Tile_X0Y5_FrameData_O[1]
  PIN Tile_X0Y5_FrameData_O[20]
    DIRECTION OUTPUT ;
    USE SIGNAL ;
    ANTENNADIFFAREA 0.708600 ;
    PORT
      LAYER Metal3 ;
        RECT 219.440 145.540 219.840 145.940 ;
    END
  END Tile_X0Y5_FrameData_O[20]
  PIN Tile_X0Y5_FrameData_O[21]
    DIRECTION OUTPUT ;
    USE SIGNAL ;
    ANTENNADIFFAREA 0.708600 ;
    PORT
      LAYER Metal3 ;
        RECT 219.440 146.380 219.840 146.780 ;
    END
  END Tile_X0Y5_FrameData_O[21]
  PIN Tile_X0Y5_FrameData_O[22]
    DIRECTION OUTPUT ;
    USE SIGNAL ;
    ANTENNADIFFAREA 0.708600 ;
    PORT
      LAYER Metal3 ;
        RECT 219.440 147.220 219.840 147.620 ;
    END
  END Tile_X0Y5_FrameData_O[22]
  PIN Tile_X0Y5_FrameData_O[23]
    DIRECTION OUTPUT ;
    USE SIGNAL ;
    ANTENNADIFFAREA 0.708600 ;
    PORT
      LAYER Metal3 ;
        RECT 219.440 148.060 219.840 148.460 ;
    END
  END Tile_X0Y5_FrameData_O[23]
  PIN Tile_X0Y5_FrameData_O[24]
    DIRECTION OUTPUT ;
    USE SIGNAL ;
    ANTENNADIFFAREA 0.708600 ;
    PORT
      LAYER Metal3 ;
        RECT 219.440 148.900 219.840 149.300 ;
    END
  END Tile_X0Y5_FrameData_O[24]
  PIN Tile_X0Y5_FrameData_O[25]
    DIRECTION OUTPUT ;
    USE SIGNAL ;
    ANTENNADIFFAREA 0.708600 ;
    PORT
      LAYER Metal3 ;
        RECT 219.440 149.740 219.840 150.140 ;
    END
  END Tile_X0Y5_FrameData_O[25]
  PIN Tile_X0Y5_FrameData_O[26]
    DIRECTION OUTPUT ;
    USE SIGNAL ;
    ANTENNADIFFAREA 0.708600 ;
    PORT
      LAYER Metal3 ;
        RECT 219.440 150.580 219.840 150.980 ;
    END
  END Tile_X0Y5_FrameData_O[26]
  PIN Tile_X0Y5_FrameData_O[27]
    DIRECTION OUTPUT ;
    USE SIGNAL ;
    ANTENNADIFFAREA 0.708600 ;
    PORT
      LAYER Metal3 ;
        RECT 219.440 151.420 219.840 151.820 ;
    END
  END Tile_X0Y5_FrameData_O[27]
  PIN Tile_X0Y5_FrameData_O[28]
    DIRECTION OUTPUT ;
    USE SIGNAL ;
    ANTENNADIFFAREA 0.708600 ;
    PORT
      LAYER Metal3 ;
        RECT 219.440 152.260 219.840 152.660 ;
    END
  END Tile_X0Y5_FrameData_O[28]
  PIN Tile_X0Y5_FrameData_O[29]
    DIRECTION OUTPUT ;
    USE SIGNAL ;
    ANTENNADIFFAREA 0.708600 ;
    PORT
      LAYER Metal3 ;
        RECT 219.440 153.100 219.840 153.500 ;
    END
  END Tile_X0Y5_FrameData_O[29]
  PIN Tile_X0Y5_FrameData_O[2]
    DIRECTION OUTPUT ;
    USE SIGNAL ;
    ANTENNADIFFAREA 0.708600 ;
    PORT
      LAYER Metal3 ;
        RECT 219.440 130.420 219.840 130.820 ;
    END
  END Tile_X0Y5_FrameData_O[2]
  PIN Tile_X0Y5_FrameData_O[30]
    DIRECTION OUTPUT ;
    USE SIGNAL ;
    ANTENNADIFFAREA 0.708600 ;
    PORT
      LAYER Metal3 ;
        RECT 219.440 153.940 219.840 154.340 ;
    END
  END Tile_X0Y5_FrameData_O[30]
  PIN Tile_X0Y5_FrameData_O[31]
    DIRECTION OUTPUT ;
    USE SIGNAL ;
    ANTENNADIFFAREA 0.708600 ;
    PORT
      LAYER Metal3 ;
        RECT 219.440 154.780 219.840 155.180 ;
    END
  END Tile_X0Y5_FrameData_O[31]
  PIN Tile_X0Y5_FrameData_O[3]
    DIRECTION OUTPUT ;
    USE SIGNAL ;
    ANTENNADIFFAREA 0.708600 ;
    PORT
      LAYER Metal3 ;
        RECT 219.440 131.260 219.840 131.660 ;
    END
  END Tile_X0Y5_FrameData_O[3]
  PIN Tile_X0Y5_FrameData_O[4]
    DIRECTION OUTPUT ;
    USE SIGNAL ;
    ANTENNADIFFAREA 0.708600 ;
    PORT
      LAYER Metal3 ;
        RECT 219.440 132.100 219.840 132.500 ;
    END
  END Tile_X0Y5_FrameData_O[4]
  PIN Tile_X0Y5_FrameData_O[5]
    DIRECTION OUTPUT ;
    USE SIGNAL ;
    ANTENNADIFFAREA 0.708600 ;
    PORT
      LAYER Metal3 ;
        RECT 219.440 132.940 219.840 133.340 ;
    END
  END Tile_X0Y5_FrameData_O[5]
  PIN Tile_X0Y5_FrameData_O[6]
    DIRECTION OUTPUT ;
    USE SIGNAL ;
    ANTENNADIFFAREA 0.708600 ;
    PORT
      LAYER Metal3 ;
        RECT 219.440 133.780 219.840 134.180 ;
    END
  END Tile_X0Y5_FrameData_O[6]
  PIN Tile_X0Y5_FrameData_O[7]
    DIRECTION OUTPUT ;
    USE SIGNAL ;
    ANTENNADIFFAREA 0.708600 ;
    PORT
      LAYER Metal3 ;
        RECT 219.440 134.620 219.840 135.020 ;
    END
  END Tile_X0Y5_FrameData_O[7]
  PIN Tile_X0Y5_FrameData_O[8]
    DIRECTION OUTPUT ;
    USE SIGNAL ;
    ANTENNADIFFAREA 0.708600 ;
    PORT
      LAYER Metal3 ;
        RECT 219.440 135.460 219.840 135.860 ;
    END
  END Tile_X0Y5_FrameData_O[8]
  PIN Tile_X0Y5_FrameData_O[9]
    DIRECTION OUTPUT ;
    USE SIGNAL ;
    ANTENNADIFFAREA 0.708600 ;
    PORT
      LAYER Metal3 ;
        RECT 219.440 136.300 219.840 136.700 ;
    END
  END Tile_X0Y5_FrameData_O[9]
  PIN Tile_X0Y5_FrameStrobe[0]
    DIRECTION INPUT ;
    USE SIGNAL ;
    ANTENNAGATEAREA 39.617500 ;
    PORT
      LAYER Metal2 ;
        RECT 159.640 0.000 160.040 0.400 ;
    END
  END Tile_X0Y5_FrameStrobe[0]
  PIN Tile_X0Y5_FrameStrobe[10]
    DIRECTION INPUT ;
    USE SIGNAL ;
    ANTENNAGATEAREA 0.180700 ;
    PORT
      LAYER Metal2 ;
        RECT 178.840 0.000 179.240 0.400 ;
    END
  END Tile_X0Y5_FrameStrobe[10]
  PIN Tile_X0Y5_FrameStrobe[11]
    DIRECTION INPUT ;
    USE SIGNAL ;
    ANTENNAGATEAREA 0.180700 ;
    PORT
      LAYER Metal2 ;
        RECT 180.760 0.000 181.160 0.400 ;
    END
  END Tile_X0Y5_FrameStrobe[11]
  PIN Tile_X0Y5_FrameStrobe[12]
    DIRECTION INPUT ;
    USE SIGNAL ;
    ANTENNAGATEAREA 0.180700 ;
    PORT
      LAYER Metal2 ;
        RECT 182.680 0.000 183.080 0.400 ;
    END
  END Tile_X0Y5_FrameStrobe[12]
  PIN Tile_X0Y5_FrameStrobe[13]
    DIRECTION INPUT ;
    USE SIGNAL ;
    ANTENNAGATEAREA 0.180700 ;
    PORT
      LAYER Metal2 ;
        RECT 184.600 0.000 185.000 0.400 ;
    END
  END Tile_X0Y5_FrameStrobe[13]
  PIN Tile_X0Y5_FrameStrobe[14]
    DIRECTION INPUT ;
    USE SIGNAL ;
    ANTENNAGATEAREA 0.180700 ;
    PORT
      LAYER Metal2 ;
        RECT 186.520 0.000 186.920 0.400 ;
    END
  END Tile_X0Y5_FrameStrobe[14]
  PIN Tile_X0Y5_FrameStrobe[15]
    DIRECTION INPUT ;
    USE SIGNAL ;
    ANTENNAGATEAREA 0.180700 ;
    PORT
      LAYER Metal2 ;
        RECT 188.440 0.000 188.840 0.400 ;
    END
  END Tile_X0Y5_FrameStrobe[15]
  PIN Tile_X0Y5_FrameStrobe[16]
    DIRECTION INPUT ;
    USE SIGNAL ;
    ANTENNAGATEAREA 0.180700 ;
    PORT
      LAYER Metal2 ;
        RECT 190.360 0.000 190.760 0.400 ;
    END
  END Tile_X0Y5_FrameStrobe[16]
  PIN Tile_X0Y5_FrameStrobe[17]
    DIRECTION INPUT ;
    USE SIGNAL ;
    ANTENNAGATEAREA 0.180700 ;
    PORT
      LAYER Metal2 ;
        RECT 192.280 0.000 192.680 0.400 ;
    END
  END Tile_X0Y5_FrameStrobe[17]
  PIN Tile_X0Y5_FrameStrobe[18]
    DIRECTION INPUT ;
    USE SIGNAL ;
    ANTENNAGATEAREA 0.180700 ;
    PORT
      LAYER Metal2 ;
        RECT 194.200 0.000 194.600 0.400 ;
    END
  END Tile_X0Y5_FrameStrobe[18]
  PIN Tile_X0Y5_FrameStrobe[19]
    DIRECTION INPUT ;
    USE SIGNAL ;
    ANTENNAGATEAREA 0.180700 ;
    PORT
      LAYER Metal2 ;
        RECT 196.120 0.000 196.520 0.400 ;
    END
  END Tile_X0Y5_FrameStrobe[19]
  PIN Tile_X0Y5_FrameStrobe[1]
    DIRECTION INPUT ;
    USE SIGNAL ;
    ANTENNAGATEAREA 39.617500 ;
    PORT
      LAYER Metal2 ;
        RECT 161.560 0.000 161.960 0.400 ;
    END
  END Tile_X0Y5_FrameStrobe[1]
  PIN Tile_X0Y5_FrameStrobe[2]
    DIRECTION INPUT ;
    USE SIGNAL ;
    ANTENNAGATEAREA 39.617500 ;
    PORT
      LAYER Metal2 ;
        RECT 163.480 0.000 163.880 0.400 ;
    END
  END Tile_X0Y5_FrameStrobe[2]
  PIN Tile_X0Y5_FrameStrobe[3]
    DIRECTION INPUT ;
    USE SIGNAL ;
    ANTENNAGATEAREA 39.617500 ;
    PORT
      LAYER Metal2 ;
        RECT 165.400 0.000 165.800 0.400 ;
    END
  END Tile_X0Y5_FrameStrobe[3]
  PIN Tile_X0Y5_FrameStrobe[4]
    DIRECTION INPUT ;
    USE SIGNAL ;
    ANTENNAGATEAREA 39.617500 ;
    PORT
      LAYER Metal2 ;
        RECT 167.320 0.000 167.720 0.400 ;
    END
  END Tile_X0Y5_FrameStrobe[4]
  PIN Tile_X0Y5_FrameStrobe[5]
    DIRECTION INPUT ;
    USE SIGNAL ;
    ANTENNAGATEAREA 39.617500 ;
    PORT
      LAYER Metal2 ;
        RECT 169.240 0.000 169.640 0.400 ;
    END
  END Tile_X0Y5_FrameStrobe[5]
  PIN Tile_X0Y5_FrameStrobe[6]
    DIRECTION INPUT ;
    USE SIGNAL ;
    ANTENNAGATEAREA 39.617500 ;
    PORT
      LAYER Metal2 ;
        RECT 171.160 0.000 171.560 0.400 ;
    END
  END Tile_X0Y5_FrameStrobe[6]
  PIN Tile_X0Y5_FrameStrobe[7]
    DIRECTION INPUT ;
    USE SIGNAL ;
    ANTENNAGATEAREA 39.617500 ;
    PORT
      LAYER Metal2 ;
        RECT 173.080 0.000 173.480 0.400 ;
    END
  END Tile_X0Y5_FrameStrobe[7]
  PIN Tile_X0Y5_FrameStrobe[8]
    DIRECTION INPUT ;
    USE SIGNAL ;
    ANTENNAGATEAREA 23.185499 ;
    PORT
      LAYER Metal2 ;
        RECT 175.000 0.000 175.400 0.400 ;
    END
  END Tile_X0Y5_FrameStrobe[8]
  PIN Tile_X0Y5_FrameStrobe[9]
    DIRECTION INPUT ;
    USE SIGNAL ;
    ANTENNAGATEAREA 1.002300 ;
    PORT
      LAYER Metal2 ;
        RECT 176.920 0.000 177.320 0.400 ;
    END
  END Tile_X0Y5_FrameStrobe[9]
  PIN Tile_X0Y5_N1END[0]
    DIRECTION INPUT ;
    USE SIGNAL ;
    ANTENNAGATEAREA 1.246700 ;
    PORT
      LAYER Metal2 ;
        RECT 21.400 0.000 21.800 0.400 ;
    END
  END Tile_X0Y5_N1END[0]
  PIN Tile_X0Y5_N1END[1]
    DIRECTION INPUT ;
    USE SIGNAL ;
    ANTENNAGATEAREA 1.246700 ;
    PORT
      LAYER Metal2 ;
        RECT 23.320 0.000 23.720 0.400 ;
    END
  END Tile_X0Y5_N1END[1]
  PIN Tile_X0Y5_N1END[2]
    DIRECTION INPUT ;
    USE SIGNAL ;
    ANTENNAGATEAREA 1.246700 ;
    PORT
      LAYER Metal2 ;
        RECT 25.240 0.000 25.640 0.400 ;
    END
  END Tile_X0Y5_N1END[2]
  PIN Tile_X0Y5_N1END[3]
    DIRECTION INPUT ;
    USE SIGNAL ;
    ANTENNAGATEAREA 1.246700 ;
    PORT
      LAYER Metal2 ;
        RECT 27.160 0.000 27.560 0.400 ;
    END
  END Tile_X0Y5_N1END[3]
  PIN Tile_X0Y5_N2END[0]
    DIRECTION INPUT ;
    USE SIGNAL ;
    ANTENNAGATEAREA 0.213200 ;
    PORT
      LAYER Metal2 ;
        RECT 44.440 0.000 44.840 0.400 ;
    END
  END Tile_X0Y5_N2END[0]
  PIN Tile_X0Y5_N2END[1]
    DIRECTION INPUT ;
    USE SIGNAL ;
    ANTENNAGATEAREA 0.213200 ;
    PORT
      LAYER Metal2 ;
        RECT 46.360 0.000 46.760 0.400 ;
    END
  END Tile_X0Y5_N2END[1]
  PIN Tile_X0Y5_N2END[2]
    DIRECTION INPUT ;
    USE SIGNAL ;
    ANTENNAGATEAREA 0.213200 ;
    PORT
      LAYER Metal2 ;
        RECT 48.280 0.000 48.680 0.400 ;
    END
  END Tile_X0Y5_N2END[2]
  PIN Tile_X0Y5_N2END[3]
    DIRECTION INPUT ;
    USE SIGNAL ;
    ANTENNAGATEAREA 0.213200 ;
    PORT
      LAYER Metal2 ;
        RECT 50.200 0.000 50.600 0.400 ;
    END
  END Tile_X0Y5_N2END[3]
  PIN Tile_X0Y5_N2END[4]
    DIRECTION INPUT ;
    USE SIGNAL ;
    ANTENNAGATEAREA 0.213200 ;
    PORT
      LAYER Metal2 ;
        RECT 52.120 0.000 52.520 0.400 ;
    END
  END Tile_X0Y5_N2END[4]
  PIN Tile_X0Y5_N2END[5]
    DIRECTION INPUT ;
    USE SIGNAL ;
    ANTENNAGATEAREA 0.213200 ;
    PORT
      LAYER Metal2 ;
        RECT 54.040 0.000 54.440 0.400 ;
    END
  END Tile_X0Y5_N2END[5]
  PIN Tile_X0Y5_N2END[6]
    DIRECTION INPUT ;
    USE SIGNAL ;
    ANTENNAGATEAREA 0.213200 ;
    PORT
      LAYER Metal2 ;
        RECT 55.960 0.000 56.360 0.400 ;
    END
  END Tile_X0Y5_N2END[6]
  PIN Tile_X0Y5_N2END[7]
    DIRECTION INPUT ;
    USE SIGNAL ;
    ANTENNAGATEAREA 0.213200 ;
    PORT
      LAYER Metal2 ;
        RECT 57.880 0.000 58.280 0.400 ;
    END
  END Tile_X0Y5_N2END[7]
  PIN Tile_X0Y5_N2MID[0]
    DIRECTION INPUT ;
    USE SIGNAL ;
    ANTENNAGATEAREA 0.426400 ;
    PORT
      LAYER Metal2 ;
        RECT 29.080 0.000 29.480 0.400 ;
    END
  END Tile_X0Y5_N2MID[0]
  PIN Tile_X0Y5_N2MID[1]
    DIRECTION INPUT ;
    USE SIGNAL ;
    ANTENNAGATEAREA 0.426400 ;
    ANTENNADIFFAREA 4.030800 ;
    PORT
      LAYER Metal2 ;
        RECT 31.000 0.000 31.400 0.400 ;
    END
  END Tile_X0Y5_N2MID[1]
  PIN Tile_X0Y5_N2MID[2]
    DIRECTION INPUT ;
    USE SIGNAL ;
    ANTENNAGATEAREA 0.426400 ;
    ANTENNADIFFAREA 4.030800 ;
    PORT
      LAYER Metal2 ;
        RECT 32.920 0.000 33.320 0.400 ;
    END
  END Tile_X0Y5_N2MID[2]
  PIN Tile_X0Y5_N2MID[3]
    DIRECTION INPUT ;
    USE SIGNAL ;
    ANTENNAGATEAREA 0.426400 ;
    PORT
      LAYER Metal2 ;
        RECT 34.840 0.000 35.240 0.400 ;
    END
  END Tile_X0Y5_N2MID[3]
  PIN Tile_X0Y5_N2MID[4]
    DIRECTION INPUT ;
    USE SIGNAL ;
    ANTENNAGATEAREA 0.426400 ;
    PORT
      LAYER Metal2 ;
        RECT 36.760 0.000 37.160 0.400 ;
    END
  END Tile_X0Y5_N2MID[4]
  PIN Tile_X0Y5_N2MID[5]
    DIRECTION INPUT ;
    USE SIGNAL ;
    ANTENNAGATEAREA 0.426400 ;
    PORT
      LAYER Metal2 ;
        RECT 38.680 0.000 39.080 0.400 ;
    END
  END Tile_X0Y5_N2MID[5]
  PIN Tile_X0Y5_N2MID[6]
    DIRECTION INPUT ;
    USE SIGNAL ;
    ANTENNAGATEAREA 0.426400 ;
    ANTENNADIFFAREA 4.030800 ;
    PORT
      LAYER Metal2 ;
        RECT 40.600 0.000 41.000 0.400 ;
    END
  END Tile_X0Y5_N2MID[6]
  PIN Tile_X0Y5_N2MID[7]
    DIRECTION INPUT ;
    USE SIGNAL ;
    ANTENNAGATEAREA 0.426400 ;
    PORT
      LAYER Metal2 ;
        RECT 42.520 0.000 42.920 0.400 ;
    END
  END Tile_X0Y5_N2MID[7]
  PIN Tile_X0Y5_N4END[0]
    DIRECTION INPUT ;
    USE SIGNAL ;
    ANTENNAGATEAREA 1.066000 ;
    PORT
      LAYER Metal2 ;
        RECT 59.800 0.000 60.200 0.400 ;
    END
  END Tile_X0Y5_N4END[0]
  PIN Tile_X0Y5_N4END[10]
    DIRECTION INPUT ;
    USE SIGNAL ;
    ANTENNAGATEAREA 1.066000 ;
    PORT
      LAYER Metal2 ;
        RECT 79.000 0.000 79.400 0.400 ;
    END
  END Tile_X0Y5_N4END[10]
  PIN Tile_X0Y5_N4END[11]
    DIRECTION INPUT ;
    USE SIGNAL ;
    ANTENNAGATEAREA 1.066000 ;
    PORT
      LAYER Metal2 ;
        RECT 80.920 0.000 81.320 0.400 ;
    END
  END Tile_X0Y5_N4END[11]
  PIN Tile_X0Y5_N4END[12]
    DIRECTION INPUT ;
    USE SIGNAL ;
    ANTENNAGATEAREA 1.066000 ;
    PORT
      LAYER Metal2 ;
        RECT 82.840 0.000 83.240 0.400 ;
    END
  END Tile_X0Y5_N4END[12]
  PIN Tile_X0Y5_N4END[13]
    DIRECTION INPUT ;
    USE SIGNAL ;
    ANTENNAGATEAREA 1.066000 ;
    ANTENNADIFFAREA 48.369598 ;
    PORT
      LAYER Metal2 ;
        RECT 84.760 0.000 85.160 0.400 ;
    END
  END Tile_X0Y5_N4END[13]
  PIN Tile_X0Y5_N4END[14]
    DIRECTION INPUT ;
    USE SIGNAL ;
    ANTENNAGATEAREA 1.066000 ;
    PORT
      LAYER Metal2 ;
        RECT 86.680 0.000 87.080 0.400 ;
    END
  END Tile_X0Y5_N4END[14]
  PIN Tile_X0Y5_N4END[15]
    DIRECTION INPUT ;
    USE SIGNAL ;
    ANTENNAGATEAREA 1.066000 ;
    PORT
      LAYER Metal2 ;
        RECT 88.600 0.000 89.000 0.400 ;
    END
  END Tile_X0Y5_N4END[15]
  PIN Tile_X0Y5_N4END[1]
    DIRECTION INPUT ;
    USE SIGNAL ;
    ANTENNAGATEAREA 1.066000 ;
    PORT
      LAYER Metal2 ;
        RECT 61.720 0.000 62.120 0.400 ;
    END
  END Tile_X0Y5_N4END[1]
  PIN Tile_X0Y5_N4END[2]
    DIRECTION INPUT ;
    USE SIGNAL ;
    ANTENNAGATEAREA 1.066000 ;
    PORT
      LAYER Metal2 ;
        RECT 63.640 0.000 64.040 0.400 ;
    END
  END Tile_X0Y5_N4END[2]
  PIN Tile_X0Y5_N4END[3]
    DIRECTION INPUT ;
    USE SIGNAL ;
    ANTENNAGATEAREA 1.066000 ;
    PORT
      LAYER Metal2 ;
        RECT 65.560 0.000 65.960 0.400 ;
    END
  END Tile_X0Y5_N4END[3]
  PIN Tile_X0Y5_N4END[4]
    DIRECTION INPUT ;
    USE SIGNAL ;
    ANTENNAGATEAREA 1.066000 ;
    PORT
      LAYER Metal2 ;
        RECT 67.480 0.000 67.880 0.400 ;
    END
  END Tile_X0Y5_N4END[4]
  PIN Tile_X0Y5_N4END[5]
    DIRECTION INPUT ;
    USE SIGNAL ;
    ANTENNAGATEAREA 1.066000 ;
    PORT
      LAYER Metal2 ;
        RECT 69.400 0.000 69.800 0.400 ;
    END
  END Tile_X0Y5_N4END[5]
  PIN Tile_X0Y5_N4END[6]
    DIRECTION INPUT ;
    USE SIGNAL ;
    ANTENNAGATEAREA 1.066000 ;
    PORT
      LAYER Metal2 ;
        RECT 71.320 0.000 71.720 0.400 ;
    END
  END Tile_X0Y5_N4END[6]
  PIN Tile_X0Y5_N4END[7]
    DIRECTION INPUT ;
    USE SIGNAL ;
    ANTENNAGATEAREA 1.066000 ;
    PORT
      LAYER Metal2 ;
        RECT 73.240 0.000 73.640 0.400 ;
    END
  END Tile_X0Y5_N4END[7]
  PIN Tile_X0Y5_N4END[8]
    DIRECTION INPUT ;
    USE SIGNAL ;
    ANTENNAGATEAREA 1.066000 ;
    PORT
      LAYER Metal2 ;
        RECT 75.160 0.000 75.560 0.400 ;
    END
  END Tile_X0Y5_N4END[8]
  PIN Tile_X0Y5_N4END[9]
    DIRECTION INPUT ;
    USE SIGNAL ;
    ANTENNAGATEAREA 1.066000 ;
    PORT
      LAYER Metal2 ;
        RECT 77.080 0.000 77.480 0.400 ;
    END
  END Tile_X0Y5_N4END[9]
  PIN Tile_X0Y5_S1BEG[0]
    DIRECTION OUTPUT ;
    USE SIGNAL ;
    ANTENNADIFFAREA 0.708600 ;
    PORT
      LAYER Metal2 ;
        RECT 90.520 0.000 90.920 0.400 ;
    END
  END Tile_X0Y5_S1BEG[0]
  PIN Tile_X0Y5_S1BEG[1]
    DIRECTION OUTPUT ;
    USE SIGNAL ;
    ANTENNADIFFAREA 0.708600 ;
    PORT
      LAYER Metal2 ;
        RECT 92.440 0.000 92.840 0.400 ;
    END
  END Tile_X0Y5_S1BEG[1]
  PIN Tile_X0Y5_S1BEG[2]
    DIRECTION OUTPUT ;
    USE SIGNAL ;
    ANTENNADIFFAREA 0.708600 ;
    PORT
      LAYER Metal2 ;
        RECT 94.360 0.000 94.760 0.400 ;
    END
  END Tile_X0Y5_S1BEG[2]
  PIN Tile_X0Y5_S1BEG[3]
    DIRECTION OUTPUT ;
    USE SIGNAL ;
    ANTENNADIFFAREA 0.708600 ;
    PORT
      LAYER Metal2 ;
        RECT 96.280 0.000 96.680 0.400 ;
    END
  END Tile_X0Y5_S1BEG[3]
  PIN Tile_X0Y5_S2BEG[0]
    DIRECTION OUTPUT ;
    USE SIGNAL ;
    ANTENNADIFFAREA 0.708600 ;
    PORT
      LAYER Metal2 ;
        RECT 98.200 0.000 98.600 0.400 ;
    END
  END Tile_X0Y5_S2BEG[0]
  PIN Tile_X0Y5_S2BEG[1]
    DIRECTION OUTPUT ;
    USE SIGNAL ;
    ANTENNADIFFAREA 0.708600 ;
    PORT
      LAYER Metal2 ;
        RECT 100.120 0.000 100.520 0.400 ;
    END
  END Tile_X0Y5_S2BEG[1]
  PIN Tile_X0Y5_S2BEG[2]
    DIRECTION OUTPUT ;
    USE SIGNAL ;
    ANTENNADIFFAREA 0.708600 ;
    PORT
      LAYER Metal2 ;
        RECT 102.040 0.000 102.440 0.400 ;
    END
  END Tile_X0Y5_S2BEG[2]
  PIN Tile_X0Y5_S2BEG[3]
    DIRECTION OUTPUT ;
    USE SIGNAL ;
    ANTENNADIFFAREA 0.708600 ;
    PORT
      LAYER Metal2 ;
        RECT 103.960 0.000 104.360 0.400 ;
    END
  END Tile_X0Y5_S2BEG[3]
  PIN Tile_X0Y5_S2BEG[4]
    DIRECTION OUTPUT ;
    USE SIGNAL ;
    ANTENNADIFFAREA 0.708600 ;
    PORT
      LAYER Metal2 ;
        RECT 105.880 0.000 106.280 0.400 ;
    END
  END Tile_X0Y5_S2BEG[4]
  PIN Tile_X0Y5_S2BEG[5]
    DIRECTION OUTPUT ;
    USE SIGNAL ;
    ANTENNADIFFAREA 0.708600 ;
    PORT
      LAYER Metal2 ;
        RECT 107.800 0.000 108.200 0.400 ;
    END
  END Tile_X0Y5_S2BEG[5]
  PIN Tile_X0Y5_S2BEG[6]
    DIRECTION OUTPUT ;
    USE SIGNAL ;
    ANTENNADIFFAREA 0.708600 ;
    PORT
      LAYER Metal2 ;
        RECT 109.720 0.000 110.120 0.400 ;
    END
  END Tile_X0Y5_S2BEG[6]
  PIN Tile_X0Y5_S2BEG[7]
    DIRECTION OUTPUT ;
    USE SIGNAL ;
    ANTENNADIFFAREA 0.708600 ;
    PORT
      LAYER Metal2 ;
        RECT 111.640 0.000 112.040 0.400 ;
    END
  END Tile_X0Y5_S2BEG[7]
  PIN Tile_X0Y5_S2BEGb[0]
    DIRECTION OUTPUT ;
    USE SIGNAL ;
    ANTENNADIFFAREA 0.708600 ;
    PORT
      LAYER Metal2 ;
        RECT 113.560 0.000 113.960 0.400 ;
    END
  END Tile_X0Y5_S2BEGb[0]
  PIN Tile_X0Y5_S2BEGb[1]
    DIRECTION OUTPUT ;
    USE SIGNAL ;
    ANTENNADIFFAREA 0.708600 ;
    PORT
      LAYER Metal2 ;
        RECT 115.480 0.000 115.880 0.400 ;
    END
  END Tile_X0Y5_S2BEGb[1]
  PIN Tile_X0Y5_S2BEGb[2]
    DIRECTION OUTPUT ;
    USE SIGNAL ;
    ANTENNADIFFAREA 0.708600 ;
    PORT
      LAYER Metal2 ;
        RECT 117.400 0.000 117.800 0.400 ;
    END
  END Tile_X0Y5_S2BEGb[2]
  PIN Tile_X0Y5_S2BEGb[3]
    DIRECTION OUTPUT ;
    USE SIGNAL ;
    ANTENNADIFFAREA 0.708600 ;
    PORT
      LAYER Metal2 ;
        RECT 119.320 0.000 119.720 0.400 ;
    END
  END Tile_X0Y5_S2BEGb[3]
  PIN Tile_X0Y5_S2BEGb[4]
    DIRECTION OUTPUT ;
    USE SIGNAL ;
    ANTENNADIFFAREA 0.708600 ;
    PORT
      LAYER Metal2 ;
        RECT 121.240 0.000 121.640 0.400 ;
    END
  END Tile_X0Y5_S2BEGb[4]
  PIN Tile_X0Y5_S2BEGb[5]
    DIRECTION OUTPUT ;
    USE SIGNAL ;
    ANTENNADIFFAREA 0.708600 ;
    PORT
      LAYER Metal2 ;
        RECT 123.160 0.000 123.560 0.400 ;
    END
  END Tile_X0Y5_S2BEGb[5]
  PIN Tile_X0Y5_S2BEGb[6]
    DIRECTION OUTPUT ;
    USE SIGNAL ;
    ANTENNADIFFAREA 0.708600 ;
    PORT
      LAYER Metal2 ;
        RECT 125.080 0.000 125.480 0.400 ;
    END
  END Tile_X0Y5_S2BEGb[6]
  PIN Tile_X0Y5_S2BEGb[7]
    DIRECTION OUTPUT ;
    USE SIGNAL ;
    ANTENNADIFFAREA 0.708600 ;
    PORT
      LAYER Metal2 ;
        RECT 127.000 0.000 127.400 0.400 ;
    END
  END Tile_X0Y5_S2BEGb[7]
  PIN Tile_X0Y5_S4BEG[0]
    DIRECTION OUTPUT ;
    USE SIGNAL ;
    ANTENNADIFFAREA 0.708600 ;
    PORT
      LAYER Metal2 ;
        RECT 128.920 0.000 129.320 0.400 ;
    END
  END Tile_X0Y5_S4BEG[0]
  PIN Tile_X0Y5_S4BEG[10]
    DIRECTION OUTPUT ;
    USE SIGNAL ;
    ANTENNADIFFAREA 0.708600 ;
    PORT
      LAYER Metal2 ;
        RECT 148.120 0.000 148.520 0.400 ;
    END
  END Tile_X0Y5_S4BEG[10]
  PIN Tile_X0Y5_S4BEG[11]
    DIRECTION OUTPUT ;
    USE SIGNAL ;
    ANTENNADIFFAREA 0.708600 ;
    PORT
      LAYER Metal2 ;
        RECT 150.040 0.000 150.440 0.400 ;
    END
  END Tile_X0Y5_S4BEG[11]
  PIN Tile_X0Y5_S4BEG[12]
    DIRECTION OUTPUT ;
    USE SIGNAL ;
    ANTENNADIFFAREA 0.708600 ;
    PORT
      LAYER Metal2 ;
        RECT 151.960 0.000 152.360 0.400 ;
    END
  END Tile_X0Y5_S4BEG[12]
  PIN Tile_X0Y5_S4BEG[13]
    DIRECTION OUTPUT ;
    USE SIGNAL ;
    ANTENNADIFFAREA 0.708600 ;
    PORT
      LAYER Metal2 ;
        RECT 153.880 0.000 154.280 0.400 ;
    END
  END Tile_X0Y5_S4BEG[13]
  PIN Tile_X0Y5_S4BEG[14]
    DIRECTION OUTPUT ;
    USE SIGNAL ;
    ANTENNADIFFAREA 0.708600 ;
    PORT
      LAYER Metal2 ;
        RECT 155.800 0.000 156.200 0.400 ;
    END
  END Tile_X0Y5_S4BEG[14]
  PIN Tile_X0Y5_S4BEG[15]
    DIRECTION OUTPUT ;
    USE SIGNAL ;
    ANTENNADIFFAREA 0.708600 ;
    PORT
      LAYER Metal2 ;
        RECT 157.720 0.000 158.120 0.400 ;
    END
  END Tile_X0Y5_S4BEG[15]
  PIN Tile_X0Y5_S4BEG[1]
    DIRECTION OUTPUT ;
    USE SIGNAL ;
    ANTENNADIFFAREA 0.708600 ;
    PORT
      LAYER Metal2 ;
        RECT 130.840 0.000 131.240 0.400 ;
    END
  END Tile_X0Y5_S4BEG[1]
  PIN Tile_X0Y5_S4BEG[2]
    DIRECTION OUTPUT ;
    USE SIGNAL ;
    ANTENNADIFFAREA 0.708600 ;
    PORT
      LAYER Metal2 ;
        RECT 132.760 0.000 133.160 0.400 ;
    END
  END Tile_X0Y5_S4BEG[2]
  PIN Tile_X0Y5_S4BEG[3]
    DIRECTION OUTPUT ;
    USE SIGNAL ;
    ANTENNADIFFAREA 0.708600 ;
    PORT
      LAYER Metal2 ;
        RECT 134.680 0.000 135.080 0.400 ;
    END
  END Tile_X0Y5_S4BEG[3]
  PIN Tile_X0Y5_S4BEG[4]
    DIRECTION OUTPUT ;
    USE SIGNAL ;
    ANTENNADIFFAREA 0.708600 ;
    PORT
      LAYER Metal2 ;
        RECT 136.600 0.000 137.000 0.400 ;
    END
  END Tile_X0Y5_S4BEG[4]
  PIN Tile_X0Y5_S4BEG[5]
    DIRECTION OUTPUT ;
    USE SIGNAL ;
    ANTENNADIFFAREA 0.708600 ;
    PORT
      LAYER Metal2 ;
        RECT 138.520 0.000 138.920 0.400 ;
    END
  END Tile_X0Y5_S4BEG[5]
  PIN Tile_X0Y5_S4BEG[6]
    DIRECTION OUTPUT ;
    USE SIGNAL ;
    ANTENNADIFFAREA 0.708600 ;
    PORT
      LAYER Metal2 ;
        RECT 140.440 0.000 140.840 0.400 ;
    END
  END Tile_X0Y5_S4BEG[6]
  PIN Tile_X0Y5_S4BEG[7]
    DIRECTION OUTPUT ;
    USE SIGNAL ;
    ANTENNADIFFAREA 0.708600 ;
    PORT
      LAYER Metal2 ;
        RECT 142.360 0.000 142.760 0.400 ;
    END
  END Tile_X0Y5_S4BEG[7]
  PIN Tile_X0Y5_S4BEG[8]
    DIRECTION OUTPUT ;
    USE SIGNAL ;
    ANTENNADIFFAREA 0.708600 ;
    PORT
      LAYER Metal2 ;
        RECT 144.280 0.000 144.680 0.400 ;
    END
  END Tile_X0Y5_S4BEG[8]
  PIN Tile_X0Y5_S4BEG[9]
    DIRECTION OUTPUT ;
    USE SIGNAL ;
    ANTENNADIFFAREA 0.708600 ;
    PORT
      LAYER Metal2 ;
        RECT 146.200 0.000 146.600 0.400 ;
    END
  END Tile_X0Y5_S4BEG[9]
  PIN Tile_X0Y5_UserCLK
    DIRECTION INPUT ;
    USE SIGNAL ;
    ANTENNAGATEAREA 0.180700 ;
    PORT
      LAYER Metal2 ;
        RECT 198.040 0.000 198.440 0.400 ;
    END
  END Tile_X0Y5_UserCLK
  PIN Tile_X0Y5_W1END[0]
    DIRECTION INPUT ;
    USE SIGNAL ;
    ANTENNAGATEAREA 1.305200 ;
    PORT
      LAYER Metal3 ;
        RECT 219.440 48.100 219.840 48.500 ;
    END
  END Tile_X0Y5_W1END[0]
  PIN Tile_X0Y5_W1END[1]
    DIRECTION INPUT ;
    USE SIGNAL ;
    ANTENNAGATEAREA 1.305200 ;
    PORT
      LAYER Metal3 ;
        RECT 219.440 48.940 219.840 49.340 ;
    END
  END Tile_X0Y5_W1END[1]
  PIN Tile_X0Y5_W1END[2]
    DIRECTION INPUT ;
    USE SIGNAL ;
    ANTENNAGATEAREA 1.305200 ;
    PORT
      LAYER Metal3 ;
        RECT 219.440 49.780 219.840 50.180 ;
    END
  END Tile_X0Y5_W1END[2]
  PIN Tile_X0Y5_W1END[3]
    DIRECTION INPUT ;
    USE SIGNAL ;
    ANTENNAGATEAREA 1.305200 ;
    PORT
      LAYER Metal3 ;
        RECT 219.440 50.620 219.840 51.020 ;
    END
  END Tile_X0Y5_W1END[3]
  PIN Tile_X0Y5_W2END[0]
    DIRECTION INPUT ;
    USE SIGNAL ;
    ANTENNAGATEAREA 0.852800 ;
    PORT
      LAYER Metal3 ;
        RECT 219.440 58.180 219.840 58.580 ;
    END
  END Tile_X0Y5_W2END[0]
  PIN Tile_X0Y5_W2END[1]
    DIRECTION INPUT ;
    USE SIGNAL ;
    ANTENNAGATEAREA 0.881400 ;
    PORT
      LAYER Metal3 ;
        RECT 219.440 59.020 219.840 59.420 ;
    END
  END Tile_X0Y5_W2END[1]
  PIN Tile_X0Y5_W2END[2]
    DIRECTION INPUT ;
    USE SIGNAL ;
    ANTENNAGATEAREA 0.852800 ;
    PORT
      LAYER Metal3 ;
        RECT 219.440 59.860 219.840 60.260 ;
    END
  END Tile_X0Y5_W2END[2]
  PIN Tile_X0Y5_W2END[3]
    DIRECTION INPUT ;
    USE SIGNAL ;
    ANTENNAGATEAREA 0.881400 ;
    PORT
      LAYER Metal3 ;
        RECT 219.440 60.700 219.840 61.100 ;
    END
  END Tile_X0Y5_W2END[3]
  PIN Tile_X0Y5_W2END[4]
    DIRECTION INPUT ;
    USE SIGNAL ;
    ANTENNAGATEAREA 0.881400 ;
    PORT
      LAYER Metal3 ;
        RECT 219.440 61.540 219.840 61.940 ;
    END
  END Tile_X0Y5_W2END[4]
  PIN Tile_X0Y5_W2END[5]
    DIRECTION INPUT ;
    USE SIGNAL ;
    ANTENNAGATEAREA 0.881400 ;
    PORT
      LAYER Metal3 ;
        RECT 219.440 62.380 219.840 62.780 ;
    END
  END Tile_X0Y5_W2END[5]
  PIN Tile_X0Y5_W2END[6]
    DIRECTION INPUT ;
    USE SIGNAL ;
    ANTENNAGATEAREA 0.881400 ;
    PORT
      LAYER Metal3 ;
        RECT 219.440 63.220 219.840 63.620 ;
    END
  END Tile_X0Y5_W2END[6]
  PIN Tile_X0Y5_W2END[7]
    DIRECTION INPUT ;
    USE SIGNAL ;
    ANTENNAGATEAREA 0.881400 ;
    PORT
      LAYER Metal3 ;
        RECT 219.440 64.060 219.840 64.460 ;
    END
  END Tile_X0Y5_W2END[7]
  PIN Tile_X0Y5_W2MID[0]
    DIRECTION INPUT ;
    USE SIGNAL ;
    ANTENNAGATEAREA 0.852800 ;
    PORT
      LAYER Metal3 ;
        RECT 219.440 51.460 219.840 51.860 ;
    END
  END Tile_X0Y5_W2MID[0]
  PIN Tile_X0Y5_W2MID[1]
    DIRECTION INPUT ;
    USE SIGNAL ;
    ANTENNAGATEAREA 0.881400 ;
    PORT
      LAYER Metal3 ;
        RECT 219.440 52.300 219.840 52.700 ;
    END
  END Tile_X0Y5_W2MID[1]
  PIN Tile_X0Y5_W2MID[2]
    DIRECTION INPUT ;
    USE SIGNAL ;
    ANTENNAGATEAREA 0.852800 ;
    PORT
      LAYER Metal3 ;
        RECT 219.440 53.140 219.840 53.540 ;
    END
  END Tile_X0Y5_W2MID[2]
  PIN Tile_X0Y5_W2MID[3]
    DIRECTION INPUT ;
    USE SIGNAL ;
    ANTENNAGATEAREA 0.881400 ;
    PORT
      LAYER Metal3 ;
        RECT 219.440 53.980 219.840 54.380 ;
    END
  END Tile_X0Y5_W2MID[3]
  PIN Tile_X0Y5_W2MID[4]
    DIRECTION INPUT ;
    USE SIGNAL ;
    ANTENNAGATEAREA 0.881400 ;
    PORT
      LAYER Metal3 ;
        RECT 219.440 54.820 219.840 55.220 ;
    END
  END Tile_X0Y5_W2MID[4]
  PIN Tile_X0Y5_W2MID[5]
    DIRECTION INPUT ;
    USE SIGNAL ;
    ANTENNAGATEAREA 0.881400 ;
    PORT
      LAYER Metal3 ;
        RECT 219.440 55.660 219.840 56.060 ;
    END
  END Tile_X0Y5_W2MID[5]
  PIN Tile_X0Y5_W2MID[6]
    DIRECTION INPUT ;
    USE SIGNAL ;
    ANTENNAGATEAREA 0.881400 ;
    PORT
      LAYER Metal3 ;
        RECT 219.440 56.500 219.840 56.900 ;
    END
  END Tile_X0Y5_W2MID[6]
  PIN Tile_X0Y5_W2MID[7]
    DIRECTION INPUT ;
    USE SIGNAL ;
    ANTENNAGATEAREA 0.881400 ;
    PORT
      LAYER Metal3 ;
        RECT 219.440 57.340 219.840 57.740 ;
    END
  END Tile_X0Y5_W2MID[7]
  PIN Tile_X0Y5_W6END[0]
    DIRECTION INPUT ;
    USE SIGNAL ;
    ANTENNAGATEAREA 0.881400 ;
    PORT
      LAYER Metal3 ;
        RECT 219.440 78.340 219.840 78.740 ;
    END
  END Tile_X0Y5_W6END[0]
  PIN Tile_X0Y5_W6END[10]
    DIRECTION INPUT ;
    USE SIGNAL ;
    ANTENNAGATEAREA 0.918600 ;
    PORT
      LAYER Metal3 ;
        RECT 219.440 86.740 219.840 87.140 ;
    END
  END Tile_X0Y5_W6END[10]
  PIN Tile_X0Y5_W6END[11]
    DIRECTION INPUT ;
    USE SIGNAL ;
    ANTENNAGATEAREA 0.918600 ;
    PORT
      LAYER Metal3 ;
        RECT 219.440 87.580 219.840 87.980 ;
    END
  END Tile_X0Y5_W6END[11]
  PIN Tile_X0Y5_W6END[1]
    DIRECTION INPUT ;
    USE SIGNAL ;
    ANTENNAGATEAREA 0.848900 ;
    PORT
      LAYER Metal3 ;
        RECT 219.440 79.180 219.840 79.580 ;
    END
  END Tile_X0Y5_W6END[1]
  PIN Tile_X0Y5_W6END[2]
    DIRECTION INPUT ;
    USE SIGNAL ;
    ANTENNAGATEAREA 0.881400 ;
    PORT
      LAYER Metal3 ;
        RECT 219.440 80.020 219.840 80.420 ;
    END
  END Tile_X0Y5_W6END[2]
  PIN Tile_X0Y5_W6END[3]
    DIRECTION INPUT ;
    USE SIGNAL ;
    ANTENNAGATEAREA 0.848900 ;
    PORT
      LAYER Metal3 ;
        RECT 219.440 80.860 219.840 81.260 ;
    END
  END Tile_X0Y5_W6END[3]
  PIN Tile_X0Y5_W6END[4]
    DIRECTION INPUT ;
    USE SIGNAL ;
    ANTENNAGATEAREA 1.099300 ;
    PORT
      LAYER Metal3 ;
        RECT 219.440 81.700 219.840 82.100 ;
    END
  END Tile_X0Y5_W6END[4]
  PIN Tile_X0Y5_W6END[5]
    DIRECTION INPUT ;
    USE SIGNAL ;
    ANTENNAGATEAREA 1.099300 ;
    PORT
      LAYER Metal3 ;
        RECT 219.440 82.540 219.840 82.940 ;
    END
  END Tile_X0Y5_W6END[5]
  PIN Tile_X0Y5_W6END[6]
    DIRECTION INPUT ;
    USE SIGNAL ;
    ANTENNAGATEAREA 1.099300 ;
    PORT
      LAYER Metal3 ;
        RECT 219.440 83.380 219.840 83.780 ;
    END
  END Tile_X0Y5_W6END[6]
  PIN Tile_X0Y5_W6END[7]
    DIRECTION INPUT ;
    USE SIGNAL ;
    ANTENNAGATEAREA 1.099300 ;
    PORT
      LAYER Metal3 ;
        RECT 219.440 84.220 219.840 84.620 ;
    END
  END Tile_X0Y5_W6END[7]
  PIN Tile_X0Y5_W6END[8]
    DIRECTION INPUT ;
    USE SIGNAL ;
    ANTENNAGATEAREA 0.918600 ;
    PORT
      LAYER Metal3 ;
        RECT 219.440 85.060 219.840 85.460 ;
    END
  END Tile_X0Y5_W6END[8]
  PIN Tile_X0Y5_W6END[9]
    DIRECTION INPUT ;
    USE SIGNAL ;
    ANTENNAGATEAREA 0.865800 ;
    PORT
      LAYER Metal3 ;
        RECT 219.440 85.900 219.840 86.300 ;
    END
  END Tile_X0Y5_W6END[9]
  PIN Tile_X0Y5_WW4END[0]
    DIRECTION INPUT ;
    USE SIGNAL ;
    ANTENNAGATEAREA 0.865800 ;
    PORT
      LAYER Metal3 ;
        RECT 219.440 64.900 219.840 65.300 ;
    END
  END Tile_X0Y5_WW4END[0]
  PIN Tile_X0Y5_WW4END[10]
    DIRECTION INPUT ;
    USE SIGNAL ;
    ANTENNAGATEAREA 0.639600 ;
    PORT
      LAYER Metal3 ;
        RECT 219.440 73.300 219.840 73.700 ;
    END
  END Tile_X0Y5_WW4END[10]
  PIN Tile_X0Y5_WW4END[11]
    DIRECTION INPUT ;
    USE SIGNAL ;
    ANTENNAGATEAREA 0.639600 ;
    PORT
      LAYER Metal3 ;
        RECT 219.440 74.140 219.840 74.540 ;
    END
  END Tile_X0Y5_WW4END[11]
  PIN Tile_X0Y5_WW4END[12]
    DIRECTION INPUT ;
    USE SIGNAL ;
    ANTENNAGATEAREA 0.865800 ;
    PORT
      LAYER Metal3 ;
        RECT 219.440 74.980 219.840 75.380 ;
    END
  END Tile_X0Y5_WW4END[12]
  PIN Tile_X0Y5_WW4END[13]
    DIRECTION INPUT ;
    USE SIGNAL ;
    ANTENNAGATEAREA 0.865800 ;
    PORT
      LAYER Metal3 ;
        RECT 219.440 75.820 219.840 76.220 ;
    END
  END Tile_X0Y5_WW4END[13]
  PIN Tile_X0Y5_WW4END[14]
    DIRECTION INPUT ;
    USE SIGNAL ;
    ANTENNAGATEAREA 0.865800 ;
    PORT
      LAYER Metal3 ;
        RECT 219.440 76.660 219.840 77.060 ;
    END
  END Tile_X0Y5_WW4END[14]
  PIN Tile_X0Y5_WW4END[15]
    DIRECTION INPUT ;
    USE SIGNAL ;
    ANTENNAGATEAREA 0.865800 ;
    PORT
      LAYER Metal3 ;
        RECT 219.440 77.500 219.840 77.900 ;
    END
  END Tile_X0Y5_WW4END[15]
  PIN Tile_X0Y5_WW4END[1]
    DIRECTION INPUT ;
    USE SIGNAL ;
    ANTENNAGATEAREA 0.865800 ;
    PORT
      LAYER Metal3 ;
        RECT 219.440 65.740 219.840 66.140 ;
    END
  END Tile_X0Y5_WW4END[1]
  PIN Tile_X0Y5_WW4END[2]
    DIRECTION INPUT ;
    USE SIGNAL ;
    ANTENNAGATEAREA 0.865800 ;
    PORT
      LAYER Metal3 ;
        RECT 219.440 66.580 219.840 66.980 ;
    END
  END Tile_X0Y5_WW4END[2]
  PIN Tile_X0Y5_WW4END[3]
    DIRECTION INPUT ;
    USE SIGNAL ;
    ANTENNAGATEAREA 0.865800 ;
    PORT
      LAYER Metal3 ;
        RECT 219.440 67.420 219.840 67.820 ;
    END
  END Tile_X0Y5_WW4END[3]
  PIN Tile_X0Y5_WW4END[4]
    DIRECTION INPUT ;
    USE SIGNAL ;
    ANTENNAGATEAREA 0.639600 ;
    PORT
      LAYER Metal3 ;
        RECT 219.440 68.260 219.840 68.660 ;
    END
  END Tile_X0Y5_WW4END[4]
  PIN Tile_X0Y5_WW4END[5]
    DIRECTION INPUT ;
    USE SIGNAL ;
    ANTENNAGATEAREA 0.639600 ;
    PORT
      LAYER Metal3 ;
        RECT 219.440 69.100 219.840 69.500 ;
    END
  END Tile_X0Y5_WW4END[5]
  PIN Tile_X0Y5_WW4END[6]
    DIRECTION INPUT ;
    USE SIGNAL ;
    ANTENNAGATEAREA 0.639600 ;
    PORT
      LAYER Metal3 ;
        RECT 219.440 69.940 219.840 70.340 ;
    END
  END Tile_X0Y5_WW4END[6]
  PIN Tile_X0Y5_WW4END[7]
    DIRECTION INPUT ;
    USE SIGNAL ;
    ANTENNAGATEAREA 0.639600 ;
    PORT
      LAYER Metal3 ;
        RECT 219.440 70.780 219.840 71.180 ;
    END
  END Tile_X0Y5_WW4END[7]
  PIN Tile_X0Y5_WW4END[8]
    DIRECTION INPUT ;
    USE SIGNAL ;
    ANTENNAGATEAREA 0.639600 ;
    PORT
      LAYER Metal3 ;
        RECT 219.440 71.620 219.840 72.020 ;
    END
  END Tile_X0Y5_WW4END[8]
  PIN Tile_X0Y5_WW4END[9]
    DIRECTION INPUT ;
    USE SIGNAL ;
    ANTENNAGATEAREA 0.639600 ;
    PORT
      LAYER Metal3 ;
        RECT 219.440 72.460 219.840 72.860 ;
    END
  END Tile_X0Y5_WW4END[9]
  PIN VGND
    DIRECTION INOUT ;
    USE GROUND ;
    PORT
      LAYER Metal4 ;
        RECT 21.580 0.000 23.780 1219.240 ;
    END
    PORT
      LAYER Metal4 ;
        RECT 97.180 0.000 99.380 1219.240 ;
    END
    PORT
      LAYER Metal4 ;
        RECT 172.780 0.000 174.980 1219.240 ;
    END
  END VGND
  PIN VPWR
    DIRECTION INOUT ;
    USE POWER ;
    PORT
      LAYER Metal4 ;
        RECT 15.380 0.000 17.580 1219.240 ;
    END
    PORT
      LAYER Metal4 ;
        RECT 90.980 0.000 93.180 1219.240 ;
    END
    PORT
      LAYER Metal4 ;
        RECT 166.580 0.000 168.780 1219.240 ;
    END
  END VPWR
  OBS
      LAYER GatPoly ;
        RECT 2.880 3.630 216.960 1213.530 ;
      LAYER Metal1 ;
        RECT 2.880 3.560 216.960 1213.600 ;
      LAYER Metal2 ;
        RECT 0.375 1218.630 21.190 1218.985 ;
        RECT 22.010 1218.630 23.110 1218.985 ;
        RECT 23.930 1218.630 25.030 1218.985 ;
        RECT 25.850 1218.630 26.950 1218.985 ;
        RECT 27.770 1218.630 28.870 1218.985 ;
        RECT 29.690 1218.630 30.790 1218.985 ;
        RECT 31.610 1218.630 32.710 1218.985 ;
        RECT 33.530 1218.630 34.630 1218.985 ;
        RECT 35.450 1218.630 36.550 1218.985 ;
        RECT 37.370 1218.630 38.470 1218.985 ;
        RECT 39.290 1218.630 40.390 1218.985 ;
        RECT 41.210 1218.630 42.310 1218.985 ;
        RECT 43.130 1218.630 44.230 1218.985 ;
        RECT 45.050 1218.630 46.150 1218.985 ;
        RECT 46.970 1218.630 48.070 1218.985 ;
        RECT 48.890 1218.630 49.990 1218.985 ;
        RECT 50.810 1218.630 51.910 1218.985 ;
        RECT 52.730 1218.630 53.830 1218.985 ;
        RECT 54.650 1218.630 55.750 1218.985 ;
        RECT 56.570 1218.630 57.670 1218.985 ;
        RECT 58.490 1218.630 59.590 1218.985 ;
        RECT 60.410 1218.630 61.510 1218.985 ;
        RECT 62.330 1218.630 63.430 1218.985 ;
        RECT 64.250 1218.630 65.350 1218.985 ;
        RECT 66.170 1218.630 67.270 1218.985 ;
        RECT 68.090 1218.630 69.190 1218.985 ;
        RECT 70.010 1218.630 71.110 1218.985 ;
        RECT 71.930 1218.630 73.030 1218.985 ;
        RECT 73.850 1218.630 74.950 1218.985 ;
        RECT 75.770 1218.630 76.870 1218.985 ;
        RECT 77.690 1218.630 78.790 1218.985 ;
        RECT 79.610 1218.630 80.710 1218.985 ;
        RECT 81.530 1218.630 82.630 1218.985 ;
        RECT 83.450 1218.630 84.550 1218.985 ;
        RECT 85.370 1218.630 86.470 1218.985 ;
        RECT 87.290 1218.630 88.390 1218.985 ;
        RECT 89.210 1218.630 90.310 1218.985 ;
        RECT 91.130 1218.630 92.230 1218.985 ;
        RECT 93.050 1218.630 94.150 1218.985 ;
        RECT 94.970 1218.630 96.070 1218.985 ;
        RECT 96.890 1218.630 97.990 1218.985 ;
        RECT 98.810 1218.630 99.910 1218.985 ;
        RECT 100.730 1218.630 101.830 1218.985 ;
        RECT 102.650 1218.630 103.750 1218.985 ;
        RECT 104.570 1218.630 105.670 1218.985 ;
        RECT 106.490 1218.630 107.590 1218.985 ;
        RECT 108.410 1218.630 109.510 1218.985 ;
        RECT 110.330 1218.630 111.430 1218.985 ;
        RECT 112.250 1218.630 113.350 1218.985 ;
        RECT 114.170 1218.630 115.270 1218.985 ;
        RECT 116.090 1218.630 117.190 1218.985 ;
        RECT 118.010 1218.630 119.110 1218.985 ;
        RECT 119.930 1218.630 121.030 1218.985 ;
        RECT 121.850 1218.630 122.950 1218.985 ;
        RECT 123.770 1218.630 124.870 1218.985 ;
        RECT 125.690 1218.630 126.790 1218.985 ;
        RECT 127.610 1218.630 128.710 1218.985 ;
        RECT 129.530 1218.630 130.630 1218.985 ;
        RECT 131.450 1218.630 132.550 1218.985 ;
        RECT 133.370 1218.630 134.470 1218.985 ;
        RECT 135.290 1218.630 136.390 1218.985 ;
        RECT 137.210 1218.630 138.310 1218.985 ;
        RECT 139.130 1218.630 140.230 1218.985 ;
        RECT 141.050 1218.630 142.150 1218.985 ;
        RECT 142.970 1218.630 144.070 1218.985 ;
        RECT 144.890 1218.630 145.990 1218.985 ;
        RECT 146.810 1218.630 147.910 1218.985 ;
        RECT 148.730 1218.630 149.830 1218.985 ;
        RECT 150.650 1218.630 151.750 1218.985 ;
        RECT 152.570 1218.630 153.670 1218.985 ;
        RECT 154.490 1218.630 155.590 1218.985 ;
        RECT 156.410 1218.630 157.510 1218.985 ;
        RECT 158.330 1218.630 159.430 1218.985 ;
        RECT 160.250 1218.630 161.350 1218.985 ;
        RECT 162.170 1218.630 163.270 1218.985 ;
        RECT 164.090 1218.630 165.190 1218.985 ;
        RECT 166.010 1218.630 167.110 1218.985 ;
        RECT 167.930 1218.630 169.030 1218.985 ;
        RECT 169.850 1218.630 170.950 1218.985 ;
        RECT 171.770 1218.630 172.870 1218.985 ;
        RECT 173.690 1218.630 174.790 1218.985 ;
        RECT 175.610 1218.630 176.710 1218.985 ;
        RECT 177.530 1218.630 178.630 1218.985 ;
        RECT 179.450 1218.630 180.550 1218.985 ;
        RECT 181.370 1218.630 182.470 1218.985 ;
        RECT 183.290 1218.630 184.390 1218.985 ;
        RECT 185.210 1218.630 186.310 1218.985 ;
        RECT 187.130 1218.630 188.230 1218.985 ;
        RECT 189.050 1218.630 190.150 1218.985 ;
        RECT 190.970 1218.630 192.070 1218.985 ;
        RECT 192.890 1218.630 193.990 1218.985 ;
        RECT 194.810 1218.630 195.910 1218.985 ;
        RECT 196.730 1218.630 197.830 1218.985 ;
        RECT 198.650 1218.630 219.465 1218.985 ;
        RECT 0.375 0.610 219.465 1218.630 ;
        RECT 0.375 0.275 21.190 0.610 ;
        RECT 22.010 0.275 23.110 0.610 ;
        RECT 23.930 0.275 25.030 0.610 ;
        RECT 25.850 0.275 26.950 0.610 ;
        RECT 27.770 0.275 28.870 0.610 ;
        RECT 29.690 0.275 30.790 0.610 ;
        RECT 31.610 0.275 32.710 0.610 ;
        RECT 33.530 0.275 34.630 0.610 ;
        RECT 35.450 0.275 36.550 0.610 ;
        RECT 37.370 0.275 38.470 0.610 ;
        RECT 39.290 0.275 40.390 0.610 ;
        RECT 41.210 0.275 42.310 0.610 ;
        RECT 43.130 0.275 44.230 0.610 ;
        RECT 45.050 0.275 46.150 0.610 ;
        RECT 46.970 0.275 48.070 0.610 ;
        RECT 48.890 0.275 49.990 0.610 ;
        RECT 50.810 0.275 51.910 0.610 ;
        RECT 52.730 0.275 53.830 0.610 ;
        RECT 54.650 0.275 55.750 0.610 ;
        RECT 56.570 0.275 57.670 0.610 ;
        RECT 58.490 0.275 59.590 0.610 ;
        RECT 60.410 0.275 61.510 0.610 ;
        RECT 62.330 0.275 63.430 0.610 ;
        RECT 64.250 0.275 65.350 0.610 ;
        RECT 66.170 0.275 67.270 0.610 ;
        RECT 68.090 0.275 69.190 0.610 ;
        RECT 70.010 0.275 71.110 0.610 ;
        RECT 71.930 0.275 73.030 0.610 ;
        RECT 73.850 0.275 74.950 0.610 ;
        RECT 75.770 0.275 76.870 0.610 ;
        RECT 77.690 0.275 78.790 0.610 ;
        RECT 79.610 0.275 80.710 0.610 ;
        RECT 81.530 0.275 82.630 0.610 ;
        RECT 83.450 0.275 84.550 0.610 ;
        RECT 85.370 0.275 86.470 0.610 ;
        RECT 87.290 0.275 88.390 0.610 ;
        RECT 89.210 0.275 90.310 0.610 ;
        RECT 91.130 0.275 92.230 0.610 ;
        RECT 93.050 0.275 94.150 0.610 ;
        RECT 94.970 0.275 96.070 0.610 ;
        RECT 96.890 0.275 97.990 0.610 ;
        RECT 98.810 0.275 99.910 0.610 ;
        RECT 100.730 0.275 101.830 0.610 ;
        RECT 102.650 0.275 103.750 0.610 ;
        RECT 104.570 0.275 105.670 0.610 ;
        RECT 106.490 0.275 107.590 0.610 ;
        RECT 108.410 0.275 109.510 0.610 ;
        RECT 110.330 0.275 111.430 0.610 ;
        RECT 112.250 0.275 113.350 0.610 ;
        RECT 114.170 0.275 115.270 0.610 ;
        RECT 116.090 0.275 117.190 0.610 ;
        RECT 118.010 0.275 119.110 0.610 ;
        RECT 119.930 0.275 121.030 0.610 ;
        RECT 121.850 0.275 122.950 0.610 ;
        RECT 123.770 0.275 124.870 0.610 ;
        RECT 125.690 0.275 126.790 0.610 ;
        RECT 127.610 0.275 128.710 0.610 ;
        RECT 129.530 0.275 130.630 0.610 ;
        RECT 131.450 0.275 132.550 0.610 ;
        RECT 133.370 0.275 134.470 0.610 ;
        RECT 135.290 0.275 136.390 0.610 ;
        RECT 137.210 0.275 138.310 0.610 ;
        RECT 139.130 0.275 140.230 0.610 ;
        RECT 141.050 0.275 142.150 0.610 ;
        RECT 142.970 0.275 144.070 0.610 ;
        RECT 144.890 0.275 145.990 0.610 ;
        RECT 146.810 0.275 147.910 0.610 ;
        RECT 148.730 0.275 149.830 0.610 ;
        RECT 150.650 0.275 151.750 0.610 ;
        RECT 152.570 0.275 153.670 0.610 ;
        RECT 154.490 0.275 155.590 0.610 ;
        RECT 156.410 0.275 157.510 0.610 ;
        RECT 158.330 0.275 159.430 0.610 ;
        RECT 160.250 0.275 161.350 0.610 ;
        RECT 162.170 0.275 163.270 0.610 ;
        RECT 164.090 0.275 165.190 0.610 ;
        RECT 166.010 0.275 167.110 0.610 ;
        RECT 167.930 0.275 169.030 0.610 ;
        RECT 169.850 0.275 170.950 0.610 ;
        RECT 171.770 0.275 172.870 0.610 ;
        RECT 173.690 0.275 174.790 0.610 ;
        RECT 175.610 0.275 176.710 0.610 ;
        RECT 177.530 0.275 178.630 0.610 ;
        RECT 179.450 0.275 180.550 0.610 ;
        RECT 181.370 0.275 182.470 0.610 ;
        RECT 183.290 0.275 184.390 0.610 ;
        RECT 185.210 0.275 186.310 0.610 ;
        RECT 187.130 0.275 188.230 0.610 ;
        RECT 189.050 0.275 190.150 0.610 ;
        RECT 190.970 0.275 192.070 0.610 ;
        RECT 192.890 0.275 193.990 0.610 ;
        RECT 194.810 0.275 195.910 0.610 ;
        RECT 196.730 0.275 197.830 0.610 ;
        RECT 198.650 0.275 219.465 0.610 ;
      LAYER Metal3 ;
        RECT 0.100 1210.430 219.505 1218.940 ;
        RECT 0.610 1209.610 219.505 1210.430 ;
        RECT 0.100 1205.390 219.505 1209.610 ;
        RECT 0.610 1204.570 219.505 1205.390 ;
        RECT 0.100 1200.350 219.505 1204.570 ;
        RECT 0.610 1199.530 219.505 1200.350 ;
        RECT 0.100 1195.310 219.505 1199.530 ;
        RECT 0.610 1194.490 219.505 1195.310 ;
        RECT 0.100 1190.270 219.505 1194.490 ;
        RECT 0.610 1189.450 219.505 1190.270 ;
        RECT 0.100 1185.230 219.505 1189.450 ;
        RECT 0.610 1184.410 219.505 1185.230 ;
        RECT 0.100 1180.190 219.505 1184.410 ;
        RECT 0.610 1179.370 219.505 1180.190 ;
        RECT 0.100 1175.150 219.505 1179.370 ;
        RECT 0.610 1174.330 219.505 1175.150 ;
        RECT 0.100 1171.370 219.505 1174.330 ;
        RECT 0.100 1170.550 219.230 1171.370 ;
        RECT 0.100 1170.530 219.505 1170.550 ;
        RECT 0.100 1170.110 219.230 1170.530 ;
        RECT 0.610 1169.710 219.230 1170.110 ;
        RECT 0.610 1169.690 219.505 1169.710 ;
        RECT 0.610 1169.290 219.230 1169.690 ;
        RECT 0.100 1168.870 219.230 1169.290 ;
        RECT 0.100 1168.850 219.505 1168.870 ;
        RECT 0.100 1168.030 219.230 1168.850 ;
        RECT 0.100 1168.010 219.505 1168.030 ;
        RECT 0.100 1167.190 219.230 1168.010 ;
        RECT 0.100 1167.170 219.505 1167.190 ;
        RECT 0.100 1166.350 219.230 1167.170 ;
        RECT 0.100 1166.330 219.505 1166.350 ;
        RECT 0.100 1165.510 219.230 1166.330 ;
        RECT 0.100 1165.490 219.505 1165.510 ;
        RECT 0.100 1165.070 219.230 1165.490 ;
        RECT 0.610 1164.670 219.230 1165.070 ;
        RECT 0.610 1164.650 219.505 1164.670 ;
        RECT 0.610 1164.250 219.230 1164.650 ;
        RECT 0.100 1163.830 219.230 1164.250 ;
        RECT 0.100 1163.810 219.505 1163.830 ;
        RECT 0.100 1162.990 219.230 1163.810 ;
        RECT 0.100 1162.970 219.505 1162.990 ;
        RECT 0.100 1162.150 219.230 1162.970 ;
        RECT 0.100 1162.130 219.505 1162.150 ;
        RECT 0.100 1161.310 219.230 1162.130 ;
        RECT 0.100 1161.290 219.505 1161.310 ;
        RECT 0.100 1160.470 219.230 1161.290 ;
        RECT 0.100 1160.450 219.505 1160.470 ;
        RECT 0.100 1160.030 219.230 1160.450 ;
        RECT 0.610 1159.630 219.230 1160.030 ;
        RECT 0.610 1159.610 219.505 1159.630 ;
        RECT 0.610 1159.210 219.230 1159.610 ;
        RECT 0.100 1158.790 219.230 1159.210 ;
        RECT 0.100 1158.770 219.505 1158.790 ;
        RECT 0.100 1157.950 219.230 1158.770 ;
        RECT 0.100 1157.930 219.505 1157.950 ;
        RECT 0.100 1157.110 219.230 1157.930 ;
        RECT 0.100 1157.090 219.505 1157.110 ;
        RECT 0.100 1156.270 219.230 1157.090 ;
        RECT 0.100 1156.250 219.505 1156.270 ;
        RECT 0.100 1155.430 219.230 1156.250 ;
        RECT 0.100 1155.410 219.505 1155.430 ;
        RECT 0.100 1154.990 219.230 1155.410 ;
        RECT 0.610 1154.590 219.230 1154.990 ;
        RECT 0.610 1154.570 219.505 1154.590 ;
        RECT 0.610 1154.170 219.230 1154.570 ;
        RECT 0.100 1153.750 219.230 1154.170 ;
        RECT 0.100 1153.730 219.505 1153.750 ;
        RECT 0.100 1152.910 219.230 1153.730 ;
        RECT 0.100 1152.890 219.505 1152.910 ;
        RECT 0.100 1152.070 219.230 1152.890 ;
        RECT 0.100 1152.050 219.505 1152.070 ;
        RECT 0.100 1151.230 219.230 1152.050 ;
        RECT 0.100 1151.210 219.505 1151.230 ;
        RECT 0.100 1150.390 219.230 1151.210 ;
        RECT 0.100 1150.370 219.505 1150.390 ;
        RECT 0.100 1149.950 219.230 1150.370 ;
        RECT 0.610 1149.550 219.230 1149.950 ;
        RECT 0.610 1149.530 219.505 1149.550 ;
        RECT 0.610 1149.130 219.230 1149.530 ;
        RECT 0.100 1148.710 219.230 1149.130 ;
        RECT 0.100 1148.690 219.505 1148.710 ;
        RECT 0.100 1147.870 219.230 1148.690 ;
        RECT 0.100 1147.850 219.505 1147.870 ;
        RECT 0.100 1147.030 219.230 1147.850 ;
        RECT 0.100 1147.010 219.505 1147.030 ;
        RECT 0.100 1146.190 219.230 1147.010 ;
        RECT 0.100 1146.170 219.505 1146.190 ;
        RECT 0.100 1145.350 219.230 1146.170 ;
        RECT 0.100 1145.330 219.505 1145.350 ;
        RECT 0.100 1144.910 219.230 1145.330 ;
        RECT 0.610 1144.510 219.230 1144.910 ;
        RECT 0.610 1144.490 219.505 1144.510 ;
        RECT 0.610 1144.090 219.230 1144.490 ;
        RECT 0.100 1143.670 219.230 1144.090 ;
        RECT 0.100 1143.650 219.505 1143.670 ;
        RECT 0.100 1142.830 219.230 1143.650 ;
        RECT 0.100 1142.810 219.505 1142.830 ;
        RECT 0.100 1141.990 219.230 1142.810 ;
        RECT 0.100 1141.970 219.505 1141.990 ;
        RECT 0.100 1141.150 219.230 1141.970 ;
        RECT 0.100 1141.130 219.505 1141.150 ;
        RECT 0.100 1140.310 219.230 1141.130 ;
        RECT 0.100 1140.290 219.505 1140.310 ;
        RECT 0.100 1139.870 219.230 1140.290 ;
        RECT 0.610 1139.470 219.230 1139.870 ;
        RECT 0.610 1139.450 219.505 1139.470 ;
        RECT 0.610 1139.050 219.230 1139.450 ;
        RECT 0.100 1138.630 219.230 1139.050 ;
        RECT 0.100 1138.610 219.505 1138.630 ;
        RECT 0.100 1137.790 219.230 1138.610 ;
        RECT 0.100 1137.770 219.505 1137.790 ;
        RECT 0.100 1136.950 219.230 1137.770 ;
        RECT 0.100 1136.930 219.505 1136.950 ;
        RECT 0.100 1136.110 219.230 1136.930 ;
        RECT 0.100 1136.090 219.505 1136.110 ;
        RECT 0.100 1135.270 219.230 1136.090 ;
        RECT 0.100 1135.250 219.505 1135.270 ;
        RECT 0.100 1134.830 219.230 1135.250 ;
        RECT 0.610 1134.430 219.230 1134.830 ;
        RECT 0.610 1134.410 219.505 1134.430 ;
        RECT 0.610 1134.010 219.230 1134.410 ;
        RECT 0.100 1133.590 219.230 1134.010 ;
        RECT 0.100 1133.570 219.505 1133.590 ;
        RECT 0.100 1132.750 219.230 1133.570 ;
        RECT 0.100 1132.730 219.505 1132.750 ;
        RECT 0.100 1131.910 219.230 1132.730 ;
        RECT 0.100 1131.890 219.505 1131.910 ;
        RECT 0.100 1131.070 219.230 1131.890 ;
        RECT 0.100 1131.050 219.505 1131.070 ;
        RECT 0.100 1130.230 219.230 1131.050 ;
        RECT 0.100 1130.210 219.505 1130.230 ;
        RECT 0.100 1129.790 219.230 1130.210 ;
        RECT 0.610 1129.390 219.230 1129.790 ;
        RECT 0.610 1129.370 219.505 1129.390 ;
        RECT 0.610 1128.970 219.230 1129.370 ;
        RECT 0.100 1128.550 219.230 1128.970 ;
        RECT 0.100 1128.530 219.505 1128.550 ;
        RECT 0.100 1127.710 219.230 1128.530 ;
        RECT 0.100 1127.690 219.505 1127.710 ;
        RECT 0.100 1126.870 219.230 1127.690 ;
        RECT 0.100 1126.850 219.505 1126.870 ;
        RECT 0.100 1126.030 219.230 1126.850 ;
        RECT 0.100 1126.010 219.505 1126.030 ;
        RECT 0.100 1125.190 219.230 1126.010 ;
        RECT 0.100 1125.170 219.505 1125.190 ;
        RECT 0.100 1124.750 219.230 1125.170 ;
        RECT 0.610 1124.350 219.230 1124.750 ;
        RECT 0.610 1124.330 219.505 1124.350 ;
        RECT 0.610 1123.930 219.230 1124.330 ;
        RECT 0.100 1123.510 219.230 1123.930 ;
        RECT 0.100 1123.490 219.505 1123.510 ;
        RECT 0.100 1122.670 219.230 1123.490 ;
        RECT 0.100 1122.650 219.505 1122.670 ;
        RECT 0.100 1121.830 219.230 1122.650 ;
        RECT 0.100 1121.810 219.505 1121.830 ;
        RECT 0.100 1120.990 219.230 1121.810 ;
        RECT 0.100 1120.970 219.505 1120.990 ;
        RECT 0.100 1120.150 219.230 1120.970 ;
        RECT 0.100 1120.130 219.505 1120.150 ;
        RECT 0.100 1119.710 219.230 1120.130 ;
        RECT 0.610 1119.310 219.230 1119.710 ;
        RECT 0.610 1119.290 219.505 1119.310 ;
        RECT 0.610 1118.890 219.230 1119.290 ;
        RECT 0.100 1118.470 219.230 1118.890 ;
        RECT 0.100 1118.450 219.505 1118.470 ;
        RECT 0.100 1117.630 219.230 1118.450 ;
        RECT 0.100 1117.610 219.505 1117.630 ;
        RECT 0.100 1116.790 219.230 1117.610 ;
        RECT 0.100 1116.770 219.505 1116.790 ;
        RECT 0.100 1115.950 219.230 1116.770 ;
        RECT 0.100 1115.930 219.505 1115.950 ;
        RECT 0.100 1115.110 219.230 1115.930 ;
        RECT 0.100 1115.090 219.505 1115.110 ;
        RECT 0.100 1114.670 219.230 1115.090 ;
        RECT 0.610 1114.270 219.230 1114.670 ;
        RECT 0.610 1114.250 219.505 1114.270 ;
        RECT 0.610 1113.850 219.230 1114.250 ;
        RECT 0.100 1113.430 219.230 1113.850 ;
        RECT 0.100 1113.410 219.505 1113.430 ;
        RECT 0.100 1112.590 219.230 1113.410 ;
        RECT 0.100 1112.570 219.505 1112.590 ;
        RECT 0.100 1111.750 219.230 1112.570 ;
        RECT 0.100 1111.730 219.505 1111.750 ;
        RECT 0.100 1110.910 219.230 1111.730 ;
        RECT 0.100 1110.890 219.505 1110.910 ;
        RECT 0.100 1110.070 219.230 1110.890 ;
        RECT 0.100 1110.050 219.505 1110.070 ;
        RECT 0.100 1109.630 219.230 1110.050 ;
        RECT 0.610 1109.230 219.230 1109.630 ;
        RECT 0.610 1109.210 219.505 1109.230 ;
        RECT 0.610 1108.810 219.230 1109.210 ;
        RECT 0.100 1108.390 219.230 1108.810 ;
        RECT 0.100 1108.370 219.505 1108.390 ;
        RECT 0.100 1107.550 219.230 1108.370 ;
        RECT 0.100 1107.530 219.505 1107.550 ;
        RECT 0.100 1106.710 219.230 1107.530 ;
        RECT 0.100 1106.690 219.505 1106.710 ;
        RECT 0.100 1105.870 219.230 1106.690 ;
        RECT 0.100 1105.850 219.505 1105.870 ;
        RECT 0.100 1105.030 219.230 1105.850 ;
        RECT 0.100 1105.010 219.505 1105.030 ;
        RECT 0.100 1104.590 219.230 1105.010 ;
        RECT 0.610 1104.190 219.230 1104.590 ;
        RECT 0.610 1104.170 219.505 1104.190 ;
        RECT 0.610 1103.770 219.230 1104.170 ;
        RECT 0.100 1103.350 219.230 1103.770 ;
        RECT 0.100 1103.330 219.505 1103.350 ;
        RECT 0.100 1102.510 219.230 1103.330 ;
        RECT 0.100 1102.490 219.505 1102.510 ;
        RECT 0.100 1101.670 219.230 1102.490 ;
        RECT 0.100 1101.650 219.505 1101.670 ;
        RECT 0.100 1100.830 219.230 1101.650 ;
        RECT 0.100 1100.810 219.505 1100.830 ;
        RECT 0.100 1099.990 219.230 1100.810 ;
        RECT 0.100 1099.970 219.505 1099.990 ;
        RECT 0.100 1099.550 219.230 1099.970 ;
        RECT 0.610 1099.150 219.230 1099.550 ;
        RECT 0.610 1099.130 219.505 1099.150 ;
        RECT 0.610 1098.730 219.230 1099.130 ;
        RECT 0.100 1098.310 219.230 1098.730 ;
        RECT 0.100 1098.290 219.505 1098.310 ;
        RECT 0.100 1097.470 219.230 1098.290 ;
        RECT 0.100 1097.450 219.505 1097.470 ;
        RECT 0.100 1096.630 219.230 1097.450 ;
        RECT 0.100 1096.610 219.505 1096.630 ;
        RECT 0.100 1095.790 219.230 1096.610 ;
        RECT 0.100 1095.770 219.505 1095.790 ;
        RECT 0.100 1094.950 219.230 1095.770 ;
        RECT 0.100 1094.930 219.505 1094.950 ;
        RECT 0.100 1094.510 219.230 1094.930 ;
        RECT 0.610 1094.110 219.230 1094.510 ;
        RECT 0.610 1094.090 219.505 1094.110 ;
        RECT 0.610 1093.690 219.230 1094.090 ;
        RECT 0.100 1093.270 219.230 1093.690 ;
        RECT 0.100 1093.250 219.505 1093.270 ;
        RECT 0.100 1092.430 219.230 1093.250 ;
        RECT 0.100 1092.410 219.505 1092.430 ;
        RECT 0.100 1091.590 219.230 1092.410 ;
        RECT 0.100 1091.570 219.505 1091.590 ;
        RECT 0.100 1090.750 219.230 1091.570 ;
        RECT 0.100 1090.730 219.505 1090.750 ;
        RECT 0.100 1089.910 219.230 1090.730 ;
        RECT 0.100 1089.890 219.505 1089.910 ;
        RECT 0.100 1089.470 219.230 1089.890 ;
        RECT 0.610 1089.070 219.230 1089.470 ;
        RECT 0.610 1089.050 219.505 1089.070 ;
        RECT 0.610 1088.650 219.230 1089.050 ;
        RECT 0.100 1088.230 219.230 1088.650 ;
        RECT 0.100 1088.210 219.505 1088.230 ;
        RECT 0.100 1087.390 219.230 1088.210 ;
        RECT 0.100 1087.370 219.505 1087.390 ;
        RECT 0.100 1086.550 219.230 1087.370 ;
        RECT 0.100 1086.530 219.505 1086.550 ;
        RECT 0.100 1085.710 219.230 1086.530 ;
        RECT 0.100 1085.690 219.505 1085.710 ;
        RECT 0.100 1084.870 219.230 1085.690 ;
        RECT 0.100 1084.850 219.505 1084.870 ;
        RECT 0.100 1084.430 219.230 1084.850 ;
        RECT 0.610 1084.030 219.230 1084.430 ;
        RECT 0.610 1084.010 219.505 1084.030 ;
        RECT 0.610 1083.610 219.230 1084.010 ;
        RECT 0.100 1083.190 219.230 1083.610 ;
        RECT 0.100 1083.170 219.505 1083.190 ;
        RECT 0.100 1082.350 219.230 1083.170 ;
        RECT 0.100 1082.330 219.505 1082.350 ;
        RECT 0.100 1081.510 219.230 1082.330 ;
        RECT 0.100 1081.490 219.505 1081.510 ;
        RECT 0.100 1080.670 219.230 1081.490 ;
        RECT 0.100 1080.650 219.505 1080.670 ;
        RECT 0.100 1079.830 219.230 1080.650 ;
        RECT 0.100 1079.810 219.505 1079.830 ;
        RECT 0.100 1079.390 219.230 1079.810 ;
        RECT 0.610 1078.990 219.230 1079.390 ;
        RECT 0.610 1078.970 219.505 1078.990 ;
        RECT 0.610 1078.570 219.230 1078.970 ;
        RECT 0.100 1078.150 219.230 1078.570 ;
        RECT 0.100 1078.130 219.505 1078.150 ;
        RECT 0.100 1077.310 219.230 1078.130 ;
        RECT 0.100 1077.290 219.505 1077.310 ;
        RECT 0.100 1076.470 219.230 1077.290 ;
        RECT 0.100 1076.450 219.505 1076.470 ;
        RECT 0.100 1075.630 219.230 1076.450 ;
        RECT 0.100 1075.610 219.505 1075.630 ;
        RECT 0.100 1074.790 219.230 1075.610 ;
        RECT 0.100 1074.770 219.505 1074.790 ;
        RECT 0.100 1074.350 219.230 1074.770 ;
        RECT 0.610 1073.950 219.230 1074.350 ;
        RECT 0.610 1073.930 219.505 1073.950 ;
        RECT 0.610 1073.530 219.230 1073.930 ;
        RECT 0.100 1073.110 219.230 1073.530 ;
        RECT 0.100 1073.090 219.505 1073.110 ;
        RECT 0.100 1072.270 219.230 1073.090 ;
        RECT 0.100 1072.250 219.505 1072.270 ;
        RECT 0.100 1071.430 219.230 1072.250 ;
        RECT 0.100 1071.410 219.505 1071.430 ;
        RECT 0.100 1070.590 219.230 1071.410 ;
        RECT 0.100 1070.570 219.505 1070.590 ;
        RECT 0.100 1069.750 219.230 1070.570 ;
        RECT 0.100 1069.730 219.505 1069.750 ;
        RECT 0.100 1069.310 219.230 1069.730 ;
        RECT 0.610 1068.910 219.230 1069.310 ;
        RECT 0.610 1068.890 219.505 1068.910 ;
        RECT 0.610 1068.490 219.230 1068.890 ;
        RECT 0.100 1068.070 219.230 1068.490 ;
        RECT 0.100 1068.050 219.505 1068.070 ;
        RECT 0.100 1067.230 219.230 1068.050 ;
        RECT 0.100 1067.210 219.505 1067.230 ;
        RECT 0.100 1066.390 219.230 1067.210 ;
        RECT 0.100 1066.370 219.505 1066.390 ;
        RECT 0.100 1065.550 219.230 1066.370 ;
        RECT 0.100 1065.530 219.505 1065.550 ;
        RECT 0.100 1064.710 219.230 1065.530 ;
        RECT 0.100 1064.690 219.505 1064.710 ;
        RECT 0.100 1064.270 219.230 1064.690 ;
        RECT 0.610 1063.870 219.230 1064.270 ;
        RECT 0.610 1063.450 219.505 1063.870 ;
        RECT 0.100 1059.230 219.505 1063.450 ;
        RECT 0.610 1058.410 219.505 1059.230 ;
        RECT 0.100 1054.190 219.505 1058.410 ;
        RECT 0.610 1053.370 219.505 1054.190 ;
        RECT 0.100 1036.130 219.505 1053.370 ;
        RECT 0.610 1035.310 219.505 1036.130 ;
        RECT 0.100 1031.090 219.505 1035.310 ;
        RECT 0.610 1030.270 219.505 1031.090 ;
        RECT 0.100 1026.050 219.505 1030.270 ;
        RECT 0.610 1025.230 219.505 1026.050 ;
        RECT 0.100 1021.010 219.505 1025.230 ;
        RECT 0.610 1020.190 219.505 1021.010 ;
        RECT 0.100 1015.970 219.505 1020.190 ;
        RECT 0.610 1015.150 219.505 1015.970 ;
        RECT 0.100 1010.930 219.505 1015.150 ;
        RECT 0.610 1010.110 219.505 1010.930 ;
        RECT 0.100 1005.890 219.505 1010.110 ;
        RECT 0.610 1005.070 219.505 1005.890 ;
        RECT 0.100 1000.850 219.505 1005.070 ;
        RECT 0.610 1000.030 219.505 1000.850 ;
        RECT 0.100 995.810 219.505 1000.030 ;
        RECT 0.610 994.990 219.505 995.810 ;
        RECT 0.100 990.770 219.505 994.990 ;
        RECT 0.610 989.950 219.505 990.770 ;
        RECT 0.100 985.730 219.505 989.950 ;
        RECT 0.610 984.910 219.505 985.730 ;
        RECT 0.100 980.690 219.505 984.910 ;
        RECT 0.610 979.870 219.505 980.690 ;
        RECT 0.100 975.650 219.505 979.870 ;
        RECT 0.610 974.830 219.505 975.650 ;
        RECT 0.100 970.610 219.505 974.830 ;
        RECT 0.610 969.790 219.505 970.610 ;
        RECT 0.100 968.090 219.505 969.790 ;
        RECT 0.100 967.270 219.230 968.090 ;
        RECT 0.100 967.250 219.505 967.270 ;
        RECT 0.100 966.430 219.230 967.250 ;
        RECT 0.100 966.410 219.505 966.430 ;
        RECT 0.100 965.590 219.230 966.410 ;
        RECT 0.100 965.570 219.505 965.590 ;
        RECT 0.610 964.750 219.230 965.570 ;
        RECT 0.100 964.730 219.505 964.750 ;
        RECT 0.100 963.910 219.230 964.730 ;
        RECT 0.100 963.890 219.505 963.910 ;
        RECT 0.100 963.070 219.230 963.890 ;
        RECT 0.100 963.050 219.505 963.070 ;
        RECT 0.100 962.230 219.230 963.050 ;
        RECT 0.100 962.210 219.505 962.230 ;
        RECT 0.100 961.390 219.230 962.210 ;
        RECT 0.100 961.370 219.505 961.390 ;
        RECT 0.100 960.550 219.230 961.370 ;
        RECT 0.100 960.530 219.505 960.550 ;
        RECT 0.610 959.710 219.230 960.530 ;
        RECT 0.100 959.690 219.505 959.710 ;
        RECT 0.100 958.870 219.230 959.690 ;
        RECT 0.100 958.850 219.505 958.870 ;
        RECT 0.100 958.030 219.230 958.850 ;
        RECT 0.100 958.010 219.505 958.030 ;
        RECT 0.100 957.190 219.230 958.010 ;
        RECT 0.100 957.170 219.505 957.190 ;
        RECT 0.100 956.350 219.230 957.170 ;
        RECT 0.100 956.330 219.505 956.350 ;
        RECT 0.100 955.510 219.230 956.330 ;
        RECT 0.100 955.490 219.505 955.510 ;
        RECT 0.610 954.670 219.230 955.490 ;
        RECT 0.100 954.650 219.505 954.670 ;
        RECT 0.100 953.830 219.230 954.650 ;
        RECT 0.100 953.810 219.505 953.830 ;
        RECT 0.100 952.990 219.230 953.810 ;
        RECT 0.100 952.970 219.505 952.990 ;
        RECT 0.100 952.150 219.230 952.970 ;
        RECT 0.100 952.130 219.505 952.150 ;
        RECT 0.100 951.310 219.230 952.130 ;
        RECT 0.100 951.290 219.505 951.310 ;
        RECT 0.100 950.470 219.230 951.290 ;
        RECT 0.100 950.450 219.505 950.470 ;
        RECT 0.610 949.630 219.230 950.450 ;
        RECT 0.100 949.610 219.505 949.630 ;
        RECT 0.100 948.790 219.230 949.610 ;
        RECT 0.100 948.770 219.505 948.790 ;
        RECT 0.100 947.950 219.230 948.770 ;
        RECT 0.100 947.930 219.505 947.950 ;
        RECT 0.100 947.110 219.230 947.930 ;
        RECT 0.100 947.090 219.505 947.110 ;
        RECT 0.100 946.270 219.230 947.090 ;
        RECT 0.100 946.250 219.505 946.270 ;
        RECT 0.100 945.430 219.230 946.250 ;
        RECT 0.100 945.410 219.505 945.430 ;
        RECT 0.610 944.590 219.230 945.410 ;
        RECT 0.100 944.570 219.505 944.590 ;
        RECT 0.100 943.750 219.230 944.570 ;
        RECT 0.100 943.730 219.505 943.750 ;
        RECT 0.100 942.910 219.230 943.730 ;
        RECT 0.100 942.890 219.505 942.910 ;
        RECT 0.100 942.070 219.230 942.890 ;
        RECT 0.100 942.050 219.505 942.070 ;
        RECT 0.100 941.230 219.230 942.050 ;
        RECT 0.100 941.210 219.505 941.230 ;
        RECT 0.100 940.390 219.230 941.210 ;
        RECT 0.100 940.370 219.505 940.390 ;
        RECT 0.610 939.550 219.230 940.370 ;
        RECT 0.100 939.530 219.505 939.550 ;
        RECT 0.100 938.710 219.230 939.530 ;
        RECT 0.100 938.690 219.505 938.710 ;
        RECT 0.100 937.870 219.230 938.690 ;
        RECT 0.100 937.850 219.505 937.870 ;
        RECT 0.100 937.030 219.230 937.850 ;
        RECT 0.100 937.010 219.505 937.030 ;
        RECT 0.100 936.190 219.230 937.010 ;
        RECT 0.100 936.170 219.505 936.190 ;
        RECT 0.100 935.350 219.230 936.170 ;
        RECT 0.100 935.330 219.505 935.350 ;
        RECT 0.610 934.510 219.230 935.330 ;
        RECT 0.100 934.490 219.505 934.510 ;
        RECT 0.100 933.670 219.230 934.490 ;
        RECT 0.100 933.650 219.505 933.670 ;
        RECT 0.100 932.830 219.230 933.650 ;
        RECT 0.100 932.810 219.505 932.830 ;
        RECT 0.100 931.990 219.230 932.810 ;
        RECT 0.100 931.970 219.505 931.990 ;
        RECT 0.100 931.150 219.230 931.970 ;
        RECT 0.100 931.130 219.505 931.150 ;
        RECT 0.100 930.310 219.230 931.130 ;
        RECT 0.100 930.290 219.505 930.310 ;
        RECT 0.610 929.470 219.230 930.290 ;
        RECT 0.100 929.450 219.505 929.470 ;
        RECT 0.100 928.630 219.230 929.450 ;
        RECT 0.100 928.610 219.505 928.630 ;
        RECT 0.100 927.790 219.230 928.610 ;
        RECT 0.100 927.770 219.505 927.790 ;
        RECT 0.100 926.950 219.230 927.770 ;
        RECT 0.100 926.930 219.505 926.950 ;
        RECT 0.100 926.110 219.230 926.930 ;
        RECT 0.100 926.090 219.505 926.110 ;
        RECT 0.100 925.270 219.230 926.090 ;
        RECT 0.100 925.250 219.505 925.270 ;
        RECT 0.610 924.430 219.230 925.250 ;
        RECT 0.100 924.410 219.505 924.430 ;
        RECT 0.100 923.590 219.230 924.410 ;
        RECT 0.100 923.570 219.505 923.590 ;
        RECT 0.100 922.750 219.230 923.570 ;
        RECT 0.100 922.730 219.505 922.750 ;
        RECT 0.100 921.910 219.230 922.730 ;
        RECT 0.100 921.890 219.505 921.910 ;
        RECT 0.100 921.070 219.230 921.890 ;
        RECT 0.100 921.050 219.505 921.070 ;
        RECT 0.100 920.230 219.230 921.050 ;
        RECT 0.100 920.210 219.505 920.230 ;
        RECT 0.610 919.390 219.230 920.210 ;
        RECT 0.100 919.370 219.505 919.390 ;
        RECT 0.100 918.550 219.230 919.370 ;
        RECT 0.100 918.530 219.505 918.550 ;
        RECT 0.100 917.710 219.230 918.530 ;
        RECT 0.100 917.690 219.505 917.710 ;
        RECT 0.100 916.870 219.230 917.690 ;
        RECT 0.100 916.850 219.505 916.870 ;
        RECT 0.100 916.030 219.230 916.850 ;
        RECT 0.100 916.010 219.505 916.030 ;
        RECT 0.100 915.190 219.230 916.010 ;
        RECT 0.100 915.170 219.505 915.190 ;
        RECT 0.610 914.350 219.230 915.170 ;
        RECT 0.100 914.330 219.505 914.350 ;
        RECT 0.100 913.510 219.230 914.330 ;
        RECT 0.100 913.490 219.505 913.510 ;
        RECT 0.100 912.670 219.230 913.490 ;
        RECT 0.100 912.650 219.505 912.670 ;
        RECT 0.100 911.830 219.230 912.650 ;
        RECT 0.100 911.810 219.505 911.830 ;
        RECT 0.100 910.990 219.230 911.810 ;
        RECT 0.100 910.970 219.505 910.990 ;
        RECT 0.100 910.150 219.230 910.970 ;
        RECT 0.100 910.130 219.505 910.150 ;
        RECT 0.610 909.310 219.230 910.130 ;
        RECT 0.100 909.290 219.505 909.310 ;
        RECT 0.100 908.470 219.230 909.290 ;
        RECT 0.100 908.450 219.505 908.470 ;
        RECT 0.100 907.630 219.230 908.450 ;
        RECT 0.100 907.610 219.505 907.630 ;
        RECT 0.100 906.790 219.230 907.610 ;
        RECT 0.100 906.770 219.505 906.790 ;
        RECT 0.100 905.950 219.230 906.770 ;
        RECT 0.100 905.930 219.505 905.950 ;
        RECT 0.100 905.110 219.230 905.930 ;
        RECT 0.100 905.090 219.505 905.110 ;
        RECT 0.610 904.270 219.230 905.090 ;
        RECT 0.100 904.250 219.505 904.270 ;
        RECT 0.100 903.430 219.230 904.250 ;
        RECT 0.100 903.410 219.505 903.430 ;
        RECT 0.100 902.590 219.230 903.410 ;
        RECT 0.100 902.570 219.505 902.590 ;
        RECT 0.100 901.750 219.230 902.570 ;
        RECT 0.100 901.730 219.505 901.750 ;
        RECT 0.100 900.910 219.230 901.730 ;
        RECT 0.100 900.890 219.505 900.910 ;
        RECT 0.100 900.070 219.230 900.890 ;
        RECT 0.100 900.050 219.505 900.070 ;
        RECT 0.610 899.230 219.230 900.050 ;
        RECT 0.100 899.210 219.505 899.230 ;
        RECT 0.100 898.390 219.230 899.210 ;
        RECT 0.100 898.370 219.505 898.390 ;
        RECT 0.100 897.550 219.230 898.370 ;
        RECT 0.100 897.530 219.505 897.550 ;
        RECT 0.100 896.710 219.230 897.530 ;
        RECT 0.100 896.690 219.505 896.710 ;
        RECT 0.100 895.870 219.230 896.690 ;
        RECT 0.100 895.850 219.505 895.870 ;
        RECT 0.100 895.030 219.230 895.850 ;
        RECT 0.100 895.010 219.505 895.030 ;
        RECT 0.610 894.190 219.230 895.010 ;
        RECT 0.100 894.170 219.505 894.190 ;
        RECT 0.100 893.350 219.230 894.170 ;
        RECT 0.100 893.330 219.505 893.350 ;
        RECT 0.100 892.510 219.230 893.330 ;
        RECT 0.100 892.490 219.505 892.510 ;
        RECT 0.100 891.670 219.230 892.490 ;
        RECT 0.100 891.650 219.505 891.670 ;
        RECT 0.100 890.830 219.230 891.650 ;
        RECT 0.100 890.810 219.505 890.830 ;
        RECT 0.100 889.990 219.230 890.810 ;
        RECT 0.100 889.970 219.505 889.990 ;
        RECT 0.610 889.150 219.230 889.970 ;
        RECT 0.100 889.130 219.505 889.150 ;
        RECT 0.100 888.310 219.230 889.130 ;
        RECT 0.100 888.290 219.505 888.310 ;
        RECT 0.100 887.470 219.230 888.290 ;
        RECT 0.100 887.450 219.505 887.470 ;
        RECT 0.100 886.630 219.230 887.450 ;
        RECT 0.100 886.610 219.505 886.630 ;
        RECT 0.100 885.790 219.230 886.610 ;
        RECT 0.100 885.770 219.505 885.790 ;
        RECT 0.100 884.950 219.230 885.770 ;
        RECT 0.100 884.930 219.505 884.950 ;
        RECT 0.610 884.110 219.230 884.930 ;
        RECT 0.100 884.090 219.505 884.110 ;
        RECT 0.100 883.270 219.230 884.090 ;
        RECT 0.100 883.250 219.505 883.270 ;
        RECT 0.100 882.430 219.230 883.250 ;
        RECT 0.100 882.410 219.505 882.430 ;
        RECT 0.100 881.590 219.230 882.410 ;
        RECT 0.100 881.570 219.505 881.590 ;
        RECT 0.100 880.750 219.230 881.570 ;
        RECT 0.100 880.730 219.505 880.750 ;
        RECT 0.100 879.910 219.230 880.730 ;
        RECT 0.100 879.890 219.505 879.910 ;
        RECT 0.610 879.070 219.230 879.890 ;
        RECT 0.100 879.050 219.505 879.070 ;
        RECT 0.100 878.230 219.230 879.050 ;
        RECT 0.100 878.210 219.505 878.230 ;
        RECT 0.100 877.390 219.230 878.210 ;
        RECT 0.100 877.370 219.505 877.390 ;
        RECT 0.100 876.550 219.230 877.370 ;
        RECT 0.100 876.530 219.505 876.550 ;
        RECT 0.100 875.710 219.230 876.530 ;
        RECT 0.100 875.690 219.505 875.710 ;
        RECT 0.100 874.870 219.230 875.690 ;
        RECT 0.100 874.850 219.505 874.870 ;
        RECT 0.100 874.030 219.230 874.850 ;
        RECT 0.100 874.010 219.505 874.030 ;
        RECT 0.100 873.190 219.230 874.010 ;
        RECT 0.100 873.170 219.505 873.190 ;
        RECT 0.100 872.350 219.230 873.170 ;
        RECT 0.100 872.330 219.505 872.350 ;
        RECT 0.100 871.510 219.230 872.330 ;
        RECT 0.100 871.490 219.505 871.510 ;
        RECT 0.100 870.670 219.230 871.490 ;
        RECT 0.100 870.650 219.505 870.670 ;
        RECT 0.100 869.830 219.230 870.650 ;
        RECT 0.100 869.810 219.505 869.830 ;
        RECT 0.100 868.990 219.230 869.810 ;
        RECT 0.100 868.970 219.505 868.990 ;
        RECT 0.100 868.150 219.230 868.970 ;
        RECT 0.100 868.130 219.505 868.150 ;
        RECT 0.100 867.310 219.230 868.130 ;
        RECT 0.100 867.290 219.505 867.310 ;
        RECT 0.100 866.470 219.230 867.290 ;
        RECT 0.100 866.450 219.505 866.470 ;
        RECT 0.100 865.630 219.230 866.450 ;
        RECT 0.100 865.610 219.505 865.630 ;
        RECT 0.100 864.790 219.230 865.610 ;
        RECT 0.100 864.770 219.505 864.790 ;
        RECT 0.100 863.950 219.230 864.770 ;
        RECT 0.100 863.930 219.505 863.950 ;
        RECT 0.100 863.110 219.230 863.930 ;
        RECT 0.100 863.090 219.505 863.110 ;
        RECT 0.100 862.270 219.230 863.090 ;
        RECT 0.100 862.250 219.505 862.270 ;
        RECT 0.100 861.830 219.230 862.250 ;
        RECT 0.610 861.430 219.230 861.830 ;
        RECT 0.610 861.410 219.505 861.430 ;
        RECT 0.610 861.010 219.230 861.410 ;
        RECT 0.100 860.590 219.230 861.010 ;
        RECT 0.100 856.790 219.505 860.590 ;
        RECT 0.610 855.970 219.505 856.790 ;
        RECT 0.100 851.750 219.505 855.970 ;
        RECT 0.610 850.930 219.505 851.750 ;
        RECT 0.100 846.710 219.505 850.930 ;
        RECT 0.610 845.890 219.505 846.710 ;
        RECT 0.100 841.670 219.505 845.890 ;
        RECT 0.610 840.850 219.505 841.670 ;
        RECT 0.100 836.630 219.505 840.850 ;
        RECT 0.610 835.810 219.505 836.630 ;
        RECT 0.100 831.590 219.505 835.810 ;
        RECT 0.610 830.770 219.505 831.590 ;
        RECT 0.100 826.550 219.505 830.770 ;
        RECT 0.610 825.730 219.505 826.550 ;
        RECT 0.100 821.510 219.505 825.730 ;
        RECT 0.610 820.690 219.505 821.510 ;
        RECT 0.100 816.470 219.505 820.690 ;
        RECT 0.610 815.650 219.505 816.470 ;
        RECT 0.100 811.430 219.505 815.650 ;
        RECT 0.610 810.610 219.505 811.430 ;
        RECT 0.100 806.390 219.505 810.610 ;
        RECT 0.610 805.570 219.505 806.390 ;
        RECT 0.100 801.350 219.505 805.570 ;
        RECT 0.610 800.530 219.505 801.350 ;
        RECT 0.100 796.310 219.505 800.530 ;
        RECT 0.610 795.490 219.505 796.310 ;
        RECT 0.100 791.270 219.505 795.490 ;
        RECT 0.610 790.450 219.505 791.270 ;
        RECT 0.100 786.230 219.505 790.450 ;
        RECT 0.610 785.410 219.505 786.230 ;
        RECT 0.100 781.190 219.505 785.410 ;
        RECT 0.610 780.370 219.505 781.190 ;
        RECT 0.100 776.150 219.505 780.370 ;
        RECT 0.610 775.330 219.505 776.150 ;
        RECT 0.100 771.110 219.505 775.330 ;
        RECT 0.610 770.290 219.505 771.110 ;
        RECT 0.100 766.070 219.505 770.290 ;
        RECT 0.610 765.250 219.505 766.070 ;
        RECT 0.100 764.810 219.505 765.250 ;
        RECT 0.100 763.990 219.230 764.810 ;
        RECT 0.100 763.970 219.505 763.990 ;
        RECT 0.100 763.150 219.230 763.970 ;
        RECT 0.100 763.130 219.505 763.150 ;
        RECT 0.100 762.310 219.230 763.130 ;
        RECT 0.100 762.290 219.505 762.310 ;
        RECT 0.100 761.470 219.230 762.290 ;
        RECT 0.100 761.450 219.505 761.470 ;
        RECT 0.100 761.030 219.230 761.450 ;
        RECT 0.610 760.630 219.230 761.030 ;
        RECT 0.610 760.610 219.505 760.630 ;
        RECT 0.610 760.210 219.230 760.610 ;
        RECT 0.100 759.790 219.230 760.210 ;
        RECT 0.100 759.770 219.505 759.790 ;
        RECT 0.100 758.950 219.230 759.770 ;
        RECT 0.100 758.930 219.505 758.950 ;
        RECT 0.100 758.110 219.230 758.930 ;
        RECT 0.100 758.090 219.505 758.110 ;
        RECT 0.100 757.270 219.230 758.090 ;
        RECT 0.100 757.250 219.505 757.270 ;
        RECT 0.100 756.430 219.230 757.250 ;
        RECT 0.100 756.410 219.505 756.430 ;
        RECT 0.100 755.990 219.230 756.410 ;
        RECT 0.610 755.590 219.230 755.990 ;
        RECT 0.610 755.570 219.505 755.590 ;
        RECT 0.610 755.170 219.230 755.570 ;
        RECT 0.100 754.750 219.230 755.170 ;
        RECT 0.100 754.730 219.505 754.750 ;
        RECT 0.100 753.910 219.230 754.730 ;
        RECT 0.100 753.890 219.505 753.910 ;
        RECT 0.100 753.070 219.230 753.890 ;
        RECT 0.100 753.050 219.505 753.070 ;
        RECT 0.100 752.230 219.230 753.050 ;
        RECT 0.100 752.210 219.505 752.230 ;
        RECT 0.100 751.390 219.230 752.210 ;
        RECT 0.100 751.370 219.505 751.390 ;
        RECT 0.100 750.950 219.230 751.370 ;
        RECT 0.610 750.550 219.230 750.950 ;
        RECT 0.610 750.530 219.505 750.550 ;
        RECT 0.610 750.130 219.230 750.530 ;
        RECT 0.100 749.710 219.230 750.130 ;
        RECT 0.100 749.690 219.505 749.710 ;
        RECT 0.100 748.870 219.230 749.690 ;
        RECT 0.100 748.850 219.505 748.870 ;
        RECT 0.100 748.030 219.230 748.850 ;
        RECT 0.100 748.010 219.505 748.030 ;
        RECT 0.100 747.190 219.230 748.010 ;
        RECT 0.100 747.170 219.505 747.190 ;
        RECT 0.100 746.350 219.230 747.170 ;
        RECT 0.100 746.330 219.505 746.350 ;
        RECT 0.100 745.910 219.230 746.330 ;
        RECT 0.610 745.510 219.230 745.910 ;
        RECT 0.610 745.490 219.505 745.510 ;
        RECT 0.610 745.090 219.230 745.490 ;
        RECT 0.100 744.670 219.230 745.090 ;
        RECT 0.100 744.650 219.505 744.670 ;
        RECT 0.100 743.830 219.230 744.650 ;
        RECT 0.100 743.810 219.505 743.830 ;
        RECT 0.100 742.990 219.230 743.810 ;
        RECT 0.100 742.970 219.505 742.990 ;
        RECT 0.100 742.150 219.230 742.970 ;
        RECT 0.100 742.130 219.505 742.150 ;
        RECT 0.100 741.310 219.230 742.130 ;
        RECT 0.100 741.290 219.505 741.310 ;
        RECT 0.100 740.870 219.230 741.290 ;
        RECT 0.610 740.470 219.230 740.870 ;
        RECT 0.610 740.450 219.505 740.470 ;
        RECT 0.610 740.050 219.230 740.450 ;
        RECT 0.100 739.630 219.230 740.050 ;
        RECT 0.100 739.610 219.505 739.630 ;
        RECT 0.100 738.790 219.230 739.610 ;
        RECT 0.100 738.770 219.505 738.790 ;
        RECT 0.100 737.950 219.230 738.770 ;
        RECT 0.100 737.930 219.505 737.950 ;
        RECT 0.100 737.110 219.230 737.930 ;
        RECT 0.100 737.090 219.505 737.110 ;
        RECT 0.100 736.270 219.230 737.090 ;
        RECT 0.100 736.250 219.505 736.270 ;
        RECT 0.100 735.830 219.230 736.250 ;
        RECT 0.610 735.430 219.230 735.830 ;
        RECT 0.610 735.410 219.505 735.430 ;
        RECT 0.610 735.010 219.230 735.410 ;
        RECT 0.100 734.590 219.230 735.010 ;
        RECT 0.100 734.570 219.505 734.590 ;
        RECT 0.100 733.750 219.230 734.570 ;
        RECT 0.100 733.730 219.505 733.750 ;
        RECT 0.100 732.910 219.230 733.730 ;
        RECT 0.100 732.890 219.505 732.910 ;
        RECT 0.100 732.070 219.230 732.890 ;
        RECT 0.100 732.050 219.505 732.070 ;
        RECT 0.100 731.230 219.230 732.050 ;
        RECT 0.100 731.210 219.505 731.230 ;
        RECT 0.100 730.790 219.230 731.210 ;
        RECT 0.610 730.390 219.230 730.790 ;
        RECT 0.610 730.370 219.505 730.390 ;
        RECT 0.610 729.970 219.230 730.370 ;
        RECT 0.100 729.550 219.230 729.970 ;
        RECT 0.100 729.530 219.505 729.550 ;
        RECT 0.100 728.710 219.230 729.530 ;
        RECT 0.100 728.690 219.505 728.710 ;
        RECT 0.100 727.870 219.230 728.690 ;
        RECT 0.100 727.850 219.505 727.870 ;
        RECT 0.100 727.030 219.230 727.850 ;
        RECT 0.100 727.010 219.505 727.030 ;
        RECT 0.100 726.190 219.230 727.010 ;
        RECT 0.100 726.170 219.505 726.190 ;
        RECT 0.100 725.750 219.230 726.170 ;
        RECT 0.610 725.350 219.230 725.750 ;
        RECT 0.610 725.330 219.505 725.350 ;
        RECT 0.610 724.930 219.230 725.330 ;
        RECT 0.100 724.510 219.230 724.930 ;
        RECT 0.100 724.490 219.505 724.510 ;
        RECT 0.100 723.670 219.230 724.490 ;
        RECT 0.100 723.650 219.505 723.670 ;
        RECT 0.100 722.830 219.230 723.650 ;
        RECT 0.100 722.810 219.505 722.830 ;
        RECT 0.100 721.990 219.230 722.810 ;
        RECT 0.100 721.970 219.505 721.990 ;
        RECT 0.100 721.150 219.230 721.970 ;
        RECT 0.100 721.130 219.505 721.150 ;
        RECT 0.100 720.710 219.230 721.130 ;
        RECT 0.610 720.310 219.230 720.710 ;
        RECT 0.610 720.290 219.505 720.310 ;
        RECT 0.610 719.890 219.230 720.290 ;
        RECT 0.100 719.470 219.230 719.890 ;
        RECT 0.100 719.450 219.505 719.470 ;
        RECT 0.100 718.630 219.230 719.450 ;
        RECT 0.100 718.610 219.505 718.630 ;
        RECT 0.100 717.790 219.230 718.610 ;
        RECT 0.100 717.770 219.505 717.790 ;
        RECT 0.100 716.950 219.230 717.770 ;
        RECT 0.100 716.930 219.505 716.950 ;
        RECT 0.100 716.110 219.230 716.930 ;
        RECT 0.100 716.090 219.505 716.110 ;
        RECT 0.100 715.670 219.230 716.090 ;
        RECT 0.610 715.270 219.230 715.670 ;
        RECT 0.610 715.250 219.505 715.270 ;
        RECT 0.610 714.850 219.230 715.250 ;
        RECT 0.100 714.430 219.230 714.850 ;
        RECT 0.100 714.410 219.505 714.430 ;
        RECT 0.100 713.590 219.230 714.410 ;
        RECT 0.100 713.570 219.505 713.590 ;
        RECT 0.100 712.750 219.230 713.570 ;
        RECT 0.100 712.730 219.505 712.750 ;
        RECT 0.100 711.910 219.230 712.730 ;
        RECT 0.100 711.890 219.505 711.910 ;
        RECT 0.100 711.070 219.230 711.890 ;
        RECT 0.100 711.050 219.505 711.070 ;
        RECT 0.100 710.630 219.230 711.050 ;
        RECT 0.610 710.230 219.230 710.630 ;
        RECT 0.610 710.210 219.505 710.230 ;
        RECT 0.610 709.810 219.230 710.210 ;
        RECT 0.100 709.390 219.230 709.810 ;
        RECT 0.100 709.370 219.505 709.390 ;
        RECT 0.100 708.550 219.230 709.370 ;
        RECT 0.100 708.530 219.505 708.550 ;
        RECT 0.100 707.710 219.230 708.530 ;
        RECT 0.100 707.690 219.505 707.710 ;
        RECT 0.100 706.870 219.230 707.690 ;
        RECT 0.100 706.850 219.505 706.870 ;
        RECT 0.100 706.030 219.230 706.850 ;
        RECT 0.100 706.010 219.505 706.030 ;
        RECT 0.100 705.590 219.230 706.010 ;
        RECT 0.610 705.190 219.230 705.590 ;
        RECT 0.610 705.170 219.505 705.190 ;
        RECT 0.610 704.770 219.230 705.170 ;
        RECT 0.100 704.350 219.230 704.770 ;
        RECT 0.100 704.330 219.505 704.350 ;
        RECT 0.100 703.510 219.230 704.330 ;
        RECT 0.100 703.490 219.505 703.510 ;
        RECT 0.100 702.670 219.230 703.490 ;
        RECT 0.100 702.650 219.505 702.670 ;
        RECT 0.100 701.830 219.230 702.650 ;
        RECT 0.100 701.810 219.505 701.830 ;
        RECT 0.100 700.990 219.230 701.810 ;
        RECT 0.100 700.970 219.505 700.990 ;
        RECT 0.100 700.150 219.230 700.970 ;
        RECT 0.100 700.130 219.505 700.150 ;
        RECT 0.100 699.310 219.230 700.130 ;
        RECT 0.100 699.290 219.505 699.310 ;
        RECT 0.100 698.470 219.230 699.290 ;
        RECT 0.100 698.450 219.505 698.470 ;
        RECT 0.100 697.630 219.230 698.450 ;
        RECT 0.100 697.610 219.505 697.630 ;
        RECT 0.100 696.790 219.230 697.610 ;
        RECT 0.100 696.770 219.505 696.790 ;
        RECT 0.100 695.950 219.230 696.770 ;
        RECT 0.100 695.930 219.505 695.950 ;
        RECT 0.100 695.110 219.230 695.930 ;
        RECT 0.100 695.090 219.505 695.110 ;
        RECT 0.100 694.270 219.230 695.090 ;
        RECT 0.100 694.250 219.505 694.270 ;
        RECT 0.100 693.430 219.230 694.250 ;
        RECT 0.100 693.410 219.505 693.430 ;
        RECT 0.100 692.590 219.230 693.410 ;
        RECT 0.100 692.570 219.505 692.590 ;
        RECT 0.100 691.750 219.230 692.570 ;
        RECT 0.100 691.730 219.505 691.750 ;
        RECT 0.100 690.910 219.230 691.730 ;
        RECT 0.100 690.890 219.505 690.910 ;
        RECT 0.100 690.070 219.230 690.890 ;
        RECT 0.100 690.050 219.505 690.070 ;
        RECT 0.100 689.230 219.230 690.050 ;
        RECT 0.100 689.210 219.505 689.230 ;
        RECT 0.100 688.390 219.230 689.210 ;
        RECT 0.100 688.370 219.505 688.390 ;
        RECT 0.100 687.950 219.230 688.370 ;
        RECT 0.610 687.550 219.230 687.950 ;
        RECT 0.610 687.530 219.505 687.550 ;
        RECT 0.610 687.130 219.230 687.530 ;
        RECT 0.100 686.710 219.230 687.130 ;
        RECT 0.100 686.690 219.505 686.710 ;
        RECT 0.100 685.870 219.230 686.690 ;
        RECT 0.100 685.850 219.505 685.870 ;
        RECT 0.100 685.030 219.230 685.850 ;
        RECT 0.100 685.010 219.505 685.030 ;
        RECT 0.100 684.190 219.230 685.010 ;
        RECT 0.100 684.170 219.505 684.190 ;
        RECT 0.100 683.350 219.230 684.170 ;
        RECT 0.100 683.330 219.505 683.350 ;
        RECT 0.100 682.910 219.230 683.330 ;
        RECT 0.610 682.510 219.230 682.910 ;
        RECT 0.610 682.490 219.505 682.510 ;
        RECT 0.610 682.090 219.230 682.490 ;
        RECT 0.100 681.670 219.230 682.090 ;
        RECT 0.100 681.650 219.505 681.670 ;
        RECT 0.100 680.830 219.230 681.650 ;
        RECT 0.100 680.810 219.505 680.830 ;
        RECT 0.100 679.990 219.230 680.810 ;
        RECT 0.100 679.970 219.505 679.990 ;
        RECT 0.100 679.150 219.230 679.970 ;
        RECT 0.100 679.130 219.505 679.150 ;
        RECT 0.100 678.310 219.230 679.130 ;
        RECT 0.100 678.290 219.505 678.310 ;
        RECT 0.100 677.870 219.230 678.290 ;
        RECT 0.610 677.470 219.230 677.870 ;
        RECT 0.610 677.450 219.505 677.470 ;
        RECT 0.610 677.050 219.230 677.450 ;
        RECT 0.100 676.630 219.230 677.050 ;
        RECT 0.100 676.610 219.505 676.630 ;
        RECT 0.100 675.790 219.230 676.610 ;
        RECT 0.100 675.770 219.505 675.790 ;
        RECT 0.100 674.950 219.230 675.770 ;
        RECT 0.100 674.930 219.505 674.950 ;
        RECT 0.100 674.110 219.230 674.930 ;
        RECT 0.100 674.090 219.505 674.110 ;
        RECT 0.100 673.270 219.230 674.090 ;
        RECT 0.100 673.250 219.505 673.270 ;
        RECT 0.100 672.830 219.230 673.250 ;
        RECT 0.610 672.430 219.230 672.830 ;
        RECT 0.610 672.410 219.505 672.430 ;
        RECT 0.610 672.010 219.230 672.410 ;
        RECT 0.100 671.590 219.230 672.010 ;
        RECT 0.100 671.570 219.505 671.590 ;
        RECT 0.100 670.750 219.230 671.570 ;
        RECT 0.100 670.730 219.505 670.750 ;
        RECT 0.100 669.910 219.230 670.730 ;
        RECT 0.100 669.890 219.505 669.910 ;
        RECT 0.100 669.070 219.230 669.890 ;
        RECT 0.100 669.050 219.505 669.070 ;
        RECT 0.100 668.230 219.230 669.050 ;
        RECT 0.100 668.210 219.505 668.230 ;
        RECT 0.100 667.790 219.230 668.210 ;
        RECT 0.610 667.390 219.230 667.790 ;
        RECT 0.610 667.370 219.505 667.390 ;
        RECT 0.610 666.970 219.230 667.370 ;
        RECT 0.100 666.550 219.230 666.970 ;
        RECT 0.100 666.530 219.505 666.550 ;
        RECT 0.100 665.710 219.230 666.530 ;
        RECT 0.100 665.690 219.505 665.710 ;
        RECT 0.100 664.870 219.230 665.690 ;
        RECT 0.100 664.850 219.505 664.870 ;
        RECT 0.100 664.030 219.230 664.850 ;
        RECT 0.100 664.010 219.505 664.030 ;
        RECT 0.100 663.190 219.230 664.010 ;
        RECT 0.100 663.170 219.505 663.190 ;
        RECT 0.100 662.750 219.230 663.170 ;
        RECT 0.610 662.350 219.230 662.750 ;
        RECT 0.610 662.330 219.505 662.350 ;
        RECT 0.610 661.930 219.230 662.330 ;
        RECT 0.100 661.510 219.230 661.930 ;
        RECT 0.100 661.490 219.505 661.510 ;
        RECT 0.100 660.670 219.230 661.490 ;
        RECT 0.100 660.650 219.505 660.670 ;
        RECT 0.100 659.830 219.230 660.650 ;
        RECT 0.100 659.810 219.505 659.830 ;
        RECT 0.100 658.990 219.230 659.810 ;
        RECT 0.100 658.970 219.505 658.990 ;
        RECT 0.100 658.150 219.230 658.970 ;
        RECT 0.100 658.130 219.505 658.150 ;
        RECT 0.100 657.710 219.230 658.130 ;
        RECT 0.610 657.310 219.230 657.710 ;
        RECT 0.610 656.890 219.505 657.310 ;
        RECT 0.100 652.670 219.505 656.890 ;
        RECT 0.610 651.850 219.505 652.670 ;
        RECT 0.100 647.630 219.505 651.850 ;
        RECT 0.610 646.810 219.505 647.630 ;
        RECT 0.100 642.590 219.505 646.810 ;
        RECT 0.610 641.770 219.505 642.590 ;
        RECT 0.100 637.550 219.505 641.770 ;
        RECT 0.610 636.730 219.505 637.550 ;
        RECT 0.100 632.510 219.505 636.730 ;
        RECT 0.610 631.690 219.505 632.510 ;
        RECT 0.100 627.470 219.505 631.690 ;
        RECT 0.610 626.650 219.505 627.470 ;
        RECT 0.100 622.430 219.505 626.650 ;
        RECT 0.610 621.610 219.505 622.430 ;
        RECT 0.100 617.390 219.505 621.610 ;
        RECT 0.610 616.570 219.505 617.390 ;
        RECT 0.100 612.350 219.505 616.570 ;
        RECT 0.610 611.530 219.505 612.350 ;
        RECT 0.100 607.310 219.505 611.530 ;
        RECT 0.610 606.490 219.505 607.310 ;
        RECT 0.100 602.270 219.505 606.490 ;
        RECT 0.610 601.450 219.505 602.270 ;
        RECT 0.100 597.230 219.505 601.450 ;
        RECT 0.610 596.410 219.505 597.230 ;
        RECT 0.100 592.190 219.505 596.410 ;
        RECT 0.610 591.370 219.505 592.190 ;
        RECT 0.100 587.150 219.505 591.370 ;
        RECT 0.610 586.330 219.505 587.150 ;
        RECT 0.100 582.110 219.505 586.330 ;
        RECT 0.610 581.290 219.505 582.110 ;
        RECT 0.100 577.070 219.505 581.290 ;
        RECT 0.610 576.250 219.505 577.070 ;
        RECT 0.100 572.030 219.505 576.250 ;
        RECT 0.610 571.210 219.505 572.030 ;
        RECT 0.100 566.990 219.505 571.210 ;
        RECT 0.610 566.170 219.505 566.990 ;
        RECT 0.100 561.950 219.505 566.170 ;
        RECT 0.610 561.530 219.505 561.950 ;
        RECT 0.610 561.130 219.230 561.530 ;
        RECT 0.100 560.710 219.230 561.130 ;
        RECT 0.100 560.690 219.505 560.710 ;
        RECT 0.100 559.870 219.230 560.690 ;
        RECT 0.100 559.850 219.505 559.870 ;
        RECT 0.100 559.030 219.230 559.850 ;
        RECT 0.100 559.010 219.505 559.030 ;
        RECT 0.100 558.190 219.230 559.010 ;
        RECT 0.100 558.170 219.505 558.190 ;
        RECT 0.100 557.350 219.230 558.170 ;
        RECT 0.100 557.330 219.505 557.350 ;
        RECT 0.100 556.910 219.230 557.330 ;
        RECT 0.610 556.510 219.230 556.910 ;
        RECT 0.610 556.490 219.505 556.510 ;
        RECT 0.610 556.090 219.230 556.490 ;
        RECT 0.100 555.670 219.230 556.090 ;
        RECT 0.100 555.650 219.505 555.670 ;
        RECT 0.100 554.830 219.230 555.650 ;
        RECT 0.100 554.810 219.505 554.830 ;
        RECT 0.100 553.990 219.230 554.810 ;
        RECT 0.100 553.970 219.505 553.990 ;
        RECT 0.100 553.150 219.230 553.970 ;
        RECT 0.100 553.130 219.505 553.150 ;
        RECT 0.100 552.310 219.230 553.130 ;
        RECT 0.100 552.290 219.505 552.310 ;
        RECT 0.100 551.870 219.230 552.290 ;
        RECT 0.610 551.470 219.230 551.870 ;
        RECT 0.610 551.450 219.505 551.470 ;
        RECT 0.610 551.050 219.230 551.450 ;
        RECT 0.100 550.630 219.230 551.050 ;
        RECT 0.100 550.610 219.505 550.630 ;
        RECT 0.100 549.790 219.230 550.610 ;
        RECT 0.100 549.770 219.505 549.790 ;
        RECT 0.100 548.950 219.230 549.770 ;
        RECT 0.100 548.930 219.505 548.950 ;
        RECT 0.100 548.110 219.230 548.930 ;
        RECT 0.100 548.090 219.505 548.110 ;
        RECT 0.100 547.270 219.230 548.090 ;
        RECT 0.100 547.250 219.505 547.270 ;
        RECT 0.100 546.830 219.230 547.250 ;
        RECT 0.610 546.430 219.230 546.830 ;
        RECT 0.610 546.410 219.505 546.430 ;
        RECT 0.610 546.010 219.230 546.410 ;
        RECT 0.100 545.590 219.230 546.010 ;
        RECT 0.100 545.570 219.505 545.590 ;
        RECT 0.100 544.750 219.230 545.570 ;
        RECT 0.100 544.730 219.505 544.750 ;
        RECT 0.100 543.910 219.230 544.730 ;
        RECT 0.100 543.890 219.505 543.910 ;
        RECT 0.100 543.070 219.230 543.890 ;
        RECT 0.100 543.050 219.505 543.070 ;
        RECT 0.100 542.230 219.230 543.050 ;
        RECT 0.100 542.210 219.505 542.230 ;
        RECT 0.100 541.790 219.230 542.210 ;
        RECT 0.610 541.390 219.230 541.790 ;
        RECT 0.610 541.370 219.505 541.390 ;
        RECT 0.610 540.970 219.230 541.370 ;
        RECT 0.100 540.550 219.230 540.970 ;
        RECT 0.100 540.530 219.505 540.550 ;
        RECT 0.100 539.710 219.230 540.530 ;
        RECT 0.100 539.690 219.505 539.710 ;
        RECT 0.100 538.870 219.230 539.690 ;
        RECT 0.100 538.850 219.505 538.870 ;
        RECT 0.100 538.030 219.230 538.850 ;
        RECT 0.100 538.010 219.505 538.030 ;
        RECT 0.100 537.190 219.230 538.010 ;
        RECT 0.100 537.170 219.505 537.190 ;
        RECT 0.100 536.750 219.230 537.170 ;
        RECT 0.610 536.350 219.230 536.750 ;
        RECT 0.610 536.330 219.505 536.350 ;
        RECT 0.610 535.930 219.230 536.330 ;
        RECT 0.100 535.510 219.230 535.930 ;
        RECT 0.100 535.490 219.505 535.510 ;
        RECT 0.100 534.670 219.230 535.490 ;
        RECT 0.100 534.650 219.505 534.670 ;
        RECT 0.100 533.830 219.230 534.650 ;
        RECT 0.100 533.810 219.505 533.830 ;
        RECT 0.100 532.990 219.230 533.810 ;
        RECT 0.100 532.970 219.505 532.990 ;
        RECT 0.100 532.150 219.230 532.970 ;
        RECT 0.100 532.130 219.505 532.150 ;
        RECT 0.100 531.710 219.230 532.130 ;
        RECT 0.610 531.310 219.230 531.710 ;
        RECT 0.610 531.290 219.505 531.310 ;
        RECT 0.610 530.890 219.230 531.290 ;
        RECT 0.100 530.470 219.230 530.890 ;
        RECT 0.100 530.450 219.505 530.470 ;
        RECT 0.100 529.630 219.230 530.450 ;
        RECT 0.100 529.610 219.505 529.630 ;
        RECT 0.100 528.790 219.230 529.610 ;
        RECT 0.100 528.770 219.505 528.790 ;
        RECT 0.100 527.950 219.230 528.770 ;
        RECT 0.100 527.930 219.505 527.950 ;
        RECT 0.100 527.110 219.230 527.930 ;
        RECT 0.100 527.090 219.505 527.110 ;
        RECT 0.100 526.270 219.230 527.090 ;
        RECT 0.100 526.250 219.505 526.270 ;
        RECT 0.100 525.430 219.230 526.250 ;
        RECT 0.100 525.410 219.505 525.430 ;
        RECT 0.100 524.590 219.230 525.410 ;
        RECT 0.100 524.570 219.505 524.590 ;
        RECT 0.100 523.750 219.230 524.570 ;
        RECT 0.100 523.730 219.505 523.750 ;
        RECT 0.100 522.910 219.230 523.730 ;
        RECT 0.100 522.890 219.505 522.910 ;
        RECT 0.100 522.070 219.230 522.890 ;
        RECT 0.100 522.050 219.505 522.070 ;
        RECT 0.100 521.230 219.230 522.050 ;
        RECT 0.100 521.210 219.505 521.230 ;
        RECT 0.100 520.390 219.230 521.210 ;
        RECT 0.100 520.370 219.505 520.390 ;
        RECT 0.100 519.550 219.230 520.370 ;
        RECT 0.100 519.530 219.505 519.550 ;
        RECT 0.100 518.710 219.230 519.530 ;
        RECT 0.100 518.690 219.505 518.710 ;
        RECT 0.100 517.870 219.230 518.690 ;
        RECT 0.100 517.850 219.505 517.870 ;
        RECT 0.100 517.030 219.230 517.850 ;
        RECT 0.100 517.010 219.505 517.030 ;
        RECT 0.100 516.190 219.230 517.010 ;
        RECT 0.100 516.170 219.505 516.190 ;
        RECT 0.100 515.350 219.230 516.170 ;
        RECT 0.100 515.330 219.505 515.350 ;
        RECT 0.100 514.510 219.230 515.330 ;
        RECT 0.100 514.490 219.505 514.510 ;
        RECT 0.100 513.670 219.230 514.490 ;
        RECT 0.100 513.650 219.505 513.670 ;
        RECT 0.610 512.830 219.230 513.650 ;
        RECT 0.100 512.810 219.505 512.830 ;
        RECT 0.100 511.990 219.230 512.810 ;
        RECT 0.100 511.970 219.505 511.990 ;
        RECT 0.100 511.150 219.230 511.970 ;
        RECT 0.100 511.130 219.505 511.150 ;
        RECT 0.100 510.310 219.230 511.130 ;
        RECT 0.100 510.290 219.505 510.310 ;
        RECT 0.100 509.470 219.230 510.290 ;
        RECT 0.100 509.450 219.505 509.470 ;
        RECT 0.100 508.630 219.230 509.450 ;
        RECT 0.100 508.610 219.505 508.630 ;
        RECT 0.610 507.790 219.230 508.610 ;
        RECT 0.100 507.770 219.505 507.790 ;
        RECT 0.100 506.950 219.230 507.770 ;
        RECT 0.100 506.930 219.505 506.950 ;
        RECT 0.100 506.110 219.230 506.930 ;
        RECT 0.100 506.090 219.505 506.110 ;
        RECT 0.100 505.270 219.230 506.090 ;
        RECT 0.100 505.250 219.505 505.270 ;
        RECT 0.100 504.430 219.230 505.250 ;
        RECT 0.100 504.410 219.505 504.430 ;
        RECT 0.100 503.590 219.230 504.410 ;
        RECT 0.100 503.570 219.505 503.590 ;
        RECT 0.610 502.750 219.230 503.570 ;
        RECT 0.100 502.730 219.505 502.750 ;
        RECT 0.100 501.910 219.230 502.730 ;
        RECT 0.100 501.890 219.505 501.910 ;
        RECT 0.100 501.070 219.230 501.890 ;
        RECT 0.100 501.050 219.505 501.070 ;
        RECT 0.100 500.230 219.230 501.050 ;
        RECT 0.100 500.210 219.505 500.230 ;
        RECT 0.100 499.390 219.230 500.210 ;
        RECT 0.100 499.370 219.505 499.390 ;
        RECT 0.100 498.550 219.230 499.370 ;
        RECT 0.100 498.530 219.505 498.550 ;
        RECT 0.610 497.710 219.230 498.530 ;
        RECT 0.100 497.690 219.505 497.710 ;
        RECT 0.100 496.870 219.230 497.690 ;
        RECT 0.100 496.850 219.505 496.870 ;
        RECT 0.100 496.030 219.230 496.850 ;
        RECT 0.100 496.010 219.505 496.030 ;
        RECT 0.100 495.190 219.230 496.010 ;
        RECT 0.100 495.170 219.505 495.190 ;
        RECT 0.100 494.350 219.230 495.170 ;
        RECT 0.100 494.330 219.505 494.350 ;
        RECT 0.100 493.510 219.230 494.330 ;
        RECT 0.100 493.490 219.505 493.510 ;
        RECT 0.610 492.670 219.230 493.490 ;
        RECT 0.100 492.650 219.505 492.670 ;
        RECT 0.100 491.830 219.230 492.650 ;
        RECT 0.100 491.810 219.505 491.830 ;
        RECT 0.100 490.990 219.230 491.810 ;
        RECT 0.100 490.970 219.505 490.990 ;
        RECT 0.100 490.150 219.230 490.970 ;
        RECT 0.100 490.130 219.505 490.150 ;
        RECT 0.100 489.310 219.230 490.130 ;
        RECT 0.100 489.290 219.505 489.310 ;
        RECT 0.100 488.470 219.230 489.290 ;
        RECT 0.100 488.450 219.505 488.470 ;
        RECT 0.610 487.630 219.230 488.450 ;
        RECT 0.100 487.610 219.505 487.630 ;
        RECT 0.100 486.790 219.230 487.610 ;
        RECT 0.100 486.770 219.505 486.790 ;
        RECT 0.100 485.950 219.230 486.770 ;
        RECT 0.100 485.930 219.505 485.950 ;
        RECT 0.100 485.110 219.230 485.930 ;
        RECT 0.100 485.090 219.505 485.110 ;
        RECT 0.100 484.270 219.230 485.090 ;
        RECT 0.100 484.250 219.505 484.270 ;
        RECT 0.100 483.430 219.230 484.250 ;
        RECT 0.100 483.410 219.505 483.430 ;
        RECT 0.610 482.590 219.230 483.410 ;
        RECT 0.100 482.570 219.505 482.590 ;
        RECT 0.100 481.750 219.230 482.570 ;
        RECT 0.100 481.730 219.505 481.750 ;
        RECT 0.100 480.910 219.230 481.730 ;
        RECT 0.100 480.890 219.505 480.910 ;
        RECT 0.100 480.070 219.230 480.890 ;
        RECT 0.100 480.050 219.505 480.070 ;
        RECT 0.100 479.230 219.230 480.050 ;
        RECT 0.100 479.210 219.505 479.230 ;
        RECT 0.100 478.390 219.230 479.210 ;
        RECT 0.100 478.370 219.505 478.390 ;
        RECT 0.610 477.550 219.230 478.370 ;
        RECT 0.100 477.530 219.505 477.550 ;
        RECT 0.100 476.710 219.230 477.530 ;
        RECT 0.100 476.690 219.505 476.710 ;
        RECT 0.100 475.870 219.230 476.690 ;
        RECT 0.100 475.850 219.505 475.870 ;
        RECT 0.100 475.030 219.230 475.850 ;
        RECT 0.100 475.010 219.505 475.030 ;
        RECT 0.100 474.190 219.230 475.010 ;
        RECT 0.100 474.170 219.505 474.190 ;
        RECT 0.100 473.350 219.230 474.170 ;
        RECT 0.100 473.330 219.505 473.350 ;
        RECT 0.610 472.510 219.230 473.330 ;
        RECT 0.100 472.490 219.505 472.510 ;
        RECT 0.100 471.670 219.230 472.490 ;
        RECT 0.100 471.650 219.505 471.670 ;
        RECT 0.100 470.830 219.230 471.650 ;
        RECT 0.100 470.810 219.505 470.830 ;
        RECT 0.100 469.990 219.230 470.810 ;
        RECT 0.100 469.970 219.505 469.990 ;
        RECT 0.100 469.150 219.230 469.970 ;
        RECT 0.100 469.130 219.505 469.150 ;
        RECT 0.100 468.310 219.230 469.130 ;
        RECT 0.100 468.290 219.505 468.310 ;
        RECT 0.610 467.470 219.230 468.290 ;
        RECT 0.100 467.450 219.505 467.470 ;
        RECT 0.100 466.630 219.230 467.450 ;
        RECT 0.100 466.610 219.505 466.630 ;
        RECT 0.100 465.790 219.230 466.610 ;
        RECT 0.100 465.770 219.505 465.790 ;
        RECT 0.100 464.950 219.230 465.770 ;
        RECT 0.100 464.930 219.505 464.950 ;
        RECT 0.100 464.110 219.230 464.930 ;
        RECT 0.100 464.090 219.505 464.110 ;
        RECT 0.100 463.270 219.230 464.090 ;
        RECT 0.100 463.250 219.505 463.270 ;
        RECT 0.610 462.430 219.230 463.250 ;
        RECT 0.100 462.410 219.505 462.430 ;
        RECT 0.100 461.590 219.230 462.410 ;
        RECT 0.100 461.570 219.505 461.590 ;
        RECT 0.100 460.750 219.230 461.570 ;
        RECT 0.100 460.730 219.505 460.750 ;
        RECT 0.100 459.910 219.230 460.730 ;
        RECT 0.100 459.890 219.505 459.910 ;
        RECT 0.100 459.070 219.230 459.890 ;
        RECT 0.100 459.050 219.505 459.070 ;
        RECT 0.100 458.230 219.230 459.050 ;
        RECT 0.100 458.210 219.505 458.230 ;
        RECT 0.610 457.390 219.230 458.210 ;
        RECT 0.100 457.370 219.505 457.390 ;
        RECT 0.100 456.550 219.230 457.370 ;
        RECT 0.100 456.530 219.505 456.550 ;
        RECT 0.100 455.710 219.230 456.530 ;
        RECT 0.100 455.690 219.505 455.710 ;
        RECT 0.100 454.870 219.230 455.690 ;
        RECT 0.100 454.850 219.505 454.870 ;
        RECT 0.100 454.030 219.230 454.850 ;
        RECT 0.100 453.170 219.505 454.030 ;
        RECT 0.610 452.350 219.505 453.170 ;
        RECT 0.100 448.130 219.505 452.350 ;
        RECT 0.610 447.310 219.505 448.130 ;
        RECT 0.100 443.090 219.505 447.310 ;
        RECT 0.610 442.270 219.505 443.090 ;
        RECT 0.100 438.050 219.505 442.270 ;
        RECT 0.610 437.230 219.505 438.050 ;
        RECT 0.100 433.010 219.505 437.230 ;
        RECT 0.610 432.190 219.505 433.010 ;
        RECT 0.100 427.970 219.505 432.190 ;
        RECT 0.610 427.150 219.505 427.970 ;
        RECT 0.100 422.930 219.505 427.150 ;
        RECT 0.610 422.110 219.505 422.930 ;
        RECT 0.100 417.890 219.505 422.110 ;
        RECT 0.610 417.070 219.505 417.890 ;
        RECT 0.100 412.850 219.505 417.070 ;
        RECT 0.610 412.030 219.505 412.850 ;
        RECT 0.100 407.810 219.505 412.030 ;
        RECT 0.610 406.990 219.505 407.810 ;
        RECT 0.100 402.770 219.505 406.990 ;
        RECT 0.610 401.950 219.505 402.770 ;
        RECT 0.100 397.730 219.505 401.950 ;
        RECT 0.610 396.910 219.505 397.730 ;
        RECT 0.100 392.690 219.505 396.910 ;
        RECT 0.610 391.870 219.505 392.690 ;
        RECT 0.100 387.650 219.505 391.870 ;
        RECT 0.610 386.830 219.505 387.650 ;
        RECT 0.100 382.610 219.505 386.830 ;
        RECT 0.610 381.790 219.505 382.610 ;
        RECT 0.100 377.570 219.505 381.790 ;
        RECT 0.610 376.750 219.505 377.570 ;
        RECT 0.100 372.530 219.505 376.750 ;
        RECT 0.610 371.710 219.505 372.530 ;
        RECT 0.100 367.490 219.505 371.710 ;
        RECT 0.610 366.670 219.505 367.490 ;
        RECT 0.100 362.450 219.505 366.670 ;
        RECT 0.610 361.630 219.505 362.450 ;
        RECT 0.100 358.250 219.505 361.630 ;
        RECT 0.100 357.430 219.230 358.250 ;
        RECT 0.100 357.410 219.505 357.430 ;
        RECT 0.610 356.590 219.230 357.410 ;
        RECT 0.100 356.570 219.505 356.590 ;
        RECT 0.100 355.750 219.230 356.570 ;
        RECT 0.100 355.730 219.505 355.750 ;
        RECT 0.100 354.910 219.230 355.730 ;
        RECT 0.100 354.890 219.505 354.910 ;
        RECT 0.100 354.070 219.230 354.890 ;
        RECT 0.100 354.050 219.505 354.070 ;
        RECT 0.100 353.230 219.230 354.050 ;
        RECT 0.100 353.210 219.505 353.230 ;
        RECT 0.100 352.390 219.230 353.210 ;
        RECT 0.100 352.370 219.505 352.390 ;
        RECT 0.100 351.550 219.230 352.370 ;
        RECT 0.100 351.530 219.505 351.550 ;
        RECT 0.100 350.710 219.230 351.530 ;
        RECT 0.100 350.690 219.505 350.710 ;
        RECT 0.100 349.870 219.230 350.690 ;
        RECT 0.100 349.850 219.505 349.870 ;
        RECT 0.100 349.030 219.230 349.850 ;
        RECT 0.100 349.010 219.505 349.030 ;
        RECT 0.100 348.190 219.230 349.010 ;
        RECT 0.100 348.170 219.505 348.190 ;
        RECT 0.100 347.350 219.230 348.170 ;
        RECT 0.100 347.330 219.505 347.350 ;
        RECT 0.100 346.510 219.230 347.330 ;
        RECT 0.100 346.490 219.505 346.510 ;
        RECT 0.100 345.670 219.230 346.490 ;
        RECT 0.100 345.650 219.505 345.670 ;
        RECT 0.100 344.830 219.230 345.650 ;
        RECT 0.100 344.810 219.505 344.830 ;
        RECT 0.100 343.990 219.230 344.810 ;
        RECT 0.100 343.970 219.505 343.990 ;
        RECT 0.100 343.150 219.230 343.970 ;
        RECT 0.100 343.130 219.505 343.150 ;
        RECT 0.100 342.310 219.230 343.130 ;
        RECT 0.100 342.290 219.505 342.310 ;
        RECT 0.100 341.470 219.230 342.290 ;
        RECT 0.100 341.450 219.505 341.470 ;
        RECT 0.100 340.630 219.230 341.450 ;
        RECT 0.100 340.610 219.505 340.630 ;
        RECT 0.100 339.790 219.230 340.610 ;
        RECT 0.100 339.770 219.505 339.790 ;
        RECT 0.100 339.350 219.230 339.770 ;
        RECT 0.610 338.950 219.230 339.350 ;
        RECT 0.610 338.930 219.505 338.950 ;
        RECT 0.610 338.530 219.230 338.930 ;
        RECT 0.100 338.110 219.230 338.530 ;
        RECT 0.100 338.090 219.505 338.110 ;
        RECT 0.100 337.270 219.230 338.090 ;
        RECT 0.100 337.250 219.505 337.270 ;
        RECT 0.100 336.430 219.230 337.250 ;
        RECT 0.100 336.410 219.505 336.430 ;
        RECT 0.100 335.590 219.230 336.410 ;
        RECT 0.100 335.570 219.505 335.590 ;
        RECT 0.100 334.750 219.230 335.570 ;
        RECT 0.100 334.730 219.505 334.750 ;
        RECT 0.100 334.310 219.230 334.730 ;
        RECT 0.610 333.910 219.230 334.310 ;
        RECT 0.610 333.890 219.505 333.910 ;
        RECT 0.610 333.490 219.230 333.890 ;
        RECT 0.100 333.070 219.230 333.490 ;
        RECT 0.100 333.050 219.505 333.070 ;
        RECT 0.100 332.230 219.230 333.050 ;
        RECT 0.100 332.210 219.505 332.230 ;
        RECT 0.100 331.390 219.230 332.210 ;
        RECT 0.100 331.370 219.505 331.390 ;
        RECT 0.100 330.550 219.230 331.370 ;
        RECT 0.100 330.530 219.505 330.550 ;
        RECT 0.100 329.710 219.230 330.530 ;
        RECT 0.100 329.690 219.505 329.710 ;
        RECT 0.100 329.270 219.230 329.690 ;
        RECT 0.610 328.870 219.230 329.270 ;
        RECT 0.610 328.850 219.505 328.870 ;
        RECT 0.610 328.450 219.230 328.850 ;
        RECT 0.100 328.030 219.230 328.450 ;
        RECT 0.100 328.010 219.505 328.030 ;
        RECT 0.100 327.190 219.230 328.010 ;
        RECT 0.100 327.170 219.505 327.190 ;
        RECT 0.100 326.350 219.230 327.170 ;
        RECT 0.100 326.330 219.505 326.350 ;
        RECT 0.100 325.510 219.230 326.330 ;
        RECT 0.100 325.490 219.505 325.510 ;
        RECT 0.100 324.670 219.230 325.490 ;
        RECT 0.100 324.650 219.505 324.670 ;
        RECT 0.100 324.230 219.230 324.650 ;
        RECT 0.610 323.830 219.230 324.230 ;
        RECT 0.610 323.810 219.505 323.830 ;
        RECT 0.610 323.410 219.230 323.810 ;
        RECT 0.100 322.990 219.230 323.410 ;
        RECT 0.100 322.970 219.505 322.990 ;
        RECT 0.100 322.150 219.230 322.970 ;
        RECT 0.100 322.130 219.505 322.150 ;
        RECT 0.100 321.310 219.230 322.130 ;
        RECT 0.100 321.290 219.505 321.310 ;
        RECT 0.100 320.470 219.230 321.290 ;
        RECT 0.100 320.450 219.505 320.470 ;
        RECT 0.100 319.630 219.230 320.450 ;
        RECT 0.100 319.610 219.505 319.630 ;
        RECT 0.100 319.190 219.230 319.610 ;
        RECT 0.610 318.790 219.230 319.190 ;
        RECT 0.610 318.770 219.505 318.790 ;
        RECT 0.610 318.370 219.230 318.770 ;
        RECT 0.100 317.950 219.230 318.370 ;
        RECT 0.100 317.930 219.505 317.950 ;
        RECT 0.100 317.110 219.230 317.930 ;
        RECT 0.100 317.090 219.505 317.110 ;
        RECT 0.100 316.270 219.230 317.090 ;
        RECT 0.100 316.250 219.505 316.270 ;
        RECT 0.100 315.430 219.230 316.250 ;
        RECT 0.100 315.410 219.505 315.430 ;
        RECT 0.100 314.590 219.230 315.410 ;
        RECT 0.100 314.570 219.505 314.590 ;
        RECT 0.100 314.150 219.230 314.570 ;
        RECT 0.610 313.750 219.230 314.150 ;
        RECT 0.610 313.730 219.505 313.750 ;
        RECT 0.610 313.330 219.230 313.730 ;
        RECT 0.100 312.910 219.230 313.330 ;
        RECT 0.100 312.890 219.505 312.910 ;
        RECT 0.100 312.070 219.230 312.890 ;
        RECT 0.100 312.050 219.505 312.070 ;
        RECT 0.100 311.230 219.230 312.050 ;
        RECT 0.100 311.210 219.505 311.230 ;
        RECT 0.100 310.390 219.230 311.210 ;
        RECT 0.100 310.370 219.505 310.390 ;
        RECT 0.100 309.550 219.230 310.370 ;
        RECT 0.100 309.530 219.505 309.550 ;
        RECT 0.100 309.110 219.230 309.530 ;
        RECT 0.610 308.710 219.230 309.110 ;
        RECT 0.610 308.690 219.505 308.710 ;
        RECT 0.610 308.290 219.230 308.690 ;
        RECT 0.100 307.870 219.230 308.290 ;
        RECT 0.100 307.850 219.505 307.870 ;
        RECT 0.100 307.030 219.230 307.850 ;
        RECT 0.100 307.010 219.505 307.030 ;
        RECT 0.100 306.190 219.230 307.010 ;
        RECT 0.100 306.170 219.505 306.190 ;
        RECT 0.100 305.350 219.230 306.170 ;
        RECT 0.100 305.330 219.505 305.350 ;
        RECT 0.100 304.510 219.230 305.330 ;
        RECT 0.100 304.490 219.505 304.510 ;
        RECT 0.100 304.070 219.230 304.490 ;
        RECT 0.610 303.670 219.230 304.070 ;
        RECT 0.610 303.650 219.505 303.670 ;
        RECT 0.610 303.250 219.230 303.650 ;
        RECT 0.100 302.830 219.230 303.250 ;
        RECT 0.100 302.810 219.505 302.830 ;
        RECT 0.100 301.990 219.230 302.810 ;
        RECT 0.100 301.970 219.505 301.990 ;
        RECT 0.100 301.150 219.230 301.970 ;
        RECT 0.100 301.130 219.505 301.150 ;
        RECT 0.100 300.310 219.230 301.130 ;
        RECT 0.100 300.290 219.505 300.310 ;
        RECT 0.100 299.470 219.230 300.290 ;
        RECT 0.100 299.450 219.505 299.470 ;
        RECT 0.100 299.030 219.230 299.450 ;
        RECT 0.610 298.630 219.230 299.030 ;
        RECT 0.610 298.610 219.505 298.630 ;
        RECT 0.610 298.210 219.230 298.610 ;
        RECT 0.100 297.790 219.230 298.210 ;
        RECT 0.100 297.770 219.505 297.790 ;
        RECT 0.100 296.950 219.230 297.770 ;
        RECT 0.100 296.930 219.505 296.950 ;
        RECT 0.100 296.110 219.230 296.930 ;
        RECT 0.100 296.090 219.505 296.110 ;
        RECT 0.100 295.270 219.230 296.090 ;
        RECT 0.100 295.250 219.505 295.270 ;
        RECT 0.100 294.430 219.230 295.250 ;
        RECT 0.100 294.410 219.505 294.430 ;
        RECT 0.100 293.990 219.230 294.410 ;
        RECT 0.610 293.590 219.230 293.990 ;
        RECT 0.610 293.570 219.505 293.590 ;
        RECT 0.610 293.170 219.230 293.570 ;
        RECT 0.100 292.750 219.230 293.170 ;
        RECT 0.100 292.730 219.505 292.750 ;
        RECT 0.100 291.910 219.230 292.730 ;
        RECT 0.100 291.890 219.505 291.910 ;
        RECT 0.100 291.070 219.230 291.890 ;
        RECT 0.100 291.050 219.505 291.070 ;
        RECT 0.100 290.230 219.230 291.050 ;
        RECT 0.100 290.210 219.505 290.230 ;
        RECT 0.100 289.390 219.230 290.210 ;
        RECT 0.100 289.370 219.505 289.390 ;
        RECT 0.100 288.950 219.230 289.370 ;
        RECT 0.610 288.550 219.230 288.950 ;
        RECT 0.610 288.530 219.505 288.550 ;
        RECT 0.610 288.130 219.230 288.530 ;
        RECT 0.100 287.710 219.230 288.130 ;
        RECT 0.100 287.690 219.505 287.710 ;
        RECT 0.100 286.870 219.230 287.690 ;
        RECT 0.100 286.850 219.505 286.870 ;
        RECT 0.100 286.030 219.230 286.850 ;
        RECT 0.100 286.010 219.505 286.030 ;
        RECT 0.100 285.190 219.230 286.010 ;
        RECT 0.100 285.170 219.505 285.190 ;
        RECT 0.100 284.350 219.230 285.170 ;
        RECT 0.100 284.330 219.505 284.350 ;
        RECT 0.100 283.910 219.230 284.330 ;
        RECT 0.610 283.510 219.230 283.910 ;
        RECT 0.610 283.490 219.505 283.510 ;
        RECT 0.610 283.090 219.230 283.490 ;
        RECT 0.100 282.670 219.230 283.090 ;
        RECT 0.100 282.650 219.505 282.670 ;
        RECT 0.100 281.830 219.230 282.650 ;
        RECT 0.100 281.810 219.505 281.830 ;
        RECT 0.100 280.990 219.230 281.810 ;
        RECT 0.100 280.970 219.505 280.990 ;
        RECT 0.100 280.150 219.230 280.970 ;
        RECT 0.100 280.130 219.505 280.150 ;
        RECT 0.100 279.310 219.230 280.130 ;
        RECT 0.100 279.290 219.505 279.310 ;
        RECT 0.100 278.870 219.230 279.290 ;
        RECT 0.610 278.470 219.230 278.870 ;
        RECT 0.610 278.450 219.505 278.470 ;
        RECT 0.610 278.050 219.230 278.450 ;
        RECT 0.100 277.630 219.230 278.050 ;
        RECT 0.100 277.610 219.505 277.630 ;
        RECT 0.100 276.790 219.230 277.610 ;
        RECT 0.100 276.770 219.505 276.790 ;
        RECT 0.100 275.950 219.230 276.770 ;
        RECT 0.100 275.930 219.505 275.950 ;
        RECT 0.100 275.110 219.230 275.930 ;
        RECT 0.100 275.090 219.505 275.110 ;
        RECT 0.100 274.270 219.230 275.090 ;
        RECT 0.100 274.250 219.505 274.270 ;
        RECT 0.100 273.830 219.230 274.250 ;
        RECT 0.610 273.430 219.230 273.830 ;
        RECT 0.610 273.410 219.505 273.430 ;
        RECT 0.610 273.010 219.230 273.410 ;
        RECT 0.100 272.590 219.230 273.010 ;
        RECT 0.100 272.570 219.505 272.590 ;
        RECT 0.100 271.750 219.230 272.570 ;
        RECT 0.100 271.730 219.505 271.750 ;
        RECT 0.100 270.910 219.230 271.730 ;
        RECT 0.100 270.890 219.505 270.910 ;
        RECT 0.100 270.070 219.230 270.890 ;
        RECT 0.100 270.050 219.505 270.070 ;
        RECT 0.100 269.230 219.230 270.050 ;
        RECT 0.100 269.210 219.505 269.230 ;
        RECT 0.100 268.790 219.230 269.210 ;
        RECT 0.610 268.390 219.230 268.790 ;
        RECT 0.610 268.370 219.505 268.390 ;
        RECT 0.610 267.970 219.230 268.370 ;
        RECT 0.100 267.550 219.230 267.970 ;
        RECT 0.100 267.530 219.505 267.550 ;
        RECT 0.100 266.710 219.230 267.530 ;
        RECT 0.100 266.690 219.505 266.710 ;
        RECT 0.100 265.870 219.230 266.690 ;
        RECT 0.100 265.850 219.505 265.870 ;
        RECT 0.100 265.030 219.230 265.850 ;
        RECT 0.100 265.010 219.505 265.030 ;
        RECT 0.100 264.190 219.230 265.010 ;
        RECT 0.100 264.170 219.505 264.190 ;
        RECT 0.100 263.750 219.230 264.170 ;
        RECT 0.610 263.350 219.230 263.750 ;
        RECT 0.610 263.330 219.505 263.350 ;
        RECT 0.610 262.930 219.230 263.330 ;
        RECT 0.100 262.510 219.230 262.930 ;
        RECT 0.100 262.490 219.505 262.510 ;
        RECT 0.100 261.670 219.230 262.490 ;
        RECT 0.100 261.650 219.505 261.670 ;
        RECT 0.100 260.830 219.230 261.650 ;
        RECT 0.100 260.810 219.505 260.830 ;
        RECT 0.100 259.990 219.230 260.810 ;
        RECT 0.100 259.970 219.505 259.990 ;
        RECT 0.100 259.150 219.230 259.970 ;
        RECT 0.100 259.130 219.505 259.150 ;
        RECT 0.100 258.710 219.230 259.130 ;
        RECT 0.610 258.310 219.230 258.710 ;
        RECT 0.610 258.290 219.505 258.310 ;
        RECT 0.610 257.890 219.230 258.290 ;
        RECT 0.100 257.470 219.230 257.890 ;
        RECT 0.100 257.450 219.505 257.470 ;
        RECT 0.100 256.630 219.230 257.450 ;
        RECT 0.100 256.610 219.505 256.630 ;
        RECT 0.100 255.790 219.230 256.610 ;
        RECT 0.100 255.770 219.505 255.790 ;
        RECT 0.100 254.950 219.230 255.770 ;
        RECT 0.100 254.930 219.505 254.950 ;
        RECT 0.100 254.110 219.230 254.930 ;
        RECT 0.100 254.090 219.505 254.110 ;
        RECT 0.100 253.670 219.230 254.090 ;
        RECT 0.610 253.270 219.230 253.670 ;
        RECT 0.610 253.250 219.505 253.270 ;
        RECT 0.610 252.850 219.230 253.250 ;
        RECT 0.100 252.430 219.230 252.850 ;
        RECT 0.100 252.410 219.505 252.430 ;
        RECT 0.100 251.590 219.230 252.410 ;
        RECT 0.100 251.570 219.505 251.590 ;
        RECT 0.100 250.750 219.230 251.570 ;
        RECT 0.100 248.630 219.505 250.750 ;
        RECT 0.610 247.810 219.505 248.630 ;
        RECT 0.100 243.590 219.505 247.810 ;
        RECT 0.610 242.770 219.505 243.590 ;
        RECT 0.100 238.550 219.505 242.770 ;
        RECT 0.610 237.730 219.505 238.550 ;
        RECT 0.100 233.510 219.505 237.730 ;
        RECT 0.610 232.690 219.505 233.510 ;
        RECT 0.100 228.470 219.505 232.690 ;
        RECT 0.610 227.650 219.505 228.470 ;
        RECT 0.100 223.430 219.505 227.650 ;
        RECT 0.610 222.610 219.505 223.430 ;
        RECT 0.100 218.390 219.505 222.610 ;
        RECT 0.610 217.570 219.505 218.390 ;
        RECT 0.100 213.350 219.505 217.570 ;
        RECT 0.610 212.530 219.505 213.350 ;
        RECT 0.100 208.310 219.505 212.530 ;
        RECT 0.610 207.490 219.505 208.310 ;
        RECT 0.100 203.270 219.505 207.490 ;
        RECT 0.610 202.450 219.505 203.270 ;
        RECT 0.100 198.230 219.505 202.450 ;
        RECT 0.610 197.410 219.505 198.230 ;
        RECT 0.100 193.190 219.505 197.410 ;
        RECT 0.610 192.370 219.505 193.190 ;
        RECT 0.100 188.150 219.505 192.370 ;
        RECT 0.610 187.330 219.505 188.150 ;
        RECT 0.100 183.110 219.505 187.330 ;
        RECT 0.610 182.290 219.505 183.110 ;
        RECT 0.100 159.590 219.505 182.290 ;
        RECT 0.610 158.770 219.505 159.590 ;
        RECT 0.100 158.750 219.505 158.770 ;
        RECT 0.610 157.930 219.505 158.750 ;
        RECT 0.100 157.910 219.505 157.930 ;
        RECT 0.610 157.090 219.505 157.910 ;
        RECT 0.100 157.070 219.505 157.090 ;
        RECT 0.610 156.250 219.505 157.070 ;
        RECT 0.100 156.230 219.505 156.250 ;
        RECT 0.610 155.410 219.505 156.230 ;
        RECT 0.100 155.390 219.505 155.410 ;
        RECT 0.610 154.570 219.230 155.390 ;
        RECT 0.100 154.550 219.505 154.570 ;
        RECT 0.610 153.730 219.230 154.550 ;
        RECT 0.100 153.710 219.505 153.730 ;
        RECT 0.610 152.890 219.230 153.710 ;
        RECT 0.100 152.870 219.505 152.890 ;
        RECT 0.610 152.050 219.230 152.870 ;
        RECT 0.100 152.030 219.505 152.050 ;
        RECT 0.610 151.210 219.230 152.030 ;
        RECT 0.100 151.190 219.505 151.210 ;
        RECT 0.610 150.370 219.230 151.190 ;
        RECT 0.100 150.350 219.505 150.370 ;
        RECT 0.610 149.530 219.230 150.350 ;
        RECT 0.100 149.510 219.505 149.530 ;
        RECT 0.610 148.690 219.230 149.510 ;
        RECT 0.100 148.670 219.505 148.690 ;
        RECT 0.610 147.850 219.230 148.670 ;
        RECT 0.100 147.830 219.505 147.850 ;
        RECT 0.610 147.010 219.230 147.830 ;
        RECT 0.100 146.990 219.505 147.010 ;
        RECT 0.610 146.170 219.230 146.990 ;
        RECT 0.100 146.150 219.505 146.170 ;
        RECT 0.610 145.330 219.230 146.150 ;
        RECT 0.100 145.310 219.505 145.330 ;
        RECT 0.610 144.490 219.230 145.310 ;
        RECT 0.100 144.470 219.505 144.490 ;
        RECT 0.610 143.650 219.230 144.470 ;
        RECT 0.100 143.630 219.505 143.650 ;
        RECT 0.610 142.810 219.230 143.630 ;
        RECT 0.100 142.790 219.505 142.810 ;
        RECT 0.610 141.970 219.230 142.790 ;
        RECT 0.100 141.950 219.505 141.970 ;
        RECT 0.610 141.130 219.230 141.950 ;
        RECT 0.100 141.110 219.505 141.130 ;
        RECT 0.610 140.290 219.230 141.110 ;
        RECT 0.100 140.270 219.505 140.290 ;
        RECT 0.610 139.450 219.230 140.270 ;
        RECT 0.100 139.430 219.505 139.450 ;
        RECT 0.610 138.610 219.230 139.430 ;
        RECT 0.100 138.590 219.505 138.610 ;
        RECT 0.610 137.770 219.230 138.590 ;
        RECT 0.100 137.750 219.505 137.770 ;
        RECT 0.610 136.930 219.230 137.750 ;
        RECT 0.100 136.910 219.505 136.930 ;
        RECT 0.610 136.090 219.230 136.910 ;
        RECT 0.100 136.070 219.505 136.090 ;
        RECT 0.610 135.250 219.230 136.070 ;
        RECT 0.100 135.230 219.505 135.250 ;
        RECT 0.610 134.410 219.230 135.230 ;
        RECT 0.100 134.390 219.505 134.410 ;
        RECT 0.610 133.570 219.230 134.390 ;
        RECT 0.100 133.550 219.505 133.570 ;
        RECT 0.610 132.730 219.230 133.550 ;
        RECT 0.100 132.710 219.505 132.730 ;
        RECT 0.610 131.890 219.230 132.710 ;
        RECT 0.100 131.870 219.505 131.890 ;
        RECT 0.610 131.050 219.230 131.870 ;
        RECT 0.100 131.030 219.505 131.050 ;
        RECT 0.610 130.210 219.230 131.030 ;
        RECT 0.100 130.190 219.505 130.210 ;
        RECT 0.610 129.370 219.230 130.190 ;
        RECT 0.100 129.350 219.505 129.370 ;
        RECT 0.610 128.530 219.230 129.350 ;
        RECT 0.100 128.510 219.505 128.530 ;
        RECT 0.610 127.690 219.230 128.510 ;
        RECT 0.100 127.670 219.505 127.690 ;
        RECT 0.610 126.850 219.230 127.670 ;
        RECT 0.100 126.830 219.505 126.850 ;
        RECT 0.610 126.010 219.230 126.830 ;
        RECT 0.100 125.990 219.505 126.010 ;
        RECT 0.610 125.170 219.230 125.990 ;
        RECT 0.100 125.150 219.505 125.170 ;
        RECT 0.610 124.330 219.230 125.150 ;
        RECT 0.100 124.310 219.505 124.330 ;
        RECT 0.610 123.490 219.230 124.310 ;
        RECT 0.100 123.470 219.505 123.490 ;
        RECT 0.610 122.650 219.230 123.470 ;
        RECT 0.100 122.630 219.505 122.650 ;
        RECT 0.610 121.810 219.230 122.630 ;
        RECT 0.100 121.790 219.505 121.810 ;
        RECT 0.610 120.970 219.230 121.790 ;
        RECT 0.100 120.950 219.505 120.970 ;
        RECT 0.610 120.130 219.230 120.950 ;
        RECT 0.100 120.110 219.505 120.130 ;
        RECT 0.610 119.290 219.230 120.110 ;
        RECT 0.100 119.270 219.505 119.290 ;
        RECT 0.610 118.450 219.230 119.270 ;
        RECT 0.100 118.430 219.505 118.450 ;
        RECT 0.610 117.610 219.230 118.430 ;
        RECT 0.100 117.590 219.505 117.610 ;
        RECT 0.610 116.770 219.230 117.590 ;
        RECT 0.100 116.750 219.505 116.770 ;
        RECT 0.610 115.930 219.230 116.750 ;
        RECT 0.100 115.910 219.505 115.930 ;
        RECT 0.610 115.090 219.230 115.910 ;
        RECT 0.100 115.070 219.505 115.090 ;
        RECT 0.610 114.250 219.230 115.070 ;
        RECT 0.100 114.230 219.505 114.250 ;
        RECT 0.610 113.410 219.230 114.230 ;
        RECT 0.100 113.390 219.505 113.410 ;
        RECT 0.610 112.570 219.230 113.390 ;
        RECT 0.100 112.550 219.505 112.570 ;
        RECT 0.610 111.730 219.230 112.550 ;
        RECT 0.100 111.710 219.505 111.730 ;
        RECT 0.610 110.890 219.230 111.710 ;
        RECT 0.100 110.870 219.505 110.890 ;
        RECT 0.610 110.050 219.230 110.870 ;
        RECT 0.100 110.030 219.505 110.050 ;
        RECT 0.610 109.210 219.230 110.030 ;
        RECT 0.100 109.190 219.505 109.210 ;
        RECT 0.610 108.370 219.230 109.190 ;
        RECT 0.100 108.350 219.505 108.370 ;
        RECT 0.610 107.530 219.230 108.350 ;
        RECT 0.100 107.510 219.505 107.530 ;
        RECT 0.610 106.690 219.230 107.510 ;
        RECT 0.100 106.670 219.505 106.690 ;
        RECT 0.610 105.850 219.230 106.670 ;
        RECT 0.100 105.830 219.505 105.850 ;
        RECT 0.610 105.010 219.230 105.830 ;
        RECT 0.100 104.990 219.505 105.010 ;
        RECT 0.610 104.170 219.230 104.990 ;
        RECT 0.100 104.150 219.505 104.170 ;
        RECT 0.610 103.330 219.230 104.150 ;
        RECT 0.100 103.310 219.505 103.330 ;
        RECT 0.610 102.490 219.230 103.310 ;
        RECT 0.100 102.470 219.505 102.490 ;
        RECT 0.610 101.650 219.230 102.470 ;
        RECT 0.100 101.630 219.505 101.650 ;
        RECT 0.610 100.810 219.230 101.630 ;
        RECT 0.100 100.790 219.505 100.810 ;
        RECT 0.610 99.970 219.230 100.790 ;
        RECT 0.100 99.950 219.505 99.970 ;
        RECT 0.610 99.130 219.230 99.950 ;
        RECT 0.100 99.110 219.505 99.130 ;
        RECT 0.610 98.290 219.230 99.110 ;
        RECT 0.100 98.270 219.505 98.290 ;
        RECT 0.610 97.450 219.230 98.270 ;
        RECT 0.100 97.430 219.505 97.450 ;
        RECT 0.610 96.610 219.230 97.430 ;
        RECT 0.100 96.590 219.505 96.610 ;
        RECT 0.610 95.770 219.230 96.590 ;
        RECT 0.100 95.750 219.505 95.770 ;
        RECT 0.610 94.930 219.230 95.750 ;
        RECT 0.100 94.910 219.505 94.930 ;
        RECT 0.610 94.090 219.230 94.910 ;
        RECT 0.100 94.070 219.505 94.090 ;
        RECT 0.610 93.250 219.230 94.070 ;
        RECT 0.100 93.230 219.505 93.250 ;
        RECT 0.610 92.410 219.230 93.230 ;
        RECT 0.100 92.390 219.505 92.410 ;
        RECT 0.610 91.570 219.230 92.390 ;
        RECT 0.100 91.550 219.505 91.570 ;
        RECT 0.610 90.730 219.230 91.550 ;
        RECT 0.100 90.710 219.505 90.730 ;
        RECT 0.610 89.890 219.230 90.710 ;
        RECT 0.100 89.870 219.505 89.890 ;
        RECT 0.610 89.050 219.230 89.870 ;
        RECT 0.100 89.030 219.505 89.050 ;
        RECT 0.610 88.210 219.230 89.030 ;
        RECT 0.100 88.190 219.505 88.210 ;
        RECT 0.610 87.370 219.230 88.190 ;
        RECT 0.100 87.350 219.505 87.370 ;
        RECT 0.610 86.530 219.230 87.350 ;
        RECT 0.100 86.510 219.505 86.530 ;
        RECT 0.610 85.690 219.230 86.510 ;
        RECT 0.100 85.670 219.505 85.690 ;
        RECT 0.610 84.850 219.230 85.670 ;
        RECT 0.100 84.830 219.505 84.850 ;
        RECT 0.610 84.010 219.230 84.830 ;
        RECT 0.100 83.990 219.505 84.010 ;
        RECT 0.610 83.170 219.230 83.990 ;
        RECT 0.100 83.150 219.505 83.170 ;
        RECT 0.610 82.330 219.230 83.150 ;
        RECT 0.100 82.310 219.505 82.330 ;
        RECT 0.610 81.490 219.230 82.310 ;
        RECT 0.100 81.470 219.505 81.490 ;
        RECT 0.610 80.650 219.230 81.470 ;
        RECT 0.100 80.630 219.505 80.650 ;
        RECT 0.610 79.810 219.230 80.630 ;
        RECT 0.100 79.790 219.505 79.810 ;
        RECT 0.610 78.970 219.230 79.790 ;
        RECT 0.100 78.950 219.505 78.970 ;
        RECT 0.610 78.130 219.230 78.950 ;
        RECT 0.100 78.110 219.505 78.130 ;
        RECT 0.610 77.290 219.230 78.110 ;
        RECT 0.100 77.270 219.505 77.290 ;
        RECT 0.610 76.450 219.230 77.270 ;
        RECT 0.100 76.430 219.505 76.450 ;
        RECT 0.610 75.610 219.230 76.430 ;
        RECT 0.100 75.590 219.505 75.610 ;
        RECT 0.610 74.770 219.230 75.590 ;
        RECT 0.100 74.750 219.505 74.770 ;
        RECT 0.610 73.930 219.230 74.750 ;
        RECT 0.100 73.910 219.505 73.930 ;
        RECT 0.610 73.090 219.230 73.910 ;
        RECT 0.100 73.070 219.505 73.090 ;
        RECT 0.610 72.250 219.230 73.070 ;
        RECT 0.100 72.230 219.505 72.250 ;
        RECT 0.610 71.410 219.230 72.230 ;
        RECT 0.100 71.390 219.505 71.410 ;
        RECT 0.610 70.570 219.230 71.390 ;
        RECT 0.100 70.550 219.505 70.570 ;
        RECT 0.610 69.730 219.230 70.550 ;
        RECT 0.100 69.710 219.505 69.730 ;
        RECT 0.610 68.890 219.230 69.710 ;
        RECT 0.100 68.870 219.505 68.890 ;
        RECT 0.610 68.050 219.230 68.870 ;
        RECT 0.100 68.030 219.505 68.050 ;
        RECT 0.610 67.210 219.230 68.030 ;
        RECT 0.100 67.190 219.505 67.210 ;
        RECT 0.610 66.370 219.230 67.190 ;
        RECT 0.100 66.350 219.505 66.370 ;
        RECT 0.610 65.530 219.230 66.350 ;
        RECT 0.100 65.510 219.505 65.530 ;
        RECT 0.610 64.690 219.230 65.510 ;
        RECT 0.100 64.670 219.505 64.690 ;
        RECT 0.610 63.850 219.230 64.670 ;
        RECT 0.100 63.830 219.505 63.850 ;
        RECT 0.610 63.010 219.230 63.830 ;
        RECT 0.100 62.990 219.505 63.010 ;
        RECT 0.610 62.170 219.230 62.990 ;
        RECT 0.100 62.150 219.505 62.170 ;
        RECT 0.610 61.330 219.230 62.150 ;
        RECT 0.100 61.310 219.505 61.330 ;
        RECT 0.610 60.490 219.230 61.310 ;
        RECT 0.100 60.470 219.505 60.490 ;
        RECT 0.610 59.650 219.230 60.470 ;
        RECT 0.100 59.630 219.505 59.650 ;
        RECT 0.610 58.810 219.230 59.630 ;
        RECT 0.100 58.790 219.505 58.810 ;
        RECT 0.610 57.970 219.230 58.790 ;
        RECT 0.100 57.950 219.505 57.970 ;
        RECT 0.610 57.130 219.230 57.950 ;
        RECT 0.100 57.110 219.505 57.130 ;
        RECT 0.610 56.290 219.230 57.110 ;
        RECT 0.100 56.270 219.505 56.290 ;
        RECT 0.610 55.450 219.230 56.270 ;
        RECT 0.100 55.430 219.505 55.450 ;
        RECT 0.610 54.610 219.230 55.430 ;
        RECT 0.100 54.590 219.505 54.610 ;
        RECT 0.610 53.770 219.230 54.590 ;
        RECT 0.100 53.750 219.505 53.770 ;
        RECT 0.610 52.930 219.230 53.750 ;
        RECT 0.100 52.910 219.505 52.930 ;
        RECT 0.610 52.090 219.230 52.910 ;
        RECT 0.100 52.070 219.505 52.090 ;
        RECT 0.610 51.250 219.230 52.070 ;
        RECT 0.100 51.230 219.505 51.250 ;
        RECT 0.610 50.410 219.230 51.230 ;
        RECT 0.100 50.390 219.505 50.410 ;
        RECT 0.610 49.570 219.230 50.390 ;
        RECT 0.100 49.550 219.505 49.570 ;
        RECT 0.610 48.730 219.230 49.550 ;
        RECT 0.100 48.710 219.505 48.730 ;
        RECT 0.610 47.890 219.230 48.710 ;
        RECT 0.100 47.870 219.505 47.890 ;
        RECT 0.610 47.050 219.505 47.870 ;
        RECT 0.100 47.030 219.505 47.050 ;
        RECT 0.610 46.210 219.505 47.030 ;
        RECT 0.100 46.190 219.505 46.210 ;
        RECT 0.610 45.370 219.505 46.190 ;
        RECT 0.100 45.350 219.505 45.370 ;
        RECT 0.610 44.530 219.505 45.350 ;
        RECT 0.100 44.510 219.505 44.530 ;
        RECT 0.610 43.690 219.505 44.510 ;
        RECT 0.100 43.670 219.505 43.690 ;
        RECT 0.610 42.850 219.505 43.670 ;
        RECT 0.100 42.830 219.505 42.850 ;
        RECT 0.610 42.010 219.505 42.830 ;
        RECT 0.100 41.990 219.505 42.010 ;
        RECT 0.610 41.170 219.505 41.990 ;
        RECT 0.100 41.150 219.505 41.170 ;
        RECT 0.610 40.330 219.505 41.150 ;
        RECT 0.100 40.310 219.505 40.330 ;
        RECT 0.610 39.490 219.505 40.310 ;
        RECT 0.100 39.470 219.505 39.490 ;
        RECT 0.610 38.650 219.505 39.470 ;
        RECT 0.100 38.630 219.505 38.650 ;
        RECT 0.610 37.810 219.505 38.630 ;
        RECT 0.100 37.790 219.505 37.810 ;
        RECT 0.610 36.970 219.505 37.790 ;
        RECT 0.100 36.950 219.505 36.970 ;
        RECT 0.610 36.130 219.505 36.950 ;
        RECT 0.100 36.110 219.505 36.130 ;
        RECT 0.610 35.290 219.505 36.110 ;
        RECT 0.100 35.270 219.505 35.290 ;
        RECT 0.610 34.450 219.505 35.270 ;
        RECT 0.100 34.430 219.505 34.450 ;
        RECT 0.610 33.610 219.505 34.430 ;
        RECT 0.100 33.590 219.505 33.610 ;
        RECT 0.610 32.770 219.505 33.590 ;
        RECT 0.100 32.750 219.505 32.770 ;
        RECT 0.610 31.930 219.505 32.750 ;
        RECT 0.100 31.910 219.505 31.930 ;
        RECT 0.610 31.090 219.505 31.910 ;
        RECT 0.100 31.070 219.505 31.090 ;
        RECT 0.610 30.250 219.505 31.070 ;
        RECT 0.100 30.230 219.505 30.250 ;
        RECT 0.610 29.410 219.505 30.230 ;
        RECT 0.100 29.390 219.505 29.410 ;
        RECT 0.610 28.570 219.505 29.390 ;
        RECT 0.100 28.550 219.505 28.570 ;
        RECT 0.610 27.730 219.505 28.550 ;
        RECT 0.100 27.710 219.505 27.730 ;
        RECT 0.610 26.890 219.505 27.710 ;
        RECT 0.100 26.870 219.505 26.890 ;
        RECT 0.610 26.050 219.505 26.870 ;
        RECT 0.100 26.030 219.505 26.050 ;
        RECT 0.610 25.210 219.505 26.030 ;
        RECT 0.100 25.190 219.505 25.210 ;
        RECT 0.610 24.370 219.505 25.190 ;
        RECT 0.100 24.350 219.505 24.370 ;
        RECT 0.610 23.530 219.505 24.350 ;
        RECT 0.100 23.510 219.505 23.530 ;
        RECT 0.610 22.690 219.505 23.510 ;
        RECT 0.100 22.670 219.505 22.690 ;
        RECT 0.610 21.850 219.505 22.670 ;
        RECT 0.100 21.830 219.505 21.850 ;
        RECT 0.610 21.010 219.505 21.830 ;
        RECT 0.100 20.990 219.505 21.010 ;
        RECT 0.610 20.170 219.505 20.990 ;
        RECT 0.100 20.150 219.505 20.170 ;
        RECT 0.610 19.330 219.505 20.150 ;
        RECT 0.100 19.310 219.505 19.330 ;
        RECT 0.610 18.490 219.505 19.310 ;
        RECT 0.100 18.470 219.505 18.490 ;
        RECT 0.610 17.650 219.505 18.470 ;
        RECT 0.100 17.630 219.505 17.650 ;
        RECT 0.610 16.810 219.505 17.630 ;
        RECT 0.100 16.790 219.505 16.810 ;
        RECT 0.610 15.970 219.505 16.790 ;
        RECT 0.100 15.950 219.505 15.970 ;
        RECT 0.610 15.130 219.505 15.950 ;
        RECT 0.100 15.110 219.505 15.130 ;
        RECT 0.610 14.290 219.505 15.110 ;
        RECT 0.100 14.270 219.505 14.290 ;
        RECT 0.610 13.450 219.505 14.270 ;
        RECT 0.100 0.320 219.505 13.450 ;
      LAYER Metal4 ;
        RECT 0.380 0.695 15.170 1216.045 ;
        RECT 17.790 0.695 21.370 1216.045 ;
        RECT 23.990 0.695 90.770 1216.045 ;
        RECT 93.390 0.695 96.970 1216.045 ;
        RECT 99.590 0.695 166.370 1216.045 ;
        RECT 168.990 0.695 172.570 1216.045 ;
        RECT 175.190 0.695 219.460 1216.045 ;
      LAYER TopMetal1 ;
        RECT 4.460 23.620 209.620 1094.580 ;
  END
END AXI_M_IO_W
END LIBRARY

